VERSION 5.8 ;
BUSBITCHARS "[]" ;
DIVIDERCHAR "/" ;
UNITS
    DATABASE MICRONS 1000 ;
END UNITS

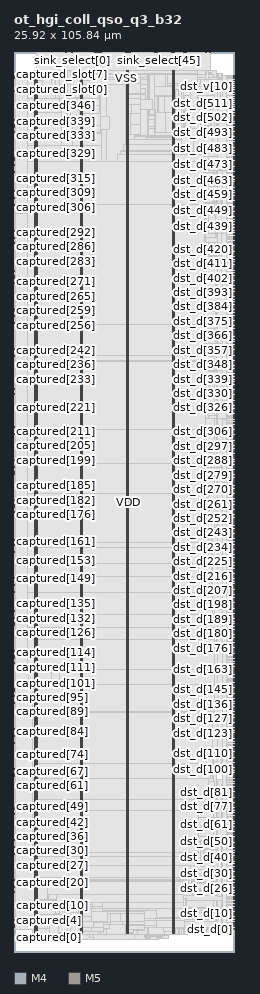
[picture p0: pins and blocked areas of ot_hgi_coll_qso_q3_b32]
MACRO ot_hgi_coll_qso_q3_b32
  FOREIGN ot_hgi_coll_qso_q3_b32 0 0 ;
  CLASS BLOCK ;
  SIZE 25.92 BY 105.84 ;
  PIN captured[0]
    DIRECTION INPUT ;
    USE SIGNAL ;
    PORT
      LAYER M4 ;
        RECT  0 2.64 0.084 2.664 ;
    END
  END captured[0]
  PIN captured[100]
    DIRECTION INPUT ;
    USE SIGNAL ;
    PORT
      LAYER M4 ;
        RECT  0 30.384 0.084 30.408 ;
    END
  END captured[100]
  PIN captured[101]
    DIRECTION INPUT ;
    USE SIGNAL ;
    PORT
      LAYER M4 ;
        RECT  0 30.672 0.084 30.696 ;
    END
  END captured[101]
  PIN captured[102]
    DIRECTION INPUT ;
    USE SIGNAL ;
    PORT
      LAYER M4 ;
        RECT  0 30.912 0.084 30.936 ;
    END
  END captured[102]
  PIN captured[103]
    DIRECTION INPUT ;
    USE SIGNAL ;
    PORT
      LAYER M4 ;
        RECT  0 31.2 0.084 31.224 ;
    END
  END captured[103]
  PIN captured[104]
    DIRECTION INPUT ;
    USE SIGNAL ;
    PORT
      LAYER M4 ;
        RECT  0 31.488 0.084 31.512 ;
    END
  END captured[104]
  PIN captured[105]
    DIRECTION INPUT ;
    USE SIGNAL ;
    PORT
      LAYER M4 ;
        RECT  0 31.776 0.084 31.8 ;
    END
  END captured[105]
  PIN captured[106]
    DIRECTION INPUT ;
    USE SIGNAL ;
    PORT
      LAYER M4 ;
        RECT  0 32.064 0.084 32.088 ;
    END
  END captured[106]
  PIN captured[107]
    DIRECTION INPUT ;
    USE SIGNAL ;
    PORT
      LAYER M4 ;
        RECT  0 32.304 0.084 32.328 ;
    END
  END captured[107]
  PIN captured[108]
    DIRECTION INPUT ;
    USE SIGNAL ;
    PORT
      LAYER M4 ;
        RECT  0 32.592 0.084 32.616 ;
    END
  END captured[108]
  PIN captured[109]
    DIRECTION INPUT ;
    USE SIGNAL ;
    PORT
      LAYER M4 ;
        RECT  0 32.88 0.084 32.904 ;
    END
  END captured[109]
  PIN captured[10]
    DIRECTION INPUT ;
    USE SIGNAL ;
    PORT
      LAYER M4 ;
        RECT  0 5.424 0.084 5.448 ;
    END
  END captured[10]
  PIN captured[110]
    DIRECTION INPUT ;
    USE SIGNAL ;
    PORT
      LAYER M4 ;
        RECT  0 33.168 0.084 33.192 ;
    END
  END captured[110]
  PIN captured[111]
    DIRECTION INPUT ;
    USE SIGNAL ;
    PORT
      LAYER M4 ;
        RECT  0 33.456 0.084 33.48 ;
    END
  END captured[111]
  PIN captured[112]
    DIRECTION INPUT ;
    USE SIGNAL ;
    PORT
      LAYER M4 ;
        RECT  0 33.696 0.084 33.72 ;
    END
  END captured[112]
  PIN captured[113]
    DIRECTION INPUT ;
    USE SIGNAL ;
    PORT
      LAYER M4 ;
        RECT  0 33.984 0.084 34.008 ;
    END
  END captured[113]
  PIN captured[114]
    DIRECTION INPUT ;
    USE SIGNAL ;
    PORT
      LAYER M4 ;
        RECT  0 34.272 0.084 34.296 ;
    END
  END captured[114]
  PIN captured[115]
    DIRECTION INPUT ;
    USE SIGNAL ;
    PORT
      LAYER M4 ;
        RECT  0 34.56 0.084 34.584 ;
    END
  END captured[115]
  PIN captured[116]
    DIRECTION INPUT ;
    USE SIGNAL ;
    PORT
      LAYER M4 ;
        RECT  0 34.8 0.084 34.824 ;
    END
  END captured[116]
  PIN captured[117]
    DIRECTION INPUT ;
    USE SIGNAL ;
    PORT
      LAYER M4 ;
        RECT  0 35.088 0.084 35.112 ;
    END
  END captured[117]
  PIN captured[118]
    DIRECTION INPUT ;
    USE SIGNAL ;
    PORT
      LAYER M4 ;
        RECT  0 35.376 0.084 35.4 ;
    END
  END captured[118]
  PIN captured[119]
    DIRECTION INPUT ;
    USE SIGNAL ;
    PORT
      LAYER M4 ;
        RECT  0 35.664 0.084 35.688 ;
    END
  END captured[119]
  PIN captured[11]
    DIRECTION INPUT ;
    USE SIGNAL ;
    PORT
      LAYER M4 ;
        RECT  0 5.664 0.084 5.688 ;
    END
  END captured[11]
  PIN captured[120]
    DIRECTION INPUT ;
    USE SIGNAL ;
    PORT
      LAYER M4 ;
        RECT  0 35.952 0.084 35.976 ;
    END
  END captured[120]
  PIN captured[121]
    DIRECTION INPUT ;
    USE SIGNAL ;
    PORT
      LAYER M4 ;
        RECT  0 36.192 0.084 36.216 ;
    END
  END captured[121]
  PIN captured[122]
    DIRECTION INPUT ;
    USE SIGNAL ;
    PORT
      LAYER M4 ;
        RECT  0 36.48 0.084 36.504 ;
    END
  END captured[122]
  PIN captured[123]
    DIRECTION INPUT ;
    USE SIGNAL ;
    PORT
      LAYER M4 ;
        RECT  0 36.768 0.084 36.792 ;
    END
  END captured[123]
  PIN captured[124]
    DIRECTION INPUT ;
    USE SIGNAL ;
    PORT
      LAYER M4 ;
        RECT  0 37.056 0.084 37.08 ;
    END
  END captured[124]
  PIN captured[125]
    DIRECTION INPUT ;
    USE SIGNAL ;
    PORT
      LAYER M4 ;
        RECT  0 37.296 0.084 37.32 ;
    END
  END captured[125]
  PIN captured[126]
    DIRECTION INPUT ;
    USE SIGNAL ;
    PORT
      LAYER M4 ;
        RECT  0 37.584 0.084 37.608 ;
    END
  END captured[126]
  PIN captured[127]
    DIRECTION INPUT ;
    USE SIGNAL ;
    PORT
      LAYER M4 ;
        RECT  0 37.872 0.084 37.896 ;
    END
  END captured[127]
  PIN captured[128]
    DIRECTION INPUT ;
    USE SIGNAL ;
    PORT
      LAYER M4 ;
        RECT  0 38.16 0.084 38.184 ;
    END
  END captured[128]
  PIN captured[129]
    DIRECTION INPUT ;
    USE SIGNAL ;
    PORT
      LAYER M4 ;
        RECT  0 38.448 0.084 38.472 ;
    END
  END captured[129]
  PIN captured[12]
    DIRECTION INPUT ;
    USE SIGNAL ;
    PORT
      LAYER M4 ;
        RECT  0 5.952 0.084 5.976 ;
    END
  END captured[12]
  PIN captured[130]
    DIRECTION INPUT ;
    USE SIGNAL ;
    PORT
      LAYER M4 ;
        RECT  0 38.688 0.084 38.712 ;
    END
  END captured[130]
  PIN captured[131]
    DIRECTION INPUT ;
    USE SIGNAL ;
    PORT
      LAYER M4 ;
        RECT  0 38.976 0.084 39 ;
    END
  END captured[131]
  PIN captured[132]
    DIRECTION INPUT ;
    USE SIGNAL ;
    PORT
      LAYER M4 ;
        RECT  0 39.264 0.084 39.288 ;
    END
  END captured[132]
  PIN captured[133]
    DIRECTION INPUT ;
    USE SIGNAL ;
    PORT
      LAYER M4 ;
        RECT  0 39.552 0.084 39.576 ;
    END
  END captured[133]
  PIN captured[134]
    DIRECTION INPUT ;
    USE SIGNAL ;
    PORT
      LAYER M4 ;
        RECT  0 39.84 0.084 39.864 ;
    END
  END captured[134]
  PIN captured[135]
    DIRECTION INPUT ;
    USE SIGNAL ;
    PORT
      LAYER M4 ;
        RECT  0 40.08 0.084 40.104 ;
    END
  END captured[135]
  PIN captured[136]
    DIRECTION INPUT ;
    USE SIGNAL ;
    PORT
      LAYER M4 ;
        RECT  0 40.368 0.084 40.392 ;
    END
  END captured[136]
  PIN captured[137]
    DIRECTION INPUT ;
    USE SIGNAL ;
    PORT
      LAYER M4 ;
        RECT  0 40.656 0.084 40.68 ;
    END
  END captured[137]
  PIN captured[138]
    DIRECTION INPUT ;
    USE SIGNAL ;
    PORT
      LAYER M4 ;
        RECT  0 40.944 0.084 40.968 ;
    END
  END captured[138]
  PIN captured[139]
    DIRECTION INPUT ;
    USE SIGNAL ;
    PORT
      LAYER M4 ;
        RECT  0 41.184 0.084 41.208 ;
    END
  END captured[139]
  PIN captured[13]
    DIRECTION INPUT ;
    USE SIGNAL ;
    PORT
      LAYER M4 ;
        RECT  0 6.24 0.084 6.264 ;
    END
  END captured[13]
  PIN captured[140]
    DIRECTION INPUT ;
    USE SIGNAL ;
    PORT
      LAYER M4 ;
        RECT  0 41.472 0.084 41.496 ;
    END
  END captured[140]
  PIN captured[141]
    DIRECTION INPUT ;
    USE SIGNAL ;
    PORT
      LAYER M4 ;
        RECT  0 41.76 0.084 41.784 ;
    END
  END captured[141]
  PIN captured[142]
    DIRECTION INPUT ;
    USE SIGNAL ;
    PORT
      LAYER M4 ;
        RECT  0 42.048 0.084 42.072 ;
    END
  END captured[142]
  PIN captured[143]
    DIRECTION INPUT ;
    USE SIGNAL ;
    PORT
      LAYER M4 ;
        RECT  0 42.336 0.084 42.36 ;
    END
  END captured[143]
  PIN captured[144]
    DIRECTION INPUT ;
    USE SIGNAL ;
    PORT
      LAYER M4 ;
        RECT  0 42.576 0.084 42.6 ;
    END
  END captured[144]
  PIN captured[145]
    DIRECTION INPUT ;
    USE SIGNAL ;
    PORT
      LAYER M4 ;
        RECT  0 42.864 0.084 42.888 ;
    END
  END captured[145]
  PIN captured[146]
    DIRECTION INPUT ;
    USE SIGNAL ;
    PORT
      LAYER M4 ;
        RECT  0 43.152 0.084 43.176 ;
    END
  END captured[146]
  PIN captured[147]
    DIRECTION INPUT ;
    USE SIGNAL ;
    PORT
      LAYER M4 ;
        RECT  0 43.44 0.084 43.464 ;
    END
  END captured[147]
  PIN captured[148]
    DIRECTION INPUT ;
    USE SIGNAL ;
    PORT
      LAYER M4 ;
        RECT  0 43.68 0.084 43.704 ;
    END
  END captured[148]
  PIN captured[149]
    DIRECTION INPUT ;
    USE SIGNAL ;
    PORT
      LAYER M4 ;
        RECT  0 43.968 0.084 43.992 ;
    END
  END captured[149]
  PIN captured[14]
    DIRECTION INPUT ;
    USE SIGNAL ;
    PORT
      LAYER M4 ;
        RECT  0 6.528 0.084 6.552 ;
    END
  END captured[14]
  PIN captured[150]
    DIRECTION INPUT ;
    USE SIGNAL ;
    PORT
      LAYER M4 ;
        RECT  0 44.256 0.084 44.28 ;
    END
  END captured[150]
  PIN captured[151]
    DIRECTION INPUT ;
    USE SIGNAL ;
    PORT
      LAYER M4 ;
        RECT  0 44.544 0.084 44.568 ;
    END
  END captured[151]
  PIN captured[152]
    DIRECTION INPUT ;
    USE SIGNAL ;
    PORT
      LAYER M4 ;
        RECT  0 44.832 0.084 44.856 ;
    END
  END captured[152]
  PIN captured[153]
    DIRECTION INPUT ;
    USE SIGNAL ;
    PORT
      LAYER M4 ;
        RECT  0 45.072 0.084 45.096 ;
    END
  END captured[153]
  PIN captured[154]
    DIRECTION INPUT ;
    USE SIGNAL ;
    PORT
      LAYER M4 ;
        RECT  0 45.36 0.084 45.384 ;
    END
  END captured[154]
  PIN captured[155]
    DIRECTION INPUT ;
    USE SIGNAL ;
    PORT
      LAYER M4 ;
        RECT  0 45.648 0.084 45.672 ;
    END
  END captured[155]
  PIN captured[156]
    DIRECTION INPUT ;
    USE SIGNAL ;
    PORT
      LAYER M4 ;
        RECT  0 45.936 0.084 45.96 ;
    END
  END captured[156]
  PIN captured[157]
    DIRECTION INPUT ;
    USE SIGNAL ;
    PORT
      LAYER M4 ;
        RECT  0 46.176 0.084 46.2 ;
    END
  END captured[157]
  PIN captured[158]
    DIRECTION INPUT ;
    USE SIGNAL ;
    PORT
      LAYER M4 ;
        RECT  0 46.464 0.084 46.488 ;
    END
  END captured[158]
  PIN captured[159]
    DIRECTION INPUT ;
    USE SIGNAL ;
    PORT
      LAYER M4 ;
        RECT  0 46.752 0.084 46.776 ;
    END
  END captured[159]
  PIN captured[15]
    DIRECTION INPUT ;
    USE SIGNAL ;
    PORT
      LAYER M4 ;
        RECT  0 6.768 0.084 6.792 ;
    END
  END captured[15]
  PIN captured[160]
    DIRECTION INPUT ;
    USE SIGNAL ;
    PORT
      LAYER M4 ;
        RECT  0 47.04 0.084 47.064 ;
    END
  END captured[160]
  PIN captured[161]
    DIRECTION INPUT ;
    USE SIGNAL ;
    PORT
      LAYER M4 ;
        RECT  0 47.328 0.084 47.352 ;
    END
  END captured[161]
  PIN captured[162]
    DIRECTION INPUT ;
    USE SIGNAL ;
    PORT
      LAYER M4 ;
        RECT  0 47.568 0.084 47.592 ;
    END
  END captured[162]
  PIN captured[163]
    DIRECTION INPUT ;
    USE SIGNAL ;
    PORT
      LAYER M4 ;
        RECT  0 47.856 0.084 47.88 ;
    END
  END captured[163]
  PIN captured[164]
    DIRECTION INPUT ;
    USE SIGNAL ;
    PORT
      LAYER M4 ;
        RECT  0 48.144 0.084 48.168 ;
    END
  END captured[164]
  PIN captured[165]
    DIRECTION INPUT ;
    USE SIGNAL ;
    PORT
      LAYER M4 ;
        RECT  0 48.432 0.084 48.456 ;
    END
  END captured[165]
  PIN captured[166]
    DIRECTION INPUT ;
    USE SIGNAL ;
    PORT
      LAYER M4 ;
        RECT  0 48.72 0.084 48.744 ;
    END
  END captured[166]
  PIN captured[167]
    DIRECTION INPUT ;
    USE SIGNAL ;
    PORT
      LAYER M4 ;
        RECT  0 48.96 0.084 48.984 ;
    END
  END captured[167]
  PIN captured[168]
    DIRECTION INPUT ;
    USE SIGNAL ;
    PORT
      LAYER M4 ;
        RECT  0 49.248 0.084 49.272 ;
    END
  END captured[168]
  PIN captured[169]
    DIRECTION INPUT ;
    USE SIGNAL ;
    PORT
      LAYER M4 ;
        RECT  0 49.536 0.084 49.56 ;
    END
  END captured[169]
  PIN captured[16]
    DIRECTION INPUT ;
    USE SIGNAL ;
    PORT
      LAYER M4 ;
        RECT  0 7.056 0.084 7.08 ;
    END
  END captured[16]
  PIN captured[170]
    DIRECTION INPUT ;
    USE SIGNAL ;
    PORT
      LAYER M4 ;
        RECT  0 49.824 0.084 49.848 ;
    END
  END captured[170]
  PIN captured[171]
    DIRECTION INPUT ;
    USE SIGNAL ;
    PORT
      LAYER M4 ;
        RECT  0 50.064 0.084 50.088 ;
    END
  END captured[171]
  PIN captured[172]
    DIRECTION INPUT ;
    USE SIGNAL ;
    PORT
      LAYER M4 ;
        RECT  0 50.352 0.084 50.376 ;
    END
  END captured[172]
  PIN captured[173]
    DIRECTION INPUT ;
    USE SIGNAL ;
    PORT
      LAYER M4 ;
        RECT  0 50.64 0.084 50.664 ;
    END
  END captured[173]
  PIN captured[174]
    DIRECTION INPUT ;
    USE SIGNAL ;
    PORT
      LAYER M4 ;
        RECT  0 50.928 0.084 50.952 ;
    END
  END captured[174]
  PIN captured[175]
    DIRECTION INPUT ;
    USE SIGNAL ;
    PORT
      LAYER M4 ;
        RECT  0 51.216 0.084 51.24 ;
    END
  END captured[175]
  PIN captured[176]
    DIRECTION INPUT ;
    USE SIGNAL ;
    PORT
      LAYER M4 ;
        RECT  0 51.456 0.084 51.48 ;
    END
  END captured[176]
  PIN captured[177]
    DIRECTION INPUT ;
    USE SIGNAL ;
    PORT
      LAYER M4 ;
        RECT  0 51.744 0.084 51.768 ;
    END
  END captured[177]
  PIN captured[178]
    DIRECTION INPUT ;
    USE SIGNAL ;
    PORT
      LAYER M4 ;
        RECT  0 52.032 0.084 52.056 ;
    END
  END captured[178]
  PIN captured[179]
    DIRECTION INPUT ;
    USE SIGNAL ;
    PORT
      LAYER M4 ;
        RECT  0 52.32 0.084 52.344 ;
    END
  END captured[179]
  PIN captured[17]
    DIRECTION INPUT ;
    USE SIGNAL ;
    PORT
      LAYER M4 ;
        RECT  0 7.344 0.084 7.368 ;
    END
  END captured[17]
  PIN captured[180]
    DIRECTION INPUT ;
    USE SIGNAL ;
    PORT
      LAYER M4 ;
        RECT  0 52.56 0.084 52.584 ;
    END
  END captured[180]
  PIN captured[181]
    DIRECTION INPUT ;
    USE SIGNAL ;
    PORT
      LAYER M4 ;
        RECT  0 52.848 0.084 52.872 ;
    END
  END captured[181]
  PIN captured[182]
    DIRECTION INPUT ;
    USE SIGNAL ;
    PORT
      LAYER M4 ;
        RECT  0 53.136 0.084 53.16 ;
    END
  END captured[182]
  PIN captured[183]
    DIRECTION INPUT ;
    USE SIGNAL ;
    PORT
      LAYER M4 ;
        RECT  0 53.424 0.084 53.448 ;
    END
  END captured[183]
  PIN captured[184]
    DIRECTION INPUT ;
    USE SIGNAL ;
    PORT
      LAYER M4 ;
        RECT  0 53.712 0.084 53.736 ;
    END
  END captured[184]
  PIN captured[185]
    DIRECTION INPUT ;
    USE SIGNAL ;
    PORT
      LAYER M4 ;
        RECT  0 53.952 0.084 53.976 ;
    END
  END captured[185]
  PIN captured[186]
    DIRECTION INPUT ;
    USE SIGNAL ;
    PORT
      LAYER M4 ;
        RECT  0 54.24 0.084 54.264 ;
    END
  END captured[186]
  PIN captured[187]
    DIRECTION INPUT ;
    USE SIGNAL ;
    PORT
      LAYER M4 ;
        RECT  0 54.528 0.084 54.552 ;
    END
  END captured[187]
  PIN captured[188]
    DIRECTION INPUT ;
    USE SIGNAL ;
    PORT
      LAYER M4 ;
        RECT  0 54.816 0.084 54.84 ;
    END
  END captured[188]
  PIN captured[189]
    DIRECTION INPUT ;
    USE SIGNAL ;
    PORT
      LAYER M4 ;
        RECT  0 55.104 0.084 55.128 ;
    END
  END captured[189]
  PIN captured[18]
    DIRECTION INPUT ;
    USE SIGNAL ;
    PORT
      LAYER M4 ;
        RECT  0 7.632 0.084 7.656 ;
    END
  END captured[18]
  PIN captured[190]
    DIRECTION INPUT ;
    USE SIGNAL ;
    PORT
      LAYER M4 ;
        RECT  0 55.344 0.084 55.368 ;
    END
  END captured[190]
  PIN captured[191]
    DIRECTION INPUT ;
    USE SIGNAL ;
    PORT
      LAYER M4 ;
        RECT  0 55.632 0.084 55.656 ;
    END
  END captured[191]
  PIN captured[192]
    DIRECTION INPUT ;
    USE SIGNAL ;
    PORT
      LAYER M4 ;
        RECT  0 55.92 0.084 55.944 ;
    END
  END captured[192]
  PIN captured[193]
    DIRECTION INPUT ;
    USE SIGNAL ;
    PORT
      LAYER M4 ;
        RECT  0 56.208 0.084 56.232 ;
    END
  END captured[193]
  PIN captured[194]
    DIRECTION INPUT ;
    USE SIGNAL ;
    PORT
      LAYER M4 ;
        RECT  0 56.448 0.084 56.472 ;
    END
  END captured[194]
  PIN captured[195]
    DIRECTION INPUT ;
    USE SIGNAL ;
    PORT
      LAYER M4 ;
        RECT  0 56.736 0.084 56.76 ;
    END
  END captured[195]
  PIN captured[196]
    DIRECTION INPUT ;
    USE SIGNAL ;
    PORT
      LAYER M4 ;
        RECT  0 57.024 0.084 57.048 ;
    END
  END captured[196]
  PIN captured[197]
    DIRECTION INPUT ;
    USE SIGNAL ;
    PORT
      LAYER M4 ;
        RECT  0 57.312 0.084 57.336 ;
    END
  END captured[197]
  PIN captured[198]
    DIRECTION INPUT ;
    USE SIGNAL ;
    PORT
      LAYER M4 ;
        RECT  0 57.6 0.084 57.624 ;
    END
  END captured[198]
  PIN captured[199]
    DIRECTION INPUT ;
    USE SIGNAL ;
    PORT
      LAYER M4 ;
        RECT  0 57.84 0.084 57.864 ;
    END
  END captured[199]
  PIN captured[19]
    DIRECTION INPUT ;
    USE SIGNAL ;
    PORT
      LAYER M4 ;
        RECT  0 7.92 0.084 7.944 ;
    END
  END captured[19]
  PIN captured[1]
    DIRECTION INPUT ;
    USE SIGNAL ;
    PORT
      LAYER M4 ;
        RECT  0 2.928 0.084 2.952 ;
    END
  END captured[1]
  PIN captured[200]
    DIRECTION INPUT ;
    USE SIGNAL ;
    PORT
      LAYER M4 ;
        RECT  0 58.128 0.084 58.152 ;
    END
  END captured[200]
  PIN captured[201]
    DIRECTION INPUT ;
    USE SIGNAL ;
    PORT
      LAYER M4 ;
        RECT  0 58.416 0.084 58.44 ;
    END
  END captured[201]
  PIN captured[202]
    DIRECTION INPUT ;
    USE SIGNAL ;
    PORT
      LAYER M4 ;
        RECT  0 58.704 0.084 58.728 ;
    END
  END captured[202]
  PIN captured[203]
    DIRECTION INPUT ;
    USE SIGNAL ;
    PORT
      LAYER M4 ;
        RECT  0 58.944 0.084 58.968 ;
    END
  END captured[203]
  PIN captured[204]
    DIRECTION INPUT ;
    USE SIGNAL ;
    PORT
      LAYER M4 ;
        RECT  0 59.232 0.084 59.256 ;
    END
  END captured[204]
  PIN captured[205]
    DIRECTION INPUT ;
    USE SIGNAL ;
    PORT
      LAYER M4 ;
        RECT  0 59.52 0.084 59.544 ;
    END
  END captured[205]
  PIN captured[206]
    DIRECTION INPUT ;
    USE SIGNAL ;
    PORT
      LAYER M4 ;
        RECT  0 59.808 0.084 59.832 ;
    END
  END captured[206]
  PIN captured[207]
    DIRECTION INPUT ;
    USE SIGNAL ;
    PORT
      LAYER M4 ;
        RECT  0 60.096 0.084 60.12 ;
    END
  END captured[207]
  PIN captured[208]
    DIRECTION INPUT ;
    USE SIGNAL ;
    PORT
      LAYER M4 ;
        RECT  0 60.336 0.084 60.36 ;
    END
  END captured[208]
  PIN captured[209]
    DIRECTION INPUT ;
    USE SIGNAL ;
    PORT
      LAYER M4 ;
        RECT  0 60.624 0.084 60.648 ;
    END
  END captured[209]
  PIN captured[20]
    DIRECTION INPUT ;
    USE SIGNAL ;
    PORT
      LAYER M4 ;
        RECT  0 8.16 0.084 8.184 ;
    END
  END captured[20]
  PIN captured[210]
    DIRECTION INPUT ;
    USE SIGNAL ;
    PORT
      LAYER M4 ;
        RECT  0 60.912 0.084 60.936 ;
    END
  END captured[210]
  PIN captured[211]
    DIRECTION INPUT ;
    USE SIGNAL ;
    PORT
      LAYER M4 ;
        RECT  0 61.2 0.084 61.224 ;
    END
  END captured[211]
  PIN captured[212]
    DIRECTION INPUT ;
    USE SIGNAL ;
    PORT
      LAYER M4 ;
        RECT  0 61.44 0.084 61.464 ;
    END
  END captured[212]
  PIN captured[213]
    DIRECTION INPUT ;
    USE SIGNAL ;
    PORT
      LAYER M4 ;
        RECT  0 61.728 0.084 61.752 ;
    END
  END captured[213]
  PIN captured[214]
    DIRECTION INPUT ;
    USE SIGNAL ;
    PORT
      LAYER M4 ;
        RECT  0 62.016 0.084 62.04 ;
    END
  END captured[214]
  PIN captured[215]
    DIRECTION INPUT ;
    USE SIGNAL ;
    PORT
      LAYER M4 ;
        RECT  0 62.304 0.084 62.328 ;
    END
  END captured[215]
  PIN captured[216]
    DIRECTION INPUT ;
    USE SIGNAL ;
    PORT
      LAYER M4 ;
        RECT  0 62.592 0.084 62.616 ;
    END
  END captured[216]
  PIN captured[217]
    DIRECTION INPUT ;
    USE SIGNAL ;
    PORT
      LAYER M4 ;
        RECT  0 62.832 0.084 62.856 ;
    END
  END captured[217]
  PIN captured[218]
    DIRECTION INPUT ;
    USE SIGNAL ;
    PORT
      LAYER M4 ;
        RECT  0 63.12 0.084 63.144 ;
    END
  END captured[218]
  PIN captured[219]
    DIRECTION INPUT ;
    USE SIGNAL ;
    PORT
      LAYER M4 ;
        RECT  0 63.408 0.084 63.432 ;
    END
  END captured[219]
  PIN captured[21]
    DIRECTION INPUT ;
    USE SIGNAL ;
    PORT
      LAYER M4 ;
        RECT  0 8.448 0.084 8.472 ;
    END
  END captured[21]
  PIN captured[220]
    DIRECTION INPUT ;
    USE SIGNAL ;
    PORT
      LAYER M4 ;
        RECT  0 63.696 0.084 63.72 ;
    END
  END captured[220]
  PIN captured[221]
    DIRECTION INPUT ;
    USE SIGNAL ;
    PORT
      LAYER M4 ;
        RECT  0 63.984 0.084 64.008 ;
    END
  END captured[221]
  PIN captured[222]
    DIRECTION INPUT ;
    USE SIGNAL ;
    PORT
      LAYER M4 ;
        RECT  0 64.224 0.084 64.248 ;
    END
  END captured[222]
  PIN captured[223]
    DIRECTION INPUT ;
    USE SIGNAL ;
    PORT
      LAYER M4 ;
        RECT  0 64.512 0.084 64.536 ;
    END
  END captured[223]
  PIN captured[224]
    DIRECTION INPUT ;
    USE SIGNAL ;
    PORT
      LAYER M4 ;
        RECT  0 64.8 0.084 64.824 ;
    END
  END captured[224]
  PIN captured[225]
    DIRECTION INPUT ;
    USE SIGNAL ;
    PORT
      LAYER M4 ;
        RECT  0 65.088 0.084 65.112 ;
    END
  END captured[225]
  PIN captured[226]
    DIRECTION INPUT ;
    USE SIGNAL ;
    PORT
      LAYER M4 ;
        RECT  0 65.328 0.084 65.352 ;
    END
  END captured[226]
  PIN captured[227]
    DIRECTION INPUT ;
    USE SIGNAL ;
    PORT
      LAYER M4 ;
        RECT  0 65.616 0.084 65.64 ;
    END
  END captured[227]
  PIN captured[228]
    DIRECTION INPUT ;
    USE SIGNAL ;
    PORT
      LAYER M4 ;
        RECT  0 65.904 0.084 65.928 ;
    END
  END captured[228]
  PIN captured[229]
    DIRECTION INPUT ;
    USE SIGNAL ;
    PORT
      LAYER M4 ;
        RECT  0 66.192 0.084 66.216 ;
    END
  END captured[229]
  PIN captured[22]
    DIRECTION INPUT ;
    USE SIGNAL ;
    PORT
      LAYER M4 ;
        RECT  0 8.736 0.084 8.76 ;
    END
  END captured[22]
  PIN captured[230]
    DIRECTION INPUT ;
    USE SIGNAL ;
    PORT
      LAYER M4 ;
        RECT  0 66.48 0.084 66.504 ;
    END
  END captured[230]
  PIN captured[231]
    DIRECTION INPUT ;
    USE SIGNAL ;
    PORT
      LAYER M4 ;
        RECT  0 66.72 0.084 66.744 ;
    END
  END captured[231]
  PIN captured[232]
    DIRECTION INPUT ;
    USE SIGNAL ;
    PORT
      LAYER M4 ;
        RECT  0 67.008 0.084 67.032 ;
    END
  END captured[232]
  PIN captured[233]
    DIRECTION INPUT ;
    USE SIGNAL ;
    PORT
      LAYER M4 ;
        RECT  0 67.296 0.084 67.32 ;
    END
  END captured[233]
  PIN captured[234]
    DIRECTION INPUT ;
    USE SIGNAL ;
    PORT
      LAYER M4 ;
        RECT  0 67.584 0.084 67.608 ;
    END
  END captured[234]
  PIN captured[235]
    DIRECTION INPUT ;
    USE SIGNAL ;
    PORT
      LAYER M4 ;
        RECT  0 67.824 0.084 67.848 ;
    END
  END captured[235]
  PIN captured[236]
    DIRECTION INPUT ;
    USE SIGNAL ;
    PORT
      LAYER M4 ;
        RECT  0 68.112 0.084 68.136 ;
    END
  END captured[236]
  PIN captured[237]
    DIRECTION INPUT ;
    USE SIGNAL ;
    PORT
      LAYER M4 ;
        RECT  0 68.4 0.084 68.424 ;
    END
  END captured[237]
  PIN captured[238]
    DIRECTION INPUT ;
    USE SIGNAL ;
    PORT
      LAYER M4 ;
        RECT  0 68.688 0.084 68.712 ;
    END
  END captured[238]
  PIN captured[239]
    DIRECTION INPUT ;
    USE SIGNAL ;
    PORT
      LAYER M4 ;
        RECT  0 68.976 0.084 69 ;
    END
  END captured[239]
  PIN captured[23]
    DIRECTION INPUT ;
    USE SIGNAL ;
    PORT
      LAYER M4 ;
        RECT  0 9.024 0.084 9.048 ;
    END
  END captured[23]
  PIN captured[240]
    DIRECTION INPUT ;
    USE SIGNAL ;
    PORT
      LAYER M4 ;
        RECT  0 69.216 0.084 69.24 ;
    END
  END captured[240]
  PIN captured[241]
    DIRECTION INPUT ;
    USE SIGNAL ;
    PORT
      LAYER M4 ;
        RECT  0 69.504 0.084 69.528 ;
    END
  END captured[241]
  PIN captured[242]
    DIRECTION INPUT ;
    USE SIGNAL ;
    PORT
      LAYER M4 ;
        RECT  0 69.792 0.084 69.816 ;
    END
  END captured[242]
  PIN captured[243]
    DIRECTION INPUT ;
    USE SIGNAL ;
    PORT
      LAYER M4 ;
        RECT  0 70.08 0.084 70.104 ;
    END
  END captured[243]
  PIN captured[244]
    DIRECTION INPUT ;
    USE SIGNAL ;
    PORT
      LAYER M4 ;
        RECT  0 70.368 0.084 70.392 ;
    END
  END captured[244]
  PIN captured[245]
    DIRECTION INPUT ;
    USE SIGNAL ;
    PORT
      LAYER M4 ;
        RECT  0 70.608 0.084 70.632 ;
    END
  END captured[245]
  PIN captured[246]
    DIRECTION INPUT ;
    USE SIGNAL ;
    PORT
      LAYER M4 ;
        RECT  0 70.896 0.084 70.92 ;
    END
  END captured[246]
  PIN captured[247]
    DIRECTION INPUT ;
    USE SIGNAL ;
    PORT
      LAYER M4 ;
        RECT  0 71.184 0.084 71.208 ;
    END
  END captured[247]
  PIN captured[248]
    DIRECTION INPUT ;
    USE SIGNAL ;
    PORT
      LAYER M4 ;
        RECT  0 71.472 0.084 71.496 ;
    END
  END captured[248]
  PIN captured[249]
    DIRECTION INPUT ;
    USE SIGNAL ;
    PORT
      LAYER M4 ;
        RECT  0 71.712 0.084 71.736 ;
    END
  END captured[249]
  PIN captured[24]
    DIRECTION INPUT ;
    USE SIGNAL ;
    PORT
      LAYER M4 ;
        RECT  0 9.264 0.084 9.288 ;
    END
  END captured[24]
  PIN captured[250]
    DIRECTION INPUT ;
    USE SIGNAL ;
    PORT
      LAYER M4 ;
        RECT  0 72 0.084 72.024 ;
    END
  END captured[250]
  PIN captured[251]
    DIRECTION INPUT ;
    USE SIGNAL ;
    PORT
      LAYER M4 ;
        RECT  0 72.288 0.084 72.312 ;
    END
  END captured[251]
  PIN captured[252]
    DIRECTION INPUT ;
    USE SIGNAL ;
    PORT
      LAYER M4 ;
        RECT  0 72.576 0.084 72.6 ;
    END
  END captured[252]
  PIN captured[253]
    DIRECTION INPUT ;
    USE SIGNAL ;
    PORT
      LAYER M4 ;
        RECT  0 72.864 0.084 72.888 ;
    END
  END captured[253]
  PIN captured[254]
    DIRECTION INPUT ;
    USE SIGNAL ;
    PORT
      LAYER M4 ;
        RECT  0 73.104 0.084 73.128 ;
    END
  END captured[254]
  PIN captured[255]
    DIRECTION INPUT ;
    USE SIGNAL ;
    PORT
      LAYER M4 ;
        RECT  0 73.392 0.084 73.416 ;
    END
  END captured[255]
  PIN captured[256]
    DIRECTION INPUT ;
    USE SIGNAL ;
    PORT
      LAYER M4 ;
        RECT  0 73.68 0.084 73.704 ;
    END
  END captured[256]
  PIN captured[257]
    DIRECTION INPUT ;
    USE SIGNAL ;
    PORT
      LAYER M4 ;
        RECT  0 73.968 0.084 73.992 ;
    END
  END captured[257]
  PIN captured[258]
    DIRECTION INPUT ;
    USE SIGNAL ;
    PORT
      LAYER M4 ;
        RECT  0 74.208 0.084 74.232 ;
    END
  END captured[258]
  PIN captured[259]
    DIRECTION INPUT ;
    USE SIGNAL ;
    PORT
      LAYER M4 ;
        RECT  0 74.496 0.084 74.52 ;
    END
  END captured[259]
  PIN captured[25]
    DIRECTION INPUT ;
    USE SIGNAL ;
    PORT
      LAYER M4 ;
        RECT  0 9.552 0.084 9.576 ;
    END
  END captured[25]
  PIN captured[260]
    DIRECTION INPUT ;
    USE SIGNAL ;
    PORT
      LAYER M4 ;
        RECT  0 74.784 0.084 74.808 ;
    END
  END captured[260]
  PIN captured[261]
    DIRECTION INPUT ;
    USE SIGNAL ;
    PORT
      LAYER M4 ;
        RECT  0 75.072 0.084 75.096 ;
    END
  END captured[261]
  PIN captured[262]
    DIRECTION INPUT ;
    USE SIGNAL ;
    PORT
      LAYER M4 ;
        RECT  0 75.36 0.084 75.384 ;
    END
  END captured[262]
  PIN captured[263]
    DIRECTION INPUT ;
    USE SIGNAL ;
    PORT
      LAYER M4 ;
        RECT  0 75.6 0.084 75.624 ;
    END
  END captured[263]
  PIN captured[264]
    DIRECTION INPUT ;
    USE SIGNAL ;
    PORT
      LAYER M4 ;
        RECT  0 75.888 0.084 75.912 ;
    END
  END captured[264]
  PIN captured[265]
    DIRECTION INPUT ;
    USE SIGNAL ;
    PORT
      LAYER M4 ;
        RECT  0 76.176 0.084 76.2 ;
    END
  END captured[265]
  PIN captured[266]
    DIRECTION INPUT ;
    USE SIGNAL ;
    PORT
      LAYER M4 ;
        RECT  0 76.464 0.084 76.488 ;
    END
  END captured[266]
  PIN captured[267]
    DIRECTION INPUT ;
    USE SIGNAL ;
    PORT
      LAYER M4 ;
        RECT  0 76.704 0.084 76.728 ;
    END
  END captured[267]
  PIN captured[268]
    DIRECTION INPUT ;
    USE SIGNAL ;
    PORT
      LAYER M4 ;
        RECT  0 76.992 0.084 77.016 ;
    END
  END captured[268]
  PIN captured[269]
    DIRECTION INPUT ;
    USE SIGNAL ;
    PORT
      LAYER M4 ;
        RECT  0 77.28 0.084 77.304 ;
    END
  END captured[269]
  PIN captured[26]
    DIRECTION INPUT ;
    USE SIGNAL ;
    PORT
      LAYER M4 ;
        RECT  0 9.84 0.084 9.864 ;
    END
  END captured[26]
  PIN captured[270]
    DIRECTION INPUT ;
    USE SIGNAL ;
    PORT
      LAYER M4 ;
        RECT  0 77.568 0.084 77.592 ;
    END
  END captured[270]
  PIN captured[271]
    DIRECTION INPUT ;
    USE SIGNAL ;
    PORT
      LAYER M4 ;
        RECT  0 77.856 0.084 77.88 ;
    END
  END captured[271]
  PIN captured[272]
    DIRECTION INPUT ;
    USE SIGNAL ;
    PORT
      LAYER M4 ;
        RECT  0 78.096 0.084 78.12 ;
    END
  END captured[272]
  PIN captured[273]
    DIRECTION INPUT ;
    USE SIGNAL ;
    PORT
      LAYER M4 ;
        RECT  0 78.384 0.084 78.408 ;
    END
  END captured[273]
  PIN captured[274]
    DIRECTION INPUT ;
    USE SIGNAL ;
    PORT
      LAYER M4 ;
        RECT  0 78.672 0.084 78.696 ;
    END
  END captured[274]
  PIN captured[275]
    DIRECTION INPUT ;
    USE SIGNAL ;
    PORT
      LAYER M4 ;
        RECT  0 78.96 0.084 78.984 ;
    END
  END captured[275]
  PIN captured[276]
    DIRECTION INPUT ;
    USE SIGNAL ;
    PORT
      LAYER M4 ;
        RECT  0 79.248 0.084 79.272 ;
    END
  END captured[276]
  PIN captured[277]
    DIRECTION INPUT ;
    USE SIGNAL ;
    PORT
      LAYER M4 ;
        RECT  0 79.488 0.084 79.512 ;
    END
  END captured[277]
  PIN captured[278]
    DIRECTION INPUT ;
    USE SIGNAL ;
    PORT
      LAYER M4 ;
        RECT  0 79.776 0.084 79.8 ;
    END
  END captured[278]
  PIN captured[279]
    DIRECTION INPUT ;
    USE SIGNAL ;
    PORT
      LAYER M4 ;
        RECT  0 80.064 0.084 80.088 ;
    END
  END captured[279]
  PIN captured[27]
    DIRECTION INPUT ;
    USE SIGNAL ;
    PORT
      LAYER M4 ;
        RECT  0 10.128 0.084 10.152 ;
    END
  END captured[27]
  PIN captured[280]
    DIRECTION INPUT ;
    USE SIGNAL ;
    PORT
      LAYER M4 ;
        RECT  0 80.352 0.084 80.376 ;
    END
  END captured[280]
  PIN captured[281]
    DIRECTION INPUT ;
    USE SIGNAL ;
    PORT
      LAYER M4 ;
        RECT  0 80.592 0.084 80.616 ;
    END
  END captured[281]
  PIN captured[282]
    DIRECTION INPUT ;
    USE SIGNAL ;
    PORT
      LAYER M4 ;
        RECT  0 80.88 0.084 80.904 ;
    END
  END captured[282]
  PIN captured[283]
    DIRECTION INPUT ;
    USE SIGNAL ;
    PORT
      LAYER M4 ;
        RECT  0 81.168 0.084 81.192 ;
    END
  END captured[283]
  PIN captured[284]
    DIRECTION INPUT ;
    USE SIGNAL ;
    PORT
      LAYER M4 ;
        RECT  0 81.456 0.084 81.48 ;
    END
  END captured[284]
  PIN captured[285]
    DIRECTION INPUT ;
    USE SIGNAL ;
    PORT
      LAYER M4 ;
        RECT  0 81.744 0.084 81.768 ;
    END
  END captured[285]
  PIN captured[286]
    DIRECTION INPUT ;
    USE SIGNAL ;
    PORT
      LAYER M4 ;
        RECT  0 81.984 0.084 82.008 ;
    END
  END captured[286]
  PIN captured[287]
    DIRECTION INPUT ;
    USE SIGNAL ;
    PORT
      LAYER M4 ;
        RECT  0 82.272 0.084 82.296 ;
    END
  END captured[287]
  PIN captured[288]
    DIRECTION INPUT ;
    USE SIGNAL ;
    PORT
      LAYER M4 ;
        RECT  0 82.56 0.084 82.584 ;
    END
  END captured[288]
  PIN captured[289]
    DIRECTION INPUT ;
    USE SIGNAL ;
    PORT
      LAYER M4 ;
        RECT  0 82.848 0.084 82.872 ;
    END
  END captured[289]
  PIN captured[28]
    DIRECTION INPUT ;
    USE SIGNAL ;
    PORT
      LAYER M4 ;
        RECT  0 10.416 0.084 10.44 ;
    END
  END captured[28]
  PIN captured[290]
    DIRECTION INPUT ;
    USE SIGNAL ;
    PORT
      LAYER M4 ;
        RECT  0 83.088 0.084 83.112 ;
    END
  END captured[290]
  PIN captured[291]
    DIRECTION INPUT ;
    USE SIGNAL ;
    PORT
      LAYER M4 ;
        RECT  0 83.376 0.084 83.4 ;
    END
  END captured[291]
  PIN captured[292]
    DIRECTION INPUT ;
    USE SIGNAL ;
    PORT
      LAYER M4 ;
        RECT  0 83.664 0.084 83.688 ;
    END
  END captured[292]
  PIN captured[293]
    DIRECTION INPUT ;
    USE SIGNAL ;
    PORT
      LAYER M4 ;
        RECT  0 83.952 0.084 83.976 ;
    END
  END captured[293]
  PIN captured[294]
    DIRECTION INPUT ;
    USE SIGNAL ;
    PORT
      LAYER M4 ;
        RECT  0 84.24 0.084 84.264 ;
    END
  END captured[294]
  PIN captured[295]
    DIRECTION INPUT ;
    USE SIGNAL ;
    PORT
      LAYER M4 ;
        RECT  0 84.48 0.084 84.504 ;
    END
  END captured[295]
  PIN captured[296]
    DIRECTION INPUT ;
    USE SIGNAL ;
    PORT
      LAYER M4 ;
        RECT  0 84.768 0.084 84.792 ;
    END
  END captured[296]
  PIN captured[297]
    DIRECTION INPUT ;
    USE SIGNAL ;
    PORT
      LAYER M4 ;
        RECT  0 85.056 0.084 85.08 ;
    END
  END captured[297]
  PIN captured[298]
    DIRECTION INPUT ;
    USE SIGNAL ;
    PORT
      LAYER M4 ;
        RECT  0 85.344 0.084 85.368 ;
    END
  END captured[298]
  PIN captured[299]
    DIRECTION INPUT ;
    USE SIGNAL ;
    PORT
      LAYER M4 ;
        RECT  0 85.632 0.084 85.656 ;
    END
  END captured[299]
  PIN captured[29]
    DIRECTION INPUT ;
    USE SIGNAL ;
    PORT
      LAYER M4 ;
        RECT  0 10.656 0.084 10.68 ;
    END
  END captured[29]
  PIN captured[2]
    DIRECTION INPUT ;
    USE SIGNAL ;
    PORT
      LAYER M4 ;
        RECT  0 3.168 0.084 3.192 ;
    END
  END captured[2]
  PIN captured[300]
    DIRECTION INPUT ;
    USE SIGNAL ;
    PORT
      LAYER M4 ;
        RECT  0 85.872 0.084 85.896 ;
    END
  END captured[300]
  PIN captured[301]
    DIRECTION INPUT ;
    USE SIGNAL ;
    PORT
      LAYER M4 ;
        RECT  0 86.16 0.084 86.184 ;
    END
  END captured[301]
  PIN captured[302]
    DIRECTION INPUT ;
    USE SIGNAL ;
    PORT
      LAYER M4 ;
        RECT  0 86.448 0.084 86.472 ;
    END
  END captured[302]
  PIN captured[303]
    DIRECTION INPUT ;
    USE SIGNAL ;
    PORT
      LAYER M4 ;
        RECT  0 86.736 0.084 86.76 ;
    END
  END captured[303]
  PIN captured[304]
    DIRECTION INPUT ;
    USE SIGNAL ;
    PORT
      LAYER M4 ;
        RECT  0 86.976 0.084 87 ;
    END
  END captured[304]
  PIN captured[305]
    DIRECTION INPUT ;
    USE SIGNAL ;
    PORT
      LAYER M4 ;
        RECT  0 87.264 0.084 87.288 ;
    END
  END captured[305]
  PIN captured[306]
    DIRECTION INPUT ;
    USE SIGNAL ;
    PORT
      LAYER M4 ;
        RECT  0 87.552 0.084 87.576 ;
    END
  END captured[306]
  PIN captured[307]
    DIRECTION INPUT ;
    USE SIGNAL ;
    PORT
      LAYER M4 ;
        RECT  0 87.84 0.084 87.864 ;
    END
  END captured[307]
  PIN captured[308]
    DIRECTION INPUT ;
    USE SIGNAL ;
    PORT
      LAYER M4 ;
        RECT  0 88.128 0.084 88.152 ;
    END
  END captured[308]
  PIN captured[309]
    DIRECTION INPUT ;
    USE SIGNAL ;
    PORT
      LAYER M4 ;
        RECT  0 88.368 0.084 88.392 ;
    END
  END captured[309]
  PIN captured[30]
    DIRECTION INPUT ;
    USE SIGNAL ;
    PORT
      LAYER M4 ;
        RECT  0 10.944 0.084 10.968 ;
    END
  END captured[30]
  PIN captured[310]
    DIRECTION INPUT ;
    USE SIGNAL ;
    PORT
      LAYER M4 ;
        RECT  0 88.656 0.084 88.68 ;
    END
  END captured[310]
  PIN captured[311]
    DIRECTION INPUT ;
    USE SIGNAL ;
    PORT
      LAYER M4 ;
        RECT  0 88.944 0.084 88.968 ;
    END
  END captured[311]
  PIN captured[312]
    DIRECTION INPUT ;
    USE SIGNAL ;
    PORT
      LAYER M4 ;
        RECT  0 89.232 0.084 89.256 ;
    END
  END captured[312]
  PIN captured[313]
    DIRECTION INPUT ;
    USE SIGNAL ;
    PORT
      LAYER M4 ;
        RECT  0 89.472 0.084 89.496 ;
    END
  END captured[313]
  PIN captured[314]
    DIRECTION INPUT ;
    USE SIGNAL ;
    PORT
      LAYER M4 ;
        RECT  0 89.76 0.084 89.784 ;
    END
  END captured[314]
  PIN captured[315]
    DIRECTION INPUT ;
    USE SIGNAL ;
    PORT
      LAYER M4 ;
        RECT  0 90.048 0.084 90.072 ;
    END
  END captured[315]
  PIN captured[316]
    DIRECTION INPUT ;
    USE SIGNAL ;
    PORT
      LAYER M4 ;
        RECT  0 90.336 0.084 90.36 ;
    END
  END captured[316]
  PIN captured[317]
    DIRECTION INPUT ;
    USE SIGNAL ;
    PORT
      LAYER M4 ;
        RECT  0 90.624 0.084 90.648 ;
    END
  END captured[317]
  PIN captured[318]
    DIRECTION INPUT ;
    USE SIGNAL ;
    PORT
      LAYER M4 ;
        RECT  0 90.864 0.084 90.888 ;
    END
  END captured[318]
  PIN captured[319]
    DIRECTION INPUT ;
    USE SIGNAL ;
    PORT
      LAYER M4 ;
        RECT  0 91.152 0.084 91.176 ;
    END
  END captured[319]
  PIN captured[31]
    DIRECTION INPUT ;
    USE SIGNAL ;
    PORT
      LAYER M4 ;
        RECT  0 11.232 0.084 11.256 ;
    END
  END captured[31]
  PIN captured[320]
    DIRECTION INPUT ;
    USE SIGNAL ;
    PORT
      LAYER M4 ;
        RECT  0 91.44 0.084 91.464 ;
    END
  END captured[320]
  PIN captured[321]
    DIRECTION INPUT ;
    USE SIGNAL ;
    PORT
      LAYER M4 ;
        RECT  0 91.728 0.084 91.752 ;
    END
  END captured[321]
  PIN captured[322]
    DIRECTION INPUT ;
    USE SIGNAL ;
    PORT
      LAYER M4 ;
        RECT  0 91.968 0.084 91.992 ;
    END
  END captured[322]
  PIN captured[323]
    DIRECTION INPUT ;
    USE SIGNAL ;
    PORT
      LAYER M4 ;
        RECT  0 92.256 0.084 92.28 ;
    END
  END captured[323]
  PIN captured[324]
    DIRECTION INPUT ;
    USE SIGNAL ;
    PORT
      LAYER M4 ;
        RECT  0 92.544 0.084 92.568 ;
    END
  END captured[324]
  PIN captured[325]
    DIRECTION INPUT ;
    USE SIGNAL ;
    PORT
      LAYER M4 ;
        RECT  0 92.832 0.084 92.856 ;
    END
  END captured[325]
  PIN captured[326]
    DIRECTION INPUT ;
    USE SIGNAL ;
    PORT
      LAYER M4 ;
        RECT  0 93.12 0.084 93.144 ;
    END
  END captured[326]
  PIN captured[327]
    DIRECTION INPUT ;
    USE SIGNAL ;
    PORT
      LAYER M4 ;
        RECT  0 93.36 0.084 93.384 ;
    END
  END captured[327]
  PIN captured[328]
    DIRECTION INPUT ;
    USE SIGNAL ;
    PORT
      LAYER M4 ;
        RECT  0 93.648 0.084 93.672 ;
    END
  END captured[328]
  PIN captured[329]
    DIRECTION INPUT ;
    USE SIGNAL ;
    PORT
      LAYER M4 ;
        RECT  0 93.936 0.084 93.96 ;
    END
  END captured[329]
  PIN captured[32]
    DIRECTION INPUT ;
    USE SIGNAL ;
    PORT
      LAYER M4 ;
        RECT  0 11.52 0.084 11.544 ;
    END
  END captured[32]
  PIN captured[330]
    DIRECTION INPUT ;
    USE SIGNAL ;
    PORT
      LAYER M4 ;
        RECT  0 94.224 0.084 94.248 ;
    END
  END captured[330]
  PIN captured[331]
    DIRECTION INPUT ;
    USE SIGNAL ;
    PORT
      LAYER M4 ;
        RECT  0 94.512 0.084 94.536 ;
    END
  END captured[331]
  PIN captured[332]
    DIRECTION INPUT ;
    USE SIGNAL ;
    PORT
      LAYER M4 ;
        RECT  0 94.752 0.084 94.776 ;
    END
  END captured[332]
  PIN captured[333]
    DIRECTION INPUT ;
    USE SIGNAL ;
    PORT
      LAYER M4 ;
        RECT  0 95.04 0.084 95.064 ;
    END
  END captured[333]
  PIN captured[334]
    DIRECTION INPUT ;
    USE SIGNAL ;
    PORT
      LAYER M4 ;
        RECT  0 95.328 0.084 95.352 ;
    END
  END captured[334]
  PIN captured[335]
    DIRECTION INPUT ;
    USE SIGNAL ;
    PORT
      LAYER M4 ;
        RECT  0 95.616 0.084 95.64 ;
    END
  END captured[335]
  PIN captured[336]
    DIRECTION INPUT ;
    USE SIGNAL ;
    PORT
      LAYER M4 ;
        RECT  0 95.856 0.084 95.88 ;
    END
  END captured[336]
  PIN captured[337]
    DIRECTION INPUT ;
    USE SIGNAL ;
    PORT
      LAYER M4 ;
        RECT  0 96.144 0.084 96.168 ;
    END
  END captured[337]
  PIN captured[338]
    DIRECTION INPUT ;
    USE SIGNAL ;
    PORT
      LAYER M4 ;
        RECT  0 96.432 0.084 96.456 ;
    END
  END captured[338]
  PIN captured[339]
    DIRECTION INPUT ;
    USE SIGNAL ;
    PORT
      LAYER M4 ;
        RECT  0 96.72 0.084 96.744 ;
    END
  END captured[339]
  PIN captured[33]
    DIRECTION INPUT ;
    USE SIGNAL ;
    PORT
      LAYER M4 ;
        RECT  0 11.808 0.084 11.832 ;
    END
  END captured[33]
  PIN captured[340]
    DIRECTION INPUT ;
    USE SIGNAL ;
    PORT
      LAYER M4 ;
        RECT  0 97.008 0.084 97.032 ;
    END
  END captured[340]
  PIN captured[341]
    DIRECTION INPUT ;
    USE SIGNAL ;
    PORT
      LAYER M4 ;
        RECT  0 97.248 0.084 97.272 ;
    END
  END captured[341]
  PIN captured[342]
    DIRECTION INPUT ;
    USE SIGNAL ;
    PORT
      LAYER M4 ;
        RECT  0 97.536 0.084 97.56 ;
    END
  END captured[342]
  PIN captured[343]
    DIRECTION INPUT ;
    USE SIGNAL ;
    PORT
      LAYER M4 ;
        RECT  0 97.824 0.084 97.848 ;
    END
  END captured[343]
  PIN captured[344]
    DIRECTION INPUT ;
    USE SIGNAL ;
    PORT
      LAYER M4 ;
        RECT  0 98.112 0.084 98.136 ;
    END
  END captured[344]
  PIN captured[345]
    DIRECTION INPUT ;
    USE SIGNAL ;
    PORT
      LAYER M4 ;
        RECT  0 98.352 0.084 98.376 ;
    END
  END captured[345]
  PIN captured[346]
    DIRECTION INPUT ;
    USE SIGNAL ;
    PORT
      LAYER M4 ;
        RECT  0 98.64 0.084 98.664 ;
    END
  END captured[346]
  PIN captured[347]
    DIRECTION INPUT ;
    USE SIGNAL ;
    PORT
      LAYER M4 ;
        RECT  0 98.928 0.084 98.952 ;
    END
  END captured[347]
  PIN captured[348]
    DIRECTION INPUT ;
    USE SIGNAL ;
    PORT
      LAYER M4 ;
        RECT  0 99.216 0.084 99.24 ;
    END
  END captured[348]
  PIN captured[349]
    DIRECTION INPUT ;
    USE SIGNAL ;
    PORT
      LAYER M4 ;
        RECT  0 99.504 0.084 99.528 ;
    END
  END captured[349]
  PIN captured[34]
    DIRECTION INPUT ;
    USE SIGNAL ;
    PORT
      LAYER M4 ;
        RECT  0 12.048 0.084 12.072 ;
    END
  END captured[34]
  PIN captured[350]
    DIRECTION INPUT ;
    USE SIGNAL ;
    PORT
      LAYER M4 ;
        RECT  0 99.744 0.084 99.768 ;
    END
  END captured[350]
  PIN captured[351]
    DIRECTION INPUT ;
    USE SIGNAL ;
    PORT
      LAYER M4 ;
        RECT  0 100.032 0.084 100.056 ;
    END
  END captured[351]
  PIN captured[35]
    DIRECTION INPUT ;
    USE SIGNAL ;
    PORT
      LAYER M4 ;
        RECT  0 12.336 0.084 12.36 ;
    END
  END captured[35]
  PIN captured[36]
    DIRECTION INPUT ;
    USE SIGNAL ;
    PORT
      LAYER M4 ;
        RECT  0 12.624 0.084 12.648 ;
    END
  END captured[36]
  PIN captured[37]
    DIRECTION INPUT ;
    USE SIGNAL ;
    PORT
      LAYER M4 ;
        RECT  0 12.912 0.084 12.936 ;
    END
  END captured[37]
  PIN captured[38]
    DIRECTION INPUT ;
    USE SIGNAL ;
    PORT
      LAYER M4 ;
        RECT  0 13.152 0.084 13.176 ;
    END
  END captured[38]
  PIN captured[39]
    DIRECTION INPUT ;
    USE SIGNAL ;
    PORT
      LAYER M4 ;
        RECT  0 13.44 0.084 13.464 ;
    END
  END captured[39]
  PIN captured[3]
    DIRECTION INPUT ;
    USE SIGNAL ;
    PORT
      LAYER M4 ;
        RECT  0 3.456 0.084 3.48 ;
    END
  END captured[3]
  PIN captured[40]
    DIRECTION INPUT ;
    USE SIGNAL ;
    PORT
      LAYER M4 ;
        RECT  0 13.728 0.084 13.752 ;
    END
  END captured[40]
  PIN captured[41]
    DIRECTION INPUT ;
    USE SIGNAL ;
    PORT
      LAYER M4 ;
        RECT  0 14.016 0.084 14.04 ;
    END
  END captured[41]
  PIN captured[42]
    DIRECTION INPUT ;
    USE SIGNAL ;
    PORT
      LAYER M4 ;
        RECT  0 14.304 0.084 14.328 ;
    END
  END captured[42]
  PIN captured[43]
    DIRECTION INPUT ;
    USE SIGNAL ;
    PORT
      LAYER M4 ;
        RECT  0 14.544 0.084 14.568 ;
    END
  END captured[43]
  PIN captured[44]
    DIRECTION INPUT ;
    USE SIGNAL ;
    PORT
      LAYER M4 ;
        RECT  0 14.832 0.084 14.856 ;
    END
  END captured[44]
  PIN captured[45]
    DIRECTION INPUT ;
    USE SIGNAL ;
    PORT
      LAYER M4 ;
        RECT  0 15.12 0.084 15.144 ;
    END
  END captured[45]
  PIN captured[46]
    DIRECTION INPUT ;
    USE SIGNAL ;
    PORT
      LAYER M4 ;
        RECT  0 15.408 0.084 15.432 ;
    END
  END captured[46]
  PIN captured[47]
    DIRECTION INPUT ;
    USE SIGNAL ;
    PORT
      LAYER M4 ;
        RECT  0 15.648 0.084 15.672 ;
    END
  END captured[47]
  PIN captured[48]
    DIRECTION INPUT ;
    USE SIGNAL ;
    PORT
      LAYER M4 ;
        RECT  0 15.936 0.084 15.96 ;
    END
  END captured[48]
  PIN captured[49]
    DIRECTION INPUT ;
    USE SIGNAL ;
    PORT
      LAYER M4 ;
        RECT  0 16.224 0.084 16.248 ;
    END
  END captured[49]
  PIN captured[4]
    DIRECTION INPUT ;
    USE SIGNAL ;
    PORT
      LAYER M4 ;
        RECT  0 3.744 0.084 3.768 ;
    END
  END captured[4]
  PIN captured[50]
    DIRECTION INPUT ;
    USE SIGNAL ;
    PORT
      LAYER M4 ;
        RECT  0 16.512 0.084 16.536 ;
    END
  END captured[50]
  PIN captured[51]
    DIRECTION INPUT ;
    USE SIGNAL ;
    PORT
      LAYER M4 ;
        RECT  0 16.8 0.084 16.824 ;
    END
  END captured[51]
  PIN captured[52]
    DIRECTION INPUT ;
    USE SIGNAL ;
    PORT
      LAYER M4 ;
        RECT  0 17.04 0.084 17.064 ;
    END
  END captured[52]
  PIN captured[53]
    DIRECTION INPUT ;
    USE SIGNAL ;
    PORT
      LAYER M4 ;
        RECT  0 17.328 0.084 17.352 ;
    END
  END captured[53]
  PIN captured[54]
    DIRECTION INPUT ;
    USE SIGNAL ;
    PORT
      LAYER M4 ;
        RECT  0 17.616 0.084 17.64 ;
    END
  END captured[54]
  PIN captured[55]
    DIRECTION INPUT ;
    USE SIGNAL ;
    PORT
      LAYER M4 ;
        RECT  0 17.904 0.084 17.928 ;
    END
  END captured[55]
  PIN captured[56]
    DIRECTION INPUT ;
    USE SIGNAL ;
    PORT
      LAYER M4 ;
        RECT  0 18.192 0.084 18.216 ;
    END
  END captured[56]
  PIN captured[57]
    DIRECTION INPUT ;
    USE SIGNAL ;
    PORT
      LAYER M4 ;
        RECT  0 18.432 0.084 18.456 ;
    END
  END captured[57]
  PIN captured[58]
    DIRECTION INPUT ;
    USE SIGNAL ;
    PORT
      LAYER M4 ;
        RECT  0 18.72 0.084 18.744 ;
    END
  END captured[58]
  PIN captured[59]
    DIRECTION INPUT ;
    USE SIGNAL ;
    PORT
      LAYER M4 ;
        RECT  0 19.008 0.084 19.032 ;
    END
  END captured[59]
  PIN captured[5]
    DIRECTION INPUT ;
    USE SIGNAL ;
    PORT
      LAYER M4 ;
        RECT  0 4.032 0.084 4.056 ;
    END
  END captured[5]
  PIN captured[60]
    DIRECTION INPUT ;
    USE SIGNAL ;
    PORT
      LAYER M4 ;
        RECT  0 19.296 0.084 19.32 ;
    END
  END captured[60]
  PIN captured[61]
    DIRECTION INPUT ;
    USE SIGNAL ;
    PORT
      LAYER M4 ;
        RECT  0 19.536 0.084 19.56 ;
    END
  END captured[61]
  PIN captured[62]
    DIRECTION INPUT ;
    USE SIGNAL ;
    PORT
      LAYER M4 ;
        RECT  0 19.824 0.084 19.848 ;
    END
  END captured[62]
  PIN captured[63]
    DIRECTION INPUT ;
    USE SIGNAL ;
    PORT
      LAYER M4 ;
        RECT  0 20.112 0.084 20.136 ;
    END
  END captured[63]
  PIN captured[64]
    DIRECTION INPUT ;
    USE SIGNAL ;
    PORT
      LAYER M4 ;
        RECT  0 20.4 0.084 20.424 ;
    END
  END captured[64]
  PIN captured[65]
    DIRECTION INPUT ;
    USE SIGNAL ;
    PORT
      LAYER M4 ;
        RECT  0 20.688 0.084 20.712 ;
    END
  END captured[65]
  PIN captured[66]
    DIRECTION INPUT ;
    USE SIGNAL ;
    PORT
      LAYER M4 ;
        RECT  0 20.928 0.084 20.952 ;
    END
  END captured[66]
  PIN captured[67]
    DIRECTION INPUT ;
    USE SIGNAL ;
    PORT
      LAYER M4 ;
        RECT  0 21.216 0.084 21.24 ;
    END
  END captured[67]
  PIN captured[68]
    DIRECTION INPUT ;
    USE SIGNAL ;
    PORT
      LAYER M4 ;
        RECT  0 21.504 0.084 21.528 ;
    END
  END captured[68]
  PIN captured[69]
    DIRECTION INPUT ;
    USE SIGNAL ;
    PORT
      LAYER M4 ;
        RECT  0 21.792 0.084 21.816 ;
    END
  END captured[69]
  PIN captured[6]
    DIRECTION INPUT ;
    USE SIGNAL ;
    PORT
      LAYER M4 ;
        RECT  0 4.272 0.084 4.296 ;
    END
  END captured[6]
  PIN captured[70]
    DIRECTION INPUT ;
    USE SIGNAL ;
    PORT
      LAYER M4 ;
        RECT  0 22.032 0.084 22.056 ;
    END
  END captured[70]
  PIN captured[71]
    DIRECTION INPUT ;
    USE SIGNAL ;
    PORT
      LAYER M4 ;
        RECT  0 22.32 0.084 22.344 ;
    END
  END captured[71]
  PIN captured[72]
    DIRECTION INPUT ;
    USE SIGNAL ;
    PORT
      LAYER M4 ;
        RECT  0 22.608 0.084 22.632 ;
    END
  END captured[72]
  PIN captured[73]
    DIRECTION INPUT ;
    USE SIGNAL ;
    PORT
      LAYER M4 ;
        RECT  0 22.896 0.084 22.92 ;
    END
  END captured[73]
  PIN captured[74]
    DIRECTION INPUT ;
    USE SIGNAL ;
    PORT
      LAYER M4 ;
        RECT  0 23.184 0.084 23.208 ;
    END
  END captured[74]
  PIN captured[75]
    DIRECTION INPUT ;
    USE SIGNAL ;
    PORT
      LAYER M4 ;
        RECT  0 23.424 0.084 23.448 ;
    END
  END captured[75]
  PIN captured[76]
    DIRECTION INPUT ;
    USE SIGNAL ;
    PORT
      LAYER M4 ;
        RECT  0 23.712 0.084 23.736 ;
    END
  END captured[76]
  PIN captured[77]
    DIRECTION INPUT ;
    USE SIGNAL ;
    PORT
      LAYER M4 ;
        RECT  0 24 0.084 24.024 ;
    END
  END captured[77]
  PIN captured[78]
    DIRECTION INPUT ;
    USE SIGNAL ;
    PORT
      LAYER M4 ;
        RECT  0 24.288 0.084 24.312 ;
    END
  END captured[78]
  PIN captured[79]
    DIRECTION INPUT ;
    USE SIGNAL ;
    PORT
      LAYER M4 ;
        RECT  0 24.576 0.084 24.6 ;
    END
  END captured[79]
  PIN captured[7]
    DIRECTION INPUT ;
    USE SIGNAL ;
    PORT
      LAYER M4 ;
        RECT  0 4.56 0.084 4.584 ;
    END
  END captured[7]
  PIN captured[80]
    DIRECTION INPUT ;
    USE SIGNAL ;
    PORT
      LAYER M4 ;
        RECT  0 24.816 0.084 24.84 ;
    END
  END captured[80]
  PIN captured[81]
    DIRECTION INPUT ;
    USE SIGNAL ;
    PORT
      LAYER M4 ;
        RECT  0 25.104 0.084 25.128 ;
    END
  END captured[81]
  PIN captured[82]
    DIRECTION INPUT ;
    USE SIGNAL ;
    PORT
      LAYER M4 ;
        RECT  0 25.392 0.084 25.416 ;
    END
  END captured[82]
  PIN captured[83]
    DIRECTION INPUT ;
    USE SIGNAL ;
    PORT
      LAYER M4 ;
        RECT  0 25.68 0.084 25.704 ;
    END
  END captured[83]
  PIN captured[84]
    DIRECTION INPUT ;
    USE SIGNAL ;
    PORT
      LAYER M4 ;
        RECT  0 25.92 0.084 25.944 ;
    END
  END captured[84]
  PIN captured[85]
    DIRECTION INPUT ;
    USE SIGNAL ;
    PORT
      LAYER M4 ;
        RECT  0 26.208 0.084 26.232 ;
    END
  END captured[85]
  PIN captured[86]
    DIRECTION INPUT ;
    USE SIGNAL ;
    PORT
      LAYER M4 ;
        RECT  0 26.496 0.084 26.52 ;
    END
  END captured[86]
  PIN captured[87]
    DIRECTION INPUT ;
    USE SIGNAL ;
    PORT
      LAYER M4 ;
        RECT  0 26.784 0.084 26.808 ;
    END
  END captured[87]
  PIN captured[88]
    DIRECTION INPUT ;
    USE SIGNAL ;
    PORT
      LAYER M4 ;
        RECT  0 27.072 0.084 27.096 ;
    END
  END captured[88]
  PIN captured[89]
    DIRECTION INPUT ;
    USE SIGNAL ;
    PORT
      LAYER M4 ;
        RECT  0 27.312 0.084 27.336 ;
    END
  END captured[89]
  PIN captured[8]
    DIRECTION INPUT ;
    USE SIGNAL ;
    PORT
      LAYER M4 ;
        RECT  0 4.848 0.084 4.872 ;
    END
  END captured[8]
  PIN captured[90]
    DIRECTION INPUT ;
    USE SIGNAL ;
    PORT
      LAYER M4 ;
        RECT  0 27.6 0.084 27.624 ;
    END
  END captured[90]
  PIN captured[91]
    DIRECTION INPUT ;
    USE SIGNAL ;
    PORT
      LAYER M4 ;
        RECT  0 27.888 0.084 27.912 ;
    END
  END captured[91]
  PIN captured[92]
    DIRECTION INPUT ;
    USE SIGNAL ;
    PORT
      LAYER M4 ;
        RECT  0 28.176 0.084 28.2 ;
    END
  END captured[92]
  PIN captured[93]
    DIRECTION INPUT ;
    USE SIGNAL ;
    PORT
      LAYER M4 ;
        RECT  0 28.416 0.084 28.44 ;
    END
  END captured[93]
  PIN captured[94]
    DIRECTION INPUT ;
    USE SIGNAL ;
    PORT
      LAYER M4 ;
        RECT  0 28.704 0.084 28.728 ;
    END
  END captured[94]
  PIN captured[95]
    DIRECTION INPUT ;
    USE SIGNAL ;
    PORT
      LAYER M4 ;
        RECT  0 28.992 0.084 29.016 ;
    END
  END captured[95]
  PIN captured[96]
    DIRECTION INPUT ;
    USE SIGNAL ;
    PORT
      LAYER M4 ;
        RECT  0 29.28 0.084 29.304 ;
    END
  END captured[96]
  PIN captured[97]
    DIRECTION INPUT ;
    USE SIGNAL ;
    PORT
      LAYER M4 ;
        RECT  0 29.568 0.084 29.592 ;
    END
  END captured[97]
  PIN captured[98]
    DIRECTION INPUT ;
    USE SIGNAL ;
    PORT
      LAYER M4 ;
        RECT  0 29.808 0.084 29.832 ;
    END
  END captured[98]
  PIN captured[99]
    DIRECTION INPUT ;
    USE SIGNAL ;
    PORT
      LAYER M4 ;
        RECT  0 30.096 0.084 30.12 ;
    END
  END captured[99]
  PIN captured[9]
    DIRECTION INPUT ;
    USE SIGNAL ;
    PORT
      LAYER M4 ;
        RECT  0 5.136 0.084 5.16 ;
    END
  END captured[9]
  PIN captured_slot[0]
    DIRECTION INPUT ;
    USE SIGNAL ;
    PORT
      LAYER M4 ;
        RECT  0 100.512 0.084 100.536 ;
    END
  END captured_slot[0]
  PIN captured_slot[10]
    DIRECTION INPUT ;
    USE SIGNAL ;
    PORT
      LAYER M4 ;
        RECT  0 103.008 0.084 103.032 ;
    END
  END captured_slot[10]
  PIN captured_slot[1]
    DIRECTION INPUT ;
    USE SIGNAL ;
    PORT
      LAYER M4 ;
        RECT  0 100.752 0.084 100.776 ;
    END
  END captured_slot[1]
  PIN captured_slot[2]
    DIRECTION INPUT ;
    USE SIGNAL ;
    PORT
      LAYER M4 ;
        RECT  0 100.992 0.084 101.016 ;
    END
  END captured_slot[2]
  PIN captured_slot[3]
    DIRECTION INPUT ;
    USE SIGNAL ;
    PORT
      LAYER M4 ;
        RECT  0 101.232 0.084 101.256 ;
    END
  END captured_slot[3]
  PIN captured_slot[4]
    DIRECTION INPUT ;
    USE SIGNAL ;
    PORT
      LAYER M4 ;
        RECT  0 101.52 0.084 101.544 ;
    END
  END captured_slot[4]
  PIN captured_slot[5]
    DIRECTION INPUT ;
    USE SIGNAL ;
    PORT
      LAYER M4 ;
        RECT  0 101.76 0.084 101.784 ;
    END
  END captured_slot[5]
  PIN captured_slot[6]
    DIRECTION INPUT ;
    USE SIGNAL ;
    PORT
      LAYER M4 ;
        RECT  0 102 0.084 102.024 ;
    END
  END captured_slot[6]
  PIN captured_slot[7]
    DIRECTION INPUT ;
    USE SIGNAL ;
    PORT
      LAYER M4 ;
        RECT  0 102.24 0.084 102.264 ;
    END
  END captured_slot[7]
  PIN captured_slot[8]
    DIRECTION INPUT ;
    USE SIGNAL ;
    PORT
      LAYER M4 ;
        RECT  0 102.48 0.084 102.504 ;
    END
  END captured_slot[8]
  PIN captured_slot[9]
    DIRECTION INPUT ;
    USE SIGNAL ;
    PORT
      LAYER M4 ;
        RECT  0 102.768 0.084 102.792 ;
    END
  END captured_slot[9]
  PIN clk
    DIRECTION INPUT ;
    USE SIGNAL ;
    PORT
      LAYER M5 ;
        RECT  21.552 105.756 21.576 105.84 ;
    END
  END clk
  PIN dst_d[0]
    DIRECTION OUTPUT ;
    USE SIGNAL ;
    PORT
      LAYER M4 ;
        RECT  25.836 2.592 25.92 2.616 ;
    END
  END dst_d[0]
  PIN dst_d[100]
    DIRECTION OUTPUT ;
    USE SIGNAL ;
    PORT
      LAYER M4 ;
        RECT  25.836 21.408 25.92 21.432 ;
    END
  END dst_d[100]
  PIN dst_d[101]
    DIRECTION OUTPUT ;
    USE SIGNAL ;
    PORT
      LAYER M4 ;
        RECT  25.836 21.6 25.92 21.624 ;
    END
  END dst_d[101]
  PIN dst_d[102]
    DIRECTION OUTPUT ;
    USE SIGNAL ;
    PORT
      LAYER M4 ;
        RECT  25.836 21.792 25.92 21.816 ;
    END
  END dst_d[102]
  PIN dst_d[103]
    DIRECTION OUTPUT ;
    USE SIGNAL ;
    PORT
      LAYER M4 ;
        RECT  25.836 21.984 25.92 22.008 ;
    END
  END dst_d[103]
  PIN dst_d[104]
    DIRECTION OUTPUT ;
    USE SIGNAL ;
    PORT
      LAYER M4 ;
        RECT  25.836 22.176 25.92 22.2 ;
    END
  END dst_d[104]
  PIN dst_d[105]
    DIRECTION OUTPUT ;
    USE SIGNAL ;
    PORT
      LAYER M4 ;
        RECT  25.836 22.368 25.92 22.392 ;
    END
  END dst_d[105]
  PIN dst_d[106]
    DIRECTION OUTPUT ;
    USE SIGNAL ;
    PORT
      LAYER M4 ;
        RECT  25.836 22.56 25.92 22.584 ;
    END
  END dst_d[106]
  PIN dst_d[107]
    DIRECTION OUTPUT ;
    USE SIGNAL ;
    PORT
      LAYER M4 ;
        RECT  25.836 22.752 25.92 22.776 ;
    END
  END dst_d[107]
  PIN dst_d[108]
    DIRECTION OUTPUT ;
    USE SIGNAL ;
    PORT
      LAYER M4 ;
        RECT  25.836 22.944 25.92 22.968 ;
    END
  END dst_d[108]
  PIN dst_d[109]
    DIRECTION OUTPUT ;
    USE SIGNAL ;
    PORT
      LAYER M4 ;
        RECT  25.836 23.136 25.92 23.16 ;
    END
  END dst_d[109]
  PIN dst_d[10]
    DIRECTION OUTPUT ;
    USE SIGNAL ;
    PORT
      LAYER M4 ;
        RECT  25.836 4.464 25.92 4.488 ;
    END
  END dst_d[10]
  PIN dst_d[110]
    DIRECTION OUTPUT ;
    USE SIGNAL ;
    PORT
      LAYER M4 ;
        RECT  25.836 23.28 25.92 23.304 ;
    END
  END dst_d[110]
  PIN dst_d[111]
    DIRECTION OUTPUT ;
    USE SIGNAL ;
    PORT
      LAYER M4 ;
        RECT  25.836 23.472 25.92 23.496 ;
    END
  END dst_d[111]
  PIN dst_d[112]
    DIRECTION OUTPUT ;
    USE SIGNAL ;
    PORT
      LAYER M4 ;
        RECT  25.836 23.664 25.92 23.688 ;
    END
  END dst_d[112]
  PIN dst_d[113]
    DIRECTION OUTPUT ;
    USE SIGNAL ;
    PORT
      LAYER M4 ;
        RECT  25.836 23.856 25.92 23.88 ;
    END
  END dst_d[113]
  PIN dst_d[114]
    DIRECTION OUTPUT ;
    USE SIGNAL ;
    PORT
      LAYER M4 ;
        RECT  25.836 24.048 25.92 24.072 ;
    END
  END dst_d[114]
  PIN dst_d[115]
    DIRECTION OUTPUT ;
    USE SIGNAL ;
    PORT
      LAYER M4 ;
        RECT  25.836 24.24 25.92 24.264 ;
    END
  END dst_d[115]
  PIN dst_d[116]
    DIRECTION OUTPUT ;
    USE SIGNAL ;
    PORT
      LAYER M4 ;
        RECT  25.836 24.432 25.92 24.456 ;
    END
  END dst_d[116]
  PIN dst_d[117]
    DIRECTION OUTPUT ;
    USE SIGNAL ;
    PORT
      LAYER M4 ;
        RECT  25.836 24.624 25.92 24.648 ;
    END
  END dst_d[117]
  PIN dst_d[118]
    DIRECTION OUTPUT ;
    USE SIGNAL ;
    PORT
      LAYER M4 ;
        RECT  25.836 24.816 25.92 24.84 ;
    END
  END dst_d[118]
  PIN dst_d[119]
    DIRECTION OUTPUT ;
    USE SIGNAL ;
    PORT
      LAYER M4 ;
        RECT  25.836 25.008 25.92 25.032 ;
    END
  END dst_d[119]
  PIN dst_d[11]
    DIRECTION OUTPUT ;
    USE SIGNAL ;
    PORT
      LAYER M4 ;
        RECT  25.836 4.656 25.92 4.68 ;
    END
  END dst_d[11]
  PIN dst_d[120]
    DIRECTION OUTPUT ;
    USE SIGNAL ;
    PORT
      LAYER M4 ;
        RECT  25.836 25.2 25.92 25.224 ;
    END
  END dst_d[120]
  PIN dst_d[121]
    DIRECTION OUTPUT ;
    USE SIGNAL ;
    PORT
      LAYER M4 ;
        RECT  25.836 25.392 25.92 25.416 ;
    END
  END dst_d[121]
  PIN dst_d[122]
    DIRECTION OUTPUT ;
    USE SIGNAL ;
    PORT
      LAYER M4 ;
        RECT  25.836 25.584 25.92 25.608 ;
    END
  END dst_d[122]
  PIN dst_d[123]
    DIRECTION OUTPUT ;
    USE SIGNAL ;
    PORT
      LAYER M4 ;
        RECT  25.836 25.728 25.92 25.752 ;
    END
  END dst_d[123]
  PIN dst_d[124]
    DIRECTION OUTPUT ;
    USE SIGNAL ;
    PORT
      LAYER M4 ;
        RECT  25.836 25.92 25.92 25.944 ;
    END
  END dst_d[124]
  PIN dst_d[125]
    DIRECTION OUTPUT ;
    USE SIGNAL ;
    PORT
      LAYER M4 ;
        RECT  25.836 26.112 25.92 26.136 ;
    END
  END dst_d[125]
  PIN dst_d[126]
    DIRECTION OUTPUT ;
    USE SIGNAL ;
    PORT
      LAYER M4 ;
        RECT  25.836 26.304 25.92 26.328 ;
    END
  END dst_d[126]
  PIN dst_d[127]
    DIRECTION OUTPUT ;
    USE SIGNAL ;
    PORT
      LAYER M4 ;
        RECT  25.836 26.496 25.92 26.52 ;
    END
  END dst_d[127]
  PIN dst_d[128]
    DIRECTION OUTPUT ;
    USE SIGNAL ;
    PORT
      LAYER M4 ;
        RECT  25.836 26.688 25.92 26.712 ;
    END
  END dst_d[128]
  PIN dst_d[129]
    DIRECTION OUTPUT ;
    USE SIGNAL ;
    PORT
      LAYER M4 ;
        RECT  25.836 26.88 25.92 26.904 ;
    END
  END dst_d[129]
  PIN dst_d[12]
    DIRECTION OUTPUT ;
    USE SIGNAL ;
    PORT
      LAYER M4 ;
        RECT  25.836 4.848 25.92 4.872 ;
    END
  END dst_d[12]
  PIN dst_d[130]
    DIRECTION OUTPUT ;
    USE SIGNAL ;
    PORT
      LAYER M4 ;
        RECT  25.836 27.072 25.92 27.096 ;
    END
  END dst_d[130]
  PIN dst_d[131]
    DIRECTION OUTPUT ;
    USE SIGNAL ;
    PORT
      LAYER M4 ;
        RECT  25.836 27.264 25.92 27.288 ;
    END
  END dst_d[131]
  PIN dst_d[132]
    DIRECTION OUTPUT ;
    USE SIGNAL ;
    PORT
      LAYER M4 ;
        RECT  25.836 27.456 25.92 27.48 ;
    END
  END dst_d[132]
  PIN dst_d[133]
    DIRECTION OUTPUT ;
    USE SIGNAL ;
    PORT
      LAYER M4 ;
        RECT  25.836 27.648 25.92 27.672 ;
    END
  END dst_d[133]
  PIN dst_d[134]
    DIRECTION OUTPUT ;
    USE SIGNAL ;
    PORT
      LAYER M4 ;
        RECT  25.836 27.84 25.92 27.864 ;
    END
  END dst_d[134]
  PIN dst_d[135]
    DIRECTION OUTPUT ;
    USE SIGNAL ;
    PORT
      LAYER M4 ;
        RECT  25.836 28.032 25.92 28.056 ;
    END
  END dst_d[135]
  PIN dst_d[136]
    DIRECTION OUTPUT ;
    USE SIGNAL ;
    PORT
      LAYER M4 ;
        RECT  25.836 28.176 25.92 28.2 ;
    END
  END dst_d[136]
  PIN dst_d[137]
    DIRECTION OUTPUT ;
    USE SIGNAL ;
    PORT
      LAYER M4 ;
        RECT  25.836 28.368 25.92 28.392 ;
    END
  END dst_d[137]
  PIN dst_d[138]
    DIRECTION OUTPUT ;
    USE SIGNAL ;
    PORT
      LAYER M4 ;
        RECT  25.836 28.56 25.92 28.584 ;
    END
  END dst_d[138]
  PIN dst_d[139]
    DIRECTION OUTPUT ;
    USE SIGNAL ;
    PORT
      LAYER M4 ;
        RECT  25.836 28.752 25.92 28.776 ;
    END
  END dst_d[139]
  PIN dst_d[13]
    DIRECTION OUTPUT ;
    USE SIGNAL ;
    PORT
      LAYER M4 ;
        RECT  25.836 5.04 25.92 5.064 ;
    END
  END dst_d[13]
  PIN dst_d[140]
    DIRECTION OUTPUT ;
    USE SIGNAL ;
    PORT
      LAYER M4 ;
        RECT  25.836 28.944 25.92 28.968 ;
    END
  END dst_d[140]
  PIN dst_d[141]
    DIRECTION OUTPUT ;
    USE SIGNAL ;
    PORT
      LAYER M4 ;
        RECT  25.836 29.136 25.92 29.16 ;
    END
  END dst_d[141]
  PIN dst_d[142]
    DIRECTION OUTPUT ;
    USE SIGNAL ;
    PORT
      LAYER M4 ;
        RECT  25.836 29.328 25.92 29.352 ;
    END
  END dst_d[142]
  PIN dst_d[143]
    DIRECTION OUTPUT ;
    USE SIGNAL ;
    PORT
      LAYER M4 ;
        RECT  25.836 29.52 25.92 29.544 ;
    END
  END dst_d[143]
  PIN dst_d[144]
    DIRECTION OUTPUT ;
    USE SIGNAL ;
    PORT
      LAYER M4 ;
        RECT  25.836 29.712 25.92 29.736 ;
    END
  END dst_d[144]
  PIN dst_d[145]
    DIRECTION OUTPUT ;
    USE SIGNAL ;
    PORT
      LAYER M4 ;
        RECT  25.836 29.904 25.92 29.928 ;
    END
  END dst_d[145]
  PIN dst_d[146]
    DIRECTION OUTPUT ;
    USE SIGNAL ;
    PORT
      LAYER M4 ;
        RECT  25.836 30.096 25.92 30.12 ;
    END
  END dst_d[146]
  PIN dst_d[147]
    DIRECTION OUTPUT ;
    USE SIGNAL ;
    PORT
      LAYER M4 ;
        RECT  25.836 30.288 25.92 30.312 ;
    END
  END dst_d[147]
  PIN dst_d[148]
    DIRECTION OUTPUT ;
    USE SIGNAL ;
    PORT
      LAYER M4 ;
        RECT  25.836 30.48 25.92 30.504 ;
    END
  END dst_d[148]
  PIN dst_d[149]
    DIRECTION OUTPUT ;
    USE SIGNAL ;
    PORT
      LAYER M4 ;
        RECT  25.836 30.672 25.92 30.696 ;
    END
  END dst_d[149]
  PIN dst_d[14]
    DIRECTION OUTPUT ;
    USE SIGNAL ;
    PORT
      LAYER M4 ;
        RECT  25.836 5.232 25.92 5.256 ;
    END
  END dst_d[14]
  PIN dst_d[150]
    DIRECTION OUTPUT ;
    USE SIGNAL ;
    PORT
      LAYER M4 ;
        RECT  25.836 30.816 25.92 30.84 ;
    END
  END dst_d[150]
  PIN dst_d[151]
    DIRECTION OUTPUT ;
    USE SIGNAL ;
    PORT
      LAYER M4 ;
        RECT  25.836 31.008 25.92 31.032 ;
    END
  END dst_d[151]
  PIN dst_d[152]
    DIRECTION OUTPUT ;
    USE SIGNAL ;
    PORT
      LAYER M4 ;
        RECT  25.836 31.2 25.92 31.224 ;
    END
  END dst_d[152]
  PIN dst_d[153]
    DIRECTION OUTPUT ;
    USE SIGNAL ;
    PORT
      LAYER M4 ;
        RECT  25.836 31.392 25.92 31.416 ;
    END
  END dst_d[153]
  PIN dst_d[154]
    DIRECTION OUTPUT ;
    USE SIGNAL ;
    PORT
      LAYER M4 ;
        RECT  25.836 31.584 25.92 31.608 ;
    END
  END dst_d[154]
  PIN dst_d[155]
    DIRECTION OUTPUT ;
    USE SIGNAL ;
    PORT
      LAYER M4 ;
        RECT  25.836 31.776 25.92 31.8 ;
    END
  END dst_d[155]
  PIN dst_d[156]
    DIRECTION OUTPUT ;
    USE SIGNAL ;
    PORT
      LAYER M4 ;
        RECT  25.836 31.968 25.92 31.992 ;
    END
  END dst_d[156]
  PIN dst_d[157]
    DIRECTION OUTPUT ;
    USE SIGNAL ;
    PORT
      LAYER M4 ;
        RECT  25.836 32.16 25.92 32.184 ;
    END
  END dst_d[157]
  PIN dst_d[158]
    DIRECTION OUTPUT ;
    USE SIGNAL ;
    PORT
      LAYER M4 ;
        RECT  25.836 32.352 25.92 32.376 ;
    END
  END dst_d[158]
  PIN dst_d[159]
    DIRECTION OUTPUT ;
    USE SIGNAL ;
    PORT
      LAYER M4 ;
        RECT  25.836 32.544 25.92 32.568 ;
    END
  END dst_d[159]
  PIN dst_d[15]
    DIRECTION OUTPUT ;
    USE SIGNAL ;
    PORT
      LAYER M4 ;
        RECT  25.836 5.424 25.92 5.448 ;
    END
  END dst_d[15]
  PIN dst_d[160]
    DIRECTION OUTPUT ;
    USE SIGNAL ;
    PORT
      LAYER M4 ;
        RECT  25.836 32.736 25.92 32.76 ;
    END
  END dst_d[160]
  PIN dst_d[161]
    DIRECTION OUTPUT ;
    USE SIGNAL ;
    PORT
      LAYER M4 ;
        RECT  25.836 32.928 25.92 32.952 ;
    END
  END dst_d[161]
  PIN dst_d[162]
    DIRECTION OUTPUT ;
    USE SIGNAL ;
    PORT
      LAYER M4 ;
        RECT  25.836 33.12 25.92 33.144 ;
    END
  END dst_d[162]
  PIN dst_d[163]
    DIRECTION OUTPUT ;
    USE SIGNAL ;
    PORT
      LAYER M4 ;
        RECT  25.836 33.264 25.92 33.288 ;
    END
  END dst_d[163]
  PIN dst_d[164]
    DIRECTION OUTPUT ;
    USE SIGNAL ;
    PORT
      LAYER M4 ;
        RECT  25.836 33.456 25.92 33.48 ;
    END
  END dst_d[164]
  PIN dst_d[165]
    DIRECTION OUTPUT ;
    USE SIGNAL ;
    PORT
      LAYER M4 ;
        RECT  25.836 33.648 25.92 33.672 ;
    END
  END dst_d[165]
  PIN dst_d[166]
    DIRECTION OUTPUT ;
    USE SIGNAL ;
    PORT
      LAYER M4 ;
        RECT  25.836 33.84 25.92 33.864 ;
    END
  END dst_d[166]
  PIN dst_d[167]
    DIRECTION OUTPUT ;
    USE SIGNAL ;
    PORT
      LAYER M4 ;
        RECT  25.836 34.032 25.92 34.056 ;
    END
  END dst_d[167]
  PIN dst_d[168]
    DIRECTION OUTPUT ;
    USE SIGNAL ;
    PORT
      LAYER M4 ;
        RECT  25.836 34.224 25.92 34.248 ;
    END
  END dst_d[168]
  PIN dst_d[169]
    DIRECTION OUTPUT ;
    USE SIGNAL ;
    PORT
      LAYER M4 ;
        RECT  25.836 34.416 25.92 34.44 ;
    END
  END dst_d[169]
  PIN dst_d[16]
    DIRECTION OUTPUT ;
    USE SIGNAL ;
    PORT
      LAYER M4 ;
        RECT  25.836 5.616 25.92 5.64 ;
    END
  END dst_d[16]
  PIN dst_d[170]
    DIRECTION OUTPUT ;
    USE SIGNAL ;
    PORT
      LAYER M4 ;
        RECT  25.836 34.608 25.92 34.632 ;
    END
  END dst_d[170]
  PIN dst_d[171]
    DIRECTION OUTPUT ;
    USE SIGNAL ;
    PORT
      LAYER M4 ;
        RECT  25.836 34.8 25.92 34.824 ;
    END
  END dst_d[171]
  PIN dst_d[172]
    DIRECTION OUTPUT ;
    USE SIGNAL ;
    PORT
      LAYER M4 ;
        RECT  25.836 34.992 25.92 35.016 ;
    END
  END dst_d[172]
  PIN dst_d[173]
    DIRECTION OUTPUT ;
    USE SIGNAL ;
    PORT
      LAYER M4 ;
        RECT  25.836 35.184 25.92 35.208 ;
    END
  END dst_d[173]
  PIN dst_d[174]
    DIRECTION OUTPUT ;
    USE SIGNAL ;
    PORT
      LAYER M4 ;
        RECT  25.836 35.376 25.92 35.4 ;
    END
  END dst_d[174]
  PIN dst_d[175]
    DIRECTION OUTPUT ;
    USE SIGNAL ;
    PORT
      LAYER M4 ;
        RECT  25.836 35.568 25.92 35.592 ;
    END
  END dst_d[175]
  PIN dst_d[176]
    DIRECTION OUTPUT ;
    USE SIGNAL ;
    PORT
      LAYER M4 ;
        RECT  25.836 35.712 25.92 35.736 ;
    END
  END dst_d[176]
  PIN dst_d[177]
    DIRECTION OUTPUT ;
    USE SIGNAL ;
    PORT
      LAYER M4 ;
        RECT  25.836 35.904 25.92 35.928 ;
    END
  END dst_d[177]
  PIN dst_d[178]
    DIRECTION OUTPUT ;
    USE SIGNAL ;
    PORT
      LAYER M4 ;
        RECT  25.836 36.096 25.92 36.12 ;
    END
  END dst_d[178]
  PIN dst_d[179]
    DIRECTION OUTPUT ;
    USE SIGNAL ;
    PORT
      LAYER M4 ;
        RECT  25.836 36.288 25.92 36.312 ;
    END
  END dst_d[179]
  PIN dst_d[17]
    DIRECTION OUTPUT ;
    USE SIGNAL ;
    PORT
      LAYER M4 ;
        RECT  25.836 5.808 25.92 5.832 ;
    END
  END dst_d[17]
  PIN dst_d[180]
    DIRECTION OUTPUT ;
    USE SIGNAL ;
    PORT
      LAYER M4 ;
        RECT  25.836 36.48 25.92 36.504 ;
    END
  END dst_d[180]
  PIN dst_d[181]
    DIRECTION OUTPUT ;
    USE SIGNAL ;
    PORT
      LAYER M4 ;
        RECT  25.836 36.672 25.92 36.696 ;
    END
  END dst_d[181]
  PIN dst_d[182]
    DIRECTION OUTPUT ;
    USE SIGNAL ;
    PORT
      LAYER M4 ;
        RECT  25.836 36.864 25.92 36.888 ;
    END
  END dst_d[182]
  PIN dst_d[183]
    DIRECTION OUTPUT ;
    USE SIGNAL ;
    PORT
      LAYER M4 ;
        RECT  25.836 37.056 25.92 37.08 ;
    END
  END dst_d[183]
  PIN dst_d[184]
    DIRECTION OUTPUT ;
    USE SIGNAL ;
    PORT
      LAYER M4 ;
        RECT  25.836 37.248 25.92 37.272 ;
    END
  END dst_d[184]
  PIN dst_d[185]
    DIRECTION OUTPUT ;
    USE SIGNAL ;
    PORT
      LAYER M4 ;
        RECT  25.836 37.44 25.92 37.464 ;
    END
  END dst_d[185]
  PIN dst_d[186]
    DIRECTION OUTPUT ;
    USE SIGNAL ;
    PORT
      LAYER M4 ;
        RECT  25.836 37.632 25.92 37.656 ;
    END
  END dst_d[186]
  PIN dst_d[187]
    DIRECTION OUTPUT ;
    USE SIGNAL ;
    PORT
      LAYER M4 ;
        RECT  25.836 37.824 25.92 37.848 ;
    END
  END dst_d[187]
  PIN dst_d[188]
    DIRECTION OUTPUT ;
    USE SIGNAL ;
    PORT
      LAYER M4 ;
        RECT  25.836 38.016 25.92 38.04 ;
    END
  END dst_d[188]
  PIN dst_d[189]
    DIRECTION OUTPUT ;
    USE SIGNAL ;
    PORT
      LAYER M4 ;
        RECT  25.836 38.16 25.92 38.184 ;
    END
  END dst_d[189]
  PIN dst_d[18]
    DIRECTION OUTPUT ;
    USE SIGNAL ;
    PORT
      LAYER M4 ;
        RECT  25.836 5.952 25.92 5.976 ;
    END
  END dst_d[18]
  PIN dst_d[190]
    DIRECTION OUTPUT ;
    USE SIGNAL ;
    PORT
      LAYER M4 ;
        RECT  25.836 38.352 25.92 38.376 ;
    END
  END dst_d[190]
  PIN dst_d[191]
    DIRECTION OUTPUT ;
    USE SIGNAL ;
    PORT
      LAYER M4 ;
        RECT  25.836 38.544 25.92 38.568 ;
    END
  END dst_d[191]
  PIN dst_d[192]
    DIRECTION OUTPUT ;
    USE SIGNAL ;
    PORT
      LAYER M4 ;
        RECT  25.836 38.736 25.92 38.76 ;
    END
  END dst_d[192]
  PIN dst_d[193]
    DIRECTION OUTPUT ;
    USE SIGNAL ;
    PORT
      LAYER M4 ;
        RECT  25.836 38.928 25.92 38.952 ;
    END
  END dst_d[193]
  PIN dst_d[194]
    DIRECTION OUTPUT ;
    USE SIGNAL ;
    PORT
      LAYER M4 ;
        RECT  25.836 39.12 25.92 39.144 ;
    END
  END dst_d[194]
  PIN dst_d[195]
    DIRECTION OUTPUT ;
    USE SIGNAL ;
    PORT
      LAYER M4 ;
        RECT  25.836 39.312 25.92 39.336 ;
    END
  END dst_d[195]
  PIN dst_d[196]
    DIRECTION OUTPUT ;
    USE SIGNAL ;
    PORT
      LAYER M4 ;
        RECT  25.836 39.504 25.92 39.528 ;
    END
  END dst_d[196]
  PIN dst_d[197]
    DIRECTION OUTPUT ;
    USE SIGNAL ;
    PORT
      LAYER M4 ;
        RECT  25.836 39.696 25.92 39.72 ;
    END
  END dst_d[197]
  PIN dst_d[198]
    DIRECTION OUTPUT ;
    USE SIGNAL ;
    PORT
      LAYER M4 ;
        RECT  25.836 39.888 25.92 39.912 ;
    END
  END dst_d[198]
  PIN dst_d[199]
    DIRECTION OUTPUT ;
    USE SIGNAL ;
    PORT
      LAYER M4 ;
        RECT  25.836 40.08 25.92 40.104 ;
    END
  END dst_d[199]
  PIN dst_d[19]
    DIRECTION OUTPUT ;
    USE SIGNAL ;
    PORT
      LAYER M4 ;
        RECT  25.836 6.144 25.92 6.168 ;
    END
  END dst_d[19]
  PIN dst_d[1]
    DIRECTION OUTPUT ;
    USE SIGNAL ;
    PORT
      LAYER M4 ;
        RECT  25.836 2.784 25.92 2.808 ;
    END
  END dst_d[1]
  PIN dst_d[200]
    DIRECTION OUTPUT ;
    USE SIGNAL ;
    PORT
      LAYER M4 ;
        RECT  25.836 40.272 25.92 40.296 ;
    END
  END dst_d[200]
  PIN dst_d[201]
    DIRECTION OUTPUT ;
    USE SIGNAL ;
    PORT
      LAYER M4 ;
        RECT  25.836 40.464 25.92 40.488 ;
    END
  END dst_d[201]
  PIN dst_d[202]
    DIRECTION OUTPUT ;
    USE SIGNAL ;
    PORT
      LAYER M4 ;
        RECT  25.836 40.608 25.92 40.632 ;
    END
  END dst_d[202]
  PIN dst_d[203]
    DIRECTION OUTPUT ;
    USE SIGNAL ;
    PORT
      LAYER M4 ;
        RECT  25.836 40.8 25.92 40.824 ;
    END
  END dst_d[203]
  PIN dst_d[204]
    DIRECTION OUTPUT ;
    USE SIGNAL ;
    PORT
      LAYER M4 ;
        RECT  25.836 40.992 25.92 41.016 ;
    END
  END dst_d[204]
  PIN dst_d[205]
    DIRECTION OUTPUT ;
    USE SIGNAL ;
    PORT
      LAYER M4 ;
        RECT  25.836 41.184 25.92 41.208 ;
    END
  END dst_d[205]
  PIN dst_d[206]
    DIRECTION OUTPUT ;
    USE SIGNAL ;
    PORT
      LAYER M4 ;
        RECT  25.836 41.376 25.92 41.4 ;
    END
  END dst_d[206]
  PIN dst_d[207]
    DIRECTION OUTPUT ;
    USE SIGNAL ;
    PORT
      LAYER M4 ;
        RECT  25.836 41.568 25.92 41.592 ;
    END
  END dst_d[207]
  PIN dst_d[208]
    DIRECTION OUTPUT ;
    USE SIGNAL ;
    PORT
      LAYER M4 ;
        RECT  25.836 41.76 25.92 41.784 ;
    END
  END dst_d[208]
  PIN dst_d[209]
    DIRECTION OUTPUT ;
    USE SIGNAL ;
    PORT
      LAYER M4 ;
        RECT  25.836 41.952 25.92 41.976 ;
    END
  END dst_d[209]
  PIN dst_d[20]
    DIRECTION OUTPUT ;
    USE SIGNAL ;
    PORT
      LAYER M4 ;
        RECT  25.836 6.336 25.92 6.36 ;
    END
  END dst_d[20]
  PIN dst_d[210]
    DIRECTION OUTPUT ;
    USE SIGNAL ;
    PORT
      LAYER M4 ;
        RECT  25.836 42.144 25.92 42.168 ;
    END
  END dst_d[210]
  PIN dst_d[211]
    DIRECTION OUTPUT ;
    USE SIGNAL ;
    PORT
      LAYER M4 ;
        RECT  25.836 42.336 25.92 42.36 ;
    END
  END dst_d[211]
  PIN dst_d[212]
    DIRECTION OUTPUT ;
    USE SIGNAL ;
    PORT
      LAYER M4 ;
        RECT  25.836 42.528 25.92 42.552 ;
    END
  END dst_d[212]
  PIN dst_d[213]
    DIRECTION OUTPUT ;
    USE SIGNAL ;
    PORT
      LAYER M4 ;
        RECT  25.836 42.72 25.92 42.744 ;
    END
  END dst_d[213]
  PIN dst_d[214]
    DIRECTION OUTPUT ;
    USE SIGNAL ;
    PORT
      LAYER M4 ;
        RECT  25.836 42.912 25.92 42.936 ;
    END
  END dst_d[214]
  PIN dst_d[215]
    DIRECTION OUTPUT ;
    USE SIGNAL ;
    PORT
      LAYER M4 ;
        RECT  25.836 43.056 25.92 43.08 ;
    END
  END dst_d[215]
  PIN dst_d[216]
    DIRECTION OUTPUT ;
    USE SIGNAL ;
    PORT
      LAYER M4 ;
        RECT  25.836 43.248 25.92 43.272 ;
    END
  END dst_d[216]
  PIN dst_d[217]
    DIRECTION OUTPUT ;
    USE SIGNAL ;
    PORT
      LAYER M4 ;
        RECT  25.836 43.44 25.92 43.464 ;
    END
  END dst_d[217]
  PIN dst_d[218]
    DIRECTION OUTPUT ;
    USE SIGNAL ;
    PORT
      LAYER M4 ;
        RECT  25.836 43.632 25.92 43.656 ;
    END
  END dst_d[218]
  PIN dst_d[219]
    DIRECTION OUTPUT ;
    USE SIGNAL ;
    PORT
      LAYER M4 ;
        RECT  25.836 43.824 25.92 43.848 ;
    END
  END dst_d[219]
  PIN dst_d[21]
    DIRECTION OUTPUT ;
    USE SIGNAL ;
    PORT
      LAYER M4 ;
        RECT  25.836 6.528 25.92 6.552 ;
    END
  END dst_d[21]
  PIN dst_d[220]
    DIRECTION OUTPUT ;
    USE SIGNAL ;
    PORT
      LAYER M4 ;
        RECT  25.836 44.016 25.92 44.04 ;
    END
  END dst_d[220]
  PIN dst_d[221]
    DIRECTION OUTPUT ;
    USE SIGNAL ;
    PORT
      LAYER M4 ;
        RECT  25.836 44.208 25.92 44.232 ;
    END
  END dst_d[221]
  PIN dst_d[222]
    DIRECTION OUTPUT ;
    USE SIGNAL ;
    PORT
      LAYER M4 ;
        RECT  25.836 44.4 25.92 44.424 ;
    END
  END dst_d[222]
  PIN dst_d[223]
    DIRECTION OUTPUT ;
    USE SIGNAL ;
    PORT
      LAYER M4 ;
        RECT  25.836 44.592 25.92 44.616 ;
    END
  END dst_d[223]
  PIN dst_d[224]
    DIRECTION OUTPUT ;
    USE SIGNAL ;
    PORT
      LAYER M4 ;
        RECT  25.836 44.784 25.92 44.808 ;
    END
  END dst_d[224]
  PIN dst_d[225]
    DIRECTION OUTPUT ;
    USE SIGNAL ;
    PORT
      LAYER M4 ;
        RECT  25.836 44.976 25.92 45 ;
    END
  END dst_d[225]
  PIN dst_d[226]
    DIRECTION OUTPUT ;
    USE SIGNAL ;
    PORT
      LAYER M4 ;
        RECT  25.836 45.168 25.92 45.192 ;
    END
  END dst_d[226]
  PIN dst_d[227]
    DIRECTION OUTPUT ;
    USE SIGNAL ;
    PORT
      LAYER M4 ;
        RECT  25.836 45.36 25.92 45.384 ;
    END
  END dst_d[227]
  PIN dst_d[228]
    DIRECTION OUTPUT ;
    USE SIGNAL ;
    PORT
      LAYER M4 ;
        RECT  25.836 45.552 25.92 45.576 ;
    END
  END dst_d[228]
  PIN dst_d[229]
    DIRECTION OUTPUT ;
    USE SIGNAL ;
    PORT
      LAYER M4 ;
        RECT  25.836 45.696 25.92 45.72 ;
    END
  END dst_d[229]
  PIN dst_d[22]
    DIRECTION OUTPUT ;
    USE SIGNAL ;
    PORT
      LAYER M4 ;
        RECT  25.836 6.72 25.92 6.744 ;
    END
  END dst_d[22]
  PIN dst_d[230]
    DIRECTION OUTPUT ;
    USE SIGNAL ;
    PORT
      LAYER M4 ;
        RECT  25.836 45.888 25.92 45.912 ;
    END
  END dst_d[230]
  PIN dst_d[231]
    DIRECTION OUTPUT ;
    USE SIGNAL ;
    PORT
      LAYER M4 ;
        RECT  25.836 46.08 25.92 46.104 ;
    END
  END dst_d[231]
  PIN dst_d[232]
    DIRECTION OUTPUT ;
    USE SIGNAL ;
    PORT
      LAYER M4 ;
        RECT  25.836 46.272 25.92 46.296 ;
    END
  END dst_d[232]
  PIN dst_d[233]
    DIRECTION OUTPUT ;
    USE SIGNAL ;
    PORT
      LAYER M4 ;
        RECT  25.836 46.464 25.92 46.488 ;
    END
  END dst_d[233]
  PIN dst_d[234]
    DIRECTION OUTPUT ;
    USE SIGNAL ;
    PORT
      LAYER M4 ;
        RECT  25.836 46.656 25.92 46.68 ;
    END
  END dst_d[234]
  PIN dst_d[235]
    DIRECTION OUTPUT ;
    USE SIGNAL ;
    PORT
      LAYER M4 ;
        RECT  25.836 46.848 25.92 46.872 ;
    END
  END dst_d[235]
  PIN dst_d[236]
    DIRECTION OUTPUT ;
    USE SIGNAL ;
    PORT
      LAYER M4 ;
        RECT  25.836 47.04 25.92 47.064 ;
    END
  END dst_d[236]
  PIN dst_d[237]
    DIRECTION OUTPUT ;
    USE SIGNAL ;
    PORT
      LAYER M4 ;
        RECT  25.836 47.232 25.92 47.256 ;
    END
  END dst_d[237]
  PIN dst_d[238]
    DIRECTION OUTPUT ;
    USE SIGNAL ;
    PORT
      LAYER M4 ;
        RECT  25.836 47.424 25.92 47.448 ;
    END
  END dst_d[238]
  PIN dst_d[239]
    DIRECTION OUTPUT ;
    USE SIGNAL ;
    PORT
      LAYER M4 ;
        RECT  25.836 47.616 25.92 47.64 ;
    END
  END dst_d[239]
  PIN dst_d[23]
    DIRECTION OUTPUT ;
    USE SIGNAL ;
    PORT
      LAYER M4 ;
        RECT  25.836 6.912 25.92 6.936 ;
    END
  END dst_d[23]
  PIN dst_d[240]
    DIRECTION OUTPUT ;
    USE SIGNAL ;
    PORT
      LAYER M4 ;
        RECT  25.836 47.808 25.92 47.832 ;
    END
  END dst_d[240]
  PIN dst_d[241]
    DIRECTION OUTPUT ;
    USE SIGNAL ;
    PORT
      LAYER M4 ;
        RECT  25.836 48 25.92 48.024 ;
    END
  END dst_d[241]
  PIN dst_d[242]
    DIRECTION OUTPUT ;
    USE SIGNAL ;
    PORT
      LAYER M4 ;
        RECT  25.836 48.144 25.92 48.168 ;
    END
  END dst_d[242]
  PIN dst_d[243]
    DIRECTION OUTPUT ;
    USE SIGNAL ;
    PORT
      LAYER M4 ;
        RECT  25.836 48.336 25.92 48.36 ;
    END
  END dst_d[243]
  PIN dst_d[244]
    DIRECTION OUTPUT ;
    USE SIGNAL ;
    PORT
      LAYER M4 ;
        RECT  25.836 48.528 25.92 48.552 ;
    END
  END dst_d[244]
  PIN dst_d[245]
    DIRECTION OUTPUT ;
    USE SIGNAL ;
    PORT
      LAYER M4 ;
        RECT  25.836 48.72 25.92 48.744 ;
    END
  END dst_d[245]
  PIN dst_d[246]
    DIRECTION OUTPUT ;
    USE SIGNAL ;
    PORT
      LAYER M4 ;
        RECT  25.836 48.912 25.92 48.936 ;
    END
  END dst_d[246]
  PIN dst_d[247]
    DIRECTION OUTPUT ;
    USE SIGNAL ;
    PORT
      LAYER M4 ;
        RECT  25.836 49.104 25.92 49.128 ;
    END
  END dst_d[247]
  PIN dst_d[248]
    DIRECTION OUTPUT ;
    USE SIGNAL ;
    PORT
      LAYER M4 ;
        RECT  25.836 49.296 25.92 49.32 ;
    END
  END dst_d[248]
  PIN dst_d[249]
    DIRECTION OUTPUT ;
    USE SIGNAL ;
    PORT
      LAYER M4 ;
        RECT  25.836 49.488 25.92 49.512 ;
    END
  END dst_d[249]
  PIN dst_d[24]
    DIRECTION OUTPUT ;
    USE SIGNAL ;
    PORT
      LAYER M4 ;
        RECT  25.836 7.104 25.92 7.128 ;
    END
  END dst_d[24]
  PIN dst_d[250]
    DIRECTION OUTPUT ;
    USE SIGNAL ;
    PORT
      LAYER M4 ;
        RECT  25.836 49.68 25.92 49.704 ;
    END
  END dst_d[250]
  PIN dst_d[251]
    DIRECTION OUTPUT ;
    USE SIGNAL ;
    PORT
      LAYER M4 ;
        RECT  25.836 49.872 25.92 49.896 ;
    END
  END dst_d[251]
  PIN dst_d[252]
    DIRECTION OUTPUT ;
    USE SIGNAL ;
    PORT
      LAYER M4 ;
        RECT  25.836 50.064 25.92 50.088 ;
    END
  END dst_d[252]
  PIN dst_d[253]
    DIRECTION OUTPUT ;
    USE SIGNAL ;
    PORT
      LAYER M4 ;
        RECT  25.836 50.256 25.92 50.28 ;
    END
  END dst_d[253]
  PIN dst_d[254]
    DIRECTION OUTPUT ;
    USE SIGNAL ;
    PORT
      LAYER M4 ;
        RECT  25.836 50.448 25.92 50.472 ;
    END
  END dst_d[254]
  PIN dst_d[255]
    DIRECTION OUTPUT ;
    USE SIGNAL ;
    PORT
      LAYER M4 ;
        RECT  25.836 50.592 25.92 50.616 ;
    END
  END dst_d[255]
  PIN dst_d[256]
    DIRECTION OUTPUT ;
    USE SIGNAL ;
    PORT
      LAYER M4 ;
        RECT  25.836 50.784 25.92 50.808 ;
    END
  END dst_d[256]
  PIN dst_d[257]
    DIRECTION OUTPUT ;
    USE SIGNAL ;
    PORT
      LAYER M4 ;
        RECT  25.836 50.976 25.92 51 ;
    END
  END dst_d[257]
  PIN dst_d[258]
    DIRECTION OUTPUT ;
    USE SIGNAL ;
    PORT
      LAYER M4 ;
        RECT  25.836 51.168 25.92 51.192 ;
    END
  END dst_d[258]
  PIN dst_d[259]
    DIRECTION OUTPUT ;
    USE SIGNAL ;
    PORT
      LAYER M4 ;
        RECT  25.836 51.36 25.92 51.384 ;
    END
  END dst_d[259]
  PIN dst_d[25]
    DIRECTION OUTPUT ;
    USE SIGNAL ;
    PORT
      LAYER M4 ;
        RECT  25.836 7.296 25.92 7.32 ;
    END
  END dst_d[25]
  PIN dst_d[260]
    DIRECTION OUTPUT ;
    USE SIGNAL ;
    PORT
      LAYER M4 ;
        RECT  25.836 51.552 25.92 51.576 ;
    END
  END dst_d[260]
  PIN dst_d[261]
    DIRECTION OUTPUT ;
    USE SIGNAL ;
    PORT
      LAYER M4 ;
        RECT  25.836 51.744 25.92 51.768 ;
    END
  END dst_d[261]
  PIN dst_d[262]
    DIRECTION OUTPUT ;
    USE SIGNAL ;
    PORT
      LAYER M4 ;
        RECT  25.836 51.936 25.92 51.96 ;
    END
  END dst_d[262]
  PIN dst_d[263]
    DIRECTION OUTPUT ;
    USE SIGNAL ;
    PORT
      LAYER M4 ;
        RECT  25.836 52.128 25.92 52.152 ;
    END
  END dst_d[263]
  PIN dst_d[264]
    DIRECTION OUTPUT ;
    USE SIGNAL ;
    PORT
      LAYER M4 ;
        RECT  25.836 52.32 25.92 52.344 ;
    END
  END dst_d[264]
  PIN dst_d[265]
    DIRECTION OUTPUT ;
    USE SIGNAL ;
    PORT
      LAYER M4 ;
        RECT  25.836 52.512 25.92 52.536 ;
    END
  END dst_d[265]
  PIN dst_d[266]
    DIRECTION OUTPUT ;
    USE SIGNAL ;
    PORT
      LAYER M4 ;
        RECT  25.836 52.704 25.92 52.728 ;
    END
  END dst_d[266]
  PIN dst_d[267]
    DIRECTION OUTPUT ;
    USE SIGNAL ;
    PORT
      LAYER M4 ;
        RECT  25.836 52.896 25.92 52.92 ;
    END
  END dst_d[267]
  PIN dst_d[268]
    DIRECTION OUTPUT ;
    USE SIGNAL ;
    PORT
      LAYER M4 ;
        RECT  25.836 53.04 25.92 53.064 ;
    END
  END dst_d[268]
  PIN dst_d[269]
    DIRECTION OUTPUT ;
    USE SIGNAL ;
    PORT
      LAYER M4 ;
        RECT  25.836 53.232 25.92 53.256 ;
    END
  END dst_d[269]
  PIN dst_d[26]
    DIRECTION OUTPUT ;
    USE SIGNAL ;
    PORT
      LAYER M4 ;
        RECT  25.836 7.488 25.92 7.512 ;
    END
  END dst_d[26]
  PIN dst_d[270]
    DIRECTION OUTPUT ;
    USE SIGNAL ;
    PORT
      LAYER M4 ;
        RECT  25.836 53.424 25.92 53.448 ;
    END
  END dst_d[270]
  PIN dst_d[271]
    DIRECTION OUTPUT ;
    USE SIGNAL ;
    PORT
      LAYER M4 ;
        RECT  25.836 53.616 25.92 53.64 ;
    END
  END dst_d[271]
  PIN dst_d[272]
    DIRECTION OUTPUT ;
    USE SIGNAL ;
    PORT
      LAYER M4 ;
        RECT  25.836 53.808 25.92 53.832 ;
    END
  END dst_d[272]
  PIN dst_d[273]
    DIRECTION OUTPUT ;
    USE SIGNAL ;
    PORT
      LAYER M4 ;
        RECT  25.836 54 25.92 54.024 ;
    END
  END dst_d[273]
  PIN dst_d[274]
    DIRECTION OUTPUT ;
    USE SIGNAL ;
    PORT
      LAYER M4 ;
        RECT  25.836 54.192 25.92 54.216 ;
    END
  END dst_d[274]
  PIN dst_d[275]
    DIRECTION OUTPUT ;
    USE SIGNAL ;
    PORT
      LAYER M4 ;
        RECT  25.836 54.384 25.92 54.408 ;
    END
  END dst_d[275]
  PIN dst_d[276]
    DIRECTION OUTPUT ;
    USE SIGNAL ;
    PORT
      LAYER M4 ;
        RECT  25.836 54.576 25.92 54.6 ;
    END
  END dst_d[276]
  PIN dst_d[277]
    DIRECTION OUTPUT ;
    USE SIGNAL ;
    PORT
      LAYER M4 ;
        RECT  25.836 54.768 25.92 54.792 ;
    END
  END dst_d[277]
  PIN dst_d[278]
    DIRECTION OUTPUT ;
    USE SIGNAL ;
    PORT
      LAYER M4 ;
        RECT  25.836 54.96 25.92 54.984 ;
    END
  END dst_d[278]
  PIN dst_d[279]
    DIRECTION OUTPUT ;
    USE SIGNAL ;
    PORT
      LAYER M4 ;
        RECT  25.836 55.152 25.92 55.176 ;
    END
  END dst_d[279]
  PIN dst_d[27]
    DIRECTION OUTPUT ;
    USE SIGNAL ;
    PORT
      LAYER M4 ;
        RECT  25.836 7.68 25.92 7.704 ;
    END
  END dst_d[27]
  PIN dst_d[280]
    DIRECTION OUTPUT ;
    USE SIGNAL ;
    PORT
      LAYER M4 ;
        RECT  25.836 55.344 25.92 55.368 ;
    END
  END dst_d[280]
  PIN dst_d[281]
    DIRECTION OUTPUT ;
    USE SIGNAL ;
    PORT
      LAYER M4 ;
        RECT  25.836 55.488 25.92 55.512 ;
    END
  END dst_d[281]
  PIN dst_d[282]
    DIRECTION OUTPUT ;
    USE SIGNAL ;
    PORT
      LAYER M4 ;
        RECT  25.836 55.68 25.92 55.704 ;
    END
  END dst_d[282]
  PIN dst_d[283]
    DIRECTION OUTPUT ;
    USE SIGNAL ;
    PORT
      LAYER M4 ;
        RECT  25.836 55.872 25.92 55.896 ;
    END
  END dst_d[283]
  PIN dst_d[284]
    DIRECTION OUTPUT ;
    USE SIGNAL ;
    PORT
      LAYER M4 ;
        RECT  25.836 56.064 25.92 56.088 ;
    END
  END dst_d[284]
  PIN dst_d[285]
    DIRECTION OUTPUT ;
    USE SIGNAL ;
    PORT
      LAYER M4 ;
        RECT  25.836 56.256 25.92 56.28 ;
    END
  END dst_d[285]
  PIN dst_d[286]
    DIRECTION OUTPUT ;
    USE SIGNAL ;
    PORT
      LAYER M4 ;
        RECT  25.836 56.448 25.92 56.472 ;
    END
  END dst_d[286]
  PIN dst_d[287]
    DIRECTION OUTPUT ;
    USE SIGNAL ;
    PORT
      LAYER M4 ;
        RECT  25.836 56.64 25.92 56.664 ;
    END
  END dst_d[287]
  PIN dst_d[288]
    DIRECTION OUTPUT ;
    USE SIGNAL ;
    PORT
      LAYER M4 ;
        RECT  25.836 56.832 25.92 56.856 ;
    END
  END dst_d[288]
  PIN dst_d[289]
    DIRECTION OUTPUT ;
    USE SIGNAL ;
    PORT
      LAYER M4 ;
        RECT  25.836 57.024 25.92 57.048 ;
    END
  END dst_d[289]
  PIN dst_d[28]
    DIRECTION OUTPUT ;
    USE SIGNAL ;
    PORT
      LAYER M4 ;
        RECT  25.836 7.872 25.92 7.896 ;
    END
  END dst_d[28]
  PIN dst_d[290]
    DIRECTION OUTPUT ;
    USE SIGNAL ;
    PORT
      LAYER M4 ;
        RECT  25.836 57.216 25.92 57.24 ;
    END
  END dst_d[290]
  PIN dst_d[291]
    DIRECTION OUTPUT ;
    USE SIGNAL ;
    PORT
      LAYER M4 ;
        RECT  25.836 57.408 25.92 57.432 ;
    END
  END dst_d[291]
  PIN dst_d[292]
    DIRECTION OUTPUT ;
    USE SIGNAL ;
    PORT
      LAYER M4 ;
        RECT  25.836 57.6 25.92 57.624 ;
    END
  END dst_d[292]
  PIN dst_d[293]
    DIRECTION OUTPUT ;
    USE SIGNAL ;
    PORT
      LAYER M4 ;
        RECT  25.836 57.792 25.92 57.816 ;
    END
  END dst_d[293]
  PIN dst_d[294]
    DIRECTION OUTPUT ;
    USE SIGNAL ;
    PORT
      LAYER M4 ;
        RECT  25.836 57.984 25.92 58.008 ;
    END
  END dst_d[294]
  PIN dst_d[295]
    DIRECTION OUTPUT ;
    USE SIGNAL ;
    PORT
      LAYER M4 ;
        RECT  25.836 58.128 25.92 58.152 ;
    END
  END dst_d[295]
  PIN dst_d[296]
    DIRECTION OUTPUT ;
    USE SIGNAL ;
    PORT
      LAYER M4 ;
        RECT  25.836 58.32 25.92 58.344 ;
    END
  END dst_d[296]
  PIN dst_d[297]
    DIRECTION OUTPUT ;
    USE SIGNAL ;
    PORT
      LAYER M4 ;
        RECT  25.836 58.512 25.92 58.536 ;
    END
  END dst_d[297]
  PIN dst_d[298]
    DIRECTION OUTPUT ;
    USE SIGNAL ;
    PORT
      LAYER M4 ;
        RECT  25.836 58.704 25.92 58.728 ;
    END
  END dst_d[298]
  PIN dst_d[299]
    DIRECTION OUTPUT ;
    USE SIGNAL ;
    PORT
      LAYER M4 ;
        RECT  25.836 58.896 25.92 58.92 ;
    END
  END dst_d[299]
  PIN dst_d[29]
    DIRECTION OUTPUT ;
    USE SIGNAL ;
    PORT
      LAYER M4 ;
        RECT  25.836 8.064 25.92 8.088 ;
    END
  END dst_d[29]
  PIN dst_d[2]
    DIRECTION OUTPUT ;
    USE SIGNAL ;
    PORT
      LAYER M4 ;
        RECT  25.836 2.976 25.92 3 ;
    END
  END dst_d[2]
  PIN dst_d[300]
    DIRECTION OUTPUT ;
    USE SIGNAL ;
    PORT
      LAYER M4 ;
        RECT  25.836 59.088 25.92 59.112 ;
    END
  END dst_d[300]
  PIN dst_d[301]
    DIRECTION OUTPUT ;
    USE SIGNAL ;
    PORT
      LAYER M4 ;
        RECT  25.836 59.28 25.92 59.304 ;
    END
  END dst_d[301]
  PIN dst_d[302]
    DIRECTION OUTPUT ;
    USE SIGNAL ;
    PORT
      LAYER M4 ;
        RECT  25.836 59.472 25.92 59.496 ;
    END
  END dst_d[302]
  PIN dst_d[303]
    DIRECTION OUTPUT ;
    USE SIGNAL ;
    PORT
      LAYER M4 ;
        RECT  25.836 59.664 25.92 59.688 ;
    END
  END dst_d[303]
  PIN dst_d[304]
    DIRECTION OUTPUT ;
    USE SIGNAL ;
    PORT
      LAYER M4 ;
        RECT  25.836 59.856 25.92 59.88 ;
    END
  END dst_d[304]
  PIN dst_d[305]
    DIRECTION OUTPUT ;
    USE SIGNAL ;
    PORT
      LAYER M4 ;
        RECT  25.836 60.048 25.92 60.072 ;
    END
  END dst_d[305]
  PIN dst_d[306]
    DIRECTION OUTPUT ;
    USE SIGNAL ;
    PORT
      LAYER M4 ;
        RECT  25.836 60.24 25.92 60.264 ;
    END
  END dst_d[306]
  PIN dst_d[307]
    DIRECTION OUTPUT ;
    USE SIGNAL ;
    PORT
      LAYER M4 ;
        RECT  25.836 60.432 25.92 60.456 ;
    END
  END dst_d[307]
  PIN dst_d[308]
    DIRECTION OUTPUT ;
    USE SIGNAL ;
    PORT
      LAYER M4 ;
        RECT  25.836 60.576 25.92 60.6 ;
    END
  END dst_d[308]
  PIN dst_d[309]
    DIRECTION OUTPUT ;
    USE SIGNAL ;
    PORT
      LAYER M4 ;
        RECT  25.836 60.768 25.92 60.792 ;
    END
  END dst_d[309]
  PIN dst_d[30]
    DIRECTION OUTPUT ;
    USE SIGNAL ;
    PORT
      LAYER M4 ;
        RECT  25.836 8.256 25.92 8.28 ;
    END
  END dst_d[30]
  PIN dst_d[310]
    DIRECTION OUTPUT ;
    USE SIGNAL ;
    PORT
      LAYER M4 ;
        RECT  25.836 60.96 25.92 60.984 ;
    END
  END dst_d[310]
  PIN dst_d[311]
    DIRECTION OUTPUT ;
    USE SIGNAL ;
    PORT
      LAYER M4 ;
        RECT  25.836 61.152 25.92 61.176 ;
    END
  END dst_d[311]
  PIN dst_d[312]
    DIRECTION OUTPUT ;
    USE SIGNAL ;
    PORT
      LAYER M4 ;
        RECT  25.836 61.344 25.92 61.368 ;
    END
  END dst_d[312]
  PIN dst_d[313]
    DIRECTION OUTPUT ;
    USE SIGNAL ;
    PORT
      LAYER M4 ;
        RECT  25.836 61.536 25.92 61.56 ;
    END
  END dst_d[313]
  PIN dst_d[314]
    DIRECTION OUTPUT ;
    USE SIGNAL ;
    PORT
      LAYER M4 ;
        RECT  25.836 61.728 25.92 61.752 ;
    END
  END dst_d[314]
  PIN dst_d[315]
    DIRECTION OUTPUT ;
    USE SIGNAL ;
    PORT
      LAYER M4 ;
        RECT  25.836 61.92 25.92 61.944 ;
    END
  END dst_d[315]
  PIN dst_d[316]
    DIRECTION OUTPUT ;
    USE SIGNAL ;
    PORT
      LAYER M4 ;
        RECT  25.836 62.112 25.92 62.136 ;
    END
  END dst_d[316]
  PIN dst_d[317]
    DIRECTION OUTPUT ;
    USE SIGNAL ;
    PORT
      LAYER M4 ;
        RECT  25.836 62.304 25.92 62.328 ;
    END
  END dst_d[317]
  PIN dst_d[318]
    DIRECTION OUTPUT ;
    USE SIGNAL ;
    PORT
      LAYER M4 ;
        RECT  25.836 62.496 25.92 62.52 ;
    END
  END dst_d[318]
  PIN dst_d[319]
    DIRECTION OUTPUT ;
    USE SIGNAL ;
    PORT
      LAYER M4 ;
        RECT  25.836 62.688 25.92 62.712 ;
    END
  END dst_d[319]
  PIN dst_d[31]
    DIRECTION OUTPUT ;
    USE SIGNAL ;
    PORT
      LAYER M4 ;
        RECT  25.836 8.4 25.92 8.424 ;
    END
  END dst_d[31]
  PIN dst_d[320]
    DIRECTION OUTPUT ;
    USE SIGNAL ;
    PORT
      LAYER M4 ;
        RECT  25.836 62.88 25.92 62.904 ;
    END
  END dst_d[320]
  PIN dst_d[321]
    DIRECTION OUTPUT ;
    USE SIGNAL ;
    PORT
      LAYER M4 ;
        RECT  25.836 63.024 25.92 63.048 ;
    END
  END dst_d[321]
  PIN dst_d[322]
    DIRECTION OUTPUT ;
    USE SIGNAL ;
    PORT
      LAYER M4 ;
        RECT  25.836 63.216 25.92 63.24 ;
    END
  END dst_d[322]
  PIN dst_d[323]
    DIRECTION OUTPUT ;
    USE SIGNAL ;
    PORT
      LAYER M4 ;
        RECT  25.836 63.408 25.92 63.432 ;
    END
  END dst_d[323]
  PIN dst_d[324]
    DIRECTION OUTPUT ;
    USE SIGNAL ;
    PORT
      LAYER M4 ;
        RECT  25.836 63.6 25.92 63.624 ;
    END
  END dst_d[324]
  PIN dst_d[325]
    DIRECTION OUTPUT ;
    USE SIGNAL ;
    PORT
      LAYER M4 ;
        RECT  25.836 63.792 25.92 63.816 ;
    END
  END dst_d[325]
  PIN dst_d[326]
    DIRECTION OUTPUT ;
    USE SIGNAL ;
    PORT
      LAYER M4 ;
        RECT  25.836 63.984 25.92 64.008 ;
    END
  END dst_d[326]
  PIN dst_d[327]
    DIRECTION OUTPUT ;
    USE SIGNAL ;
    PORT
      LAYER M4 ;
        RECT  25.836 64.176 25.92 64.2 ;
    END
  END dst_d[327]
  PIN dst_d[328]
    DIRECTION OUTPUT ;
    USE SIGNAL ;
    PORT
      LAYER M4 ;
        RECT  25.836 64.368 25.92 64.392 ;
    END
  END dst_d[328]
  PIN dst_d[329]
    DIRECTION OUTPUT ;
    USE SIGNAL ;
    PORT
      LAYER M4 ;
        RECT  25.836 64.56 25.92 64.584 ;
    END
  END dst_d[329]
  PIN dst_d[32]
    DIRECTION OUTPUT ;
    USE SIGNAL ;
    PORT
      LAYER M4 ;
        RECT  25.836 8.592 25.92 8.616 ;
    END
  END dst_d[32]
  PIN dst_d[330]
    DIRECTION OUTPUT ;
    USE SIGNAL ;
    PORT
      LAYER M4 ;
        RECT  25.836 64.752 25.92 64.776 ;
    END
  END dst_d[330]
  PIN dst_d[331]
    DIRECTION OUTPUT ;
    USE SIGNAL ;
    PORT
      LAYER M4 ;
        RECT  25.836 64.944 25.92 64.968 ;
    END
  END dst_d[331]
  PIN dst_d[332]
    DIRECTION OUTPUT ;
    USE SIGNAL ;
    PORT
      LAYER M4 ;
        RECT  25.836 65.136 25.92 65.16 ;
    END
  END dst_d[332]
  PIN dst_d[333]
    DIRECTION OUTPUT ;
    USE SIGNAL ;
    PORT
      LAYER M4 ;
        RECT  25.836 65.328 25.92 65.352 ;
    END
  END dst_d[333]
  PIN dst_d[334]
    DIRECTION OUTPUT ;
    USE SIGNAL ;
    PORT
      LAYER M4 ;
        RECT  25.836 65.472 25.92 65.496 ;
    END
  END dst_d[334]
  PIN dst_d[335]
    DIRECTION OUTPUT ;
    USE SIGNAL ;
    PORT
      LAYER M4 ;
        RECT  25.836 65.664 25.92 65.688 ;
    END
  END dst_d[335]
  PIN dst_d[336]
    DIRECTION OUTPUT ;
    USE SIGNAL ;
    PORT
      LAYER M4 ;
        RECT  25.836 65.856 25.92 65.88 ;
    END
  END dst_d[336]
  PIN dst_d[337]
    DIRECTION OUTPUT ;
    USE SIGNAL ;
    PORT
      LAYER M4 ;
        RECT  25.836 66.048 25.92 66.072 ;
    END
  END dst_d[337]
  PIN dst_d[338]
    DIRECTION OUTPUT ;
    USE SIGNAL ;
    PORT
      LAYER M4 ;
        RECT  25.836 66.24 25.92 66.264 ;
    END
  END dst_d[338]
  PIN dst_d[339]
    DIRECTION OUTPUT ;
    USE SIGNAL ;
    PORT
      LAYER M4 ;
        RECT  25.836 66.432 25.92 66.456 ;
    END
  END dst_d[339]
  PIN dst_d[33]
    DIRECTION OUTPUT ;
    USE SIGNAL ;
    PORT
      LAYER M4 ;
        RECT  25.836 8.784 25.92 8.808 ;
    END
  END dst_d[33]
  PIN dst_d[340]
    DIRECTION OUTPUT ;
    USE SIGNAL ;
    PORT
      LAYER M4 ;
        RECT  25.836 66.624 25.92 66.648 ;
    END
  END dst_d[340]
  PIN dst_d[341]
    DIRECTION OUTPUT ;
    USE SIGNAL ;
    PORT
      LAYER M4 ;
        RECT  25.836 66.816 25.92 66.84 ;
    END
  END dst_d[341]
  PIN dst_d[342]
    DIRECTION OUTPUT ;
    USE SIGNAL ;
    PORT
      LAYER M4 ;
        RECT  25.836 67.008 25.92 67.032 ;
    END
  END dst_d[342]
  PIN dst_d[343]
    DIRECTION OUTPUT ;
    USE SIGNAL ;
    PORT
      LAYER M4 ;
        RECT  25.836 67.2 25.92 67.224 ;
    END
  END dst_d[343]
  PIN dst_d[344]
    DIRECTION OUTPUT ;
    USE SIGNAL ;
    PORT
      LAYER M4 ;
        RECT  25.836 67.392 25.92 67.416 ;
    END
  END dst_d[344]
  PIN dst_d[345]
    DIRECTION OUTPUT ;
    USE SIGNAL ;
    PORT
      LAYER M4 ;
        RECT  25.836 67.584 25.92 67.608 ;
    END
  END dst_d[345]
  PIN dst_d[346]
    DIRECTION OUTPUT ;
    USE SIGNAL ;
    PORT
      LAYER M4 ;
        RECT  25.836 67.776 25.92 67.8 ;
    END
  END dst_d[346]
  PIN dst_d[347]
    DIRECTION OUTPUT ;
    USE SIGNAL ;
    PORT
      LAYER M4 ;
        RECT  25.836 67.92 25.92 67.944 ;
    END
  END dst_d[347]
  PIN dst_d[348]
    DIRECTION OUTPUT ;
    USE SIGNAL ;
    PORT
      LAYER M4 ;
        RECT  25.836 68.112 25.92 68.136 ;
    END
  END dst_d[348]
  PIN dst_d[349]
    DIRECTION OUTPUT ;
    USE SIGNAL ;
    PORT
      LAYER M4 ;
        RECT  25.836 68.304 25.92 68.328 ;
    END
  END dst_d[349]
  PIN dst_d[34]
    DIRECTION OUTPUT ;
    USE SIGNAL ;
    PORT
      LAYER M4 ;
        RECT  25.836 8.976 25.92 9 ;
    END
  END dst_d[34]
  PIN dst_d[350]
    DIRECTION OUTPUT ;
    USE SIGNAL ;
    PORT
      LAYER M4 ;
        RECT  25.836 68.496 25.92 68.52 ;
    END
  END dst_d[350]
  PIN dst_d[351]
    DIRECTION OUTPUT ;
    USE SIGNAL ;
    PORT
      LAYER M4 ;
        RECT  25.836 68.688 25.92 68.712 ;
    END
  END dst_d[351]
  PIN dst_d[352]
    DIRECTION OUTPUT ;
    USE SIGNAL ;
    PORT
      LAYER M4 ;
        RECT  25.836 68.88 25.92 68.904 ;
    END
  END dst_d[352]
  PIN dst_d[353]
    DIRECTION OUTPUT ;
    USE SIGNAL ;
    PORT
      LAYER M4 ;
        RECT  25.836 69.072 25.92 69.096 ;
    END
  END dst_d[353]
  PIN dst_d[354]
    DIRECTION OUTPUT ;
    USE SIGNAL ;
    PORT
      LAYER M4 ;
        RECT  25.836 69.264 25.92 69.288 ;
    END
  END dst_d[354]
  PIN dst_d[355]
    DIRECTION OUTPUT ;
    USE SIGNAL ;
    PORT
      LAYER M4 ;
        RECT  25.836 69.456 25.92 69.48 ;
    END
  END dst_d[355]
  PIN dst_d[356]
    DIRECTION OUTPUT ;
    USE SIGNAL ;
    PORT
      LAYER M4 ;
        RECT  25.836 69.648 25.92 69.672 ;
    END
  END dst_d[356]
  PIN dst_d[357]
    DIRECTION OUTPUT ;
    USE SIGNAL ;
    PORT
      LAYER M4 ;
        RECT  25.836 69.84 25.92 69.864 ;
    END
  END dst_d[357]
  PIN dst_d[358]
    DIRECTION OUTPUT ;
    USE SIGNAL ;
    PORT
      LAYER M4 ;
        RECT  25.836 70.032 25.92 70.056 ;
    END
  END dst_d[358]
  PIN dst_d[359]
    DIRECTION OUTPUT ;
    USE SIGNAL ;
    PORT
      LAYER M4 ;
        RECT  25.836 70.224 25.92 70.248 ;
    END
  END dst_d[359]
  PIN dst_d[35]
    DIRECTION OUTPUT ;
    USE SIGNAL ;
    PORT
      LAYER M4 ;
        RECT  25.836 9.168 25.92 9.192 ;
    END
  END dst_d[35]
  PIN dst_d[360]
    DIRECTION OUTPUT ;
    USE SIGNAL ;
    PORT
      LAYER M4 ;
        RECT  25.836 70.416 25.92 70.44 ;
    END
  END dst_d[360]
  PIN dst_d[361]
    DIRECTION OUTPUT ;
    USE SIGNAL ;
    PORT
      LAYER M4 ;
        RECT  25.836 70.56 25.92 70.584 ;
    END
  END dst_d[361]
  PIN dst_d[362]
    DIRECTION OUTPUT ;
    USE SIGNAL ;
    PORT
      LAYER M4 ;
        RECT  25.836 70.752 25.92 70.776 ;
    END
  END dst_d[362]
  PIN dst_d[363]
    DIRECTION OUTPUT ;
    USE SIGNAL ;
    PORT
      LAYER M4 ;
        RECT  25.836 70.944 25.92 70.968 ;
    END
  END dst_d[363]
  PIN dst_d[364]
    DIRECTION OUTPUT ;
    USE SIGNAL ;
    PORT
      LAYER M4 ;
        RECT  25.836 71.136 25.92 71.16 ;
    END
  END dst_d[364]
  PIN dst_d[365]
    DIRECTION OUTPUT ;
    USE SIGNAL ;
    PORT
      LAYER M4 ;
        RECT  25.836 71.328 25.92 71.352 ;
    END
  END dst_d[365]
  PIN dst_d[366]
    DIRECTION OUTPUT ;
    USE SIGNAL ;
    PORT
      LAYER M4 ;
        RECT  25.836 71.52 25.92 71.544 ;
    END
  END dst_d[366]
  PIN dst_d[367]
    DIRECTION OUTPUT ;
    USE SIGNAL ;
    PORT
      LAYER M4 ;
        RECT  25.836 71.712 25.92 71.736 ;
    END
  END dst_d[367]
  PIN dst_d[368]
    DIRECTION OUTPUT ;
    USE SIGNAL ;
    PORT
      LAYER M4 ;
        RECT  25.836 71.904 25.92 71.928 ;
    END
  END dst_d[368]
  PIN dst_d[369]
    DIRECTION OUTPUT ;
    USE SIGNAL ;
    PORT
      LAYER M4 ;
        RECT  25.836 72.096 25.92 72.12 ;
    END
  END dst_d[369]
  PIN dst_d[36]
    DIRECTION OUTPUT ;
    USE SIGNAL ;
    PORT
      LAYER M4 ;
        RECT  25.836 9.36 25.92 9.384 ;
    END
  END dst_d[36]
  PIN dst_d[370]
    DIRECTION OUTPUT ;
    USE SIGNAL ;
    PORT
      LAYER M4 ;
        RECT  25.836 72.288 25.92 72.312 ;
    END
  END dst_d[370]
  PIN dst_d[371]
    DIRECTION OUTPUT ;
    USE SIGNAL ;
    PORT
      LAYER M4 ;
        RECT  25.836 72.48 25.92 72.504 ;
    END
  END dst_d[371]
  PIN dst_d[372]
    DIRECTION OUTPUT ;
    USE SIGNAL ;
    PORT
      LAYER M4 ;
        RECT  25.836 72.672 25.92 72.696 ;
    END
  END dst_d[372]
  PIN dst_d[373]
    DIRECTION OUTPUT ;
    USE SIGNAL ;
    PORT
      LAYER M4 ;
        RECT  25.836 72.864 25.92 72.888 ;
    END
  END dst_d[373]
  PIN dst_d[374]
    DIRECTION OUTPUT ;
    USE SIGNAL ;
    PORT
      LAYER M4 ;
        RECT  25.836 73.008 25.92 73.032 ;
    END
  END dst_d[374]
  PIN dst_d[375]
    DIRECTION OUTPUT ;
    USE SIGNAL ;
    PORT
      LAYER M4 ;
        RECT  25.836 73.2 25.92 73.224 ;
    END
  END dst_d[375]
  PIN dst_d[376]
    DIRECTION OUTPUT ;
    USE SIGNAL ;
    PORT
      LAYER M4 ;
        RECT  25.836 73.392 25.92 73.416 ;
    END
  END dst_d[376]
  PIN dst_d[377]
    DIRECTION OUTPUT ;
    USE SIGNAL ;
    PORT
      LAYER M4 ;
        RECT  25.836 73.584 25.92 73.608 ;
    END
  END dst_d[377]
  PIN dst_d[378]
    DIRECTION OUTPUT ;
    USE SIGNAL ;
    PORT
      LAYER M4 ;
        RECT  25.836 73.776 25.92 73.8 ;
    END
  END dst_d[378]
  PIN dst_d[379]
    DIRECTION OUTPUT ;
    USE SIGNAL ;
    PORT
      LAYER M4 ;
        RECT  25.836 73.968 25.92 73.992 ;
    END
  END dst_d[379]
  PIN dst_d[37]
    DIRECTION OUTPUT ;
    USE SIGNAL ;
    PORT
      LAYER M4 ;
        RECT  25.836 9.552 25.92 9.576 ;
    END
  END dst_d[37]
  PIN dst_d[380]
    DIRECTION OUTPUT ;
    USE SIGNAL ;
    PORT
      LAYER M4 ;
        RECT  25.836 74.16 25.92 74.184 ;
    END
  END dst_d[380]
  PIN dst_d[381]
    DIRECTION OUTPUT ;
    USE SIGNAL ;
    PORT
      LAYER M4 ;
        RECT  25.836 74.352 25.92 74.376 ;
    END
  END dst_d[381]
  PIN dst_d[382]
    DIRECTION OUTPUT ;
    USE SIGNAL ;
    PORT
      LAYER M4 ;
        RECT  25.836 74.544 25.92 74.568 ;
    END
  END dst_d[382]
  PIN dst_d[383]
    DIRECTION OUTPUT ;
    USE SIGNAL ;
    PORT
      LAYER M4 ;
        RECT  25.836 74.736 25.92 74.76 ;
    END
  END dst_d[383]
  PIN dst_d[384]
    DIRECTION OUTPUT ;
    USE SIGNAL ;
    PORT
      LAYER M4 ;
        RECT  25.836 74.928 25.92 74.952 ;
    END
  END dst_d[384]
  PIN dst_d[385]
    DIRECTION OUTPUT ;
    USE SIGNAL ;
    PORT
      LAYER M4 ;
        RECT  25.836 75.12 25.92 75.144 ;
    END
  END dst_d[385]
  PIN dst_d[386]
    DIRECTION OUTPUT ;
    USE SIGNAL ;
    PORT
      LAYER M4 ;
        RECT  25.836 75.312 25.92 75.336 ;
    END
  END dst_d[386]
  PIN dst_d[387]
    DIRECTION OUTPUT ;
    USE SIGNAL ;
    PORT
      LAYER M4 ;
        RECT  25.836 75.456 25.92 75.48 ;
    END
  END dst_d[387]
  PIN dst_d[388]
    DIRECTION OUTPUT ;
    USE SIGNAL ;
    PORT
      LAYER M4 ;
        RECT  25.836 75.648 25.92 75.672 ;
    END
  END dst_d[388]
  PIN dst_d[389]
    DIRECTION OUTPUT ;
    USE SIGNAL ;
    PORT
      LAYER M4 ;
        RECT  25.836 75.84 25.92 75.864 ;
    END
  END dst_d[389]
  PIN dst_d[38]
    DIRECTION OUTPUT ;
    USE SIGNAL ;
    PORT
      LAYER M4 ;
        RECT  25.836 9.744 25.92 9.768 ;
    END
  END dst_d[38]
  PIN dst_d[390]
    DIRECTION OUTPUT ;
    USE SIGNAL ;
    PORT
      LAYER M4 ;
        RECT  25.836 76.032 25.92 76.056 ;
    END
  END dst_d[390]
  PIN dst_d[391]
    DIRECTION OUTPUT ;
    USE SIGNAL ;
    PORT
      LAYER M4 ;
        RECT  25.836 76.224 25.92 76.248 ;
    END
  END dst_d[391]
  PIN dst_d[392]
    DIRECTION OUTPUT ;
    USE SIGNAL ;
    PORT
      LAYER M4 ;
        RECT  25.836 76.416 25.92 76.44 ;
    END
  END dst_d[392]
  PIN dst_d[393]
    DIRECTION OUTPUT ;
    USE SIGNAL ;
    PORT
      LAYER M4 ;
        RECT  25.836 76.608 25.92 76.632 ;
    END
  END dst_d[393]
  PIN dst_d[394]
    DIRECTION OUTPUT ;
    USE SIGNAL ;
    PORT
      LAYER M4 ;
        RECT  25.836 76.8 25.92 76.824 ;
    END
  END dst_d[394]
  PIN dst_d[395]
    DIRECTION OUTPUT ;
    USE SIGNAL ;
    PORT
      LAYER M4 ;
        RECT  25.836 76.992 25.92 77.016 ;
    END
  END dst_d[395]
  PIN dst_d[396]
    DIRECTION OUTPUT ;
    USE SIGNAL ;
    PORT
      LAYER M4 ;
        RECT  25.836 77.184 25.92 77.208 ;
    END
  END dst_d[396]
  PIN dst_d[397]
    DIRECTION OUTPUT ;
    USE SIGNAL ;
    PORT
      LAYER M4 ;
        RECT  25.836 77.376 25.92 77.4 ;
    END
  END dst_d[397]
  PIN dst_d[398]
    DIRECTION OUTPUT ;
    USE SIGNAL ;
    PORT
      LAYER M4 ;
        RECT  25.836 77.568 25.92 77.592 ;
    END
  END dst_d[398]
  PIN dst_d[399]
    DIRECTION OUTPUT ;
    USE SIGNAL ;
    PORT
      LAYER M4 ;
        RECT  25.836 77.76 25.92 77.784 ;
    END
  END dst_d[399]
  PIN dst_d[39]
    DIRECTION OUTPUT ;
    USE SIGNAL ;
    PORT
      LAYER M4 ;
        RECT  25.836 9.936 25.92 9.96 ;
    END
  END dst_d[39]
  PIN dst_d[3]
    DIRECTION OUTPUT ;
    USE SIGNAL ;
    PORT
      LAYER M4 ;
        RECT  25.836 3.168 25.92 3.192 ;
    END
  END dst_d[3]
  PIN dst_d[400]
    DIRECTION OUTPUT ;
    USE SIGNAL ;
    PORT
      LAYER M4 ;
        RECT  25.836 77.904 25.92 77.928 ;
    END
  END dst_d[400]
  PIN dst_d[401]
    DIRECTION OUTPUT ;
    USE SIGNAL ;
    PORT
      LAYER M4 ;
        RECT  25.836 78.096 25.92 78.12 ;
    END
  END dst_d[401]
  PIN dst_d[402]
    DIRECTION OUTPUT ;
    USE SIGNAL ;
    PORT
      LAYER M4 ;
        RECT  25.836 78.288 25.92 78.312 ;
    END
  END dst_d[402]
  PIN dst_d[403]
    DIRECTION OUTPUT ;
    USE SIGNAL ;
    PORT
      LAYER M4 ;
        RECT  25.836 78.48 25.92 78.504 ;
    END
  END dst_d[403]
  PIN dst_d[404]
    DIRECTION OUTPUT ;
    USE SIGNAL ;
    PORT
      LAYER M4 ;
        RECT  25.836 78.672 25.92 78.696 ;
    END
  END dst_d[404]
  PIN dst_d[405]
    DIRECTION OUTPUT ;
    USE SIGNAL ;
    PORT
      LAYER M4 ;
        RECT  25.836 78.864 25.92 78.888 ;
    END
  END dst_d[405]
  PIN dst_d[406]
    DIRECTION OUTPUT ;
    USE SIGNAL ;
    PORT
      LAYER M4 ;
        RECT  25.836 79.056 25.92 79.08 ;
    END
  END dst_d[406]
  PIN dst_d[407]
    DIRECTION OUTPUT ;
    USE SIGNAL ;
    PORT
      LAYER M4 ;
        RECT  25.836 79.248 25.92 79.272 ;
    END
  END dst_d[407]
  PIN dst_d[408]
    DIRECTION OUTPUT ;
    USE SIGNAL ;
    PORT
      LAYER M4 ;
        RECT  25.836 79.44 25.92 79.464 ;
    END
  END dst_d[408]
  PIN dst_d[409]
    DIRECTION OUTPUT ;
    USE SIGNAL ;
    PORT
      LAYER M4 ;
        RECT  25.836 79.632 25.92 79.656 ;
    END
  END dst_d[409]
  PIN dst_d[40]
    DIRECTION OUTPUT ;
    USE SIGNAL ;
    PORT
      LAYER M4 ;
        RECT  25.836 10.128 25.92 10.152 ;
    END
  END dst_d[40]
  PIN dst_d[410]
    DIRECTION OUTPUT ;
    USE SIGNAL ;
    PORT
      LAYER M4 ;
        RECT  25.836 79.824 25.92 79.848 ;
    END
  END dst_d[410]
  PIN dst_d[411]
    DIRECTION OUTPUT ;
    USE SIGNAL ;
    PORT
      LAYER M4 ;
        RECT  25.836 80.016 25.92 80.04 ;
    END
  END dst_d[411]
  PIN dst_d[412]
    DIRECTION OUTPUT ;
    USE SIGNAL ;
    PORT
      LAYER M4 ;
        RECT  25.836 80.208 25.92 80.232 ;
    END
  END dst_d[412]
  PIN dst_d[413]
    DIRECTION OUTPUT ;
    USE SIGNAL ;
    PORT
      LAYER M4 ;
        RECT  25.836 80.352 25.92 80.376 ;
    END
  END dst_d[413]
  PIN dst_d[414]
    DIRECTION OUTPUT ;
    USE SIGNAL ;
    PORT
      LAYER M4 ;
        RECT  25.836 80.544 25.92 80.568 ;
    END
  END dst_d[414]
  PIN dst_d[415]
    DIRECTION OUTPUT ;
    USE SIGNAL ;
    PORT
      LAYER M4 ;
        RECT  25.836 80.736 25.92 80.76 ;
    END
  END dst_d[415]
  PIN dst_d[416]
    DIRECTION OUTPUT ;
    USE SIGNAL ;
    PORT
      LAYER M4 ;
        RECT  25.836 80.928 25.92 80.952 ;
    END
  END dst_d[416]
  PIN dst_d[417]
    DIRECTION OUTPUT ;
    USE SIGNAL ;
    PORT
      LAYER M4 ;
        RECT  25.836 81.12 25.92 81.144 ;
    END
  END dst_d[417]
  PIN dst_d[418]
    DIRECTION OUTPUT ;
    USE SIGNAL ;
    PORT
      LAYER M4 ;
        RECT  25.836 81.312 25.92 81.336 ;
    END
  END dst_d[418]
  PIN dst_d[419]
    DIRECTION OUTPUT ;
    USE SIGNAL ;
    PORT
      LAYER M4 ;
        RECT  25.836 81.504 25.92 81.528 ;
    END
  END dst_d[419]
  PIN dst_d[41]
    DIRECTION OUTPUT ;
    USE SIGNAL ;
    PORT
      LAYER M4 ;
        RECT  25.836 10.32 25.92 10.344 ;
    END
  END dst_d[41]
  PIN dst_d[420]
    DIRECTION OUTPUT ;
    USE SIGNAL ;
    PORT
      LAYER M4 ;
        RECT  25.836 81.696 25.92 81.72 ;
    END
  END dst_d[420]
  PIN dst_d[421]
    DIRECTION OUTPUT ;
    USE SIGNAL ;
    PORT
      LAYER M4 ;
        RECT  25.836 81.888 25.92 81.912 ;
    END
  END dst_d[421]
  PIN dst_d[422]
    DIRECTION OUTPUT ;
    USE SIGNAL ;
    PORT
      LAYER M4 ;
        RECT  25.836 82.08 25.92 82.104 ;
    END
  END dst_d[422]
  PIN dst_d[423]
    DIRECTION OUTPUT ;
    USE SIGNAL ;
    PORT
      LAYER M4 ;
        RECT  25.836 82.272 25.92 82.296 ;
    END
  END dst_d[423]
  PIN dst_d[424]
    DIRECTION OUTPUT ;
    USE SIGNAL ;
    PORT
      LAYER M4 ;
        RECT  25.836 82.464 25.92 82.488 ;
    END
  END dst_d[424]
  PIN dst_d[425]
    DIRECTION OUTPUT ;
    USE SIGNAL ;
    PORT
      LAYER M4 ;
        RECT  25.836 82.656 25.92 82.68 ;
    END
  END dst_d[425]
  PIN dst_d[426]
    DIRECTION OUTPUT ;
    USE SIGNAL ;
    PORT
      LAYER M4 ;
        RECT  25.836 82.8 25.92 82.824 ;
    END
  END dst_d[426]
  PIN dst_d[427]
    DIRECTION OUTPUT ;
    USE SIGNAL ;
    PORT
      LAYER M4 ;
        RECT  25.836 82.992 25.92 83.016 ;
    END
  END dst_d[427]
  PIN dst_d[428]
    DIRECTION OUTPUT ;
    USE SIGNAL ;
    PORT
      LAYER M4 ;
        RECT  25.836 83.184 25.92 83.208 ;
    END
  END dst_d[428]
  PIN dst_d[429]
    DIRECTION OUTPUT ;
    USE SIGNAL ;
    PORT
      LAYER M4 ;
        RECT  25.836 83.376 25.92 83.4 ;
    END
  END dst_d[429]
  PIN dst_d[42]
    DIRECTION OUTPUT ;
    USE SIGNAL ;
    PORT
      LAYER M4 ;
        RECT  25.836 10.512 25.92 10.536 ;
    END
  END dst_d[42]
  PIN dst_d[430]
    DIRECTION OUTPUT ;
    USE SIGNAL ;
    PORT
      LAYER M4 ;
        RECT  25.836 83.568 25.92 83.592 ;
    END
  END dst_d[430]
  PIN dst_d[431]
    DIRECTION OUTPUT ;
    USE SIGNAL ;
    PORT
      LAYER M4 ;
        RECT  25.836 83.76 25.92 83.784 ;
    END
  END dst_d[431]
  PIN dst_d[432]
    DIRECTION OUTPUT ;
    USE SIGNAL ;
    PORT
      LAYER M4 ;
        RECT  25.836 83.952 25.92 83.976 ;
    END
  END dst_d[432]
  PIN dst_d[433]
    DIRECTION OUTPUT ;
    USE SIGNAL ;
    PORT
      LAYER M4 ;
        RECT  25.836 84.144 25.92 84.168 ;
    END
  END dst_d[433]
  PIN dst_d[434]
    DIRECTION OUTPUT ;
    USE SIGNAL ;
    PORT
      LAYER M4 ;
        RECT  25.836 84.336 25.92 84.36 ;
    END
  END dst_d[434]
  PIN dst_d[435]
    DIRECTION OUTPUT ;
    USE SIGNAL ;
    PORT
      LAYER M4 ;
        RECT  25.836 84.528 25.92 84.552 ;
    END
  END dst_d[435]
  PIN dst_d[436]
    DIRECTION OUTPUT ;
    USE SIGNAL ;
    PORT
      LAYER M4 ;
        RECT  25.836 84.72 25.92 84.744 ;
    END
  END dst_d[436]
  PIN dst_d[437]
    DIRECTION OUTPUT ;
    USE SIGNAL ;
    PORT
      LAYER M4 ;
        RECT  25.836 84.912 25.92 84.936 ;
    END
  END dst_d[437]
  PIN dst_d[438]
    DIRECTION OUTPUT ;
    USE SIGNAL ;
    PORT
      LAYER M4 ;
        RECT  25.836 85.104 25.92 85.128 ;
    END
  END dst_d[438]
  PIN dst_d[439]
    DIRECTION OUTPUT ;
    USE SIGNAL ;
    PORT
      LAYER M4 ;
        RECT  25.836 85.296 25.92 85.32 ;
    END
  END dst_d[439]
  PIN dst_d[43]
    DIRECTION OUTPUT ;
    USE SIGNAL ;
    PORT
      LAYER M4 ;
        RECT  25.836 10.704 25.92 10.728 ;
    END
  END dst_d[43]
  PIN dst_d[440]
    DIRECTION OUTPUT ;
    USE SIGNAL ;
    PORT
      LAYER M4 ;
        RECT  25.836 85.44 25.92 85.464 ;
    END
  END dst_d[440]
  PIN dst_d[441]
    DIRECTION OUTPUT ;
    USE SIGNAL ;
    PORT
      LAYER M4 ;
        RECT  25.836 85.632 25.92 85.656 ;
    END
  END dst_d[441]
  PIN dst_d[442]
    DIRECTION OUTPUT ;
    USE SIGNAL ;
    PORT
      LAYER M4 ;
        RECT  25.836 85.824 25.92 85.848 ;
    END
  END dst_d[442]
  PIN dst_d[443]
    DIRECTION OUTPUT ;
    USE SIGNAL ;
    PORT
      LAYER M4 ;
        RECT  25.836 86.016 25.92 86.04 ;
    END
  END dst_d[443]
  PIN dst_d[444]
    DIRECTION OUTPUT ;
    USE SIGNAL ;
    PORT
      LAYER M4 ;
        RECT  25.836 86.208 25.92 86.232 ;
    END
  END dst_d[444]
  PIN dst_d[445]
    DIRECTION OUTPUT ;
    USE SIGNAL ;
    PORT
      LAYER M4 ;
        RECT  25.836 86.4 25.92 86.424 ;
    END
  END dst_d[445]
  PIN dst_d[446]
    DIRECTION OUTPUT ;
    USE SIGNAL ;
    PORT
      LAYER M4 ;
        RECT  25.836 86.592 25.92 86.616 ;
    END
  END dst_d[446]
  PIN dst_d[447]
    DIRECTION OUTPUT ;
    USE SIGNAL ;
    PORT
      LAYER M4 ;
        RECT  25.836 86.784 25.92 86.808 ;
    END
  END dst_d[447]
  PIN dst_d[448]
    DIRECTION OUTPUT ;
    USE SIGNAL ;
    PORT
      LAYER M4 ;
        RECT  25.836 86.976 25.92 87 ;
    END
  END dst_d[448]
  PIN dst_d[449]
    DIRECTION OUTPUT ;
    USE SIGNAL ;
    PORT
      LAYER M4 ;
        RECT  25.836 87.168 25.92 87.192 ;
    END
  END dst_d[449]
  PIN dst_d[44]
    DIRECTION OUTPUT ;
    USE SIGNAL ;
    PORT
      LAYER M4 ;
        RECT  25.836 10.848 25.92 10.872 ;
    END
  END dst_d[44]
  PIN dst_d[450]
    DIRECTION OUTPUT ;
    USE SIGNAL ;
    PORT
      LAYER M4 ;
        RECT  25.836 87.36 25.92 87.384 ;
    END
  END dst_d[450]
  PIN dst_d[451]
    DIRECTION OUTPUT ;
    USE SIGNAL ;
    PORT
      LAYER M4 ;
        RECT  25.836 87.552 25.92 87.576 ;
    END
  END dst_d[451]
  PIN dst_d[452]
    DIRECTION OUTPUT ;
    USE SIGNAL ;
    PORT
      LAYER M4 ;
        RECT  25.836 87.744 25.92 87.768 ;
    END
  END dst_d[452]
  PIN dst_d[453]
    DIRECTION OUTPUT ;
    USE SIGNAL ;
    PORT
      LAYER M4 ;
        RECT  25.836 87.888 25.92 87.912 ;
    END
  END dst_d[453]
  PIN dst_d[454]
    DIRECTION OUTPUT ;
    USE SIGNAL ;
    PORT
      LAYER M4 ;
        RECT  25.836 88.08 25.92 88.104 ;
    END
  END dst_d[454]
  PIN dst_d[455]
    DIRECTION OUTPUT ;
    USE SIGNAL ;
    PORT
      LAYER M4 ;
        RECT  25.836 88.272 25.92 88.296 ;
    END
  END dst_d[455]
  PIN dst_d[456]
    DIRECTION OUTPUT ;
    USE SIGNAL ;
    PORT
      LAYER M4 ;
        RECT  25.836 88.464 25.92 88.488 ;
    END
  END dst_d[456]
  PIN dst_d[457]
    DIRECTION OUTPUT ;
    USE SIGNAL ;
    PORT
      LAYER M4 ;
        RECT  25.836 88.656 25.92 88.68 ;
    END
  END dst_d[457]
  PIN dst_d[458]
    DIRECTION OUTPUT ;
    USE SIGNAL ;
    PORT
      LAYER M4 ;
        RECT  25.836 88.848 25.92 88.872 ;
    END
  END dst_d[458]
  PIN dst_d[459]
    DIRECTION OUTPUT ;
    USE SIGNAL ;
    PORT
      LAYER M4 ;
        RECT  25.836 89.04 25.92 89.064 ;
    END
  END dst_d[459]
  PIN dst_d[45]
    DIRECTION OUTPUT ;
    USE SIGNAL ;
    PORT
      LAYER M4 ;
        RECT  25.836 11.04 25.92 11.064 ;
    END
  END dst_d[45]
  PIN dst_d[460]
    DIRECTION OUTPUT ;
    USE SIGNAL ;
    PORT
      LAYER M4 ;
        RECT  25.836 89.232 25.92 89.256 ;
    END
  END dst_d[460]
  PIN dst_d[461]
    DIRECTION OUTPUT ;
    USE SIGNAL ;
    PORT
      LAYER M4 ;
        RECT  25.836 89.424 25.92 89.448 ;
    END
  END dst_d[461]
  PIN dst_d[462]
    DIRECTION OUTPUT ;
    USE SIGNAL ;
    PORT
      LAYER M4 ;
        RECT  25.836 89.616 25.92 89.64 ;
    END
  END dst_d[462]
  PIN dst_d[463]
    DIRECTION OUTPUT ;
    USE SIGNAL ;
    PORT
      LAYER M4 ;
        RECT  25.836 89.808 25.92 89.832 ;
    END
  END dst_d[463]
  PIN dst_d[464]
    DIRECTION OUTPUT ;
    USE SIGNAL ;
    PORT
      LAYER M4 ;
        RECT  25.836 90 25.92 90.024 ;
    END
  END dst_d[464]
  PIN dst_d[465]
    DIRECTION OUTPUT ;
    USE SIGNAL ;
    PORT
      LAYER M4 ;
        RECT  25.836 90.192 25.92 90.216 ;
    END
  END dst_d[465]
  PIN dst_d[466]
    DIRECTION OUTPUT ;
    USE SIGNAL ;
    PORT
      LAYER M4 ;
        RECT  25.836 90.336 25.92 90.36 ;
    END
  END dst_d[466]
  PIN dst_d[467]
    DIRECTION OUTPUT ;
    USE SIGNAL ;
    PORT
      LAYER M4 ;
        RECT  25.836 90.528 25.92 90.552 ;
    END
  END dst_d[467]
  PIN dst_d[468]
    DIRECTION OUTPUT ;
    USE SIGNAL ;
    PORT
      LAYER M4 ;
        RECT  25.836 90.72 25.92 90.744 ;
    END
  END dst_d[468]
  PIN dst_d[469]
    DIRECTION OUTPUT ;
    USE SIGNAL ;
    PORT
      LAYER M4 ;
        RECT  25.836 90.912 25.92 90.936 ;
    END
  END dst_d[469]
  PIN dst_d[46]
    DIRECTION OUTPUT ;
    USE SIGNAL ;
    PORT
      LAYER M4 ;
        RECT  25.836 11.232 25.92 11.256 ;
    END
  END dst_d[46]
  PIN dst_d[470]
    DIRECTION OUTPUT ;
    USE SIGNAL ;
    PORT
      LAYER M4 ;
        RECT  25.836 91.104 25.92 91.128 ;
    END
  END dst_d[470]
  PIN dst_d[471]
    DIRECTION OUTPUT ;
    USE SIGNAL ;
    PORT
      LAYER M4 ;
        RECT  25.836 91.296 25.92 91.32 ;
    END
  END dst_d[471]
  PIN dst_d[472]
    DIRECTION OUTPUT ;
    USE SIGNAL ;
    PORT
      LAYER M4 ;
        RECT  25.836 91.488 25.92 91.512 ;
    END
  END dst_d[472]
  PIN dst_d[473]
    DIRECTION OUTPUT ;
    USE SIGNAL ;
    PORT
      LAYER M4 ;
        RECT  25.836 91.68 25.92 91.704 ;
    END
  END dst_d[473]
  PIN dst_d[474]
    DIRECTION OUTPUT ;
    USE SIGNAL ;
    PORT
      LAYER M4 ;
        RECT  25.836 91.872 25.92 91.896 ;
    END
  END dst_d[474]
  PIN dst_d[475]
    DIRECTION OUTPUT ;
    USE SIGNAL ;
    PORT
      LAYER M4 ;
        RECT  25.836 92.064 25.92 92.088 ;
    END
  END dst_d[475]
  PIN dst_d[476]
    DIRECTION OUTPUT ;
    USE SIGNAL ;
    PORT
      LAYER M4 ;
        RECT  25.836 92.256 25.92 92.28 ;
    END
  END dst_d[476]
  PIN dst_d[477]
    DIRECTION OUTPUT ;
    USE SIGNAL ;
    PORT
      LAYER M4 ;
        RECT  25.836 92.448 25.92 92.472 ;
    END
  END dst_d[477]
  PIN dst_d[478]
    DIRECTION OUTPUT ;
    USE SIGNAL ;
    PORT
      LAYER M4 ;
        RECT  25.836 92.64 25.92 92.664 ;
    END
  END dst_d[478]
  PIN dst_d[479]
    DIRECTION OUTPUT ;
    USE SIGNAL ;
    PORT
      LAYER M4 ;
        RECT  25.836 92.784 25.92 92.808 ;
    END
  END dst_d[479]
  PIN dst_d[47]
    DIRECTION OUTPUT ;
    USE SIGNAL ;
    PORT
      LAYER M4 ;
        RECT  25.836 11.424 25.92 11.448 ;
    END
  END dst_d[47]
  PIN dst_d[480]
    DIRECTION OUTPUT ;
    USE SIGNAL ;
    PORT
      LAYER M4 ;
        RECT  25.836 92.976 25.92 93 ;
    END
  END dst_d[480]
  PIN dst_d[481]
    DIRECTION OUTPUT ;
    USE SIGNAL ;
    PORT
      LAYER M4 ;
        RECT  25.836 93.168 25.92 93.192 ;
    END
  END dst_d[481]
  PIN dst_d[482]
    DIRECTION OUTPUT ;
    USE SIGNAL ;
    PORT
      LAYER M4 ;
        RECT  25.836 93.36 25.92 93.384 ;
    END
  END dst_d[482]
  PIN dst_d[483]
    DIRECTION OUTPUT ;
    USE SIGNAL ;
    PORT
      LAYER M4 ;
        RECT  25.836 93.552 25.92 93.576 ;
    END
  END dst_d[483]
  PIN dst_d[484]
    DIRECTION OUTPUT ;
    USE SIGNAL ;
    PORT
      LAYER M4 ;
        RECT  25.836 93.744 25.92 93.768 ;
    END
  END dst_d[484]
  PIN dst_d[485]
    DIRECTION OUTPUT ;
    USE SIGNAL ;
    PORT
      LAYER M4 ;
        RECT  25.836 93.936 25.92 93.96 ;
    END
  END dst_d[485]
  PIN dst_d[486]
    DIRECTION OUTPUT ;
    USE SIGNAL ;
    PORT
      LAYER M4 ;
        RECT  25.836 94.128 25.92 94.152 ;
    END
  END dst_d[486]
  PIN dst_d[487]
    DIRECTION OUTPUT ;
    USE SIGNAL ;
    PORT
      LAYER M4 ;
        RECT  25.836 94.32 25.92 94.344 ;
    END
  END dst_d[487]
  PIN dst_d[488]
    DIRECTION OUTPUT ;
    USE SIGNAL ;
    PORT
      LAYER M4 ;
        RECT  25.836 94.512 25.92 94.536 ;
    END
  END dst_d[488]
  PIN dst_d[489]
    DIRECTION OUTPUT ;
    USE SIGNAL ;
    PORT
      LAYER M4 ;
        RECT  25.836 94.704 25.92 94.728 ;
    END
  END dst_d[489]
  PIN dst_d[48]
    DIRECTION OUTPUT ;
    USE SIGNAL ;
    PORT
      LAYER M4 ;
        RECT  25.836 11.616 25.92 11.64 ;
    END
  END dst_d[48]
  PIN dst_d[490]
    DIRECTION OUTPUT ;
    USE SIGNAL ;
    PORT
      LAYER M4 ;
        RECT  25.836 94.896 25.92 94.92 ;
    END
  END dst_d[490]
  PIN dst_d[491]
    DIRECTION OUTPUT ;
    USE SIGNAL ;
    PORT
      LAYER M4 ;
        RECT  25.836 95.088 25.92 95.112 ;
    END
  END dst_d[491]
  PIN dst_d[492]
    DIRECTION OUTPUT ;
    USE SIGNAL ;
    PORT
      LAYER M4 ;
        RECT  25.836 95.232 25.92 95.256 ;
    END
  END dst_d[492]
  PIN dst_d[493]
    DIRECTION OUTPUT ;
    USE SIGNAL ;
    PORT
      LAYER M4 ;
        RECT  25.836 95.424 25.92 95.448 ;
    END
  END dst_d[493]
  PIN dst_d[494]
    DIRECTION OUTPUT ;
    USE SIGNAL ;
    PORT
      LAYER M4 ;
        RECT  25.836 95.616 25.92 95.64 ;
    END
  END dst_d[494]
  PIN dst_d[495]
    DIRECTION OUTPUT ;
    USE SIGNAL ;
    PORT
      LAYER M4 ;
        RECT  25.836 95.808 25.92 95.832 ;
    END
  END dst_d[495]
  PIN dst_d[496]
    DIRECTION OUTPUT ;
    USE SIGNAL ;
    PORT
      LAYER M4 ;
        RECT  25.836 96 25.92 96.024 ;
    END
  END dst_d[496]
  PIN dst_d[497]
    DIRECTION OUTPUT ;
    USE SIGNAL ;
    PORT
      LAYER M4 ;
        RECT  25.836 96.192 25.92 96.216 ;
    END
  END dst_d[497]
  PIN dst_d[498]
    DIRECTION OUTPUT ;
    USE SIGNAL ;
    PORT
      LAYER M4 ;
        RECT  25.836 96.384 25.92 96.408 ;
    END
  END dst_d[498]
  PIN dst_d[499]
    DIRECTION OUTPUT ;
    USE SIGNAL ;
    PORT
      LAYER M4 ;
        RECT  25.836 96.576 25.92 96.6 ;
    END
  END dst_d[499]
  PIN dst_d[49]
    DIRECTION OUTPUT ;
    USE SIGNAL ;
    PORT
      LAYER M4 ;
        RECT  25.836 11.808 25.92 11.832 ;
    END
  END dst_d[49]
  PIN dst_d[4]
    DIRECTION OUTPUT ;
    USE SIGNAL ;
    PORT
      LAYER M4 ;
        RECT  25.836 3.36 25.92 3.384 ;
    END
  END dst_d[4]
  PIN dst_d[500]
    DIRECTION OUTPUT ;
    USE SIGNAL ;
    PORT
      LAYER M4 ;
        RECT  25.836 96.768 25.92 96.792 ;
    END
  END dst_d[500]
  PIN dst_d[501]
    DIRECTION OUTPUT ;
    USE SIGNAL ;
    PORT
      LAYER M4 ;
        RECT  25.836 96.96 25.92 96.984 ;
    END
  END dst_d[501]
  PIN dst_d[502]
    DIRECTION OUTPUT ;
    USE SIGNAL ;
    PORT
      LAYER M4 ;
        RECT  25.836 97.152 25.92 97.176 ;
    END
  END dst_d[502]
  PIN dst_d[503]
    DIRECTION OUTPUT ;
    USE SIGNAL ;
    PORT
      LAYER M4 ;
        RECT  25.836 97.344 25.92 97.368 ;
    END
  END dst_d[503]
  PIN dst_d[504]
    DIRECTION OUTPUT ;
    USE SIGNAL ;
    PORT
      LAYER M4 ;
        RECT  25.836 97.536 25.92 97.56 ;
    END
  END dst_d[504]
  PIN dst_d[505]
    DIRECTION OUTPUT ;
    USE SIGNAL ;
    PORT
      LAYER M4 ;
        RECT  25.836 97.728 25.92 97.752 ;
    END
  END dst_d[505]
  PIN dst_d[506]
    DIRECTION OUTPUT ;
    USE SIGNAL ;
    PORT
      LAYER M4 ;
        RECT  25.836 97.872 25.92 97.896 ;
    END
  END dst_d[506]
  PIN dst_d[507]
    DIRECTION OUTPUT ;
    USE SIGNAL ;
    PORT
      LAYER M4 ;
        RECT  25.836 98.064 25.92 98.088 ;
    END
  END dst_d[507]
  PIN dst_d[508]
    DIRECTION OUTPUT ;
    USE SIGNAL ;
    PORT
      LAYER M4 ;
        RECT  25.836 98.256 25.92 98.28 ;
    END
  END dst_d[508]
  PIN dst_d[509]
    DIRECTION OUTPUT ;
    USE SIGNAL ;
    PORT
      LAYER M4 ;
        RECT  25.836 98.448 25.92 98.472 ;
    END
  END dst_d[509]
  PIN dst_d[50]
    DIRECTION OUTPUT ;
    USE SIGNAL ;
    PORT
      LAYER M4 ;
        RECT  25.836 12 25.92 12.024 ;
    END
  END dst_d[50]
  PIN dst_d[510]
    DIRECTION OUTPUT ;
    USE SIGNAL ;
    PORT
      LAYER M4 ;
        RECT  25.836 98.64 25.92 98.664 ;
    END
  END dst_d[510]
  PIN dst_d[511]
    DIRECTION OUTPUT ;
    USE SIGNAL ;
    PORT
      LAYER M4 ;
        RECT  25.836 98.832 25.92 98.856 ;
    END
  END dst_d[511]
  PIN dst_d[51]
    DIRECTION OUTPUT ;
    USE SIGNAL ;
    PORT
      LAYER M4 ;
        RECT  25.836 12.192 25.92 12.216 ;
    END
  END dst_d[51]
  PIN dst_d[52]
    DIRECTION OUTPUT ;
    USE SIGNAL ;
    PORT
      LAYER M4 ;
        RECT  25.836 12.384 25.92 12.408 ;
    END
  END dst_d[52]
  PIN dst_d[53]
    DIRECTION OUTPUT ;
    USE SIGNAL ;
    PORT
      LAYER M4 ;
        RECT  25.836 12.576 25.92 12.6 ;
    END
  END dst_d[53]
  PIN dst_d[54]
    DIRECTION OUTPUT ;
    USE SIGNAL ;
    PORT
      LAYER M4 ;
        RECT  25.836 12.768 25.92 12.792 ;
    END
  END dst_d[54]
  PIN dst_d[55]
    DIRECTION OUTPUT ;
    USE SIGNAL ;
    PORT
      LAYER M4 ;
        RECT  25.836 12.96 25.92 12.984 ;
    END
  END dst_d[55]
  PIN dst_d[56]
    DIRECTION OUTPUT ;
    USE SIGNAL ;
    PORT
      LAYER M4 ;
        RECT  25.836 13.152 25.92 13.176 ;
    END
  END dst_d[56]
  PIN dst_d[57]
    DIRECTION OUTPUT ;
    USE SIGNAL ;
    PORT
      LAYER M4 ;
        RECT  25.836 13.296 25.92 13.32 ;
    END
  END dst_d[57]
  PIN dst_d[58]
    DIRECTION OUTPUT ;
    USE SIGNAL ;
    PORT
      LAYER M4 ;
        RECT  25.836 13.488 25.92 13.512 ;
    END
  END dst_d[58]
  PIN dst_d[59]
    DIRECTION OUTPUT ;
    USE SIGNAL ;
    PORT
      LAYER M4 ;
        RECT  25.836 13.68 25.92 13.704 ;
    END
  END dst_d[59]
  PIN dst_d[5]
    DIRECTION OUTPUT ;
    USE SIGNAL ;
    PORT
      LAYER M4 ;
        RECT  25.836 3.504 25.92 3.528 ;
    END
  END dst_d[5]
  PIN dst_d[60]
    DIRECTION OUTPUT ;
    USE SIGNAL ;
    PORT
      LAYER M4 ;
        RECT  25.836 13.872 25.92 13.896 ;
    END
  END dst_d[60]
  PIN dst_d[61]
    DIRECTION OUTPUT ;
    USE SIGNAL ;
    PORT
      LAYER M4 ;
        RECT  25.836 14.064 25.92 14.088 ;
    END
  END dst_d[61]
  PIN dst_d[62]
    DIRECTION OUTPUT ;
    USE SIGNAL ;
    PORT
      LAYER M4 ;
        RECT  25.836 14.256 25.92 14.28 ;
    END
  END dst_d[62]
  PIN dst_d[63]
    DIRECTION OUTPUT ;
    USE SIGNAL ;
    PORT
      LAYER M4 ;
        RECT  25.836 14.448 25.92 14.472 ;
    END
  END dst_d[63]
  PIN dst_d[64]
    DIRECTION OUTPUT ;
    USE SIGNAL ;
    PORT
      LAYER M4 ;
        RECT  25.836 14.64 25.92 14.664 ;
    END
  END dst_d[64]
  PIN dst_d[65]
    DIRECTION OUTPUT ;
    USE SIGNAL ;
    PORT
      LAYER M4 ;
        RECT  25.836 14.832 25.92 14.856 ;
    END
  END dst_d[65]
  PIN dst_d[66]
    DIRECTION OUTPUT ;
    USE SIGNAL ;
    PORT
      LAYER M4 ;
        RECT  25.836 15.024 25.92 15.048 ;
    END
  END dst_d[66]
  PIN dst_d[67]
    DIRECTION OUTPUT ;
    USE SIGNAL ;
    PORT
      LAYER M4 ;
        RECT  25.836 15.216 25.92 15.24 ;
    END
  END dst_d[67]
  PIN dst_d[68]
    DIRECTION OUTPUT ;
    USE SIGNAL ;
    PORT
      LAYER M4 ;
        RECT  25.836 15.408 25.92 15.432 ;
    END
  END dst_d[68]
  PIN dst_d[69]
    DIRECTION OUTPUT ;
    USE SIGNAL ;
    PORT
      LAYER M4 ;
        RECT  25.836 15.6 25.92 15.624 ;
    END
  END dst_d[69]
  PIN dst_d[6]
    DIRECTION OUTPUT ;
    USE SIGNAL ;
    PORT
      LAYER M4 ;
        RECT  25.836 3.696 25.92 3.72 ;
    END
  END dst_d[6]
  PIN dst_d[70]
    DIRECTION OUTPUT ;
    USE SIGNAL ;
    PORT
      LAYER M4 ;
        RECT  25.836 15.744 25.92 15.768 ;
    END
  END dst_d[70]
  PIN dst_d[71]
    DIRECTION OUTPUT ;
    USE SIGNAL ;
    PORT
      LAYER M4 ;
        RECT  25.836 15.936 25.92 15.96 ;
    END
  END dst_d[71]
  PIN dst_d[72]
    DIRECTION OUTPUT ;
    USE SIGNAL ;
    PORT
      LAYER M4 ;
        RECT  25.836 16.128 25.92 16.152 ;
    END
  END dst_d[72]
  PIN dst_d[73]
    DIRECTION OUTPUT ;
    USE SIGNAL ;
    PORT
      LAYER M4 ;
        RECT  25.836 16.32 25.92 16.344 ;
    END
  END dst_d[73]
  PIN dst_d[74]
    DIRECTION OUTPUT ;
    USE SIGNAL ;
    PORT
      LAYER M4 ;
        RECT  25.836 16.512 25.92 16.536 ;
    END
  END dst_d[74]
  PIN dst_d[75]
    DIRECTION OUTPUT ;
    USE SIGNAL ;
    PORT
      LAYER M4 ;
        RECT  25.836 16.704 25.92 16.728 ;
    END
  END dst_d[75]
  PIN dst_d[76]
    DIRECTION OUTPUT ;
    USE SIGNAL ;
    PORT
      LAYER M4 ;
        RECT  25.836 16.896 25.92 16.92 ;
    END
  END dst_d[76]
  PIN dst_d[77]
    DIRECTION OUTPUT ;
    USE SIGNAL ;
    PORT
      LAYER M4 ;
        RECT  25.836 17.088 25.92 17.112 ;
    END
  END dst_d[77]
  PIN dst_d[78]
    DIRECTION OUTPUT ;
    USE SIGNAL ;
    PORT
      LAYER M4 ;
        RECT  25.836 17.28 25.92 17.304 ;
    END
  END dst_d[78]
  PIN dst_d[79]
    DIRECTION OUTPUT ;
    USE SIGNAL ;
    PORT
      LAYER M4 ;
        RECT  25.836 17.472 25.92 17.496 ;
    END
  END dst_d[79]
  PIN dst_d[7]
    DIRECTION OUTPUT ;
    USE SIGNAL ;
    PORT
      LAYER M4 ;
        RECT  25.836 3.888 25.92 3.912 ;
    END
  END dst_d[7]
  PIN dst_d[80]
    DIRECTION OUTPUT ;
    USE SIGNAL ;
    PORT
      LAYER M4 ;
        RECT  25.836 17.664 25.92 17.688 ;
    END
  END dst_d[80]
  PIN dst_d[81]
    DIRECTION OUTPUT ;
    USE SIGNAL ;
    PORT
      LAYER M4 ;
        RECT  25.836 17.856 25.92 17.88 ;
    END
  END dst_d[81]
  PIN dst_d[82]
    DIRECTION OUTPUT ;
    USE SIGNAL ;
    PORT
      LAYER M4 ;
        RECT  25.836 18.048 25.92 18.072 ;
    END
  END dst_d[82]
  PIN dst_d[83]
    DIRECTION OUTPUT ;
    USE SIGNAL ;
    PORT
      LAYER M4 ;
        RECT  25.836 18.24 25.92 18.264 ;
    END
  END dst_d[83]
  PIN dst_d[84]
    DIRECTION OUTPUT ;
    USE SIGNAL ;
    PORT
      LAYER M4 ;
        RECT  25.836 18.384 25.92 18.408 ;
    END
  END dst_d[84]
  PIN dst_d[85]
    DIRECTION OUTPUT ;
    USE SIGNAL ;
    PORT
      LAYER M4 ;
        RECT  25.836 18.576 25.92 18.6 ;
    END
  END dst_d[85]
  PIN dst_d[86]
    DIRECTION OUTPUT ;
    USE SIGNAL ;
    PORT
      LAYER M4 ;
        RECT  25.836 18.768 25.92 18.792 ;
    END
  END dst_d[86]
  PIN dst_d[87]
    DIRECTION OUTPUT ;
    USE SIGNAL ;
    PORT
      LAYER M4 ;
        RECT  25.836 18.96 25.92 18.984 ;
    END
  END dst_d[87]
  PIN dst_d[88]
    DIRECTION OUTPUT ;
    USE SIGNAL ;
    PORT
      LAYER M4 ;
        RECT  25.836 19.152 25.92 19.176 ;
    END
  END dst_d[88]
  PIN dst_d[89]
    DIRECTION OUTPUT ;
    USE SIGNAL ;
    PORT
      LAYER M4 ;
        RECT  25.836 19.344 25.92 19.368 ;
    END
  END dst_d[89]
  PIN dst_d[8]
    DIRECTION OUTPUT ;
    USE SIGNAL ;
    PORT
      LAYER M4 ;
        RECT  25.836 4.08 25.92 4.104 ;
    END
  END dst_d[8]
  PIN dst_d[90]
    DIRECTION OUTPUT ;
    USE SIGNAL ;
    PORT
      LAYER M4 ;
        RECT  25.836 19.536 25.92 19.56 ;
    END
  END dst_d[90]
  PIN dst_d[91]
    DIRECTION OUTPUT ;
    USE SIGNAL ;
    PORT
      LAYER M4 ;
        RECT  25.836 19.728 25.92 19.752 ;
    END
  END dst_d[91]
  PIN dst_d[92]
    DIRECTION OUTPUT ;
    USE SIGNAL ;
    PORT
      LAYER M4 ;
        RECT  25.836 19.92 25.92 19.944 ;
    END
  END dst_d[92]
  PIN dst_d[93]
    DIRECTION OUTPUT ;
    USE SIGNAL ;
    PORT
      LAYER M4 ;
        RECT  25.836 20.112 25.92 20.136 ;
    END
  END dst_d[93]
  PIN dst_d[94]
    DIRECTION OUTPUT ;
    USE SIGNAL ;
    PORT
      LAYER M4 ;
        RECT  25.836 20.304 25.92 20.328 ;
    END
  END dst_d[94]
  PIN dst_d[95]
    DIRECTION OUTPUT ;
    USE SIGNAL ;
    PORT
      LAYER M4 ;
        RECT  25.836 20.496 25.92 20.52 ;
    END
  END dst_d[95]
  PIN dst_d[96]
    DIRECTION OUTPUT ;
    USE SIGNAL ;
    PORT
      LAYER M4 ;
        RECT  25.836 20.688 25.92 20.712 ;
    END
  END dst_d[96]
  PIN dst_d[97]
    DIRECTION OUTPUT ;
    USE SIGNAL ;
    PORT
      LAYER M4 ;
        RECT  25.836 20.832 25.92 20.856 ;
    END
  END dst_d[97]
  PIN dst_d[98]
    DIRECTION OUTPUT ;
    USE SIGNAL ;
    PORT
      LAYER M4 ;
        RECT  25.836 21.024 25.92 21.048 ;
    END
  END dst_d[98]
  PIN dst_d[99]
    DIRECTION OUTPUT ;
    USE SIGNAL ;
    PORT
      LAYER M4 ;
        RECT  25.836 21.216 25.92 21.24 ;
    END
  END dst_d[99]
  PIN dst_d[9]
    DIRECTION OUTPUT ;
    USE SIGNAL ;
    PORT
      LAYER M4 ;
        RECT  25.836 4.272 25.92 4.296 ;
    END
  END dst_d[9]
  PIN dst_v[0]
    DIRECTION OUTPUT ;
    USE SIGNAL ;
    PORT
      LAYER M4 ;
        RECT  25.836 99.264 25.92 99.288 ;
    END
  END dst_v[0]
  PIN dst_v[10]
    DIRECTION OUTPUT ;
    USE SIGNAL ;
    PORT
      LAYER M4 ;
        RECT  25.836 101.76 25.92 101.784 ;
    END
  END dst_v[10]
  PIN dst_v[11]
    DIRECTION OUTPUT ;
    USE SIGNAL ;
    PORT
      LAYER M4 ;
        RECT  25.836 102 25.92 102.024 ;
    END
  END dst_v[11]
  PIN dst_v[12]
    DIRECTION OUTPUT ;
    USE SIGNAL ;
    PORT
      LAYER M4 ;
        RECT  25.836 102.24 25.92 102.264 ;
    END
  END dst_v[12]
  PIN dst_v[13]
    DIRECTION OUTPUT ;
    USE SIGNAL ;
    PORT
      LAYER M4 ;
        RECT  25.836 102.48 25.92 102.504 ;
    END
  END dst_v[13]
  PIN dst_v[14]
    DIRECTION OUTPUT ;
    USE SIGNAL ;
    PORT
      LAYER M4 ;
        RECT  25.836 102.768 25.92 102.792 ;
    END
  END dst_v[14]
  PIN dst_v[15]
    DIRECTION OUTPUT ;
    USE SIGNAL ;
    PORT
      LAYER M4 ;
        RECT  25.836 103.008 25.92 103.032 ;
    END
  END dst_v[15]
  PIN dst_v[1]
    DIRECTION OUTPUT ;
    USE SIGNAL ;
    PORT
      LAYER M4 ;
        RECT  25.836 99.504 25.92 99.528 ;
    END
  END dst_v[1]
  PIN dst_v[2]
    DIRECTION OUTPUT ;
    USE SIGNAL ;
    PORT
      LAYER M4 ;
        RECT  25.836 99.744 25.92 99.768 ;
    END
  END dst_v[2]
  PIN dst_v[3]
    DIRECTION OUTPUT ;
    USE SIGNAL ;
    PORT
      LAYER M4 ;
        RECT  25.836 99.984 25.92 100.008 ;
    END
  END dst_v[3]
  PIN dst_v[4]
    DIRECTION OUTPUT ;
    USE SIGNAL ;
    PORT
      LAYER M4 ;
        RECT  25.836 100.272 25.92 100.296 ;
    END
  END dst_v[4]
  PIN dst_v[5]
    DIRECTION OUTPUT ;
    USE SIGNAL ;
    PORT
      LAYER M4 ;
        RECT  25.836 100.512 25.92 100.536 ;
    END
  END dst_v[5]
  PIN dst_v[6]
    DIRECTION OUTPUT ;
    USE SIGNAL ;
    PORT
      LAYER M4 ;
        RECT  25.836 100.752 25.92 100.776 ;
    END
  END dst_v[6]
  PIN dst_v[7]
    DIRECTION OUTPUT ;
    USE SIGNAL ;
    PORT
      LAYER M4 ;
        RECT  25.836 100.992 25.92 101.016 ;
    END
  END dst_v[7]
  PIN dst_v[8]
    DIRECTION OUTPUT ;
    USE SIGNAL ;
    PORT
      LAYER M4 ;
        RECT  25.836 101.232 25.92 101.256 ;
    END
  END dst_v[8]
  PIN dst_v[9]
    DIRECTION OUTPUT ;
    USE SIGNAL ;
    PORT
      LAYER M4 ;
        RECT  25.836 101.52 25.92 101.544 ;
    END
  END dst_v[9]
  PIN rst_n
    DIRECTION INPUT ;
    USE SIGNAL ;
    PORT
      LAYER M5 ;
        RECT  22.08 105.756 22.104 105.84 ;
    END
  END rst_n
  PIN select_fault
    DIRECTION OUTPUT ;
    USE SIGNAL ;
    PORT
      LAYER M5 ;
        RECT  22.56 105.756 22.584 105.84 ;
    END
  END select_fault
  PIN sink_select[0]
    DIRECTION INPUT ;
    USE SIGNAL ;
    PORT
      LAYER M5 ;
        RECT  6.816 105.756 6.84 105.84 ;
    END
  END sink_select[0]
  PIN sink_select[10]
    DIRECTION INPUT ;
    USE SIGNAL ;
    PORT
      LAYER M5 ;
        RECT  9.072 105.756 9.096 105.84 ;
    END
  END sink_select[10]
  PIN sink_select[11]
    DIRECTION INPUT ;
    USE SIGNAL ;
    PORT
      LAYER M5 ;
        RECT  9.312 105.756 9.336 105.84 ;
    END
  END sink_select[11]
  PIN sink_select[12]
    DIRECTION INPUT ;
    USE SIGNAL ;
    PORT
      LAYER M5 ;
        RECT  9.504 105.756 9.528 105.84 ;
    END
  END sink_select[12]
  PIN sink_select[13]
    DIRECTION INPUT ;
    USE SIGNAL ;
    PORT
      LAYER M5 ;
        RECT  9.744 105.756 9.768 105.84 ;
    END
  END sink_select[13]
  PIN sink_select[14]
    DIRECTION INPUT ;
    USE SIGNAL ;
    PORT
      LAYER M5 ;
        RECT  9.984 105.756 10.008 105.84 ;
    END
  END sink_select[14]
  PIN sink_select[15]
    DIRECTION INPUT ;
    USE SIGNAL ;
    PORT
      LAYER M5 ;
        RECT  10.224 105.756 10.248 105.84 ;
    END
  END sink_select[15]
  PIN sink_select[16]
    DIRECTION INPUT ;
    USE SIGNAL ;
    PORT
      LAYER M5 ;
        RECT  10.416 105.756 10.44 105.84 ;
    END
  END sink_select[16]
  PIN sink_select[17]
    DIRECTION INPUT ;
    USE SIGNAL ;
    PORT
      LAYER M5 ;
        RECT  10.656 105.756 10.68 105.84 ;
    END
  END sink_select[17]
  PIN sink_select[18]
    DIRECTION INPUT ;
    USE SIGNAL ;
    PORT
      LAYER M5 ;
        RECT  10.896 105.756 10.92 105.84 ;
    END
  END sink_select[18]
  PIN sink_select[19]
    DIRECTION INPUT ;
    USE SIGNAL ;
    PORT
      LAYER M5 ;
        RECT  11.136 105.756 11.16 105.84 ;
    END
  END sink_select[19]
  PIN sink_select[1]
    DIRECTION INPUT ;
    USE SIGNAL ;
    PORT
      LAYER M5 ;
        RECT  7.008 105.756 7.032 105.84 ;
    END
  END sink_select[1]
  PIN sink_select[20]
    DIRECTION INPUT ;
    USE SIGNAL ;
    PORT
      LAYER M5 ;
        RECT  11.328 105.756 11.352 105.84 ;
    END
  END sink_select[20]
  PIN sink_select[21]
    DIRECTION INPUT ;
    USE SIGNAL ;
    PORT
      LAYER M5 ;
        RECT  11.568 105.756 11.592 105.84 ;
    END
  END sink_select[21]
  PIN sink_select[22]
    DIRECTION INPUT ;
    USE SIGNAL ;
    PORT
      LAYER M5 ;
        RECT  11.808 105.756 11.832 105.84 ;
    END
  END sink_select[22]
  PIN sink_select[23]
    DIRECTION INPUT ;
    USE SIGNAL ;
    PORT
      LAYER M5 ;
        RECT  12 105.756 12.024 105.84 ;
    END
  END sink_select[23]
  PIN sink_select[24]
    DIRECTION INPUT ;
    USE SIGNAL ;
    PORT
      LAYER M5 ;
        RECT  12.24 105.756 12.264 105.84 ;
    END
  END sink_select[24]
  PIN sink_select[25]
    DIRECTION INPUT ;
    USE SIGNAL ;
    PORT
      LAYER M5 ;
        RECT  12.48 105.756 12.504 105.84 ;
    END
  END sink_select[25]
  PIN sink_select[26]
    DIRECTION INPUT ;
    USE SIGNAL ;
    PORT
      LAYER M5 ;
        RECT  12.72 105.756 12.744 105.84 ;
    END
  END sink_select[26]
  PIN sink_select[27]
    DIRECTION INPUT ;
    USE SIGNAL ;
    PORT
      LAYER M5 ;
        RECT  12.912 105.756 12.936 105.84 ;
    END
  END sink_select[27]
  PIN sink_select[28]
    DIRECTION INPUT ;
    USE SIGNAL ;
    PORT
      LAYER M5 ;
        RECT  13.152 105.756 13.176 105.84 ;
    END
  END sink_select[28]
  PIN sink_select[29]
    DIRECTION INPUT ;
    USE SIGNAL ;
    PORT
      LAYER M5 ;
        RECT  13.392 105.756 13.416 105.84 ;
    END
  END sink_select[29]
  PIN sink_select[2]
    DIRECTION INPUT ;
    USE SIGNAL ;
    PORT
      LAYER M5 ;
        RECT  7.248 105.756 7.272 105.84 ;
    END
  END sink_select[2]
  PIN sink_select[30]
    DIRECTION INPUT ;
    USE SIGNAL ;
    PORT
      LAYER M5 ;
        RECT  13.632 105.756 13.656 105.84 ;
    END
  END sink_select[30]
  PIN sink_select[31]
    DIRECTION INPUT ;
    USE SIGNAL ;
    PORT
      LAYER M5 ;
        RECT  13.824 105.756 13.848 105.84 ;
    END
  END sink_select[31]
  PIN sink_select[32]
    DIRECTION INPUT ;
    USE SIGNAL ;
    PORT
      LAYER M5 ;
        RECT  14.064 105.756 14.088 105.84 ;
    END
  END sink_select[32]
  PIN sink_select[33]
    DIRECTION INPUT ;
    USE SIGNAL ;
    PORT
      LAYER M5 ;
        RECT  14.304 105.756 14.328 105.84 ;
    END
  END sink_select[33]
  PIN sink_select[34]
    DIRECTION INPUT ;
    USE SIGNAL ;
    PORT
      LAYER M5 ;
        RECT  14.496 105.756 14.52 105.84 ;
    END
  END sink_select[34]
  PIN sink_select[35]
    DIRECTION INPUT ;
    USE SIGNAL ;
    PORT
      LAYER M5 ;
        RECT  14.736 105.756 14.76 105.84 ;
    END
  END sink_select[35]
  PIN sink_select[36]
    DIRECTION INPUT ;
    USE SIGNAL ;
    PORT
      LAYER M5 ;
        RECT  14.976 105.756 15 105.84 ;
    END
  END sink_select[36]
  PIN sink_select[37]
    DIRECTION INPUT ;
    USE SIGNAL ;
    PORT
      LAYER M5 ;
        RECT  15.216 105.756 15.24 105.84 ;
    END
  END sink_select[37]
  PIN sink_select[38]
    DIRECTION INPUT ;
    USE SIGNAL ;
    PORT
      LAYER M5 ;
        RECT  15.408 105.756 15.432 105.84 ;
    END
  END sink_select[38]
  PIN sink_select[39]
    DIRECTION INPUT ;
    USE SIGNAL ;
    PORT
      LAYER M5 ;
        RECT  15.648 105.756 15.672 105.84 ;
    END
  END sink_select[39]
  PIN sink_select[3]
    DIRECTION INPUT ;
    USE SIGNAL ;
    PORT
      LAYER M5 ;
        RECT  7.488 105.756 7.512 105.84 ;
    END
  END sink_select[3]
  PIN sink_select[40]
    DIRECTION INPUT ;
    USE SIGNAL ;
    PORT
      LAYER M5 ;
        RECT  15.888 105.756 15.912 105.84 ;
    END
  END sink_select[40]
  PIN sink_select[41]
    DIRECTION INPUT ;
    USE SIGNAL ;
    PORT
      LAYER M5 ;
        RECT  16.08 105.756 16.104 105.84 ;
    END
  END sink_select[41]
  PIN sink_select[42]
    DIRECTION INPUT ;
    USE SIGNAL ;
    PORT
      LAYER M5 ;
        RECT  16.32 105.756 16.344 105.84 ;
    END
  END sink_select[42]
  PIN sink_select[43]
    DIRECTION INPUT ;
    USE SIGNAL ;
    PORT
      LAYER M5 ;
        RECT  16.56 105.756 16.584 105.84 ;
    END
  END sink_select[43]
  PIN sink_select[44]
    DIRECTION INPUT ;
    USE SIGNAL ;
    PORT
      LAYER M5 ;
        RECT  16.8 105.756 16.824 105.84 ;
    END
  END sink_select[44]
  PIN sink_select[45]
    DIRECTION INPUT ;
    USE SIGNAL ;
    PORT
      LAYER M5 ;
        RECT  16.992 105.756 17.016 105.84 ;
    END
  END sink_select[45]
  PIN sink_select[46]
    DIRECTION INPUT ;
    USE SIGNAL ;
    PORT
      LAYER M5 ;
        RECT  17.232 105.756 17.256 105.84 ;
    END
  END sink_select[46]
  PIN sink_select[47]
    DIRECTION INPUT ;
    USE SIGNAL ;
    PORT
      LAYER M5 ;
        RECT  17.472 105.756 17.496 105.84 ;
    END
  END sink_select[47]
  PIN sink_select[48]
    DIRECTION INPUT ;
    USE SIGNAL ;
    PORT
      LAYER M5 ;
        RECT  17.712 105.756 17.736 105.84 ;
    END
  END sink_select[48]
  PIN sink_select[49]
    DIRECTION INPUT ;
    USE SIGNAL ;
    PORT
      LAYER M5 ;
        RECT  17.904 105.756 17.928 105.84 ;
    END
  END sink_select[49]
  PIN sink_select[4]
    DIRECTION INPUT ;
    USE SIGNAL ;
    PORT
      LAYER M5 ;
        RECT  7.728 105.756 7.752 105.84 ;
    END
  END sink_select[4]
  PIN sink_select[50]
    DIRECTION INPUT ;
    USE SIGNAL ;
    PORT
      LAYER M5 ;
        RECT  18.144 105.756 18.168 105.84 ;
    END
  END sink_select[50]
  PIN sink_select[51]
    DIRECTION INPUT ;
    USE SIGNAL ;
    PORT
      LAYER M5 ;
        RECT  18.384 105.756 18.408 105.84 ;
    END
  END sink_select[51]
  PIN sink_select[52]
    DIRECTION INPUT ;
    USE SIGNAL ;
    PORT
      LAYER M5 ;
        RECT  18.576 105.756 18.6 105.84 ;
    END
  END sink_select[52]
  PIN sink_select[53]
    DIRECTION INPUT ;
    USE SIGNAL ;
    PORT
      LAYER M5 ;
        RECT  18.816 105.756 18.84 105.84 ;
    END
  END sink_select[53]
  PIN sink_select[54]
    DIRECTION INPUT ;
    USE SIGNAL ;
    PORT
      LAYER M5 ;
        RECT  19.056 105.756 19.08 105.84 ;
    END
  END sink_select[54]
  PIN sink_select[55]
    DIRECTION INPUT ;
    USE SIGNAL ;
    PORT
      LAYER M5 ;
        RECT  19.296 105.756 19.32 105.84 ;
    END
  END sink_select[55]
  PIN sink_select[56]
    DIRECTION INPUT ;
    USE SIGNAL ;
    PORT
      LAYER M5 ;
        RECT  19.488 105.756 19.512 105.84 ;
    END
  END sink_select[56]
  PIN sink_select[57]
    DIRECTION INPUT ;
    USE SIGNAL ;
    PORT
      LAYER M5 ;
        RECT  19.728 105.756 19.752 105.84 ;
    END
  END sink_select[57]
  PIN sink_select[58]
    DIRECTION INPUT ;
    USE SIGNAL ;
    PORT
      LAYER M5 ;
        RECT  19.968 105.756 19.992 105.84 ;
    END
  END sink_select[58]
  PIN sink_select[59]
    DIRECTION INPUT ;
    USE SIGNAL ;
    PORT
      LAYER M5 ;
        RECT  20.208 105.756 20.232 105.84 ;
    END
  END sink_select[59]
  PIN sink_select[5]
    DIRECTION INPUT ;
    USE SIGNAL ;
    PORT
      LAYER M5 ;
        RECT  7.92 105.756 7.944 105.84 ;
    END
  END sink_select[5]
  PIN sink_select[60]
    DIRECTION INPUT ;
    USE SIGNAL ;
    PORT
      LAYER M5 ;
        RECT  20.4 105.756 20.424 105.84 ;
    END
  END sink_select[60]
  PIN sink_select[61]
    DIRECTION INPUT ;
    USE SIGNAL ;
    PORT
      LAYER M5 ;
        RECT  20.64 105.756 20.664 105.84 ;
    END
  END sink_select[61]
  PIN sink_select[62]
    DIRECTION INPUT ;
    USE SIGNAL ;
    PORT
      LAYER M5 ;
        RECT  20.88 105.756 20.904 105.84 ;
    END
  END sink_select[62]
  PIN sink_select[63]
    DIRECTION INPUT ;
    USE SIGNAL ;
    PORT
      LAYER M5 ;
        RECT  21.072 105.756 21.096 105.84 ;
    END
  END sink_select[63]
  PIN sink_select[6]
    DIRECTION INPUT ;
    USE SIGNAL ;
    PORT
      LAYER M5 ;
        RECT  8.16 105.756 8.184 105.84 ;
    END
  END sink_select[6]
  PIN sink_select[7]
    DIRECTION INPUT ;
    USE SIGNAL ;
    PORT
      LAYER M5 ;
        RECT  8.4 105.756 8.424 105.84 ;
    END
  END sink_select[7]
  PIN sink_select[8]
    DIRECTION INPUT ;
    USE SIGNAL ;
    PORT
      LAYER M5 ;
        RECT  8.64 105.756 8.664 105.84 ;
    END
  END sink_select[8]
  PIN sink_select[9]
    DIRECTION INPUT ;
    USE SIGNAL ;
    PORT
      LAYER M5 ;
        RECT  8.832 105.756 8.856 105.84 ;
    END
  END sink_select[9]
  PIN sink_slot[0]
    DIRECTION INPUT ;
    USE SIGNAL ;
    PORT
      LAYER M5 ;
        RECT  2.592 105.756 2.616 105.84 ;
    END
  END sink_slot[0]
  PIN sink_slot[10]
    DIRECTION INPUT ;
    USE SIGNAL ;
    PORT
      LAYER M5 ;
        RECT  5.136 105.756 5.16 105.84 ;
    END
  END sink_slot[10]
  PIN sink_slot[11]
    DIRECTION INPUT ;
    USE SIGNAL ;
    PORT
      LAYER M5 ;
        RECT  5.376 105.756 5.4 105.84 ;
    END
  END sink_slot[11]
  PIN sink_slot[12]
    DIRECTION INPUT ;
    USE SIGNAL ;
    PORT
      LAYER M5 ;
        RECT  5.616 105.756 5.64 105.84 ;
    END
  END sink_slot[12]
  PIN sink_slot[13]
    DIRECTION INPUT ;
    USE SIGNAL ;
    PORT
      LAYER M5 ;
        RECT  5.856 105.756 5.88 105.84 ;
    END
  END sink_slot[13]
  PIN sink_slot[14]
    DIRECTION INPUT ;
    USE SIGNAL ;
    PORT
      LAYER M5 ;
        RECT  6.096 105.756 6.12 105.84 ;
    END
  END sink_slot[14]
  PIN sink_slot[15]
    DIRECTION INPUT ;
    USE SIGNAL ;
    PORT
      LAYER M5 ;
        RECT  6.384 105.756 6.408 105.84 ;
    END
  END sink_slot[15]
  PIN sink_slot[1]
    DIRECTION INPUT ;
    USE SIGNAL ;
    PORT
      LAYER M5 ;
        RECT  2.88 105.756 2.904 105.84 ;
    END
  END sink_slot[1]
  PIN sink_slot[2]
    DIRECTION INPUT ;
    USE SIGNAL ;
    PORT
      LAYER M5 ;
        RECT  3.12 105.756 3.144 105.84 ;
    END
  END sink_slot[2]
  PIN sink_slot[3]
    DIRECTION INPUT ;
    USE SIGNAL ;
    PORT
      LAYER M5 ;
        RECT  3.36 105.756 3.384 105.84 ;
    END
  END sink_slot[3]
  PIN sink_slot[4]
    DIRECTION INPUT ;
    USE SIGNAL ;
    PORT
      LAYER M5 ;
        RECT  3.6 105.756 3.624 105.84 ;
    END
  END sink_slot[4]
  PIN sink_slot[5]
    DIRECTION INPUT ;
    USE SIGNAL ;
    PORT
      LAYER M5 ;
        RECT  3.84 105.756 3.864 105.84 ;
    END
  END sink_slot[5]
  PIN sink_slot[6]
    DIRECTION INPUT ;
    USE SIGNAL ;
    PORT
      LAYER M5 ;
        RECT  4.128 105.756 4.152 105.84 ;
    END
  END sink_slot[6]
  PIN sink_slot[7]
    DIRECTION INPUT ;
    USE SIGNAL ;
    PORT
      LAYER M5 ;
        RECT  4.368 105.756 4.392 105.84 ;
    END
  END sink_slot[7]
  PIN sink_slot[8]
    DIRECTION INPUT ;
    USE SIGNAL ;
    PORT
      LAYER M5 ;
        RECT  4.608 105.756 4.632 105.84 ;
    END
  END sink_slot[8]
  PIN sink_slot[9]
    DIRECTION INPUT ;
    USE SIGNAL ;
    PORT
      LAYER M5 ;
        RECT  4.848 105.756 4.872 105.84 ;
    END
  END sink_slot[9]
  PIN unavailable_fault
    DIRECTION OUTPUT ;
    USE SIGNAL ;
    PORT
      LAYER M5 ;
        RECT  23.04 105.756 23.064 105.84 ;
    END
  END unavailable_fault
  PIN VDD
    DIRECTION INOUT ;
    USE POWER ;
    PORT
      LAYER M5 ;
        RECT  18.792 2.151 18.912 103.689 ;
        RECT  13.392 2.151 13.512 103.689 ;
        RECT  7.992 2.151 8.112 103.689 ;
        RECT  2.592 2.151 2.712 103.689 ;
    END
  END VDD
  PIN VSS
    DIRECTION INOUT ;
    USE GROUND ;
    PORT
      LAYER M5 ;
        RECT  18.6 2.137 18.72 103.703 ;
        RECT  13.2 2.137 13.32 103.703 ;
        RECT  7.8 2.137 7.92 103.703 ;
        RECT  2.4 2.137 2.52 103.703 ;
    END
  END VSS
  # OT_OBS_CLOSED layer=M5 d_um=1.536 added=55
  OBS
    LAYER RVTN ;
     RECT  2.16 2.16 23.76 2.295 ;
     RECT  2.16 2.565 23.76 2.835 ;
     RECT  2.16 3.105 23.76 3.375 ;
     RECT  2.16 3.645 23.76 3.915 ;
     RECT  2.16 4.185 23.76 4.455 ;
     RECT  2.16 4.725 23.76 4.995 ;
     RECT  2.16 5.265 23.76 5.535 ;
     RECT  2.16 5.805 23.76 6.075 ;
     RECT  2.16 6.345 23.76 6.615 ;
     RECT  2.16 6.885 23.76 7.155 ;
     RECT  2.16 7.425 23.76 7.695 ;
     RECT  2.16 7.965 23.76 8.235 ;
     RECT  2.16 8.505 23.76 8.775 ;
     RECT  2.16 9.045 23.76 9.315 ;
     RECT  2.16 9.585 23.76 9.855 ;
     RECT  2.16 10.125 23.76 10.395 ;
     RECT  2.16 10.665 23.76 10.935 ;
     RECT  2.16 11.205 23.76 11.475 ;
     RECT  2.16 11.745 23.76 12.015 ;
     RECT  2.16 12.285 23.76 12.555 ;
     RECT  2.16 12.825 23.76 13.095 ;
     RECT  2.16 13.365 23.76 13.635 ;
     RECT  2.16 13.905 23.76 14.175 ;
     RECT  2.16 14.445 23.76 14.715 ;
     RECT  2.16 14.985 23.76 15.255 ;
     RECT  2.16 15.525 23.76 15.795 ;
     RECT  2.16 16.065 23.76 16.335 ;
     RECT  2.16 16.605 23.76 16.875 ;
     RECT  2.16 17.145 23.76 17.415 ;
     RECT  2.16 17.685 23.76 17.955 ;
     RECT  2.16 18.225 23.76 18.495 ;
     RECT  2.16 18.765 23.76 19.035 ;
     RECT  2.16 19.305 23.76 19.575 ;
     RECT  2.16 19.845 23.76 20.115 ;
     RECT  2.16 20.385 23.76 20.655 ;
     RECT  2.16 20.925 23.76 21.195 ;
     RECT  2.16 21.465 23.76 21.735 ;
     RECT  2.16 22.005 23.76 22.275 ;
     RECT  2.16 22.545 23.76 22.815 ;
     RECT  2.16 23.085 23.76 23.355 ;
     RECT  2.16 23.625 23.76 23.895 ;
     RECT  2.16 24.165 23.76 24.435 ;
     RECT  2.16 24.705 23.76 24.975 ;
     RECT  2.16 25.245 23.76 25.515 ;
     RECT  2.16 25.785 23.76 26.055 ;
     RECT  2.16 26.325 23.76 26.595 ;
     RECT  2.16 26.865 23.76 27.135 ;
     RECT  2.16 27.405 23.76 27.675 ;
     RECT  2.16 27.945 23.76 28.215 ;
     RECT  2.16 28.485 23.76 28.755 ;
     RECT  2.16 29.025 23.76 29.295 ;
     RECT  2.16 29.565 23.76 29.835 ;
     RECT  2.16 30.105 23.76 30.375 ;
     RECT  2.16 30.645 23.76 30.915 ;
     RECT  2.16 31.185 23.76 31.455 ;
     RECT  2.16 31.725 23.76 31.995 ;
     RECT  2.16 32.265 23.76 32.535 ;
     RECT  2.16 32.805 23.76 33.075 ;
     RECT  2.16 33.345 23.76 33.615 ;
     RECT  2.16 33.885 23.76 34.155 ;
     RECT  2.16 34.425 23.76 34.695 ;
     RECT  2.16 34.965 23.76 35.235 ;
     RECT  2.16 35.505 23.76 35.775 ;
     RECT  2.16 36.045 23.76 36.315 ;
     RECT  2.16 36.585 23.76 36.855 ;
     RECT  2.16 37.125 23.76 37.395 ;
     RECT  2.16 37.665 23.76 37.935 ;
     RECT  2.16 38.205 23.76 38.475 ;
     RECT  2.16 38.745 23.76 39.015 ;
     RECT  2.16 39.285 23.76 39.555 ;
     RECT  2.16 39.825 23.76 40.095 ;
     RECT  2.16 40.365 23.76 40.635 ;
     RECT  2.16 40.905 23.76 41.175 ;
     RECT  2.16 41.445 23.76 41.715 ;
     RECT  2.16 41.985 23.76 42.255 ;
     RECT  2.16 42.525 23.76 42.795 ;
     RECT  2.16 43.065 23.76 43.335 ;
     RECT  2.16 43.605 23.76 43.875 ;
     RECT  2.16 44.145 23.76 44.415 ;
     RECT  2.16 44.685 23.76 44.955 ;
     RECT  2.16 45.225 23.76 45.495 ;
     RECT  2.16 45.765 23.76 46.035 ;
     RECT  2.16 46.305 23.76 46.575 ;
     RECT  2.16 46.845 23.76 47.115 ;
     RECT  2.16 47.385 23.76 47.655 ;
     RECT  2.16 47.925 23.76 48.195 ;
     RECT  2.16 48.465 23.76 48.735 ;
     RECT  2.16 49.005 23.76 49.275 ;
     RECT  2.16 49.545 23.76 49.815 ;
     RECT  2.16 50.085 23.76 50.355 ;
     RECT  2.16 50.625 23.76 50.895 ;
     RECT  2.16 51.165 23.76 51.435 ;
     RECT  2.16 51.705 23.76 51.975 ;
     RECT  2.16 52.245 23.76 52.515 ;
     RECT  2.16 52.785 23.76 53.055 ;
     RECT  2.16 53.325 23.76 53.595 ;
     RECT  2.16 53.865 23.76 54.135 ;
     RECT  2.16 54.405 23.76 54.675 ;
     RECT  2.16 54.945 23.76 55.215 ;
     RECT  2.16 55.485 23.76 55.755 ;
     RECT  2.16 56.025 23.76 56.295 ;
     RECT  2.16 56.565 23.76 56.835 ;
     RECT  2.16 57.105 23.76 57.375 ;
     RECT  2.16 57.645 23.76 57.915 ;
     RECT  2.16 58.185 23.76 58.455 ;
     RECT  2.16 58.725 23.76 58.995 ;
     RECT  2.16 59.265 23.76 59.535 ;
     RECT  2.16 59.805 23.76 60.075 ;
     RECT  2.16 60.345 23.76 60.615 ;
     RECT  2.16 60.885 23.76 61.155 ;
     RECT  2.16 61.425 23.76 61.695 ;
     RECT  2.16 61.965 23.76 62.235 ;
     RECT  2.16 62.505 23.76 62.775 ;
     RECT  2.16 63.045 23.76 63.315 ;
     RECT  2.16 63.585 23.76 63.855 ;
     RECT  2.16 64.125 23.76 64.395 ;
     RECT  2.16 64.665 23.76 64.935 ;
     RECT  2.16 65.205 23.76 65.475 ;
     RECT  2.16 65.745 23.76 66.015 ;
     RECT  2.16 66.285 23.76 66.555 ;
     RECT  2.16 66.825 23.76 67.095 ;
     RECT  2.16 67.365 23.76 67.635 ;
     RECT  2.16 67.905 23.76 68.175 ;
     RECT  2.16 68.445 23.76 68.715 ;
     RECT  2.16 68.985 23.76 69.255 ;
     RECT  2.16 69.525 23.76 69.795 ;
     RECT  2.16 70.065 23.76 70.335 ;
     RECT  2.16 70.605 23.76 70.875 ;
     RECT  2.16 71.145 23.76 71.415 ;
     RECT  2.16 71.685 23.76 71.955 ;
     RECT  2.16 72.225 23.76 72.495 ;
     RECT  2.16 72.765 23.76 73.035 ;
     RECT  2.16 73.305 23.76 73.575 ;
     RECT  2.16 73.845 23.76 74.115 ;
     RECT  2.16 74.385 23.76 74.655 ;
     RECT  2.16 74.925 23.76 75.195 ;
     RECT  2.16 75.465 23.76 75.735 ;
     RECT  2.16 76.005 23.76 76.275 ;
     RECT  2.16 76.545 23.76 76.815 ;
     RECT  2.16 77.085 23.76 77.355 ;
     RECT  2.16 77.625 23.76 77.895 ;
     RECT  2.16 78.165 23.76 78.435 ;
     RECT  2.16 78.705 23.76 78.975 ;
     RECT  2.16 79.245 23.76 79.515 ;
     RECT  2.16 79.785 23.76 80.055 ;
     RECT  2.16 80.325 23.76 80.595 ;
     RECT  2.16 80.865 23.76 81.135 ;
     RECT  2.16 81.405 23.76 81.675 ;
     RECT  2.16 81.945 23.76 82.215 ;
     RECT  2.16 82.485 23.76 82.755 ;
     RECT  2.16 83.025 23.76 83.295 ;
     RECT  2.16 83.565 23.76 83.835 ;
     RECT  2.16 84.105 23.76 84.375 ;
     RECT  2.16 84.645 23.76 84.915 ;
     RECT  2.16 85.185 23.76 85.455 ;
     RECT  2.16 85.725 23.76 85.995 ;
     RECT  2.16 86.265 23.76 86.535 ;
     RECT  2.16 86.805 23.76 87.075 ;
     RECT  2.16 87.345 23.76 87.615 ;
     RECT  2.16 87.885 23.76 88.155 ;
     RECT  2.16 88.425 23.76 88.695 ;
     RECT  2.16 88.965 23.76 89.235 ;
     RECT  2.16 89.505 23.76 89.775 ;
     RECT  2.16 90.045 23.76 90.315 ;
     RECT  2.16 90.585 23.76 90.855 ;
     RECT  2.16 91.125 23.76 91.395 ;
     RECT  2.16 91.665 23.76 91.935 ;
     RECT  2.16 92.205 23.76 92.475 ;
     RECT  2.16 92.745 23.76 93.015 ;
     RECT  2.16 93.285 23.76 93.555 ;
     RECT  2.16 93.825 23.76 94.095 ;
     RECT  2.16 94.365 23.76 94.635 ;
     RECT  2.16 94.905 23.76 95.175 ;
     RECT  2.16 95.445 23.76 95.715 ;
     RECT  2.16 95.985 23.76 96.255 ;
     RECT  2.16 96.525 23.76 96.795 ;
     RECT  2.16 97.065 23.76 97.335 ;
     RECT  2.16 97.605 23.76 97.875 ;
     RECT  2.16 98.145 23.76 98.415 ;
     RECT  2.16 98.685 23.76 98.955 ;
     RECT  2.16 99.225 23.76 99.495 ;
     RECT  2.16 99.765 23.76 100.035 ;
     RECT  2.16 100.305 23.76 100.575 ;
     RECT  2.16 100.845 23.76 101.115 ;
     RECT  2.16 101.385 23.76 101.655 ;
     RECT  2.16 101.925 23.76 102.195 ;
     RECT  2.16 102.465 23.76 102.735 ;
     RECT  2.16 103.005 23.76 103.275 ;
     RECT  2.16 103.545 23.76 103.68 ;
    LAYER RVTP ;
     RECT  2.16 2.295 23.76 2.565 ;
     RECT  2.16 2.835 23.76 3.105 ;
     RECT  2.16 3.375 23.76 3.645 ;
     RECT  2.16 3.915 23.76 4.185 ;
     RECT  2.16 4.455 23.76 4.725 ;
     RECT  2.16 4.995 23.76 5.265 ;
     RECT  2.16 5.535 23.76 5.805 ;
     RECT  2.16 6.075 23.76 6.345 ;
     RECT  2.16 6.615 23.76 6.885 ;
     RECT  2.16 7.155 23.76 7.425 ;
     RECT  2.16 7.695 23.76 7.965 ;
     RECT  2.16 8.235 23.76 8.505 ;
     RECT  2.16 8.775 23.76 9.045 ;
     RECT  2.16 9.315 23.76 9.585 ;
     RECT  2.16 9.855 23.76 10.125 ;
     RECT  2.16 10.395 23.76 10.665 ;
     RECT  2.16 10.935 23.76 11.205 ;
     RECT  2.16 11.475 23.76 11.745 ;
     RECT  2.16 12.015 23.76 12.285 ;
     RECT  2.16 12.555 23.76 12.825 ;
     RECT  2.16 13.095 23.76 13.365 ;
     RECT  2.16 13.635 23.76 13.905 ;
     RECT  2.16 14.175 23.76 14.445 ;
     RECT  2.16 14.715 23.76 14.985 ;
     RECT  2.16 15.255 23.76 15.525 ;
     RECT  2.16 15.795 23.76 16.065 ;
     RECT  2.16 16.335 23.76 16.605 ;
     RECT  2.16 16.875 23.76 17.145 ;
     RECT  2.16 17.415 23.76 17.685 ;
     RECT  2.16 17.955 23.76 18.225 ;
     RECT  2.16 18.495 23.76 18.765 ;
     RECT  2.16 19.035 23.76 19.305 ;
     RECT  2.16 19.575 23.76 19.845 ;
     RECT  2.16 20.115 23.76 20.385 ;
     RECT  2.16 20.655 23.76 20.925 ;
     RECT  2.16 21.195 23.76 21.465 ;
     RECT  2.16 21.735 23.76 22.005 ;
     RECT  2.16 22.275 23.76 22.545 ;
     RECT  2.16 22.815 23.76 23.085 ;
     RECT  2.16 23.355 23.76 23.625 ;
     RECT  2.16 23.895 23.76 24.165 ;
     RECT  2.16 24.435 23.76 24.705 ;
     RECT  2.16 24.975 23.76 25.245 ;
     RECT  2.16 25.515 23.76 25.785 ;
     RECT  2.16 26.055 23.76 26.325 ;
     RECT  2.16 26.595 23.76 26.865 ;
     RECT  2.16 27.135 23.76 27.405 ;
     RECT  2.16 27.675 23.76 27.945 ;
     RECT  2.16 28.215 23.76 28.485 ;
     RECT  2.16 28.755 23.76 29.025 ;
     RECT  2.16 29.295 23.76 29.565 ;
     RECT  2.16 29.835 23.76 30.105 ;
     RECT  2.16 30.375 23.76 30.645 ;
     RECT  2.16 30.915 23.76 31.185 ;
     RECT  2.16 31.455 23.76 31.725 ;
     RECT  2.16 31.995 23.76 32.265 ;
     RECT  2.16 32.535 23.76 32.805 ;
     RECT  2.16 33.075 23.76 33.345 ;
     RECT  2.16 33.615 23.76 33.885 ;
     RECT  2.16 34.155 23.76 34.425 ;
     RECT  2.16 34.695 23.76 34.965 ;
     RECT  2.16 35.235 23.76 35.505 ;
     RECT  2.16 35.775 23.76 36.045 ;
     RECT  2.16 36.315 23.76 36.585 ;
     RECT  2.16 36.855 23.76 37.125 ;
     RECT  2.16 37.395 23.76 37.665 ;
     RECT  2.16 37.935 23.76 38.205 ;
     RECT  2.16 38.475 23.76 38.745 ;
     RECT  2.16 39.015 23.76 39.285 ;
     RECT  2.16 39.555 23.76 39.825 ;
     RECT  2.16 40.095 23.76 40.365 ;
     RECT  2.16 40.635 23.76 40.905 ;
     RECT  2.16 41.175 23.76 41.445 ;
     RECT  2.16 41.715 23.76 41.985 ;
     RECT  2.16 42.255 23.76 42.525 ;
     RECT  2.16 42.795 23.76 43.065 ;
     RECT  2.16 43.335 23.76 43.605 ;
     RECT  2.16 43.875 23.76 44.145 ;
     RECT  2.16 44.415 23.76 44.685 ;
     RECT  2.16 44.955 23.76 45.225 ;
     RECT  2.16 45.495 23.76 45.765 ;
     RECT  2.16 46.035 23.76 46.305 ;
     RECT  2.16 46.575 23.76 46.845 ;
     RECT  2.16 47.115 23.76 47.385 ;
     RECT  2.16 47.655 23.76 47.925 ;
     RECT  2.16 48.195 23.76 48.465 ;
     RECT  2.16 48.735 23.76 49.005 ;
     RECT  2.16 49.275 23.76 49.545 ;
     RECT  2.16 49.815 23.76 50.085 ;
     RECT  2.16 50.355 23.76 50.625 ;
     RECT  2.16 50.895 23.76 51.165 ;
     RECT  2.16 51.435 23.76 51.705 ;
     RECT  2.16 51.975 23.76 52.245 ;
     RECT  2.16 52.515 23.76 52.785 ;
     RECT  2.16 53.055 23.76 53.325 ;
     RECT  2.16 53.595 23.76 53.865 ;
     RECT  2.16 54.135 23.76 54.405 ;
     RECT  2.16 54.675 23.76 54.945 ;
     RECT  2.16 55.215 23.76 55.485 ;
     RECT  2.16 55.755 23.76 56.025 ;
     RECT  2.16 56.295 23.76 56.565 ;
     RECT  2.16 56.835 23.76 57.105 ;
     RECT  2.16 57.375 23.76 57.645 ;
     RECT  2.16 57.915 23.76 58.185 ;
     RECT  2.16 58.455 23.76 58.725 ;
     RECT  2.16 58.995 23.76 59.265 ;
     RECT  2.16 59.535 23.76 59.805 ;
     RECT  2.16 60.075 23.76 60.345 ;
     RECT  2.16 60.615 23.76 60.885 ;
     RECT  2.16 61.155 23.76 61.425 ;
     RECT  2.16 61.695 23.76 61.965 ;
     RECT  2.16 62.235 23.76 62.505 ;
     RECT  2.16 62.775 23.76 63.045 ;
     RECT  2.16 63.315 23.76 63.585 ;
     RECT  2.16 63.855 23.76 64.125 ;
     RECT  2.16 64.395 23.76 64.665 ;
     RECT  2.16 64.935 23.76 65.205 ;
     RECT  2.16 65.475 23.76 65.745 ;
     RECT  2.16 66.015 23.76 66.285 ;
     RECT  2.16 66.555 23.76 66.825 ;
     RECT  2.16 67.095 23.76 67.365 ;
     RECT  2.16 67.635 23.76 67.905 ;
     RECT  2.16 68.175 23.76 68.445 ;
     RECT  2.16 68.715 23.76 68.985 ;
     RECT  2.16 69.255 23.76 69.525 ;
     RECT  2.16 69.795 23.76 70.065 ;
     RECT  2.16 70.335 23.76 70.605 ;
     RECT  2.16 70.875 23.76 71.145 ;
     RECT  2.16 71.415 23.76 71.685 ;
     RECT  2.16 71.955 23.76 72.225 ;
     RECT  2.16 72.495 23.76 72.765 ;
     RECT  2.16 73.035 23.76 73.305 ;
     RECT  2.16 73.575 23.76 73.845 ;
     RECT  2.16 74.115 23.76 74.385 ;
     RECT  2.16 74.655 23.76 74.925 ;
     RECT  2.16 75.195 23.76 75.465 ;
     RECT  2.16 75.735 23.76 76.005 ;
     RECT  2.16 76.275 23.76 76.545 ;
     RECT  2.16 76.815 23.76 77.085 ;
     RECT  2.16 77.355 23.76 77.625 ;
     RECT  2.16 77.895 23.76 78.165 ;
     RECT  2.16 78.435 23.76 78.705 ;
     RECT  2.16 78.975 23.76 79.245 ;
     RECT  2.16 79.515 23.76 79.785 ;
     RECT  2.16 80.055 23.76 80.325 ;
     RECT  2.16 80.595 23.76 80.865 ;
     RECT  2.16 81.135 23.76 81.405 ;
     RECT  2.16 81.675 23.76 81.945 ;
     RECT  2.16 82.215 23.76 82.485 ;
     RECT  2.16 82.755 23.76 83.025 ;
     RECT  2.16 83.295 23.76 83.565 ;
     RECT  2.16 83.835 23.76 84.105 ;
     RECT  2.16 84.375 23.76 84.645 ;
     RECT  2.16 84.915 23.76 85.185 ;
     RECT  2.16 85.455 23.76 85.725 ;
     RECT  2.16 85.995 23.76 86.265 ;
     RECT  2.16 86.535 23.76 86.805 ;
     RECT  2.16 87.075 23.76 87.345 ;
     RECT  2.16 87.615 23.76 87.885 ;
     RECT  2.16 88.155 23.76 88.425 ;
     RECT  2.16 88.695 23.76 88.965 ;
     RECT  2.16 89.235 23.76 89.505 ;
     RECT  2.16 89.775 23.76 90.045 ;
     RECT  2.16 90.315 23.76 90.585 ;
     RECT  2.16 90.855 23.76 91.125 ;
     RECT  2.16 91.395 23.76 91.665 ;
     RECT  2.16 91.935 23.76 92.205 ;
     RECT  2.16 92.475 23.76 92.745 ;
     RECT  2.16 93.015 23.76 93.285 ;
     RECT  2.16 93.555 23.76 93.825 ;
     RECT  2.16 94.095 23.76 94.365 ;
     RECT  2.16 94.635 23.76 94.905 ;
     RECT  2.16 95.175 23.76 95.445 ;
     RECT  2.16 95.715 23.76 95.985 ;
     RECT  2.16 96.255 23.76 96.525 ;
     RECT  2.16 96.795 23.76 97.065 ;
     RECT  2.16 97.335 23.76 97.605 ;
     RECT  2.16 97.875 23.76 98.145 ;
     RECT  2.16 98.415 23.76 98.685 ;
     RECT  2.16 98.955 23.76 99.225 ;
     RECT  2.16 99.495 23.76 99.765 ;
     RECT  2.16 100.035 23.76 100.305 ;
     RECT  2.16 100.575 23.76 100.845 ;
     RECT  2.16 101.115 23.76 101.385 ;
     RECT  2.16 101.655 23.76 101.925 ;
     RECT  2.16 102.195 23.76 102.465 ;
     RECT  2.16 102.735 23.76 103.005 ;
     RECT  2.16 103.275 23.76 103.545 ;
    LAYER M1 ;
     RECT  2.16 2.151 23.76 103.689 ;
    LAYER M2 ;
     RECT  0.103 2.772 0.535 2.79 ;
     RECT  0.103 58.122 0.535 58.14 ;
     RECT  0.103 86.58 0.535 88.11 ;
     RECT  0.103 99.162 0.535 99.18 ;
     RECT  0.103 63.252 0.931 63.27 ;
     RECT  0.535 64.368 0.931 65.538 ;
     RECT  0.535 53.568 1.003 53.586 ;
     RECT  0.103 42.732 1.039 42.75 ;
     RECT  1.003 93.906 1.039 93.924 ;
     RECT  0.535 36.36 1.111 36.378 ;
     RECT  0.103 89.982 1.111 90 ;
     RECT  1.003 53.568 1.435 53.892 ;
     RECT  1.363 91.476 1.471 91.494 ;
     RECT  0.535 86.58 1.507 88.722 ;
     RECT  1.111 36.36 1.543 36.684 ;
     RECT  1.435 96.336 1.579 96.354 ;
     RECT  0.535 99.162 1.651 99.558 ;
     RECT  1.939 76.554 1.975 76.572 ;
     RECT  0.103 72.432 2.011 72.45 ;
     RECT  2.047 55.836 2.083 55.854 ;
     RECT  0.535 2.772 2.16 3.33 ;
     RECT  0.103 8.514 2.16 8.532 ;
     RECT  0.103 13.068 2.16 14.778 ;
     RECT  1.687 19.116 2.16 19.134 ;
     RECT  0.103 22.788 2.16 23.31 ;
     RECT  0.103 25.02 2.16 25.038 ;
     RECT  0.103 26.1 2.16 26.118 ;
     RECT  1.543 36.36 2.16 36.954 ;
     RECT  0.535 38.178 2.16 38.196 ;
     RECT  2.119 40.95 2.16 40.968 ;
     RECT  1.039 42.066 2.16 42.75 ;
     RECT  0.103 44.424 2.16 44.442 ;
     RECT  1.435 53.568 2.16 54.504 ;
     RECT  2.083 55.566 2.16 55.854 ;
     RECT  0.535 57.996 2.16 58.14 ;
     RECT  0.931 63.252 2.16 65.538 ;
     RECT  2.011 72.432 2.16 73.062 ;
     RECT  1.363 74.394 2.16 74.412 ;
     RECT  1.975 76.086 2.16 76.572 ;
     RECT  1.507 86.58 2.16 89.064 ;
     RECT  1.111 89.982 2.16 90.108 ;
     RECT  1.471 91.476 2.16 92.034 ;
     RECT  1.039 93.33 2.16 93.924 ;
     RECT  2.011 95.526 2.16 95.544 ;
     RECT  1.579 96.336 2.16 97.056 ;
     RECT  1.651 99.162 2.16 99.864 ;
     RECT  1.615 100.656 2.16 100.674 ;
     RECT  2.16 2.151 4.495 103.689 ;
     RECT  4.495 2.106 5.791 103.689 ;
     RECT  5.791 1.494 6.223 103.689 ;
     RECT  6.223 1.458 16.763 103.689 ;
     RECT  16.763 1.494 17.051 103.689 ;
     RECT  17.051 1.611 18.203 103.689 ;
     RECT  18.203 2.034 19.211 103.689 ;
     RECT  19.211 2.151 23.76 103.689 ;
     RECT  23.76 33.894 23.819 39.474 ;
     RECT  23.76 21.204 23.855 29.016 ;
     RECT  23.76 53.226 23.891 103.266 ;
     RECT  23.76 2.268 23.927 20.304 ;
     RECT  23.76 29.808 23.927 31.914 ;
     RECT  23.819 33.894 23.927 37.224 ;
     RECT  23.76 40.266 23.927 52.434 ;
     RECT  23.891 53.226 23.927 70.362 ;
     RECT  23.891 76.788 23.927 103.266 ;
     RECT  23.855 28.458 23.963 29.016 ;
     RECT  23.76 32.706 23.963 33.066 ;
     RECT  23.927 94.806 23.999 103.266 ;
     RECT  23.927 2.268 24.359 11.268 ;
     RECT  23.855 21.204 24.359 27.594 ;
     RECT  23.999 101.466 24.359 103.266 ;
     RECT  23.927 80.496 24.395 93.744 ;
     RECT  24.359 2.268 24.467 4.68 ;
     RECT  23.927 40.266 24.467 45.684 ;
     RECT  24.359 101.736 24.467 103.266 ;
     RECT  24.359 5.436 24.503 11.268 ;
     RECT  24.359 21.204 24.503 24.696 ;
     RECT  24.359 25.524 24.503 27.594 ;
     RECT  23.927 31.356 24.503 31.914 ;
     RECT  24.467 40.266 24.503 42.624 ;
     RECT  24.467 43.38 24.503 45.684 ;
     RECT  23.927 53.226 24.503 63.774 ;
     RECT  24.395 80.496 24.503 90.234 ;
     RECT  24.395 91.368 24.503 93.744 ;
     RECT  24.467 101.736 24.503 102.996 ;
     RECT  24.503 44.586 24.539 45.684 ;
     RECT  23.927 64.566 24.539 70.362 ;
     RECT  23.927 33.966 24.575 37.224 ;
     RECT  24.503 21.204 25.007 24.534 ;
     RECT  24.503 54.216 25.007 63.774 ;
     RECT  24.503 7.326 25.043 8.874 ;
     RECT  23.927 15.156 25.043 20.304 ;
     RECT  25.007 21.24 25.043 24.534 ;
     RECT  23.963 32.706 25.043 32.994 ;
     RECT  23.819 37.98 25.043 39.474 ;
     RECT  25.007 54.216 25.043 59.454 ;
     RECT  25.007 60.246 25.043 63.774 ;
     RECT  24.539 64.566 25.043 67.284 ;
     RECT  23.927 76.788 25.043 79.704 ;
     RECT  24.503 80.496 25.043 89.694 ;
     RECT  24.503 92.376 25.043 93.744 ;
     RECT  23.999 94.806 25.043 100.674 ;
     RECT  24.467 2.268 25.079 3.204 ;
     RECT  24.467 3.96 25.079 4.68 ;
     RECT  24.503 5.436 25.079 6.102 ;
     RECT  25.043 7.326 25.079 7.884 ;
     RECT  25.043 8.676 25.079 8.874 ;
     RECT  24.503 9.756 25.079 11.268 ;
     RECT  23.927 12.024 25.079 12.474 ;
     RECT  23.927 13.266 25.079 14.364 ;
     RECT  25.043 15.156 25.079 18.144 ;
     RECT  25.043 18.936 25.079 20.304 ;
     RECT  24.503 25.758 25.079 27.594 ;
     RECT  23.963 28.656 25.079 29.016 ;
     RECT  23.927 30.006 25.079 30.294 ;
     RECT  24.503 31.626 25.079 31.914 ;
     RECT  25.043 32.706 25.079 32.868 ;
     RECT  24.575 34.056 25.079 37.224 ;
     RECT  25.043 38.016 25.079 39.474 ;
     RECT  24.503 40.266 25.079 42.516 ;
     RECT  24.503 43.38 25.079 43.794 ;
     RECT  24.539 44.586 25.079 44.604 ;
     RECT  24.539 45.396 25.079 45.684 ;
     RECT  23.927 46.476 25.079 52.434 ;
     RECT  24.503 53.226 25.079 53.244 ;
     RECT  25.043 54.216 25.079 58.644 ;
     RECT  25.043 59.436 25.079 59.454 ;
     RECT  25.043 60.246 25.079 61.344 ;
     RECT  25.043 62.208 25.079 63.774 ;
     RECT  25.043 64.674 25.079 67.158 ;
     RECT  24.539 68.076 25.079 70.362 ;
     RECT  23.891 71.316 25.079 75.654 ;
     RECT  25.043 76.986 25.079 77.004 ;
     RECT  25.043 77.796 25.079 79.704 ;
     RECT  25.043 80.496 25.079 80.514 ;
     RECT  25.043 81.306 25.079 81.324 ;
     RECT  25.043 82.386 25.079 87.408 ;
     RECT  25.043 88.326 25.079 89.424 ;
     RECT  24.503 91.368 25.079 91.584 ;
     RECT  25.043 92.376 25.079 93.474 ;
     RECT  25.043 94.806 25.079 94.824 ;
     RECT  25.043 95.616 25.079 100.674 ;
     RECT  24.503 102.636 25.079 102.654 ;
     RECT  25.079 5.814 25.115 6.102 ;
     RECT  25.079 7.776 25.115 7.794 ;
     RECT  25.079 11.142 25.115 11.268 ;
     RECT  25.079 12.024 25.115 12.384 ;
     RECT  25.079 13.446 25.115 14.238 ;
     RECT  25.079 19.116 25.115 19.638 ;
     RECT  25.043 21.276 25.115 24.534 ;
     RECT  25.079 25.758 25.115 26.424 ;
     RECT  25.079 32.85 25.115 32.868 ;
     RECT  25.079 36.9 25.115 37.224 ;
     RECT  25.079 38.016 25.115 38.619 ;
     RECT  25.079 42.498 25.115 42.516 ;
     RECT  25.079 47.016 25.115 48.294 ;
     RECT  25.079 49.356 25.115 49.374 ;
     RECT  25.079 54.216 25.115 56.124 ;
     RECT  25.079 64.674 25.115 65.034 ;
     RECT  25.079 66.33 25.115 67.158 ;
     RECT  25.079 68.526 25.115 68.544 ;
     RECT  25.079 70.344 25.115 70.362 ;
     RECT  25.079 72.036 25.115 75.222 ;
     RECT  25.079 78.516 25.115 78.804 ;
     RECT  25.079 83.61 25.115 84.204 ;
     RECT  25.079 84.996 25.115 85.554 ;
     RECT  25.079 86.31 25.115 87.408 ;
     RECT  25.079 88.704 25.115 89.298 ;
     RECT  25.079 95.688 25.115 98.442 ;
     RECT  25.115 5.814 25.151 5.904 ;
     RECT  25.079 9.756 25.151 10.224 ;
     RECT  25.115 12.186 25.151 12.384 ;
     RECT  25.115 21.276 25.151 23.922 ;
     RECT  25.079 8.784 25.799 8.874 ;
     RECT  25.151 23.328 25.799 23.922 ;
     RECT  25.079 31.806 25.799 31.914 ;
     RECT  25.079 2.268 25.835 2.286 ;
     RECT  25.079 3.96 25.835 3.978 ;
     RECT  25.151 5.886 25.835 5.904 ;
     RECT  25.799 8.856 25.835 8.874 ;
     RECT  25.151 9.756 25.835 9.774 ;
     RECT  25.115 11.25 25.835 11.268 ;
     RECT  25.151 12.366 25.835 12.384 ;
     RECT  25.115 13.446 25.835 13.968 ;
     RECT  25.079 15.498 25.835 16.164 ;
     RECT  25.151 21.276 25.835 22.572 ;
     RECT  25.799 23.904 25.835 23.922 ;
     RECT  25.079 27.216 25.835 27.36 ;
     RECT  25.079 28.998 25.835 29.016 ;
     RECT  25.079 30.276 25.835 30.294 ;
     RECT  25.799 31.806 25.835 31.824 ;
     RECT  25.079 36.018 25.835 36.036 ;
     RECT  25.079 40.68 25.835 41.274 ;
     RECT  25.079 45.576 25.835 45.594 ;
     RECT  25.115 47.016 25.835 47.034 ;
     RECT  25.079 50.436 25.835 52.038 ;
     RECT  25.115 54.414 25.835 54.432 ;
     RECT  25.115 55.566 25.835 56.124 ;
     RECT  25.079 57.726 25.835 58.014 ;
     RECT  25.079 60.354 25.835 60.876 ;
     RECT  25.079 62.244 25.835 62.262 ;
     RECT  25.115 65.016 25.835 65.034 ;
     RECT  25.115 67.14 25.835 67.158 ;
     RECT  25.115 72.036 25.835 73.944 ;
     RECT  25.115 75.204 25.835 75.222 ;
     RECT  25.115 78.516 25.835 78.534 ;
     RECT  25.079 82.656 25.835 82.674 ;
     RECT  25.115 85.464 25.835 85.482 ;
     RECT  25.115 86.31 25.835 86.328 ;
     RECT  25.115 87.354 25.835 87.372 ;
     RECT  25.115 88.704 25.835 89.064 ;
     RECT  25.079 91.368 25.835 91.386 ;
     RECT  25.079 92.556 25.835 93.384 ;
     RECT  25.115 95.688 25.835 97.704 ;
     RECT  25.079 99.738 25.835 99.756 ;
     RECT  25.079 100.656 25.835 100.674 ;
     RECT  24.503 101.736 25.835 101.754 ;
    LAYER M3 ;
     RECT  6.228 1.453 6.246 1.489 ;
     RECT  16.74 1.453 16.758 1.489 ;
     RECT  5.796 1.489 6.246 1.561 ;
     RECT  15.444 1.525 15.462 1.561 ;
     RECT  9.36 1.525 9.378 1.651 ;
     RECT  15.444 1.561 16.002 1.651 ;
     RECT  16.74 1.489 17.046 1.651 ;
     RECT  5.796 1.561 6.39 1.687 ;
     RECT  15.372 1.651 16.002 1.876 ;
     RECT  16.74 1.651 17.406 1.876 ;
     RECT  15.372 1.876 17.406 1.921 ;
     RECT  18.18 1.606 18.198 1.921 ;
     RECT  5.796 1.687 6.606 1.957 ;
     RECT  5.796 1.957 7.002 1.993 ;
     RECT  7.776 1.606 7.794 1.993 ;
     RECT  10.8 1.921 10.818 2.011 ;
     RECT  8.82 1.651 9.378 2.065 ;
     RECT  10.224 2.011 10.818 2.065 ;
     RECT  5.796 1.993 7.794 2.101 ;
     RECT  13.104 1.876 13.122 2.101 ;
     RECT  5.328 2.101 7.794 2.143 ;
     RECT  13.104 2.101 13.194 2.143 ;
     RECT  15.372 1.921 18.198 2.143 ;
     RECT  19.188 2.029 19.206 2.143 ;
     RECT  4.5 2.101 4.518 2.191 ;
     RECT  8.82 2.065 10.818 2.191 ;
     RECT  14.112 1.687 14.13 2.191 ;
     RECT  4.5 2.191 4.554 2.203 ;
     RECT  5.328 2.143 7.905 2.203 ;
     RECT  8.82 2.191 11.502 2.203 ;
     RECT  14.112 2.191 14.31 2.227 ;
     RECT  15.372 2.143 19.206 2.227 ;
     RECT  3.672 2.227 3.69 2.263 ;
     RECT  4.5 2.203 11.502 2.263 ;
     RECT  21.924 2.191 21.942 2.263 ;
     RECT  13.104 2.143 13.305 2.299 ;
     RECT  14.112 2.227 19.206 2.299 ;
     RECT  20.34 2.059 20.358 2.299 ;
     RECT  20.052 2.299 20.358 2.335 ;
     RECT  21.528 2.263 21.942 2.335 ;
     RECT  3.672 2.263 11.502 2.371 ;
     RECT  12.996 2.299 19.206 2.371 ;
     RECT  20.052 2.335 20.574 2.371 ;
     RECT  23.436 2.263 23.454 2.371 ;
     RECT  2.415 2.143 2.505 2.413 ;
     RECT  2.415 2.413 2.697 2.488 ;
     RECT  21.528 2.335 22.662 2.497 ;
     RECT  23.4 2.371 23.454 2.497 ;
     RECT  19.98 2.371 20.574 2.533 ;
     RECT  24.624 2.461 24.642 2.569 ;
     RECT  3.672 2.371 19.206 2.587 ;
     RECT  19.944 2.533 20.574 2.587 ;
     RECT  24.588 2.569 24.642 2.587 ;
     RECT  2.415 2.488 2.754 2.605 ;
     RECT  3.672 2.587 20.574 2.605 ;
     RECT  2.304 2.605 2.754 2.641 ;
     RECT  3.672 2.605 20.682 2.641 ;
     RECT  21.528 2.497 23.454 2.641 ;
     RECT  2.304 2.641 23.454 2.803 ;
     RECT  24.588 2.587 25.074 2.803 ;
     RECT  25.812 2.263 25.83 2.813 ;
     RECT  2.304 2.803 23.742 2.939 ;
     RECT  0.108 2.767 0.126 2.957 ;
     RECT  0.54 3.307 0.558 3.485 ;
     RECT  24.516 2.803 25.074 3.533 ;
     RECT  2.304 2.939 23.67 3.569 ;
     RECT  24.516 3.533 24.786 3.691 ;
     RECT  5.58 3.569 23.67 3.839 ;
     RECT  5.688 3.839 23.67 3.883 ;
     RECT  24.444 3.691 24.786 3.883 ;
     RECT  25.812 3.883 25.83 3.983 ;
     RECT  2.304 3.569 4.77 4.459 ;
     RECT  5.688 3.883 24.786 4.648 ;
     RECT  5.688 4.648 25.074 4.685 ;
     RECT  5.688 4.685 24.786 4.829 ;
     RECT  5.688 4.829 23.634 4.877 ;
     RECT  2.304 4.459 4.842 5.071 ;
     RECT  5.688 4.877 23.454 5.071 ;
     RECT  2.304 5.071 23.454 5.189 ;
     RECT  24.768 4.829 24.786 5.419 ;
     RECT  24.768 5.419 25.074 5.611 ;
     RECT  24.516 5.611 25.074 5.809 ;
     RECT  25.812 5.611 25.83 5.809 ;
     RECT  24.516 5.809 25.83 5.909 ;
     RECT  2.304 5.189 23.418 6.043 ;
     RECT  2.304 6.043 23.526 6.115 ;
     RECT  24.516 5.909 25.146 6.115 ;
     RECT  2.304 6.115 25.146 6.611 ;
     RECT  25.056 6.611 25.146 6.749 ;
     RECT  2.304 6.611 23.958 7.133 ;
     RECT  2.304 7.133 23.454 7.223 ;
     RECT  25.056 6.749 25.074 7.675 ;
     RECT  25.02 7.675 25.074 7.771 ;
     RECT  2.34 7.223 23.454 8.059 ;
     RECT  2.34 8.059 23.922 8.155 ;
     RECT  2.304 8.155 23.922 8.267 ;
     RECT  2.304 8.267 23.526 8.303 ;
     RECT  25.02 7.771 25.11 8.395 ;
     RECT  25.02 8.395 25.83 8.699 ;
     RECT  0.108 8.509 0.126 8.765 ;
     RECT  25.776 8.699 25.83 8.807 ;
     RECT  2.34 8.303 23.526 9.013 ;
     RECT  24.372 8.779 24.498 9.013 ;
     RECT  2.34 9.013 24.498 9.197 ;
     RECT  2.34 9.197 23.454 9.259 ;
     RECT  24.48 9.197 24.498 9.389 ;
     RECT  2.304 9.259 23.454 9.661 ;
     RECT  25.812 8.807 25.83 9.739 ;
     RECT  25.092 9.739 25.83 9.779 ;
     RECT  25.092 9.779 25.146 10.123 ;
     RECT  25.056 10.123 25.146 10.843 ;
     RECT  2.268 9.661 23.454 11.011 ;
     RECT  25.056 10.843 25.83 11.273 ;
     RECT  2.268 11.011 23.958 11.645 ;
     RECT  2.268 11.645 23.454 12.091 ;
     RECT  25.056 11.273 25.11 12.181 ;
     RECT  25.056 12.181 25.146 12.187 ;
     RECT  25.056 12.187 25.83 12.389 ;
     RECT  25.056 12.389 25.146 12.605 ;
     RECT  2.196 12.091 23.454 12.793 ;
     RECT  2.196 12.793 23.49 12.955 ;
     RECT  2.196 12.955 23.922 13.091 ;
     RECT  2.196 13.091 23.49 13.559 ;
     RECT  25.812 13.291 25.83 13.973 ;
     RECT  25.056 12.605 25.074 13.981 ;
     RECT  25.056 13.981 25.11 14.285 ;
     RECT  2.196 13.559 23.418 14.635 ;
     RECT  0.108 13.063 0.126 14.861 ;
     RECT  25.056 14.285 25.074 15.019 ;
     RECT  2.196 14.635 23.922 15.791 ;
     RECT  2.196 15.791 23.418 15.835 ;
     RECT  25.02 15.019 25.074 16.105 ;
     RECT  25.812 15.403 25.83 16.169 ;
     RECT  24.444 16.105 25.074 16.439 ;
     RECT  24.48 16.439 25.074 16.529 ;
     RECT  24.516 16.529 25.074 16.541 ;
     RECT  2.16 15.835 23.418 16.879 ;
     RECT  24.984 16.541 25.074 17.117 ;
     RECT  2.16 16.879 23.454 17.275 ;
     RECT  2.16 17.275 23.922 17.447 ;
     RECT  2.16 17.447 23.382 18.265 ;
     RECT  2.16 18.265 23.454 18.841 ;
     RECT  2.16 18.841 23.958 18.989 ;
     RECT  2.16 18.989 23.634 19.111 ;
     RECT  25.02 17.117 25.074 19.111 ;
     RECT  25.02 19.111 25.11 19.339 ;
     RECT  24.444 19.339 25.11 19.679 ;
     RECT  24.48 19.679 25.11 19.757 ;
     RECT  1.692 19.111 23.634 20.039 ;
     RECT  24.48 19.757 25.074 20.147 ;
     RECT  24.516 20.147 25.074 20.333 ;
     RECT  24.984 20.333 25.074 21.227 ;
     RECT  25.02 21.227 25.074 21.263 ;
     RECT  25.056 21.263 25.074 21.629 ;
     RECT  25.812 20.491 25.83 21.631 ;
     RECT  25.092 21.631 25.83 22.013 ;
     RECT  1.692 20.039 23.49 22.351 ;
     RECT  25.128 22.013 25.83 22.577 ;
     RECT  25.128 22.577 25.182 22.589 ;
     RECT  1.692 22.351 23.958 22.747 ;
     RECT  25.128 22.589 25.146 22.747 ;
     RECT  1.692 22.747 25.146 23.009 ;
     RECT  1.692 23.009 23.958 23.165 ;
     RECT  25.056 23.009 25.146 23.323 ;
     RECT  0.108 22.783 0.126 23.453 ;
     RECT  25.056 23.323 25.794 23.851 ;
     RECT  25.056 23.851 25.83 23.927 ;
     RECT  1.692 23.165 23.562 24.241 ;
     RECT  25.056 23.927 25.794 24.427 ;
     RECT  1.692 24.241 23.634 24.737 ;
     RECT  24.48 24.427 25.794 25.037 ;
     RECT  0.108 25.015 0.126 25.133 ;
     RECT  24.48 25.037 25.146 25.195 ;
     RECT  24.336 25.195 25.146 25.349 ;
     RECT  24.48 25.349 25.146 25.547 ;
     RECT  0.108 26.095 0.126 26.237 ;
     RECT  25.056 25.547 25.146 26.299 ;
     RECT  1.692 24.737 23.562 26.329 ;
     RECT  25.056 26.299 25.83 26.491 ;
     RECT  1.692 26.329 23.598 26.635 ;
     RECT  25.02 26.491 25.83 26.699 ;
     RECT  25.056 26.699 25.83 26.909 ;
     RECT  1.692 26.635 23.634 26.941 ;
     RECT  1.692 26.941 23.814 27.067 ;
     RECT  1.692 27.067 23.922 27.203 ;
     RECT  25.812 26.909 25.83 27.677 ;
     RECT  1.692 27.203 23.814 27.949 ;
     RECT  1.692 27.949 23.85 28.363 ;
     RECT  1.692 28.363 23.922 28.453 ;
     RECT  1.692 28.453 23.958 28.589 ;
     RECT  25.056 26.909 25.074 28.949 ;
     RECT  25.812 28.939 25.83 29.021 ;
     RECT  1.692 28.589 23.922 29.323 ;
     RECT  1.692 29.323 24.498 29.899 ;
     RECT  1.692 29.899 25.074 30.029 ;
     RECT  25.812 30.091 25.83 30.299 ;
     RECT  1.692 30.029 24.498 31.195 ;
     RECT  1.692 31.195 25.074 31.379 ;
     RECT  25.056 31.379 25.074 31.771 ;
     RECT  25.812 31.579 25.83 31.771 ;
     RECT  25.056 31.771 25.83 31.829 ;
     RECT  25.056 31.829 25.794 31.919 ;
     RECT  25.056 31.919 25.074 32.539 ;
     RECT  25.02 32.539 25.074 32.845 ;
     RECT  25.02 32.845 25.11 32.957 ;
     RECT  1.692 31.379 23.85 33.043 ;
     RECT  1.692 33.043 23.958 33.115 ;
     RECT  25.02 32.957 25.074 33.115 ;
     RECT  1.692 33.115 25.074 33.989 ;
     RECT  1.692 33.989 23.958 34.987 ;
     RECT  25.056 33.989 25.074 34.987 ;
     RECT  1.692 34.987 25.074 35.429 ;
     RECT  25.812 35.899 25.83 36.041 ;
     RECT  1.692 35.429 23.922 36.149 ;
     RECT  1.692 36.149 23.85 36.391 ;
     RECT  25.056 35.429 25.074 36.475 ;
     RECT  0.54 36.355 0.558 36.509 ;
     RECT  1.656 36.391 23.85 36.619 ;
     RECT  25.02 36.475 25.074 36.895 ;
     RECT  25.02 36.895 25.11 36.959 ;
     RECT  25.056 36.959 25.11 37.819 ;
     RECT  1.08 36.619 23.85 38.173 ;
     RECT  0.54 38.173 23.85 38.281 ;
     RECT  25.02 37.819 25.11 38.281 ;
     RECT  0.54 38.281 25.11 38.477 ;
     RECT  1.08 38.477 25.11 38.573 ;
     RECT  25.02 38.573 25.11 38.669 ;
     RECT  0.108 38.587 0.126 38.717 ;
     RECT  1.08 38.573 23.85 38.957 ;
     RECT  25.056 38.669 25.11 38.957 ;
     RECT  1.08 38.957 23.742 39.353 ;
     RECT  1.08 39.353 23.454 40.559 ;
     RECT  25.056 38.957 25.074 41.179 ;
     RECT  25.812 40.459 25.83 41.279 ;
     RECT  1.08 40.559 23.418 41.521 ;
     RECT  24.48 41.179 25.074 41.563 ;
     RECT  1.08 41.521 23.454 42.025 ;
     RECT  1.08 42.025 23.526 42.061 ;
     RECT  1.044 42.061 23.526 42.331 ;
     RECT  24.444 41.563 25.074 42.331 ;
     RECT  1.044 42.331 25.074 42.493 ;
     RECT  1.044 42.493 25.11 42.557 ;
     RECT  1.044 42.557 23.526 42.719 ;
     RECT  24.444 42.557 25.11 42.749 ;
     RECT  0.108 42.727 0.126 42.893 ;
     RECT  24.444 42.749 25.074 43.061 ;
     RECT  1.044 42.719 23.346 43.771 ;
     RECT  25.056 43.061 25.074 43.819 ;
     RECT  1.044 43.771 23.562 44.185 ;
     RECT  0.108 44.419 0.126 44.573 ;
     RECT  24.48 43.819 25.074 44.789 ;
     RECT  24.516 44.789 25.074 44.813 ;
     RECT  25.812 45.355 25.83 45.599 ;
     RECT  1.044 44.185 23.598 45.691 ;
     RECT  1.044 45.691 23.922 46.067 ;
     RECT  25.056 44.813 25.074 46.267 ;
     RECT  24.48 46.267 25.074 46.607 ;
     RECT  25.812 46.843 25.83 47.039 ;
     RECT  25.056 46.607 25.074 47.611 ;
     RECT  25.02 47.611 25.074 47.687 ;
     RECT  25.056 47.687 25.074 47.731 ;
     RECT  25.056 47.731 25.11 48.365 ;
     RECT  25.056 48.365 25.074 48.523 ;
     RECT  25.02 48.523 25.074 48.907 ;
     RECT  24.984 48.907 25.074 49.109 ;
     RECT  25.056 49.109 25.074 49.351 ;
     RECT  25.056 49.351 25.11 49.517 ;
     RECT  1.044 46.067 23.598 49.675 ;
     RECT  1.044 49.675 23.922 49.919 ;
     RECT  25.056 49.517 25.074 50.161 ;
     RECT  24.516 50.161 25.074 50.477 ;
     RECT  25.02 50.477 25.074 50.621 ;
     RECT  25.056 50.621 25.074 50.965 ;
     RECT  25.812 50.251 25.83 50.965 ;
     RECT  25.056 50.965 25.83 51.005 ;
     RECT  25.056 51.005 25.074 51.511 ;
     RECT  1.044 49.919 23.598 51.547 ;
     RECT  25.812 51.005 25.83 52.043 ;
     RECT  1.044 51.547 23.922 52.051 ;
     RECT  25.02 51.511 25.074 52.051 ;
     RECT  1.044 52.051 25.074 52.733 ;
     RECT  1.044 52.733 23.598 53.563 ;
     RECT  0.54 53.563 23.598 53.741 ;
     RECT  24.48 52.733 25.074 54.211 ;
     RECT  25.812 53.227 25.83 54.211 ;
     RECT  24.48 54.211 25.83 54.437 ;
     RECT  24.48 54.437 25.11 55.181 ;
     RECT  24.48 55.181 25.074 55.481 ;
     RECT  25.812 55.339 25.83 56.129 ;
     RECT  24.516 55.481 25.074 56.443 ;
     RECT  24.48 56.443 25.074 56.635 ;
     RECT  1.008 53.741 23.598 57.019 ;
     RECT  24.444 56.635 25.074 57.019 ;
     RECT  1.008 57.019 25.074 57.029 ;
     RECT  1.008 57.029 23.922 57.355 ;
     RECT  0.972 57.355 23.922 57.479 ;
     RECT  25.056 57.029 25.074 57.919 ;
     RECT  25.812 57.595 25.83 57.919 ;
     RECT  0.972 57.479 23.598 57.991 ;
     RECT  25.056 57.919 25.83 58.019 ;
     RECT  0.54 57.991 23.598 58.117 ;
     RECT  0.108 58.117 23.598 58.157 ;
     RECT  25.056 58.019 25.11 58.157 ;
     RECT  25.056 58.157 25.074 58.315 ;
     RECT  0.54 58.157 23.598 58.733 ;
     RECT  25.02 58.315 25.074 59.275 ;
     RECT  0.972 58.733 23.598 59.467 ;
     RECT  24.984 59.275 25.074 59.729 ;
     RECT  0.972 59.467 23.922 59.837 ;
     RECT  25.812 60.235 25.83 60.881 ;
     RECT  25.02 59.729 25.074 61.147 ;
     RECT  24.984 61.147 25.074 61.339 ;
     RECT  24.372 61.339 25.074 61.457 ;
     RECT  24.48 61.457 25.074 62.609 ;
     RECT  0.972 59.837 23.598 62.779 ;
     RECT  25.812 62.107 25.83 62.813 ;
     RECT  0.972 62.779 23.922 63.041 ;
     RECT  0.972 63.041 23.886 63.149 ;
     RECT  0.108 63.247 0.126 63.437 ;
     RECT  25.02 62.609 25.074 63.617 ;
     RECT  0.972 63.149 23.598 63.661 ;
     RECT  0.936 63.661 23.598 63.979 ;
     RECT  0.936 63.979 23.922 64.157 ;
     RECT  0.936 64.157 23.598 64.363 ;
     RECT  25.056 63.617 25.074 64.363 ;
     RECT  25.02 64.363 25.074 64.669 ;
     RECT  25.812 64.555 25.83 64.669 ;
     RECT  25.02 64.669 25.83 64.781 ;
     RECT  25.02 64.781 25.074 64.903 ;
     RECT  25.812 64.781 25.83 65.039 ;
     RECT  0.54 64.363 23.598 65.209 ;
     RECT  24.516 64.903 25.074 65.209 ;
     RECT  0.54 65.209 25.074 65.357 ;
     RECT  0.54 65.357 23.958 65.693 ;
     RECT  0.54 65.693 23.922 65.933 ;
     RECT  0.936 65.933 23.922 66.119 ;
     RECT  25.056 65.357 25.074 66.235 ;
     RECT  25.056 66.235 25.11 66.551 ;
     RECT  25.056 66.551 25.074 66.811 ;
     RECT  25.812 67.003 25.83 67.163 ;
     RECT  25.02 66.811 25.074 67.195 ;
     RECT  24.48 67.195 25.074 67.613 ;
     RECT  0.936 66.119 23.598 67.639 ;
     RECT  0.936 67.639 23.958 68.279 ;
     RECT  25.02 67.613 25.074 68.521 ;
     RECT  25.02 68.521 25.11 68.791 ;
     RECT  24.516 68.791 25.11 68.909 ;
     RECT  25.056 68.909 25.11 69.101 ;
     RECT  0.936 68.279 23.598 69.331 ;
     RECT  0.936 69.331 23.67 69.643 ;
     RECT  25.056 69.101 25.074 69.643 ;
     RECT  0.936 69.643 25.074 70.253 ;
     RECT  25.056 70.253 25.074 70.339 ;
     RECT  25.056 70.339 25.11 70.445 ;
     RECT  0.936 70.253 23.922 70.795 ;
     RECT  25.056 70.445 25.074 71.131 ;
     RECT  0.9 70.795 23.922 71.515 ;
     RECT  25.02 71.131 25.074 71.515 ;
     RECT  0.9 71.515 25.074 71.519 ;
     RECT  0.9 71.519 23.67 72.139 ;
     RECT  24.48 71.519 25.074 72.667 ;
     RECT  25.812 71.899 25.83 72.667 ;
     RECT  24.48 72.667 25.83 72.797 ;
     RECT  0.864 72.139 23.67 72.931 ;
     RECT  0.864 72.931 23.706 73.031 ;
     RECT  25.056 72.797 25.83 73.229 ;
     RECT  0.108 72.283 0.126 73.277 ;
     RECT  25.092 73.229 25.83 73.421 ;
     RECT  25.812 73.421 25.83 73.949 ;
     RECT  0.864 73.031 23.67 73.963 ;
     RECT  0.864 73.963 23.922 74.155 ;
     RECT  0.864 74.155 24.498 74.347 ;
     RECT  0.864 74.347 25.074 74.489 ;
     RECT  0.108 74.203 0.126 74.525 ;
     RECT  24.48 74.489 25.074 74.539 ;
     RECT  24.48 74.539 25.11 74.579 ;
     RECT  24.516 74.579 25.11 74.651 ;
     RECT  25.812 75.115 25.83 75.227 ;
     RECT  0.864 74.489 23.67 75.307 ;
     RECT  24.516 74.651 25.074 75.307 ;
     RECT  0.864 75.307 25.074 75.659 ;
     RECT  0.864 75.659 24.534 75.677 ;
     RECT  25.056 76.603 25.074 76.783 ;
     RECT  0.864 75.677 23.922 77.387 ;
     RECT  25.02 76.783 25.074 77.563 ;
     RECT  25.812 78.283 25.83 78.539 ;
     RECT  24.48 77.563 25.074 78.781 ;
     RECT  24.48 78.781 25.11 78.893 ;
     RECT  0.864 77.387 23.67 79.435 ;
     RECT  24.48 78.893 25.074 79.435 ;
     RECT  0.864 79.435 25.074 79.661 ;
     RECT  0.864 79.661 23.922 81.307 ;
     RECT  25.02 79.661 25.074 81.307 ;
     RECT  0.864 81.307 25.074 81.779 ;
     RECT  0.864 81.779 23.922 81.977 ;
     RECT  25.02 81.779 25.074 82.651 ;
     RECT  25.812 82.267 25.83 82.679 ;
     RECT  24.48 82.651 25.074 82.786 ;
     RECT  24.444 82.786 25.074 82.859 ;
     RECT  0.864 81.977 23.67 83.065 ;
     RECT  25.02 82.859 25.074 83.605 ;
     RECT  0.864 83.065 23.958 83.981 ;
     RECT  25.02 83.605 25.11 84.139 ;
     RECT  24.48 84.139 25.11 84.749 ;
     RECT  0.108 84.763 0.126 84.893 ;
     RECT  25.056 84.749 25.11 85.291 ;
     RECT  25.056 85.291 25.83 86.011 ;
     RECT  24.48 86.011 25.83 86.333 ;
     RECT  0.864 83.981 23.67 86.669 ;
     RECT  24.48 86.333 25.11 86.801 ;
     RECT  25.056 86.801 25.11 87.163 ;
     RECT  25.056 87.163 25.83 87.377 ;
     RECT  25.056 87.377 25.11 87.547 ;
     RECT  25.02 87.547 25.11 87.773 ;
     RECT  25.02 87.773 25.074 87.883 ;
     RECT  24.408 87.883 25.074 87.989 ;
     RECT  0.864 86.669 23.598 88.075 ;
     RECT  0.864 88.075 23.922 88.151 ;
     RECT  0.108 86.575 0.126 88.157 ;
     RECT  0.864 88.151 23.598 88.699 ;
     RECT  0.54 88.699 23.598 88.973 ;
     RECT  25.056 87.989 25.074 89.035 ;
     RECT  25.812 88.651 25.83 89.069 ;
     RECT  0.864 88.973 23.598 89.239 ;
     RECT  24.48 89.035 25.074 89.239 ;
     RECT  0.864 89.239 25.074 89.275 ;
     RECT  0.864 89.275 25.11 89.453 ;
     RECT  0.864 89.453 25.038 89.699 ;
     RECT  0.864 89.699 24.534 90.029 ;
     RECT  0.108 89.977 0.126 90.077 ;
     RECT  0.864 90.029 24.498 90.221 ;
     RECT  0.864 90.221 23.598 90.845 ;
     RECT  24.336 90.221 24.498 91.099 ;
     RECT  0.9 90.845 23.598 91.661 ;
     RECT  1.008 91.661 23.598 91.867 ;
     RECT  24.336 91.099 25.074 91.867 ;
     RECT  1.008 91.867 25.074 92.039 ;
     RECT  1.008 92.039 23.922 92.309 ;
     RECT  25.02 92.039 25.074 92.779 ;
     RECT  25.812 91.291 25.83 92.779 ;
     RECT  25.02 92.779 25.83 93.011 ;
     RECT  1.008 92.309 23.598 93.163 ;
     RECT  1.008 93.163 23.922 93.325 ;
     RECT  25.812 93.011 25.83 93.389 ;
     RECT  1.008 93.325 23.994 93.547 ;
     RECT  25.02 93.011 25.074 93.547 ;
     RECT  1.008 93.547 25.074 93.929 ;
     RECT  1.44 93.929 25.074 94.361 ;
     RECT  24.444 94.361 25.074 95.227 ;
     RECT  24.372 95.227 25.074 95.477 ;
     RECT  1.44 94.361 23.598 96.359 ;
     RECT  1.584 96.359 23.598 96.379 ;
     RECT  1.584 96.379 23.922 96.629 ;
     RECT  25.02 95.477 25.074 96.763 ;
     RECT  25.812 95.611 25.83 96.763 ;
     RECT  1.584 96.629 23.598 97.061 ;
     RECT  25.02 96.763 25.83 97.439 ;
     RECT  25.812 97.439 25.83 97.709 ;
     RECT  25.02 97.439 25.074 97.757 ;
     RECT  1.62 97.061 23.598 97.879 ;
     RECT  1.62 97.879 23.958 98.411 ;
     RECT  25.056 97.757 25.074 98.419 ;
     RECT  1.62 98.411 23.418 98.609 ;
     RECT  25.056 98.419 25.11 98.635 ;
     RECT  24.372 98.635 25.11 98.861 ;
     RECT  24.372 98.861 25.074 98.987 ;
     RECT  24.516 98.987 25.074 99.149 ;
     RECT  0.108 99.157 0.126 99.245 ;
     RECT  24.516 99.149 24.534 99.293 ;
     RECT  1.62 98.609 23.382 99.733 ;
     RECT  0.54 99.535 0.558 99.773 ;
     RECT  25.056 99.979 25.074 100.229 ;
     RECT  1.62 99.733 23.454 100.273 ;
     RECT  1.62 100.273 23.958 100.507 ;
     RECT  1.62 100.507 24.462 100.679 ;
     RECT  25.812 99.733 25.83 100.679 ;
     RECT  2.232 100.679 24.462 101.755 ;
     RECT  2.232 101.755 25.074 102.029 ;
     RECT  25.812 101.731 25.83 102.269 ;
     RECT  2.268 102.029 25.074 102.659 ;
     RECT  2.268 102.659 24.498 102.797 ;
     RECT  24.444 102.797 24.498 103.001 ;
     RECT  2.268 102.797 23.454 103.199 ;
     RECT  24.444 103.001 24.462 103.271 ;
     RECT  2.268 103.199 23.238 103.343 ;
     RECT  2.415 103.343 23.238 103.379 ;
     RECT  2.415 103.379 21.114 103.469 ;
     RECT  21.96 103.379 23.238 103.469 ;
     RECT  10.44 103.469 13.662 103.541 ;
     RECT  22.104 103.469 22.878 103.541 ;
     RECT  19.944 103.469 21.114 103.577 ;
     RECT  10.728 103.541 13.662 103.649 ;
     RECT  15.3 103.469 16.002 103.649 ;
     RECT  17.46 103.469 18.99 103.649 ;
     RECT  20.664 103.577 21.114 103.649 ;
     RECT  2.415 103.469 4.914 103.697 ;
     RECT  2.592 103.697 4.914 103.757 ;
     RECT  5.652 103.469 9.342 103.757 ;
     RECT  11.808 103.649 13.662 103.757 ;
     RECT  15.804 103.649 15.822 103.757 ;
     RECT  17.856 103.649 18.99 103.757 ;
     RECT  22.104 103.541 22.842 103.757 ;
     RECT  2.592 103.757 2.754 103.805 ;
     RECT  7.704 103.757 8.334 103.805 ;
     RECT  12.528 103.757 13.194 103.805 ;
     RECT  18.108 103.757 18.99 103.805 ;
     RECT  7.956 103.805 7.974 103.853 ;
     RECT  18.108 103.805 18.558 103.853 ;
     RECT  4.5 103.757 4.914 104.333 ;
     RECT  12.528 103.805 13.122 104.861 ;
     RECT  2.736 103.805 2.754 104.909 ;
     RECT  18.108 103.853 18.126 104.909 ;
     RECT  4.896 104.333 4.914 105.725 ;
     RECT  13.104 104.861 13.122 105.725 ;
    LAYER M4 ;
     RECT  0.084 2.64 0.137 2.664 ;
     RECT  0.06 2.664 0.137 2.928 ;
     RECT  0.084 2.928 0.137 2.952 ;
     RECT  0.06 2.952 0.137 3.168 ;
     RECT  0.084 3.168 0.137 3.192 ;
     RECT  0.06 3.192 0.137 3.456 ;
     RECT  0.084 3.456 0.137 3.48 ;
     RECT  0.06 3.48 0.137 3.744 ;
     RECT  0.084 3.744 0.137 3.768 ;
     RECT  0.06 3.768 0.137 4.032 ;
     RECT  0.084 4.032 0.137 4.056 ;
     RECT  0.06 4.056 0.137 4.272 ;
     RECT  0.084 4.272 0.137 4.296 ;
     RECT  0.06 4.296 0.137 4.56 ;
     RECT  0.084 4.56 0.137 4.584 ;
     RECT  0.06 4.584 0.137 4.848 ;
     RECT  0.084 4.848 0.137 4.872 ;
     RECT  0.06 4.872 0.137 5.136 ;
     RECT  0.084 5.136 0.137 5.16 ;
     RECT  0.06 5.16 0.137 5.424 ;
     RECT  0.084 5.424 0.137 5.448 ;
     RECT  0.06 5.448 0.137 5.664 ;
     RECT  0.084 5.664 0.137 5.688 ;
     RECT  0.06 5.688 0.137 5.952 ;
     RECT  0.084 5.952 0.137 5.976 ;
     RECT  0.06 5.976 0.137 6.24 ;
     RECT  0.084 6.24 0.137 6.264 ;
     RECT  0.06 6.264 0.137 6.528 ;
     RECT  0.084 6.528 0.137 6.552 ;
     RECT  0.06 6.552 0.137 6.768 ;
     RECT  0.084 6.768 0.137 6.792 ;
     RECT  0.06 6.792 0.137 7.056 ;
     RECT  0.084 7.056 0.137 7.08 ;
     RECT  0.06 7.08 0.137 7.344 ;
     RECT  0.084 7.344 0.137 7.368 ;
     RECT  0.06 7.368 0.137 7.632 ;
     RECT  0.084 7.632 0.137 7.656 ;
     RECT  0.06 7.656 0.137 7.92 ;
     RECT  0.084 7.92 0.137 7.944 ;
     RECT  0.06 7.944 0.137 8.16 ;
     RECT  0.084 8.16 0.137 8.184 ;
     RECT  0.06 8.184 0.137 8.448 ;
     RECT  0.084 8.448 0.137 8.472 ;
     RECT  0.06 8.472 0.137 8.736 ;
     RECT  0.084 8.736 0.137 8.76 ;
     RECT  0.06 8.76 0.137 9.024 ;
     RECT  0.084 9.024 0.137 9.048 ;
     RECT  0.06 9.048 0.137 9.264 ;
     RECT  0.084 9.264 0.137 9.288 ;
     RECT  0.06 9.288 0.137 9.552 ;
     RECT  0.084 9.552 0.137 9.576 ;
     RECT  0.06 9.576 0.137 9.84 ;
     RECT  0.084 9.84 0.137 9.864 ;
     RECT  0.06 9.864 0.137 10.128 ;
     RECT  0.084 10.128 0.137 10.152 ;
     RECT  0.06 10.152 0.137 10.416 ;
     RECT  0.084 10.416 0.137 10.44 ;
     RECT  0.06 10.44 0.137 10.656 ;
     RECT  0.084 10.656 0.137 10.68 ;
     RECT  0.06 10.68 0.137 10.944 ;
     RECT  0.084 10.944 0.137 10.968 ;
     RECT  0.06 10.968 0.137 11.232 ;
     RECT  0.084 11.232 0.137 11.256 ;
     RECT  0.06 11.256 0.137 11.52 ;
     RECT  0.084 11.52 0.137 11.544 ;
     RECT  0.06 11.544 0.137 11.808 ;
     RECT  0.084 11.808 0.137 11.832 ;
     RECT  0.06 11.832 0.137 12.048 ;
     RECT  0.084 12.048 0.137 12.072 ;
     RECT  0.06 12.072 0.137 12.336 ;
     RECT  0.084 12.336 0.137 12.36 ;
     RECT  0.06 12.36 0.137 12.624 ;
     RECT  0.084 12.624 0.137 12.648 ;
     RECT  0.06 12.648 0.137 12.912 ;
     RECT  0.084 12.912 0.137 12.936 ;
     RECT  0.06 12.936 0.137 13.152 ;
     RECT  0.084 13.152 0.137 13.176 ;
     RECT  0.06 13.176 0.137 13.44 ;
     RECT  0.084 13.44 0.137 13.464 ;
     RECT  0.06 13.464 0.137 13.728 ;
     RECT  0.084 13.728 0.137 13.752 ;
     RECT  0.06 13.752 0.137 14.016 ;
     RECT  0.084 14.016 0.137 14.04 ;
     RECT  0.06 14.04 0.137 14.304 ;
     RECT  0.084 14.304 0.137 14.328 ;
     RECT  0.06 14.328 0.137 14.544 ;
     RECT  0.084 14.544 0.137 14.568 ;
     RECT  0.06 14.568 0.137 14.832 ;
     RECT  0.084 14.832 0.137 14.856 ;
     RECT  0.06 14.856 0.137 15.12 ;
     RECT  0.084 15.12 0.137 15.144 ;
     RECT  0.06 15.144 0.137 15.408 ;
     RECT  0.084 15.408 0.137 15.432 ;
     RECT  0.06 15.432 0.137 15.648 ;
     RECT  0.084 15.648 0.137 15.672 ;
     RECT  0.06 15.672 0.137 15.936 ;
     RECT  0.084 15.936 0.137 15.96 ;
     RECT  0.06 15.96 0.137 16.224 ;
     RECT  0.084 16.224 0.137 16.248 ;
     RECT  0.06 16.248 0.137 16.512 ;
     RECT  0.084 16.512 0.137 16.536 ;
     RECT  0.06 16.536 0.137 16.8 ;
     RECT  0.084 16.8 0.137 16.824 ;
     RECT  0.06 16.824 0.137 17.04 ;
     RECT  0.084 17.04 0.137 17.064 ;
     RECT  0.06 17.064 0.137 17.328 ;
     RECT  0.084 17.328 0.137 17.352 ;
     RECT  0.06 17.352 0.137 17.616 ;
     RECT  0.084 17.616 0.137 17.64 ;
     RECT  0.06 17.64 0.137 17.904 ;
     RECT  0.084 17.904 0.137 17.928 ;
     RECT  0.06 17.928 0.137 18.192 ;
     RECT  0.084 18.192 0.137 18.216 ;
     RECT  0.06 18.216 0.137 18.432 ;
     RECT  0.084 18.432 0.137 18.456 ;
     RECT  0.06 18.456 0.137 18.72 ;
     RECT  0.084 18.72 0.137 18.744 ;
     RECT  0.06 18.744 0.137 19.008 ;
     RECT  0.084 19.008 0.137 19.032 ;
     RECT  0.06 19.032 0.137 19.296 ;
     RECT  0.084 19.296 0.137 19.32 ;
     RECT  0.06 19.32 0.137 19.536 ;
     RECT  0.084 19.536 0.137 19.56 ;
     RECT  0.06 19.56 0.137 19.824 ;
     RECT  0.084 19.824 0.137 19.848 ;
     RECT  0.06 19.848 0.137 20.112 ;
     RECT  0.084 20.112 0.137 20.136 ;
     RECT  0.06 20.136 0.137 20.4 ;
     RECT  0.084 20.4 0.137 20.424 ;
     RECT  0.06 20.424 0.137 20.688 ;
     RECT  0.084 20.688 0.137 20.712 ;
     RECT  0.06 20.712 0.137 20.928 ;
     RECT  0.084 20.928 0.137 20.952 ;
     RECT  0.06 20.952 0.137 21.216 ;
     RECT  0.084 21.216 0.137 21.24 ;
     RECT  0.06 21.24 0.137 21.504 ;
     RECT  0.084 21.504 0.137 21.528 ;
     RECT  0.06 21.528 0.137 21.792 ;
     RECT  0.084 21.792 0.137 21.816 ;
     RECT  0.06 21.816 0.137 22.032 ;
     RECT  0.084 22.032 0.137 22.056 ;
     RECT  0.06 22.056 0.137 22.32 ;
     RECT  0.084 22.32 0.137 22.344 ;
     RECT  0.06 22.344 0.137 22.608 ;
     RECT  0.084 22.608 0.137 22.632 ;
     RECT  0.06 22.632 0.137 22.896 ;
     RECT  0.084 22.896 0.137 22.92 ;
     RECT  0.06 22.92 0.137 23.184 ;
     RECT  0.084 23.184 0.137 23.208 ;
     RECT  0.06 23.208 0.137 23.424 ;
     RECT  0.084 23.424 0.137 23.448 ;
     RECT  0.06 23.448 0.137 23.712 ;
     RECT  0.084 23.712 0.137 23.736 ;
     RECT  0.06 23.736 0.137 24 ;
     RECT  0.084 24 0.137 24.024 ;
     RECT  0.06 24.024 0.137 24.288 ;
     RECT  0.084 24.288 0.137 24.312 ;
     RECT  0.06 24.312 0.137 24.576 ;
     RECT  0.084 24.576 0.137 24.6 ;
     RECT  0.06 24.6 0.137 24.816 ;
     RECT  0.084 24.816 0.137 24.84 ;
     RECT  0.06 24.84 0.137 25.104 ;
     RECT  0.084 25.104 0.137 25.128 ;
     RECT  0.06 25.128 0.137 25.392 ;
     RECT  0.084 25.392 0.137 25.416 ;
     RECT  0.06 25.416 0.137 25.68 ;
     RECT  0.084 25.68 0.137 25.704 ;
     RECT  0.06 25.704 0.137 25.92 ;
     RECT  0.084 25.92 0.137 25.944 ;
     RECT  0.06 25.944 0.137 26.208 ;
     RECT  0.084 26.208 0.137 26.232 ;
     RECT  0.06 26.232 0.137 26.496 ;
     RECT  0.084 26.496 0.137 26.52 ;
     RECT  0.06 26.52 0.137 26.784 ;
     RECT  0.084 26.784 0.137 26.808 ;
     RECT  0.06 26.808 0.137 27.072 ;
     RECT  0.084 27.072 0.137 27.096 ;
     RECT  0.06 27.096 0.137 27.312 ;
     RECT  0.084 27.312 0.137 27.336 ;
     RECT  0.06 27.336 0.137 27.6 ;
     RECT  0.084 27.6 0.137 27.624 ;
     RECT  0.06 27.624 0.137 27.888 ;
     RECT  0.084 27.888 0.137 27.912 ;
     RECT  0.06 27.912 0.137 28.176 ;
     RECT  0.084 28.176 0.137 28.2 ;
     RECT  0.06 28.2 0.137 28.416 ;
     RECT  0.084 28.416 0.137 28.44 ;
     RECT  0.06 28.44 0.137 28.704 ;
     RECT  0.084 28.704 0.137 28.728 ;
     RECT  0.06 28.728 0.137 28.992 ;
     RECT  0.084 28.992 0.137 29.016 ;
     RECT  0.06 29.016 0.137 29.28 ;
     RECT  0.084 29.28 0.137 29.304 ;
     RECT  0.06 29.304 0.137 29.568 ;
     RECT  0.084 29.568 0.137 29.592 ;
     RECT  0.06 29.592 0.137 29.808 ;
     RECT  0.084 29.808 0.137 29.832 ;
     RECT  0.06 29.832 0.137 30.096 ;
     RECT  0.084 30.096 0.137 30.12 ;
     RECT  0.06 30.12 0.137 30.384 ;
     RECT  0.084 30.384 0.137 30.408 ;
     RECT  0.06 30.408 0.137 30.672 ;
     RECT  0.084 30.672 0.137 30.696 ;
     RECT  0.06 30.696 0.137 30.912 ;
     RECT  0.084 30.912 0.137 30.936 ;
     RECT  0.06 30.936 0.137 31.2 ;
     RECT  0.084 31.2 0.137 31.224 ;
     RECT  0.06 31.224 0.137 31.488 ;
     RECT  0.084 31.488 0.137 31.512 ;
     RECT  0.06 31.512 0.137 31.776 ;
     RECT  0.084 31.776 0.137 31.8 ;
     RECT  0.06 31.8 0.137 32.064 ;
     RECT  0.084 32.064 0.137 32.088 ;
     RECT  0.06 32.088 0.137 32.304 ;
     RECT  0.084 32.304 0.137 32.328 ;
     RECT  0.06 32.328 0.137 32.592 ;
     RECT  0.084 32.592 0.137 32.616 ;
     RECT  0.06 32.616 0.137 32.88 ;
     RECT  0.084 32.88 0.137 32.904 ;
     RECT  0.06 32.904 0.137 33.168 ;
     RECT  0.084 33.168 0.137 33.192 ;
     RECT  0.06 33.192 0.137 33.456 ;
     RECT  0.084 33.456 0.137 33.48 ;
     RECT  0.06 33.48 0.137 33.696 ;
     RECT  0.084 33.696 0.137 33.72 ;
     RECT  0.06 33.72 0.137 33.984 ;
     RECT  0.084 33.984 0.137 34.008 ;
     RECT  0.06 34.008 0.137 34.272 ;
     RECT  0.084 34.272 0.137 34.296 ;
     RECT  0.06 34.296 0.137 34.56 ;
     RECT  0.084 34.56 0.137 34.584 ;
     RECT  0.06 34.584 0.137 34.8 ;
     RECT  0.084 34.8 0.137 34.824 ;
     RECT  0.06 34.824 0.137 35.088 ;
     RECT  0.084 35.088 0.137 35.112 ;
     RECT  0.06 35.112 0.137 35.376 ;
     RECT  0.084 35.376 0.137 35.4 ;
     RECT  0.06 35.4 0.137 35.664 ;
     RECT  0.084 35.664 0.137 35.688 ;
     RECT  0.06 35.688 0.137 35.952 ;
     RECT  0.084 35.952 0.137 35.976 ;
     RECT  0.06 35.976 0.137 36.192 ;
     RECT  0.084 36.192 0.137 36.216 ;
     RECT  0.06 36.216 0.137 36.48 ;
     RECT  0.084 36.48 0.137 36.504 ;
     RECT  0.06 36.504 0.137 36.768 ;
     RECT  0.084 36.768 0.137 36.792 ;
     RECT  0.06 36.792 0.137 37.056 ;
     RECT  0.084 37.056 0.137 37.08 ;
     RECT  0.06 37.08 0.137 37.296 ;
     RECT  0.084 37.296 0.137 37.32 ;
     RECT  0.06 37.32 0.137 37.584 ;
     RECT  0.084 37.584 0.137 37.608 ;
     RECT  0.06 37.608 0.137 37.872 ;
     RECT  0.084 37.872 0.137 37.896 ;
     RECT  0.06 37.896 0.137 38.16 ;
     RECT  0.084 38.16 0.137 38.184 ;
     RECT  0.06 38.184 0.137 38.448 ;
     RECT  0.084 38.448 0.137 38.472 ;
     RECT  0.06 38.472 0.137 38.688 ;
     RECT  0.084 38.688 0.137 38.712 ;
     RECT  0.06 38.712 0.137 38.976 ;
     RECT  0.084 38.976 0.137 39 ;
     RECT  0.06 39 0.137 39.264 ;
     RECT  0.084 39.264 0.137 39.288 ;
     RECT  0.06 39.288 0.137 39.552 ;
     RECT  0.084 39.552 0.137 39.576 ;
     RECT  0.06 39.576 0.137 39.84 ;
     RECT  0.084 39.84 0.137 39.864 ;
     RECT  0.06 39.864 0.137 40.08 ;
     RECT  0.084 40.08 0.137 40.104 ;
     RECT  0.06 40.104 0.137 40.368 ;
     RECT  0.084 40.368 0.137 40.392 ;
     RECT  0.06 40.392 0.137 40.656 ;
     RECT  0.084 40.656 0.137 40.68 ;
     RECT  0.06 40.68 0.137 40.944 ;
     RECT  0.084 40.944 0.137 40.968 ;
     RECT  0.06 40.968 0.137 41.184 ;
     RECT  0.084 41.184 0.137 41.208 ;
     RECT  0.06 41.208 0.137 41.472 ;
     RECT  0.084 41.472 0.137 41.496 ;
     RECT  0.06 41.496 0.137 41.76 ;
     RECT  0.084 41.76 0.137 41.784 ;
     RECT  0.06 41.784 0.137 42.048 ;
     RECT  0.084 42.048 0.137 42.072 ;
     RECT  0.06 42.072 0.137 42.336 ;
     RECT  0.084 42.336 0.137 42.36 ;
     RECT  0.06 42.36 0.137 42.576 ;
     RECT  0.084 42.576 0.137 42.6 ;
     RECT  0.06 42.6 0.137 42.864 ;
     RECT  0.084 42.864 0.137 42.888 ;
     RECT  0.06 42.888 0.137 43.152 ;
     RECT  0.084 43.152 0.137 43.176 ;
     RECT  0.06 43.176 0.137 43.44 ;
     RECT  0.084 43.44 0.137 43.464 ;
     RECT  0.06 43.464 0.137 43.68 ;
     RECT  0.084 43.68 0.137 43.704 ;
     RECT  0.06 43.704 0.137 43.968 ;
     RECT  0.084 43.968 0.137 43.992 ;
     RECT  0.06 43.992 0.137 44.256 ;
     RECT  0.084 44.256 0.137 44.28 ;
     RECT  0.06 44.28 0.137 44.544 ;
     RECT  0.084 44.544 0.137 44.568 ;
     RECT  0.06 44.568 0.137 44.832 ;
     RECT  0.084 44.832 0.137 44.856 ;
     RECT  0.06 44.856 0.137 45.072 ;
     RECT  0.084 45.072 0.137 45.096 ;
     RECT  0.06 45.096 0.137 45.36 ;
     RECT  0.084 45.36 0.137 45.384 ;
     RECT  0.06 45.384 0.137 45.648 ;
     RECT  0.084 45.648 0.137 45.672 ;
     RECT  0.06 45.672 0.137 45.936 ;
     RECT  0.084 45.936 0.137 45.96 ;
     RECT  0.06 45.96 0.137 46.176 ;
     RECT  0.084 46.176 0.137 46.2 ;
     RECT  0.06 46.2 0.137 46.464 ;
     RECT  0.084 46.464 0.137 46.488 ;
     RECT  0.06 46.488 0.137 46.752 ;
     RECT  0.084 46.752 0.137 46.776 ;
     RECT  0.06 46.776 0.137 47.04 ;
     RECT  0.084 47.04 0.137 47.064 ;
     RECT  0.06 47.064 0.137 47.328 ;
     RECT  0.084 47.328 0.137 47.352 ;
     RECT  0.06 47.352 0.137 47.568 ;
     RECT  0.084 47.568 0.137 47.592 ;
     RECT  0.06 47.592 0.137 47.856 ;
     RECT  0.084 47.856 0.137 47.88 ;
     RECT  0.06 47.88 0.137 48.144 ;
     RECT  0.084 48.144 0.137 48.168 ;
     RECT  0.06 48.168 0.137 48.432 ;
     RECT  0.084 48.432 0.137 48.456 ;
     RECT  0.06 48.456 0.137 48.72 ;
     RECT  0.084 48.72 0.137 48.744 ;
     RECT  0.06 48.744 0.137 48.96 ;
     RECT  0.084 48.96 0.137 48.984 ;
     RECT  0.06 48.984 0.137 49.248 ;
     RECT  0.084 49.248 0.137 49.272 ;
     RECT  0.06 49.272 0.137 49.536 ;
     RECT  0.084 49.536 0.137 49.56 ;
     RECT  0.06 49.56 0.137 49.824 ;
     RECT  0.084 49.824 0.137 49.848 ;
     RECT  0.06 49.848 0.137 50.064 ;
     RECT  0.084 50.064 0.137 50.088 ;
     RECT  0.06 50.088 0.137 50.352 ;
     RECT  0.084 50.352 0.137 50.376 ;
     RECT  0.06 50.376 0.137 50.64 ;
     RECT  0.084 50.64 0.137 50.664 ;
     RECT  0.06 50.664 0.137 50.928 ;
     RECT  0.084 50.928 0.137 50.952 ;
     RECT  0.06 50.952 0.137 51.216 ;
     RECT  0.084 51.216 0.137 51.24 ;
     RECT  0.06 51.24 0.137 51.456 ;
     RECT  0.084 51.456 0.137 51.48 ;
     RECT  0.06 51.48 0.137 51.744 ;
     RECT  0.084 51.744 0.137 51.768 ;
     RECT  0.06 51.768 0.137 52.032 ;
     RECT  0.084 52.032 0.137 52.056 ;
     RECT  0.06 52.056 0.137 52.32 ;
     RECT  0.084 52.32 0.137 52.344 ;
     RECT  0.06 52.344 0.137 52.56 ;
     RECT  0.084 52.56 0.137 52.584 ;
     RECT  0.06 52.584 0.137 52.848 ;
     RECT  0.084 52.848 0.137 52.872 ;
     RECT  0.06 52.872 0.137 53.136 ;
     RECT  0.084 53.136 0.137 53.16 ;
     RECT  0.06 53.16 0.137 53.424 ;
     RECT  0.084 53.424 0.137 53.448 ;
     RECT  0.06 53.448 0.137 53.712 ;
     RECT  0.084 53.712 0.137 53.736 ;
     RECT  0.06 53.736 0.137 53.952 ;
     RECT  0.084 53.952 0.137 53.976 ;
     RECT  0.06 53.976 0.137 54.24 ;
     RECT  0.084 54.24 0.137 54.264 ;
     RECT  0.06 54.264 0.137 54.528 ;
     RECT  0.084 54.528 0.137 54.552 ;
     RECT  0.06 54.552 0.137 54.816 ;
     RECT  0.084 54.816 0.137 54.84 ;
     RECT  0.06 54.84 0.137 55.104 ;
     RECT  0.084 55.104 0.137 55.128 ;
     RECT  0.06 55.128 0.137 55.344 ;
     RECT  0.084 55.344 0.137 55.368 ;
     RECT  0.06 55.368 0.137 55.632 ;
     RECT  0.084 55.632 0.137 55.656 ;
     RECT  0.06 55.656 0.137 55.92 ;
     RECT  0.084 55.92 0.137 55.944 ;
     RECT  0.06 55.944 0.137 56.208 ;
     RECT  0.084 56.208 0.137 56.232 ;
     RECT  0.06 56.232 0.137 56.448 ;
     RECT  0.084 56.448 0.137 56.472 ;
     RECT  0.06 56.472 0.137 56.736 ;
     RECT  0.084 56.736 0.137 56.76 ;
     RECT  0.06 56.76 0.137 57.024 ;
     RECT  0.084 57.024 0.137 57.048 ;
     RECT  0.06 57.048 0.137 57.312 ;
     RECT  0.084 57.312 0.137 57.336 ;
     RECT  0.06 57.336 0.137 57.6 ;
     RECT  0.084 57.6 0.137 57.624 ;
     RECT  0.06 57.624 0.137 57.84 ;
     RECT  0.084 57.84 0.137 57.864 ;
     RECT  0.06 57.864 0.137 58.128 ;
     RECT  0.084 58.128 0.137 58.152 ;
     RECT  0.06 58.152 0.137 58.416 ;
     RECT  0.084 58.416 0.137 58.44 ;
     RECT  0.06 58.44 0.137 58.704 ;
     RECT  0.084 58.704 0.137 58.728 ;
     RECT  0.06 58.728 0.137 58.944 ;
     RECT  0.084 58.944 0.137 58.968 ;
     RECT  0.06 58.968 0.137 59.232 ;
     RECT  0.084 59.232 0.137 59.256 ;
     RECT  0.06 59.256 0.137 59.52 ;
     RECT  0.084 59.52 0.137 59.544 ;
     RECT  0.06 59.544 0.137 59.808 ;
     RECT  0.084 59.808 0.137 59.832 ;
     RECT  0.06 59.832 0.137 60.096 ;
     RECT  0.084 60.096 0.137 60.12 ;
     RECT  0.06 60.12 0.137 60.336 ;
     RECT  0.084 60.336 0.137 60.36 ;
     RECT  0.06 60.36 0.137 60.624 ;
     RECT  0.084 60.624 0.137 60.648 ;
     RECT  0.06 60.648 0.137 60.912 ;
     RECT  0.084 60.912 0.137 60.936 ;
     RECT  0.06 60.936 0.137 61.2 ;
     RECT  0.084 61.2 0.137 61.224 ;
     RECT  0.06 61.224 0.137 61.44 ;
     RECT  0.084 61.44 0.137 61.464 ;
     RECT  0.06 61.464 0.137 61.728 ;
     RECT  0.084 61.728 0.137 61.752 ;
     RECT  0.06 61.752 0.137 62.016 ;
     RECT  0.084 62.016 0.137 62.04 ;
     RECT  0.06 62.04 0.137 62.304 ;
     RECT  0.084 62.304 0.137 62.328 ;
     RECT  0.06 62.328 0.137 62.592 ;
     RECT  0.084 62.592 0.137 62.616 ;
     RECT  0.06 62.616 0.137 62.832 ;
     RECT  0.084 62.832 0.137 62.856 ;
     RECT  0.06 62.856 0.137 63.12 ;
     RECT  0.084 63.12 0.137 63.144 ;
     RECT  0.06 63.144 0.137 63.408 ;
     RECT  0.084 63.408 0.137 63.432 ;
     RECT  0.06 63.432 0.137 63.696 ;
     RECT  0.084 63.696 0.137 63.72 ;
     RECT  0.06 63.72 0.137 63.984 ;
     RECT  0.084 63.984 0.137 64.008 ;
     RECT  0.06 64.008 0.137 64.224 ;
     RECT  0.084 64.224 0.137 64.248 ;
     RECT  0.06 64.248 0.137 64.512 ;
     RECT  0.084 64.512 0.137 64.536 ;
     RECT  0.06 64.536 0.137 64.8 ;
     RECT  0.084 64.8 0.137 64.824 ;
     RECT  0.06 64.824 0.137 65.088 ;
     RECT  0.084 65.088 0.137 65.112 ;
     RECT  0.06 65.112 0.137 65.328 ;
     RECT  0.084 65.328 0.137 65.352 ;
     RECT  0.06 65.352 0.137 65.616 ;
     RECT  0.084 65.616 0.137 65.64 ;
     RECT  0.06 65.64 0.137 65.904 ;
     RECT  0.084 65.904 0.137 65.928 ;
     RECT  0.06 65.928 0.137 66.192 ;
     RECT  0.084 66.192 0.137 66.216 ;
     RECT  0.06 66.216 0.137 66.48 ;
     RECT  0.084 66.48 0.137 66.504 ;
     RECT  0.06 66.504 0.137 66.72 ;
     RECT  0.084 66.72 0.137 66.744 ;
     RECT  0.06 66.744 0.137 67.008 ;
     RECT  0.084 67.008 0.137 67.032 ;
     RECT  0.06 67.032 0.137 67.296 ;
     RECT  0.084 67.296 0.137 67.32 ;
     RECT  0.06 67.32 0.137 67.584 ;
     RECT  0.084 67.584 0.137 67.608 ;
     RECT  0.06 67.608 0.137 67.824 ;
     RECT  0.084 67.824 0.137 67.848 ;
     RECT  0.06 67.848 0.137 68.112 ;
     RECT  0.084 68.112 0.137 68.136 ;
     RECT  0.06 68.136 0.137 68.4 ;
     RECT  0.084 68.4 0.137 68.424 ;
     RECT  0.06 68.424 0.137 68.688 ;
     RECT  0.084 68.688 0.137 68.712 ;
     RECT  0.06 68.712 0.137 68.976 ;
     RECT  0.084 68.976 0.137 69 ;
     RECT  0.06 69 0.137 69.216 ;
     RECT  0.084 69.216 0.137 69.24 ;
     RECT  0.06 69.24 0.137 69.504 ;
     RECT  0.084 69.504 0.137 69.528 ;
     RECT  0.06 69.528 0.137 69.792 ;
     RECT  0.084 69.792 0.137 69.816 ;
     RECT  0.06 69.816 0.137 70.08 ;
     RECT  0.084 70.08 0.137 70.104 ;
     RECT  0.06 70.104 0.137 70.368 ;
     RECT  0.084 70.368 0.137 70.392 ;
     RECT  0.06 70.392 0.137 70.608 ;
     RECT  0.084 70.608 0.137 70.632 ;
     RECT  0.06 70.632 0.137 70.896 ;
     RECT  0.084 70.896 0.137 70.92 ;
     RECT  0.06 70.92 0.137 71.184 ;
     RECT  0.084 71.184 0.137 71.208 ;
     RECT  0.06 71.208 0.137 71.472 ;
     RECT  0.084 71.472 0.137 71.496 ;
     RECT  0.06 71.496 0.137 71.712 ;
     RECT  0.084 71.712 0.137 71.736 ;
     RECT  0.06 71.736 0.137 72 ;
     RECT  0.084 72 0.137 72.024 ;
     RECT  0.06 72.024 0.137 72.288 ;
     RECT  0.084 72.288 0.137 72.312 ;
     RECT  0.06 72.312 0.137 72.576 ;
     RECT  0.084 72.576 0.137 72.6 ;
     RECT  0.06 72.6 0.137 72.864 ;
     RECT  0.084 72.864 0.137 72.888 ;
     RECT  0.06 72.888 0.137 73.104 ;
     RECT  0.084 73.104 0.137 73.128 ;
     RECT  0.06 73.128 0.137 73.392 ;
     RECT  0.084 73.392 0.137 73.416 ;
     RECT  0.06 73.416 0.137 73.68 ;
     RECT  0.084 73.68 0.137 73.704 ;
     RECT  0.06 73.704 0.137 73.968 ;
     RECT  0.084 73.968 0.137 73.992 ;
     RECT  0.06 73.992 0.137 74.208 ;
     RECT  0.084 74.208 0.137 74.232 ;
     RECT  0.06 74.232 0.137 74.496 ;
     RECT  0.084 74.496 0.137 74.52 ;
     RECT  0.06 74.52 0.137 74.784 ;
     RECT  0.084 74.784 0.137 74.808 ;
     RECT  0.06 74.808 0.137 75.072 ;
     RECT  0.084 75.072 0.137 75.096 ;
     RECT  0.06 75.096 0.137 75.36 ;
     RECT  0.084 75.36 0.137 75.384 ;
     RECT  0.06 75.384 0.137 75.6 ;
     RECT  0.084 75.6 0.137 75.624 ;
     RECT  0.06 75.624 0.137 75.888 ;
     RECT  0.084 75.888 0.137 75.912 ;
     RECT  0.06 75.912 0.137 76.176 ;
     RECT  0.084 76.176 0.137 76.2 ;
     RECT  0.06 76.2 0.137 76.464 ;
     RECT  0.084 76.464 0.137 76.488 ;
     RECT  0.06 76.488 0.137 76.704 ;
     RECT  0.084 76.704 0.137 76.728 ;
     RECT  0.06 76.728 0.137 76.992 ;
     RECT  0.084 76.992 0.137 77.016 ;
     RECT  0.06 77.016 0.137 77.28 ;
     RECT  0.084 77.28 0.137 77.304 ;
     RECT  0.06 77.304 0.137 77.568 ;
     RECT  0.084 77.568 0.137 77.592 ;
     RECT  0.06 77.592 0.137 77.856 ;
     RECT  0.084 77.856 0.137 77.88 ;
     RECT  0.06 77.88 0.137 78.096 ;
     RECT  0.084 78.096 0.137 78.12 ;
     RECT  0.06 78.12 0.137 78.384 ;
     RECT  0.084 78.384 0.137 78.408 ;
     RECT  0.06 78.408 0.137 78.672 ;
     RECT  0.084 78.672 0.137 78.696 ;
     RECT  0.06 78.696 0.137 78.96 ;
     RECT  0.084 78.96 0.137 78.984 ;
     RECT  0.06 78.984 0.137 79.248 ;
     RECT  0.084 79.248 0.137 79.272 ;
     RECT  0.06 79.272 0.137 79.488 ;
     RECT  0.084 79.488 0.137 79.512 ;
     RECT  0.06 79.512 0.137 79.776 ;
     RECT  0.084 79.776 0.137 79.8 ;
     RECT  0.06 79.8 0.137 80.064 ;
     RECT  0.084 80.064 0.137 80.088 ;
     RECT  0.06 80.088 0.137 80.352 ;
     RECT  0.084 80.352 0.137 80.376 ;
     RECT  0.06 80.376 0.137 80.592 ;
     RECT  0.084 80.592 0.137 80.616 ;
     RECT  0.06 80.616 0.137 80.88 ;
     RECT  0.084 80.88 0.137 80.904 ;
     RECT  0.06 80.904 0.137 81.168 ;
     RECT  0.084 81.168 0.137 81.192 ;
     RECT  0.06 81.192 0.137 81.456 ;
     RECT  0.084 81.456 0.137 81.48 ;
     RECT  0.06 81.48 0.137 81.744 ;
     RECT  0.084 81.744 0.137 81.768 ;
     RECT  0.06 81.768 0.137 81.984 ;
     RECT  0.084 81.984 0.137 82.008 ;
     RECT  0.06 82.008 0.137 82.272 ;
     RECT  0.084 82.272 0.137 82.296 ;
     RECT  0.06 82.296 0.137 82.56 ;
     RECT  0.084 82.56 0.137 82.584 ;
     RECT  0.06 82.584 0.137 82.848 ;
     RECT  0.084 82.848 0.137 82.872 ;
     RECT  0.06 82.872 0.137 83.088 ;
     RECT  0.084 83.088 0.137 83.112 ;
     RECT  0.06 83.112 0.137 83.376 ;
     RECT  0.084 83.376 0.137 83.4 ;
     RECT  0.06 83.4 0.137 83.664 ;
     RECT  0.084 83.664 0.137 83.688 ;
     RECT  0.06 83.688 0.137 83.952 ;
     RECT  0.084 83.952 0.137 83.976 ;
     RECT  0.06 83.976 0.137 84.24 ;
     RECT  0.084 84.24 0.137 84.264 ;
     RECT  0.06 84.264 0.137 84.48 ;
     RECT  0.084 84.48 0.137 84.504 ;
     RECT  0.06 84.504 0.137 84.768 ;
     RECT  0.084 84.768 0.137 84.792 ;
     RECT  0.06 84.792 0.137 85.056 ;
     RECT  0.084 85.056 0.137 85.08 ;
     RECT  0.06 85.08 0.137 85.344 ;
     RECT  0.084 85.344 0.137 85.368 ;
     RECT  0.06 85.368 0.137 85.632 ;
     RECT  0.084 85.632 0.137 85.656 ;
     RECT  0.06 85.656 0.137 85.872 ;
     RECT  0.084 85.872 0.137 85.896 ;
     RECT  0.06 85.896 0.137 86.16 ;
     RECT  0.084 86.16 0.137 86.184 ;
     RECT  0.06 86.184 0.137 86.448 ;
     RECT  0.084 86.448 0.137 86.472 ;
     RECT  0.06 86.472 0.137 86.736 ;
     RECT  0.084 86.736 0.137 86.76 ;
     RECT  0.06 86.76 0.137 86.976 ;
     RECT  0.084 86.976 0.137 87 ;
     RECT  0.06 87 0.137 87.264 ;
     RECT  0.084 87.264 0.137 87.288 ;
     RECT  0.06 87.288 0.137 87.552 ;
     RECT  0.084 87.552 0.137 87.576 ;
     RECT  0.06 87.576 0.137 87.84 ;
     RECT  0.084 87.84 0.137 87.864 ;
     RECT  0.06 87.864 0.137 88.128 ;
     RECT  0.084 88.128 0.137 88.152 ;
     RECT  0.06 88.152 0.137 88.368 ;
     RECT  0.084 88.368 0.137 88.392 ;
     RECT  0.06 88.392 0.137 88.656 ;
     RECT  0.084 88.656 0.137 88.68 ;
     RECT  0.06 88.68 0.137 88.944 ;
     RECT  0.084 88.944 0.137 88.968 ;
     RECT  0.06 88.968 0.137 89.232 ;
     RECT  0.084 89.232 0.137 89.256 ;
     RECT  0.06 89.256 0.137 89.472 ;
     RECT  0.084 89.472 0.137 89.496 ;
     RECT  0.06 89.496 0.137 89.76 ;
     RECT  0.084 89.76 0.137 89.784 ;
     RECT  0.06 89.784 0.137 90.048 ;
     RECT  0.084 90.048 0.137 90.072 ;
     RECT  0.06 90.072 0.137 90.336 ;
     RECT  0.084 90.336 0.137 90.36 ;
     RECT  0.06 90.36 0.137 90.624 ;
     RECT  0.084 90.624 0.137 90.648 ;
     RECT  0.06 90.648 0.137 90.864 ;
     RECT  0.084 90.864 0.137 90.888 ;
     RECT  0.06 90.888 0.137 91.152 ;
     RECT  0.084 91.152 0.137 91.176 ;
     RECT  0.06 91.176 0.137 91.44 ;
     RECT  0.084 91.44 0.137 91.464 ;
     RECT  0.06 91.464 0.137 91.728 ;
     RECT  0.084 91.728 0.137 91.752 ;
     RECT  0.06 91.752 0.137 91.968 ;
     RECT  0.084 91.968 0.137 91.992 ;
     RECT  0.06 91.992 0.137 92.256 ;
     RECT  0.084 92.256 0.137 92.28 ;
     RECT  0.06 92.28 0.137 92.544 ;
     RECT  0.084 92.544 0.137 92.568 ;
     RECT  0.06 92.568 0.137 92.832 ;
     RECT  0.084 92.832 0.137 92.856 ;
     RECT  0.06 92.856 0.137 93.12 ;
     RECT  0.084 93.12 0.137 93.144 ;
     RECT  0.06 93.144 0.137 93.36 ;
     RECT  0.084 93.36 0.137 93.384 ;
     RECT  0.06 93.384 0.137 93.648 ;
     RECT  0.084 93.648 0.137 93.672 ;
     RECT  0.06 93.672 0.137 93.936 ;
     RECT  0.084 93.936 0.137 93.96 ;
     RECT  0.06 93.96 0.137 94.224 ;
     RECT  0.084 94.224 0.137 94.248 ;
     RECT  0.06 94.248 0.137 94.512 ;
     RECT  0.084 94.512 0.137 94.536 ;
     RECT  0.06 94.536 0.137 94.752 ;
     RECT  0.084 94.752 0.137 94.776 ;
     RECT  0.06 94.776 0.137 95.04 ;
     RECT  0.084 95.04 0.137 95.064 ;
     RECT  0.06 95.064 0.137 95.328 ;
     RECT  0.084 95.328 0.137 95.352 ;
     RECT  0.06 95.352 0.137 95.616 ;
     RECT  0.084 95.616 0.137 95.64 ;
     RECT  0.06 95.64 0.137 95.856 ;
     RECT  0.084 95.856 0.137 95.88 ;
     RECT  0.06 95.88 0.137 96.144 ;
     RECT  0.084 96.144 0.137 96.168 ;
     RECT  0.06 96.168 0.137 96.432 ;
     RECT  0.084 96.432 0.137 96.456 ;
     RECT  0.06 96.456 0.137 96.72 ;
     RECT  0.084 96.72 0.137 96.744 ;
     RECT  0.06 96.744 0.137 97.008 ;
     RECT  0.084 97.008 0.137 97.032 ;
     RECT  0.06 97.032 0.137 97.248 ;
     RECT  0.084 97.248 0.137 97.272 ;
     RECT  0.06 97.272 0.137 97.536 ;
     RECT  0.084 97.536 0.137 97.56 ;
     RECT  0.06 97.56 0.137 97.824 ;
     RECT  0.084 97.824 0.137 97.848 ;
     RECT  0.06 97.848 0.137 98.112 ;
     RECT  0.084 98.112 0.137 98.136 ;
     RECT  0.06 98.136 0.137 98.352 ;
     RECT  0.084 98.352 0.137 98.376 ;
     RECT  0.06 98.376 0.137 98.64 ;
     RECT  0.084 98.64 0.137 98.664 ;
     RECT  0.06 98.664 0.137 98.928 ;
     RECT  0.084 98.928 0.137 98.952 ;
     RECT  0.06 98.952 0.137 99.216 ;
     RECT  0.084 99.216 0.137 99.24 ;
     RECT  0.06 99.24 0.137 99.504 ;
     RECT  0.084 99.504 0.137 99.528 ;
     RECT  0.06 99.528 0.137 99.744 ;
     RECT  0.084 99.744 0.137 99.768 ;
     RECT  0.06 99.768 0.137 100.032 ;
     RECT  0.084 100.032 0.137 100.056 ;
     RECT  0.06 100.056 0.137 100.512 ;
     RECT  0.084 100.512 0.137 100.536 ;
     RECT  0.06 100.536 0.137 100.752 ;
     RECT  0.084 100.752 0.137 100.776 ;
     RECT  0.06 100.776 0.137 100.992 ;
     RECT  0.084 100.992 0.137 101.016 ;
     RECT  0.06 101.016 0.137 101.232 ;
     RECT  0.084 101.232 0.137 101.256 ;
     RECT  0.06 101.256 0.137 101.52 ;
     RECT  0.084 101.52 0.137 101.544 ;
     RECT  0.06 101.544 0.137 101.76 ;
     RECT  0.084 101.76 0.137 101.784 ;
     RECT  0.06 101.784 0.137 102 ;
     RECT  0.084 102 0.137 102.024 ;
     RECT  0.06 102.024 0.137 102.24 ;
     RECT  0.084 102.24 0.137 102.264 ;
     RECT  0.06 102.264 0.137 102.48 ;
     RECT  0.084 102.48 0.137 102.504 ;
     RECT  0.06 102.504 0.137 102.768 ;
     RECT  0.084 102.768 0.137 102.792 ;
     RECT  0.06 102.792 0.137 103.008 ;
     RECT  0.084 103.008 0.137 103.032 ;
     RECT  0.137 87.888 1.669 103.032 ;
     RECT  1.669 87.888 2.245 103.224 ;
     RECT  0.137 2.64 2.408 86.808 ;
     RECT  2.245 87.888 2.408 103.272 ;
     RECT  2.408 2.148 2.512 103.692 ;
     RECT  2.512 2.418 2.581 103.692 ;
     RECT  2.581 2.418 2.665 103.8 ;
     RECT  2.665 2.418 2.704 103.752 ;
     RECT  2.704 11.232 2.765 11.784 ;
     RECT  2.704 47.328 2.765 48.168 ;
     RECT  2.704 51.456 2.765 53.4 ;
     RECT  2.704 29.808 2.801 29.832 ;
     RECT  2.704 35.856 2.801 42.792 ;
     RECT  2.765 47.808 2.801 48.168 ;
     RECT  2.704 49.536 2.801 49.848 ;
     RECT  2.704 54.576 2.801 60.936 ;
     RECT  2.704 73.248 2.873 74.424 ;
     RECT  2.704 77.088 2.873 77.304 ;
     RECT  2.765 51.744 2.909 53.4 ;
     RECT  2.704 69.504 2.909 70.968 ;
     RECT  2.725 104.88 2.915 104.904 ;
     RECT  2.801 47.808 3.089 47.88 ;
     RECT  2.873 73.248 3.089 74.328 ;
     RECT  2.704 78.624 3.089 79.272 ;
     RECT  3.089 73.392 3.125 74.328 ;
     RECT  2.704 84.336 3.197 88.584 ;
     RECT  2.801 35.856 3.233 41.496 ;
     RECT  2.801 54.576 3.443 60.84 ;
     RECT  3.197 84.336 3.443 84.36 ;
     RECT  3.197 85.632 3.443 88.584 ;
     RECT  2.801 49.536 3.449 49.56 ;
     RECT  2.704 13.584 3.485 17.16 ;
     RECT  2.704 27.6 3.485 28.584 ;
     RECT  2.704 23.328 3.521 24.408 ;
     RECT  3.443 59.808 3.521 60.84 ;
     RECT  2.704 89.952 3.629 94.632 ;
     RECT  2.704 18.816 3.635 21.96 ;
     RECT  3.485 13.584 3.733 17.112 ;
     RECT  3.635 21.36 3.733 21.96 ;
     RECT  3.521 23.328 3.733 23.352 ;
     RECT  2.704 30.96 3.733 33.144 ;
     RECT  2.909 69.504 3.733 69.576 ;
     RECT  2.909 70.8 3.733 70.968 ;
     RECT  2.704 72.144 3.733 72.168 ;
     RECT  2.704 67.248 3.737 67.272 ;
     RECT  2.704 34.224 3.769 34.248 ;
     RECT  3.733 21.36 3.773 23.352 ;
     RECT  2.704 99.408 3.777 99.432 ;
     RECT  2.704 100.56 3.777 103.752 ;
     RECT  3.629 89.952 3.788 94.344 ;
     RECT  3.089 78.624 3.805 79.176 ;
     RECT  3.125 73.392 3.809 73.944 ;
     RECT  3.443 85.632 3.809 85.656 ;
     RECT  3.733 30.768 3.841 33.144 ;
     RECT  3.769 34.224 3.841 34.344 ;
     RECT  3.805 78.576 3.841 79.176 ;
     RECT  3.841 30.768 3.845 34.344 ;
     RECT  3.845 30.96 3.877 34.344 ;
     RECT  3.877 30.96 3.881 34.44 ;
     RECT  2.704 80.4 3.884 80.424 ;
     RECT  2.704 81.792 3.884 81.816 ;
     RECT  2.704 2.496 3.905 2.52 ;
     RECT  3.841 78.48 3.905 79.176 ;
     RECT  2.704 43.92 3.913 45.576 ;
     RECT  3.733 68.784 3.913 69.576 ;
     RECT  3.905 2.496 3.925 2.856 ;
     RECT  3.485 27.6 3.925 28.44 ;
     RECT  3.884 80.4 3.925 81.816 ;
     RECT  2.704 6.816 3.973 6.888 ;
     RECT  2.873 77.088 4.021 77.16 ;
     RECT  3.905 78.336 4.021 79.176 ;
     RECT  3.521 60.816 4.025 60.84 ;
     RECT  3.913 68.544 4.057 69.576 ;
     RECT  3.089 47.808 4.061 47.832 ;
     RECT  2.704 96.912 4.061 97.128 ;
     RECT  3.881 31.344 4.067 34.44 ;
     RECT  3.777 99.408 4.069 103.752 ;
     RECT  2.801 42.768 4.093 42.792 ;
     RECT  3.913 43.92 4.093 45.624 ;
     RECT  3.925 27.36 4.097 28.44 ;
     RECT  3.973 6.144 4.129 6.888 ;
     RECT  2.704 7.968 4.129 9.048 ;
     RECT  3.925 2.496 4.165 3.288 ;
     RECT  2.704 62.16 4.165 62.184 ;
     RECT  4.069 98.928 4.165 103.752 ;
     RECT  4.057 68.352 4.177 69.576 ;
     RECT  2.704 95.76 4.205 95.784 ;
     RECT  3.443 86.64 4.261 88.584 ;
     RECT  3.788 89.856 4.261 94.344 ;
     RECT  2.704 10.08 4.273 10.248 ;
     RECT  2.765 11.28 4.273 11.784 ;
     RECT  3.635 18.816 4.273 20.376 ;
     RECT  2.704 66.096 4.309 66.12 ;
     RECT  3.925 80.4 4.309 82.68 ;
     RECT  4.165 62.16 4.357 62.712 ;
     RECT  4.273 18.384 4.381 20.376 ;
     RECT  4.021 77.088 4.381 79.176 ;
     RECT  3.233 35.856 4.405 41.4 ;
     RECT  4.061 96.96 4.421 97.128 ;
     RECT  4.057 60.96 4.453 60.984 ;
     RECT  4.129 6.144 4.489 9.048 ;
     RECT  4.273 10.08 4.489 11.784 ;
     RECT  4.067 31.872 4.489 34.44 ;
     RECT  4.405 35.856 4.489 41.496 ;
     RECT  4.381 76.272 4.489 79.176 ;
     RECT  4.165 98.64 4.489 103.752 ;
     RECT  2.909 52.464 4.501 53.4 ;
     RECT  3.443 54.576 4.501 58.824 ;
     RECT  3.521 24.384 4.525 24.408 ;
     RECT  4.489 76.032 4.525 79.176 ;
     RECT  4.309 80.4 4.525 84.12 ;
     RECT  3.733 12.768 4.597 17.112 ;
     RECT  4.381 18.144 4.597 20.376 ;
     RECT  4.093 42.768 4.597 45.624 ;
     RECT  3.769 46.752 4.597 46.776 ;
     RECT  3.733 49.152 4.597 49.176 ;
     RECT  3.733 70.8 4.597 72.168 ;
     RECT  4.309 65.376 4.669 66.12 ;
     RECT  4.177 68.352 4.673 69.48 ;
     RECT  4.489 98.64 4.693 104.328 ;
     RECT  4.597 12.768 4.705 20.376 ;
     RECT  3.773 21.36 4.705 22.872 ;
     RECT  4.357 62.16 4.705 63.576 ;
     RECT  4.525 23.904 4.741 24.408 ;
     RECT  2.704 25.44 4.741 26.184 ;
     RECT  4.669 65.376 4.741 66.888 ;
     RECT  4.673 68.352 4.741 68.952 ;
     RECT  4.525 80.4 4.741 84.984 ;
     RECT  4.741 80.304 4.777 84.984 ;
     RECT  4.261 86.64 4.777 94.344 ;
     RECT  4.525 76.032 4.789 79.272 ;
     RECT  4.789 75.216 4.837 79.272 ;
     RECT  4.777 80.304 4.837 94.344 ;
     RECT  4.705 12.768 4.849 22.872 ;
     RECT  4.741 23.904 4.849 26.184 ;
     RECT  4.693 98.112 4.883 104.328 ;
     RECT  4.705 62.16 4.885 63.816 ;
     RECT  4.741 65.376 4.885 68.952 ;
     RECT  4.597 70.8 4.885 72.216 ;
     RECT  4.837 75.216 4.885 94.344 ;
     RECT  4.849 12.768 4.949 26.184 ;
     RECT  4.097 27.36 4.949 27.72 ;
     RECT  3.521 59.808 4.949 59.832 ;
     RECT  4.705 28.8 4.957 29.208 ;
     RECT  4.885 74.64 4.957 94.344 ;
     RECT  4.489 6.144 4.981 11.784 ;
     RECT  4.501 52.464 4.981 58.824 ;
     RECT  4.949 59.808 4.981 59.976 ;
     RECT  4.957 28.8 5.029 29.64 ;
     RECT  4.489 31.872 5.029 41.496 ;
     RECT  4.597 42.768 5.029 46.776 ;
     RECT  5.029 31.872 5.065 46.776 ;
     RECT  5.065 31.872 5.077 47.448 ;
     RECT  4.885 70.656 5.077 72.216 ;
     RECT  3.809 73.392 5.077 73.416 ;
     RECT  4.957 74.64 5.077 94.824 ;
     RECT  4.981 52.464 5.101 59.976 ;
     RECT  4.453 60.96 5.101 61.032 ;
     RECT  4.885 62.16 5.101 68.952 ;
     RECT  4.949 12.768 5.137 27.72 ;
     RECT  5.029 28.8 5.137 30.024 ;
     RECT  4.597 48.768 5.137 49.176 ;
     RECT  4.381 50.16 5.137 50.184 ;
     RECT  4.885 105.696 5.171 105.72 ;
     RECT  5.077 31.44 5.173 47.448 ;
     RECT  5.137 48.768 5.173 50.424 ;
     RECT  4.165 2.208 5.177 3.288 ;
     RECT  5.077 70.656 5.317 94.824 ;
     RECT  5.137 95.904 5.317 95.928 ;
     RECT  4.421 97.008 5.324 97.128 ;
     RECT  4.883 98.112 5.324 103.752 ;
     RECT  5.317 70.656 5.353 95.928 ;
     RECT  4.813 4.464 5.365 4.488 ;
     RECT  4.981 5.472 5.365 11.784 ;
     RECT  5.173 31.104 5.461 47.448 ;
     RECT  5.173 48.672 5.461 50.424 ;
     RECT  5.461 31.104 5.533 50.424 ;
     RECT  5.533 31.104 5.569 50.904 ;
     RECT  5.101 51.888 5.569 59.976 ;
     RECT  5.569 31.104 5.641 59.976 ;
     RECT  5.101 60.96 5.641 68.952 ;
     RECT  5.137 12.768 5.701 30.024 ;
     RECT  5.641 31.104 5.701 68.952 ;
     RECT  5.365 4.464 5.749 11.784 ;
     RECT  5.701 12.768 5.749 68.952 ;
     RECT  5.749 4.464 5.989 68.952 ;
     RECT  5.353 70.128 5.989 95.928 ;
     RECT  5.989 4.464 6.073 95.928 ;
     RECT  6.073 4.464 6.181 95.976 ;
     RECT  5.324 97.008 6.181 103.752 ;
     RECT  5.177 2.256 6.325 3.144 ;
     RECT  6.181 4.464 6.325 103.752 ;
     RECT  6.325 2.256 6.649 103.752 ;
     RECT  6.649 2.064 7.693 103.752 ;
     RECT  7.693 2.064 7.901 103.8 ;
     RECT  7.901 2.064 7.985 103.848 ;
     RECT  7.985 2.064 8.104 103.8 ;
     RECT  8.104 102.432 8.345 103.8 ;
     RECT  8.345 102.432 9.281 103.752 ;
     RECT  9.281 103.2 9.353 103.752 ;
     RECT  8.104 2.064 9.961 101.16 ;
     RECT  9.961 2.064 10.213 101.832 ;
     RECT  9.353 103.2 10.691 103.32 ;
     RECT  10.213 2.016 10.861 101.832 ;
     RECT  10.691 103.2 11.797 103.224 ;
     RECT  12.517 104.832 12.755 104.856 ;
     RECT  10.861 2.016 13.129 101.976 ;
     RECT  11.797 103.2 13.129 103.752 ;
     RECT  13.129 2.016 13.165 103.752 ;
     RECT  13.093 105.696 13.187 105.72 ;
     RECT  13.165 2.016 13.427 103.8 ;
     RECT  13.427 2.016 13.673 103.752 ;
     RECT  13.673 2.016 14.051 103.272 ;
     RECT  14.051 2.064 14.573 103.272 ;
     RECT  14.573 103.2 14.725 103.272 ;
     RECT  14.573 2.064 15.685 102.072 ;
     RECT  14.725 103.2 15.685 103.368 ;
     RECT  15.685 2.064 15.793 103.368 ;
     RECT  15.793 2.064 15.833 103.752 ;
     RECT  15.833 97.824 15.869 103.752 ;
     RECT  15.869 98.544 15.923 103.752 ;
     RECT  15.923 98.544 16.517 103.272 ;
     RECT  16.517 98.544 16.873 100.584 ;
     RECT  16.873 98.208 17.017 100.584 ;
     RECT  15.833 2.064 17.737 96.84 ;
     RECT  17.017 97.92 17.737 100.584 ;
     RECT  16.517 101.76 17.845 103.272 ;
     RECT  17.845 101.76 18.524 103.752 ;
     RECT  17.737 2.064 18.608 100.584 ;
     RECT  18.524 101.76 18.608 103.848 ;
     RECT  18.608 2.064 18.611 103.848 ;
     RECT  18.611 2.064 19.001 103.8 ;
     RECT  18.097 104.88 19.091 104.904 ;
     RECT  19.001 2.064 19.331 103.224 ;
     RECT  19.331 2.064 19.427 75.24 ;
     RECT  19.331 76.224 19.649 103.224 ;
     RECT  19.427 2.064 19.657 74.664 ;
     RECT  19.649 76.224 19.721 90.6 ;
     RECT  19.657 2.064 19.907 14.52 ;
     RECT  19.657 15.504 19.937 74.664 ;
     RECT  19.907 5.28 19.973 14.52 ;
     RECT  19.649 91.872 19.973 103.224 ;
     RECT  19.907 2.064 20.003 4.008 ;
     RECT  19.937 15.504 20.009 69.144 ;
     RECT  19.973 91.872 20.009 100.392 ;
     RECT  19.973 7.68 20.081 14.52 ;
     RECT  19.721 76.224 20.099 90.12 ;
     RECT  20.009 15.84 20.117 69.144 ;
     RECT  19.937 70.128 20.117 74.664 ;
     RECT  20.009 91.872 20.117 100.296 ;
     RECT  19.973 5.28 20.153 6.264 ;
     RECT  20.081 10.128 20.189 14.52 ;
     RECT  19.973 101.376 20.197 103.224 ;
     RECT  20.003 3.984 20.261 4.008 ;
     RECT  20.153 5.472 20.261 6.264 ;
     RECT  20.117 91.872 20.291 97.128 ;
     RECT  20.261 6.24 20.297 6.264 ;
     RECT  20.099 76.224 20.333 79.224 ;
     RECT  20.081 7.68 20.339 9.144 ;
     RECT  20.003 2.064 20.369 2.856 ;
     RECT  20.189 10.128 20.405 14.472 ;
     RECT  20.117 15.84 20.405 69 ;
     RECT  20.099 80.256 20.441 90.12 ;
     RECT  20.333 76.656 20.483 76.824 ;
     RECT  20.339 7.68 20.579 9.048 ;
     RECT  20.117 70.128 20.579 74.568 ;
     RECT  20.369 2.832 20.585 2.856 ;
     RECT  20.405 60.912 20.585 69 ;
     RECT  20.483 76.8 20.585 76.824 ;
     RECT  20.441 80.352 20.585 90.12 ;
     RECT  20.333 77.904 20.723 79.224 ;
     RECT  20.117 98.592 20.729 100.296 ;
     RECT  20.585 80.352 20.765 87.912 ;
     RECT  20.579 7.68 20.819 8.808 ;
     RECT  20.291 92.256 20.819 97.128 ;
     RECT  20.197 101.376 20.837 103.272 ;
     RECT  20.765 80.352 20.909 84.168 ;
     RECT  20.585 60.912 20.915 68.952 ;
     RECT  20.909 80.352 20.915 81.24 ;
     RECT  20.819 92.256 20.915 95.016 ;
     RECT  20.585 88.896 20.941 90.12 ;
     RECT  20.837 101.664 20.945 103.272 ;
     RECT  20.405 15.84 20.963 59.88 ;
     RECT  20.915 61.056 20.981 68.952 ;
     RECT  20.963 15.84 21.011 54.744 ;
     RECT  20.819 7.68 21.013 8.472 ;
     RECT  20.945 102.144 21.02 103.272 ;
     RECT  20.981 61.056 21.062 65.544 ;
     RECT  21.013 6.816 21.089 8.472 ;
     RECT  20.981 66.96 21.089 68.952 ;
     RECT  20.915 94.992 21.089 95.016 ;
     RECT  21.062 61.056 21.107 65.496 ;
     RECT  21.02 102.144 21.107 103.56 ;
     RECT  21.089 6.816 21.125 7.416 ;
     RECT  20.915 92.256 21.125 93.816 ;
     RECT  20.729 98.592 21.155 100.248 ;
     RECT  21.125 92.256 21.161 93.048 ;
     RECT  21.155 98.592 21.161 99.48 ;
     RECT  20.819 96.768 21.193 97.128 ;
     RECT  21.161 98.592 21.193 99.24 ;
     RECT  20.941 88.896 21.233 90.6 ;
     RECT  20.405 12.192 21.251 14.472 ;
     RECT  20.723 78 21.251 79.224 ;
     RECT  21.251 78.48 21.299 79.224 ;
     RECT  21.161 92.4 21.299 93.048 ;
     RECT  21.251 14.16 21.305 14.472 ;
     RECT  20.909 82.272 21.341 84.168 ;
     RECT  21.299 78.576 21.347 79.224 ;
     RECT  21.305 14.448 21.443 14.472 ;
     RECT  20.405 10.128 21.445 11.208 ;
     RECT  21.251 12.192 21.445 12.984 ;
     RECT  21.089 8.448 21.449 8.472 ;
     RECT  21.011 16.656 21.485 54.744 ;
     RECT  20.579 70.128 21.553 70.968 ;
     RECT  21.233 88.896 21.557 90.12 ;
     RECT  20.963 55.824 21.635 59.88 ;
     RECT  21.553 69.456 21.661 70.968 ;
     RECT  20.579 71.952 21.661 74.568 ;
     RECT  21.485 16.656 21.683 48.648 ;
     RECT  21.557 89.424 21.683 90.12 ;
     RECT  20.915 81.216 21.701 81.24 ;
     RECT  21.485 50.4 21.731 54.744 ;
     RECT  21.683 23.808 21.737 48.648 ;
     RECT  21.635 56.688 21.737 59.88 ;
     RECT  21.107 61.488 21.737 65.496 ;
     RECT  21.737 29.184 21.773 48.648 ;
     RECT  21.737 23.808 21.809 28.2 ;
     RECT  21.553 75.744 21.841 75.768 ;
     RECT  21.731 50.4 21.881 52.008 ;
     RECT  21.089 66.96 21.881 68.424 ;
     RECT  21.347 78.576 21.881 78.648 ;
     RECT  21.107 102.144 21.881 102.648 ;
     RECT  21.445 10.128 21.949 12.984 ;
     RECT  21.881 78.576 21.953 78.6 ;
     RECT  21.125 7.392 21.989 7.416 ;
     RECT  21.661 69.456 21.989 74.568 ;
     RECT  21.773 30.816 22.025 48.504 ;
     RECT  21.737 56.976 22.061 59.88 ;
     RECT  22.061 58.608 22.097 59.88 ;
     RECT  21.737 61.488 22.133 65.448 ;
     RECT  21.841 75.744 22.133 75.96 ;
     RECT  21.341 82.56 22.165 84.168 ;
     RECT  20.765 85.488 22.165 87.912 ;
     RECT  21.985 14.832 22.169 14.856 ;
     RECT  22.133 61.488 22.169 63.24 ;
     RECT  22.025 30.816 22.205 46.2 ;
     RECT  22.133 75.84 22.205 75.96 ;
     RECT  22.165 82.56 22.211 87.912 ;
     RECT  21.949 10.032 22.241 12.984 ;
     RECT  21.193 96.768 22.259 99.24 ;
     RECT  21.773 29.184 22.277 29.784 ;
     RECT  21.683 16.656 22.307 22.728 ;
     RECT  22.133 64.368 22.307 65.448 ;
     RECT  22.211 82.56 22.309 86.664 ;
     RECT  22.307 16.944 22.313 22.728 ;
     RECT  22.205 30.816 22.349 46.152 ;
     RECT  21.989 71.328 22.349 74.568 ;
     RECT  21.881 67.632 22.355 68.424 ;
     RECT  22.241 10.032 22.385 12.504 ;
     RECT  22.313 17.904 22.385 22.728 ;
     RECT  22.061 56.976 22.403 57.432 ;
     RECT  22.211 87.888 22.403 87.912 ;
     RECT  22.385 19.92 22.421 22.728 ;
     RECT  21.881 50.688 22.421 52.008 ;
     RECT  22.307 64.368 22.421 65.4 ;
     RECT  22.349 72.528 22.451 74.568 ;
     RECT  22.097 58.752 22.489 59.88 ;
     RECT  21.683 89.424 22.493 89.448 ;
     RECT  22.129 93.84 22.493 93.864 ;
     RECT  22.169 61.488 22.499 61.56 ;
     RECT  21.989 69.456 22.499 70.152 ;
     RECT  22.385 10.944 22.529 10.968 ;
     RECT  22.309 81.888 22.529 86.664 ;
     RECT  21.881 102.624 22.549 102.648 ;
     RECT  22.049 103.728 22.549 103.752 ;
     RECT  21.731 53.04 22.601 54.744 ;
     RECT  22.451 72.528 22.601 73.368 ;
     RECT  22.403 56.976 22.637 57 ;
     RECT  22.421 64.368 22.637 65.112 ;
     RECT  22.355 68.304 22.637 68.424 ;
     RECT  21.809 23.808 22.643 23.832 ;
     RECT  22.421 20.4 22.669 22.728 ;
     RECT  22.489 58.752 22.673 59.976 ;
     RECT  22.529 81.888 22.673 83.4 ;
     RECT  21.809 24.816 22.813 28.2 ;
     RECT  22.277 29.184 22.813 29.544 ;
     RECT  22.601 53.04 22.813 54.6 ;
     RECT  22.169 62.736 22.817 63.24 ;
     RECT  21.299 92.4 22.817 92.424 ;
     RECT  22.549 102.624 22.817 103.752 ;
     RECT  22.385 17.904 22.835 18.6 ;
     RECT  22.421 50.688 22.853 51.912 ;
     RECT  22.813 52.896 22.853 54.6 ;
     RECT  22.673 83.232 22.853 83.4 ;
     RECT  22.529 84.528 22.853 86.664 ;
     RECT  22.817 102.624 22.853 102.648 ;
     RECT  22.673 58.8 22.889 59.976 ;
     RECT  22.853 85.536 22.889 86.664 ;
     RECT  22.813 6.864 22.925 6.888 ;
     RECT  22.813 14.688 22.925 14.712 ;
     RECT  22.849 66.528 22.961 66.648 ;
     RECT  22.853 51.888 22.997 51.912 ;
     RECT  22.637 64.368 23.069 64.392 ;
     RECT  22.817 103.728 23.075 103.752 ;
     RECT  22.961 66.528 23.105 66.552 ;
     RECT  22.259 97.152 23.171 99.24 ;
     RECT  22.349 30.816 23.173 45.624 ;
     RECT  22.025 47.232 23.281 48.504 ;
     RECT  23.173 30.72 23.285 45.624 ;
     RECT  22.853 50.688 23.285 50.712 ;
     RECT  22.889 59.952 23.285 59.976 ;
     RECT  22.813 24.816 23.317 29.544 ;
     RECT  23.285 30.72 23.317 35.736 ;
     RECT  23.285 36.768 23.317 45.624 ;
     RECT  23.281 46.608 23.317 48.504 ;
     RECT  22.385 12.192 23.353 12.504 ;
     RECT  22.669 20.4 23.353 22.776 ;
     RECT  23.317 24.816 23.353 35.736 ;
     RECT  23.317 36.768 23.353 48.504 ;
     RECT  23.353 20.4 23.357 22.968 ;
     RECT  23.353 36.768 23.357 49.128 ;
     RECT  22.889 58.8 23.357 58.92 ;
     RECT  23.353 95.808 23.389 95.832 ;
     RECT  23.357 21.216 23.411 22.968 ;
     RECT  23.317 9.936 23.425 9.96 ;
     RECT  23.353 12.192 23.425 13.512 ;
     RECT  22.637 68.304 23.465 68.376 ;
     RECT  22.601 72.672 23.501 73.368 ;
     RECT  23.501 73.344 23.537 73.368 ;
     RECT  23.357 36.768 23.555 40.296 ;
     RECT  23.555 36.768 23.603 36.792 ;
     RECT  23.101 5.232 23.605 5.256 ;
     RECT  23.353 100.752 23.605 101.256 ;
     RECT  23.605 4.848 23.641 5.256 ;
     RECT  22.889 85.824 23.681 86.664 ;
     RECT  23.281 63.408 23.857 64.008 ;
     RECT  22.499 69.456 23.857 70.056 ;
     RECT  22.349 71.328 23.857 71.352 ;
     RECT  22.205 75.84 23.857 75.864 ;
     RECT  23.353 7.296 23.893 7.32 ;
     RECT  23.425 9.936 23.893 10.728 ;
     RECT  23.425 12 23.893 13.512 ;
     RECT  22.835 18.048 23.893 18.6 ;
     RECT  23.357 41.376 23.893 49.128 ;
     RECT  23.357 58.896 23.893 58.92 ;
     RECT  23.857 62.88 23.893 64.008 ;
     RECT  23.465 68.304 23.893 68.328 ;
     RECT  22.813 74.736 23.893 74.76 ;
     RECT  23.857 75.84 23.893 76.44 ;
     RECT  22.741 78.096 23.893 78.12 ;
     RECT  22.673 81.888 23.893 81.912 ;
     RECT  23.353 88.272 23.893 88.296 ;
     RECT  23.353 90.528 23.893 91.512 ;
     RECT  23.353 93.936 23.893 93.96 ;
     RECT  23.389 95.088 23.893 95.832 ;
     RECT  23.171 97.872 23.893 99.24 ;
     RECT  23.605 100.32 23.893 101.256 ;
     RECT  23.641 4.464 23.929 5.256 ;
     RECT  23.893 7.296 23.929 8.088 ;
     RECT  23.893 9.936 23.929 13.512 ;
     RECT  23.893 17.28 23.929 18.6 ;
     RECT  23.411 22.944 23.929 22.968 ;
     RECT  23.353 24.048 23.929 35.736 ;
     RECT  22.853 52.896 23.929 54.024 ;
     RECT  23.893 65.856 23.929 65.88 ;
     RECT  22.853 83.376 23.929 83.4 ;
     RECT  22.853 84.528 23.929 84.552 ;
     RECT  23.893 90.528 23.929 91.896 ;
     RECT  23.893 97.872 23.939 101.256 ;
     RECT  23.939 100.512 24.325 101.256 ;
     RECT  23.929 6.528 24.361 8.088 ;
     RECT  23.929 9.168 24.361 13.512 ;
     RECT  22.499 61.536 24.361 61.56 ;
     RECT  23.893 88.08 24.397 88.296 ;
     RECT  23.929 4.08 24.433 5.256 ;
     RECT  23.893 14.64 24.433 15.768 ;
     RECT  23.929 17.28 24.433 18.984 ;
     RECT  23.893 57.024 24.433 57.24 ;
     RECT  23.893 79.44 24.433 81.912 ;
     RECT  23.929 83.184 24.433 84.552 ;
     RECT  23.929 102.768 24.433 102.792 ;
     RECT  24.361 6.528 24.469 13.512 ;
     RECT  24.433 14.64 24.469 19.368 ;
     RECT  23.411 21.216 24.469 21.816 ;
     RECT  23.929 22.944 24.469 35.736 ;
     RECT  23.555 38.016 24.469 40.296 ;
     RECT  23.893 41.376 24.469 49.704 ;
     RECT  23.893 51.552 24.469 51.576 ;
     RECT  23.929 52.704 24.469 54.024 ;
     RECT  24.433 56.64 24.469 57.24 ;
     RECT  24.361 61.344 24.469 61.56 ;
     RECT  23.893 67.776 24.469 68.328 ;
     RECT  23.857 69.456 24.469 71.352 ;
     RECT  24.397 87.888 24.469 88.296 ;
     RECT  23.929 89.616 24.469 91.896 ;
     RECT  24.325 100.512 24.469 101.544 ;
     RECT  24.433 102.768 24.469 103.032 ;
     RECT  24.433 3.696 24.505 5.256 ;
     RECT  24.469 6.336 24.505 13.512 ;
     RECT  24.469 14.64 24.505 20.136 ;
     RECT  24.469 21.216 24.505 35.736 ;
     RECT  24.469 38.016 24.505 49.704 ;
     RECT  24.469 56.448 24.505 57.24 ;
     RECT  23.929 65.664 24.505 65.88 ;
     RECT  24.469 67.2 24.505 68.328 ;
     RECT  24.469 69.456 24.505 72.504 ;
     RECT  24.505 3.168 24.577 13.512 ;
     RECT  24.469 61.344 24.973 61.752 ;
     RECT  24.505 14.64 25.009 35.736 ;
     RECT  24.505 38.016 25.009 50.472 ;
     RECT  24.469 51.552 25.009 54.984 ;
     RECT  23.893 58.896 25.009 59.688 ;
     RECT  24.973 61.152 25.009 61.752 ;
     RECT  23.893 62.784 25.009 64.008 ;
     RECT  24.505 65.136 25.009 65.88 ;
     RECT  24.505 67.2 25.009 72.504 ;
     RECT  23.893 73.968 25.009 78.12 ;
     RECT  24.433 79.44 25.009 84.552 ;
     RECT  23.681 85.824 25.009 86.616 ;
     RECT  24.469 87.888 25.009 91.896 ;
     RECT  23.893 93.168 25.009 96.408 ;
     RECT  23.939 97.872 25.009 99.528 ;
     RECT  24.577 2.976 25.045 13.512 ;
     RECT  25.009 14.64 25.045 36.504 ;
     RECT  25.009 37.824 25.045 54.984 ;
     RECT  24.505 56.256 25.045 57.24 ;
     RECT  25.009 58.32 25.045 61.752 ;
     RECT  25.009 62.784 25.045 72.504 ;
     RECT  25.009 73.968 25.045 84.552 ;
     RECT  25.009 85.824 25.045 96.408 ;
     RECT  25.009 97.728 25.045 99.528 ;
     RECT  24.469 100.512 25.045 103.032 ;
     RECT  25.045 2.592 25.836 2.616 ;
     RECT  25.045 2.616 25.884 2.784 ;
     RECT  25.045 2.784 25.836 2.808 ;
     RECT  25.045 2.808 25.884 2.976 ;
     RECT  25.045 2.976 25.836 3 ;
     RECT  25.045 3 25.884 3.168 ;
     RECT  25.045 3.168 25.836 3.192 ;
     RECT  25.045 3.192 25.884 3.36 ;
     RECT  25.045 3.36 25.836 3.384 ;
     RECT  25.045 3.384 25.884 3.504 ;
     RECT  25.045 3.504 25.836 3.528 ;
     RECT  25.045 3.528 25.884 3.696 ;
     RECT  25.045 3.696 25.836 3.72 ;
     RECT  25.045 3.72 25.884 3.888 ;
     RECT  25.045 3.888 25.836 3.912 ;
     RECT  25.045 3.912 25.884 4.08 ;
     RECT  25.045 4.08 25.836 4.104 ;
     RECT  25.045 4.104 25.884 4.272 ;
     RECT  25.045 4.272 25.836 4.296 ;
     RECT  25.045 4.296 25.884 4.464 ;
     RECT  25.045 4.464 25.836 4.488 ;
     RECT  25.045 4.488 25.884 4.656 ;
     RECT  25.045 4.656 25.836 4.68 ;
     RECT  25.045 4.68 25.884 4.848 ;
     RECT  25.045 4.848 25.836 4.872 ;
     RECT  25.045 4.872 25.884 5.04 ;
     RECT  25.045 5.04 25.836 5.064 ;
     RECT  25.045 5.064 25.884 5.232 ;
     RECT  25.045 5.232 25.836 5.256 ;
     RECT  25.045 5.256 25.884 5.424 ;
     RECT  25.045 5.424 25.836 5.448 ;
     RECT  25.045 5.448 25.884 5.616 ;
     RECT  25.045 5.616 25.836 5.64 ;
     RECT  25.045 5.64 25.884 5.808 ;
     RECT  25.045 5.808 25.836 5.832 ;
     RECT  25.045 5.832 25.884 5.952 ;
     RECT  25.045 5.952 25.836 5.976 ;
     RECT  25.045 5.976 25.884 6.144 ;
     RECT  25.045 6.144 25.836 6.168 ;
     RECT  25.045 6.168 25.884 6.336 ;
     RECT  25.045 6.336 25.836 6.36 ;
     RECT  25.045 6.36 25.884 6.528 ;
     RECT  25.045 6.528 25.836 6.552 ;
     RECT  25.045 6.552 25.884 6.72 ;
     RECT  25.045 6.72 25.836 6.744 ;
     RECT  25.045 6.744 25.884 6.912 ;
     RECT  25.045 6.912 25.836 6.936 ;
     RECT  25.045 6.936 25.884 7.104 ;
     RECT  25.045 7.104 25.836 7.128 ;
     RECT  25.045 7.128 25.884 7.296 ;
     RECT  25.045 7.296 25.836 7.32 ;
     RECT  25.045 7.32 25.884 7.488 ;
     RECT  25.045 7.488 25.836 7.512 ;
     RECT  25.045 7.512 25.884 7.68 ;
     RECT  25.045 7.68 25.836 7.704 ;
     RECT  25.045 7.704 25.884 7.872 ;
     RECT  25.045 7.872 25.836 7.896 ;
     RECT  25.045 7.896 25.884 8.064 ;
     RECT  25.045 8.064 25.836 8.088 ;
     RECT  25.045 8.088 25.884 8.256 ;
     RECT  25.045 8.256 25.836 8.28 ;
     RECT  25.045 8.28 25.884 8.4 ;
     RECT  25.045 8.4 25.836 8.424 ;
     RECT  25.045 8.424 25.884 8.592 ;
     RECT  25.045 8.592 25.836 8.616 ;
     RECT  25.045 8.616 25.884 8.784 ;
     RECT  25.045 8.784 25.836 8.808 ;
     RECT  25.045 8.808 25.884 8.976 ;
     RECT  25.045 8.976 25.836 9 ;
     RECT  25.045 9 25.884 9.168 ;
     RECT  25.045 9.168 25.836 9.192 ;
     RECT  25.045 9.192 25.884 9.36 ;
     RECT  25.045 9.36 25.836 9.384 ;
     RECT  25.045 9.384 25.884 9.552 ;
     RECT  25.045 9.552 25.836 9.576 ;
     RECT  25.045 9.576 25.884 9.744 ;
     RECT  25.045 9.744 25.836 9.768 ;
     RECT  25.045 9.768 25.884 9.936 ;
     RECT  25.045 9.936 25.836 9.96 ;
     RECT  25.045 9.96 25.884 10.128 ;
     RECT  25.045 10.128 25.836 10.152 ;
     RECT  25.045 10.152 25.884 10.32 ;
     RECT  25.045 10.32 25.836 10.344 ;
     RECT  25.045 10.344 25.884 10.512 ;
     RECT  25.045 10.512 25.836 10.536 ;
     RECT  25.045 10.536 25.884 10.704 ;
     RECT  25.045 10.704 25.836 10.728 ;
     RECT  25.045 10.728 25.884 10.848 ;
     RECT  25.045 10.848 25.836 10.872 ;
     RECT  25.045 10.872 25.884 11.04 ;
     RECT  25.045 11.04 25.836 11.064 ;
     RECT  25.045 11.064 25.884 11.232 ;
     RECT  25.045 11.232 25.836 11.256 ;
     RECT  25.045 11.256 25.884 11.424 ;
     RECT  25.045 11.424 25.836 11.448 ;
     RECT  25.045 11.448 25.884 11.616 ;
     RECT  25.045 11.616 25.836 11.64 ;
     RECT  25.045 11.64 25.884 11.808 ;
     RECT  25.045 11.808 25.836 11.832 ;
     RECT  25.045 11.832 25.884 12 ;
     RECT  25.045 12 25.836 12.024 ;
     RECT  25.045 12.024 25.884 12.192 ;
     RECT  25.045 12.192 25.836 12.216 ;
     RECT  25.045 12.216 25.884 12.384 ;
     RECT  25.045 12.384 25.836 12.408 ;
     RECT  25.045 12.408 25.884 12.576 ;
     RECT  25.045 12.576 25.836 12.6 ;
     RECT  25.045 12.6 25.884 12.768 ;
     RECT  25.045 12.768 25.836 12.792 ;
     RECT  25.045 12.792 25.884 12.96 ;
     RECT  25.045 12.96 25.836 12.984 ;
     RECT  25.045 12.984 25.884 13.152 ;
     RECT  25.045 13.152 25.836 13.176 ;
     RECT  25.045 13.176 25.884 13.296 ;
     RECT  25.045 13.296 25.836 13.32 ;
     RECT  25.045 13.32 25.884 13.488 ;
     RECT  25.045 13.488 25.836 13.512 ;
     RECT  25.045 13.512 25.884 13.68 ;
     RECT  25.045 13.68 25.836 13.704 ;
     RECT  25.045 13.704 25.884 13.872 ;
     RECT  25.045 13.872 25.836 13.896 ;
     RECT  25.045 13.896 25.884 14.064 ;
     RECT  25.045 14.064 25.836 14.088 ;
     RECT  25.045 14.088 25.884 14.256 ;
     RECT  25.045 14.256 25.836 14.28 ;
     RECT  25.045 14.28 25.884 14.448 ;
     RECT  25.045 14.448 25.836 14.472 ;
     RECT  25.045 14.472 25.884 14.64 ;
     RECT  25.045 14.64 25.836 14.664 ;
     RECT  25.045 14.664 25.884 14.832 ;
     RECT  25.045 14.832 25.836 14.856 ;
     RECT  25.045 14.856 25.884 15.024 ;
     RECT  25.045 15.024 25.836 15.048 ;
     RECT  25.045 15.048 25.884 15.216 ;
     RECT  25.045 15.216 25.836 15.24 ;
     RECT  25.045 15.24 25.884 15.408 ;
     RECT  25.045 15.408 25.836 15.432 ;
     RECT  25.045 15.432 25.884 15.6 ;
     RECT  25.045 15.6 25.836 15.624 ;
     RECT  25.045 15.624 25.884 15.744 ;
     RECT  25.045 15.744 25.836 15.768 ;
     RECT  25.045 15.768 25.884 15.936 ;
     RECT  25.045 15.936 25.836 15.96 ;
     RECT  25.045 15.96 25.884 16.128 ;
     RECT  25.045 16.128 25.836 16.152 ;
     RECT  25.045 16.152 25.884 16.32 ;
     RECT  25.045 16.32 25.836 16.344 ;
     RECT  25.045 16.344 25.884 16.512 ;
     RECT  25.045 16.512 25.836 16.536 ;
     RECT  25.045 16.536 25.884 16.704 ;
     RECT  25.045 16.704 25.836 16.728 ;
     RECT  25.045 16.728 25.884 16.896 ;
     RECT  25.045 16.896 25.836 16.92 ;
     RECT  25.045 16.92 25.884 17.088 ;
     RECT  25.045 17.088 25.836 17.112 ;
     RECT  25.045 17.112 25.884 17.28 ;
     RECT  25.045 17.28 25.836 17.304 ;
     RECT  25.045 17.304 25.884 17.472 ;
     RECT  25.045 17.472 25.836 17.496 ;
     RECT  25.045 17.496 25.884 17.664 ;
     RECT  25.045 17.664 25.836 17.688 ;
     RECT  25.045 17.688 25.884 17.856 ;
     RECT  25.045 17.856 25.836 17.88 ;
     RECT  25.045 17.88 25.884 18.048 ;
     RECT  25.045 18.048 25.836 18.072 ;
     RECT  25.045 18.072 25.884 18.24 ;
     RECT  25.045 18.24 25.836 18.264 ;
     RECT  25.045 18.264 25.884 18.384 ;
     RECT  25.045 18.384 25.836 18.408 ;
     RECT  25.045 18.408 25.884 18.576 ;
     RECT  25.045 18.576 25.836 18.6 ;
     RECT  25.045 18.6 25.884 18.768 ;
     RECT  25.045 18.768 25.836 18.792 ;
     RECT  25.045 18.792 25.884 18.96 ;
     RECT  25.045 18.96 25.836 18.984 ;
     RECT  25.045 18.984 25.884 19.152 ;
     RECT  25.045 19.152 25.836 19.176 ;
     RECT  25.045 19.176 25.884 19.344 ;
     RECT  25.045 19.344 25.836 19.368 ;
     RECT  25.045 19.368 25.884 19.536 ;
     RECT  25.045 19.536 25.836 19.56 ;
     RECT  25.045 19.56 25.884 19.728 ;
     RECT  25.045 19.728 25.836 19.752 ;
     RECT  25.045 19.752 25.884 19.92 ;
     RECT  25.045 19.92 25.836 19.944 ;
     RECT  25.045 19.944 25.884 20.112 ;
     RECT  25.045 20.112 25.836 20.136 ;
     RECT  25.045 20.136 25.884 20.304 ;
     RECT  25.045 20.304 25.836 20.328 ;
     RECT  25.045 20.328 25.884 20.496 ;
     RECT  25.045 20.496 25.836 20.52 ;
     RECT  25.045 20.52 25.884 20.688 ;
     RECT  25.045 20.688 25.836 20.712 ;
     RECT  25.045 20.712 25.884 20.832 ;
     RECT  25.045 20.832 25.836 20.856 ;
     RECT  25.045 20.856 25.884 21.024 ;
     RECT  25.045 21.024 25.836 21.048 ;
     RECT  25.045 21.048 25.884 21.216 ;
     RECT  25.045 21.216 25.836 21.24 ;
     RECT  25.045 21.24 25.884 21.408 ;
     RECT  25.045 21.408 25.836 21.432 ;
     RECT  25.045 21.432 25.884 21.6 ;
     RECT  25.045 21.6 25.836 21.624 ;
     RECT  25.045 21.624 25.884 21.792 ;
     RECT  25.045 21.792 25.836 21.816 ;
     RECT  25.045 21.816 25.884 21.984 ;
     RECT  25.045 21.984 25.836 22.008 ;
     RECT  25.045 22.008 25.884 22.176 ;
     RECT  25.045 22.176 25.836 22.2 ;
     RECT  25.045 22.2 25.884 22.368 ;
     RECT  25.045 22.368 25.836 22.392 ;
     RECT  25.045 22.392 25.884 22.56 ;
     RECT  25.045 22.56 25.836 22.584 ;
     RECT  25.045 22.584 25.884 22.752 ;
     RECT  25.045 22.752 25.836 22.776 ;
     RECT  25.045 22.776 25.884 22.944 ;
     RECT  25.045 22.944 25.836 22.968 ;
     RECT  25.045 22.968 25.884 23.136 ;
     RECT  25.045 23.136 25.836 23.16 ;
     RECT  25.045 23.16 25.884 23.28 ;
     RECT  25.045 23.28 25.836 23.304 ;
     RECT  25.045 23.304 25.884 23.472 ;
     RECT  25.045 23.472 25.836 23.496 ;
     RECT  25.045 23.496 25.884 23.664 ;
     RECT  25.045 23.664 25.836 23.688 ;
     RECT  25.045 23.688 25.884 23.856 ;
     RECT  25.045 23.856 25.836 23.88 ;
     RECT  25.045 23.88 25.884 24.048 ;
     RECT  25.045 24.048 25.836 24.072 ;
     RECT  25.045 24.072 25.884 24.24 ;
     RECT  25.045 24.24 25.836 24.264 ;
     RECT  25.045 24.264 25.884 24.432 ;
     RECT  25.045 24.432 25.836 24.456 ;
     RECT  25.045 24.456 25.884 24.624 ;
     RECT  25.045 24.624 25.836 24.648 ;
     RECT  25.045 24.648 25.884 24.816 ;
     RECT  25.045 24.816 25.836 24.84 ;
     RECT  25.045 24.84 25.884 25.008 ;
     RECT  25.045 25.008 25.836 25.032 ;
     RECT  25.045 25.032 25.884 25.2 ;
     RECT  25.045 25.2 25.836 25.224 ;
     RECT  25.045 25.224 25.884 25.392 ;
     RECT  25.045 25.392 25.836 25.416 ;
     RECT  25.045 25.416 25.884 25.584 ;
     RECT  25.045 25.584 25.836 25.608 ;
     RECT  25.045 25.608 25.884 25.728 ;
     RECT  25.045 25.728 25.836 25.752 ;
     RECT  25.045 25.752 25.884 25.92 ;
     RECT  25.045 25.92 25.836 25.944 ;
     RECT  25.045 25.944 25.884 26.112 ;
     RECT  25.045 26.112 25.836 26.136 ;
     RECT  25.045 26.136 25.884 26.304 ;
     RECT  25.045 26.304 25.836 26.328 ;
     RECT  25.045 26.328 25.884 26.496 ;
     RECT  25.045 26.496 25.836 26.52 ;
     RECT  25.045 26.52 25.884 26.688 ;
     RECT  25.045 26.688 25.836 26.712 ;
     RECT  25.045 26.712 25.884 26.88 ;
     RECT  25.045 26.88 25.836 26.904 ;
     RECT  25.045 26.904 25.884 27.072 ;
     RECT  25.045 27.072 25.836 27.096 ;
     RECT  25.045 27.096 25.884 27.264 ;
     RECT  25.045 27.264 25.836 27.288 ;
     RECT  25.045 27.288 25.884 27.456 ;
     RECT  25.045 27.456 25.836 27.48 ;
     RECT  25.045 27.48 25.884 27.648 ;
     RECT  25.045 27.648 25.836 27.672 ;
     RECT  25.045 27.672 25.884 27.84 ;
     RECT  25.045 27.84 25.836 27.864 ;
     RECT  25.045 27.864 25.884 28.032 ;
     RECT  25.045 28.032 25.836 28.056 ;
     RECT  25.045 28.056 25.884 28.176 ;
     RECT  25.045 28.176 25.836 28.2 ;
     RECT  25.045 28.2 25.884 28.368 ;
     RECT  25.045 28.368 25.836 28.392 ;
     RECT  25.045 28.392 25.884 28.56 ;
     RECT  25.045 28.56 25.836 28.584 ;
     RECT  25.045 28.584 25.884 28.752 ;
     RECT  25.045 28.752 25.836 28.776 ;
     RECT  25.045 28.776 25.884 28.944 ;
     RECT  25.045 28.944 25.836 28.968 ;
     RECT  25.045 28.968 25.884 29.136 ;
     RECT  25.045 29.136 25.836 29.16 ;
     RECT  25.045 29.16 25.884 29.328 ;
     RECT  25.045 29.328 25.836 29.352 ;
     RECT  25.045 29.352 25.884 29.52 ;
     RECT  25.045 29.52 25.836 29.544 ;
     RECT  25.045 29.544 25.884 29.712 ;
     RECT  25.045 29.712 25.836 29.736 ;
     RECT  25.045 29.736 25.884 29.904 ;
     RECT  25.045 29.904 25.836 29.928 ;
     RECT  25.045 29.928 25.884 30.096 ;
     RECT  25.045 30.096 25.836 30.12 ;
     RECT  25.045 30.12 25.884 30.288 ;
     RECT  25.045 30.288 25.836 30.312 ;
     RECT  25.045 30.312 25.884 30.48 ;
     RECT  25.045 30.48 25.836 30.504 ;
     RECT  25.045 30.504 25.884 30.672 ;
     RECT  25.045 30.672 25.836 30.696 ;
     RECT  25.045 30.696 25.884 30.816 ;
     RECT  25.045 30.816 25.836 30.84 ;
     RECT  25.045 30.84 25.884 31.008 ;
     RECT  25.045 31.008 25.836 31.032 ;
     RECT  25.045 31.032 25.884 31.2 ;
     RECT  25.045 31.2 25.836 31.224 ;
     RECT  25.045 31.224 25.884 31.392 ;
     RECT  25.045 31.392 25.836 31.416 ;
     RECT  25.045 31.416 25.884 31.584 ;
     RECT  25.045 31.584 25.836 31.608 ;
     RECT  25.045 31.608 25.884 31.776 ;
     RECT  25.045 31.776 25.836 31.8 ;
     RECT  25.045 31.8 25.884 31.968 ;
     RECT  25.045 31.968 25.836 31.992 ;
     RECT  25.045 31.992 25.884 32.16 ;
     RECT  25.045 32.16 25.836 32.184 ;
     RECT  25.045 32.184 25.884 32.352 ;
     RECT  25.045 32.352 25.836 32.376 ;
     RECT  25.045 32.376 25.884 32.544 ;
     RECT  25.045 32.544 25.836 32.568 ;
     RECT  25.045 32.568 25.884 32.736 ;
     RECT  25.045 32.736 25.836 32.76 ;
     RECT  25.045 32.76 25.884 32.928 ;
     RECT  25.045 32.928 25.836 32.952 ;
     RECT  25.045 32.952 25.884 33.12 ;
     RECT  25.045 33.12 25.836 33.144 ;
     RECT  25.045 33.144 25.884 33.264 ;
     RECT  25.045 33.264 25.836 33.288 ;
     RECT  25.045 33.288 25.884 33.456 ;
     RECT  25.045 33.456 25.836 33.48 ;
     RECT  25.045 33.48 25.884 33.648 ;
     RECT  25.045 33.648 25.836 33.672 ;
     RECT  25.045 33.672 25.884 33.84 ;
     RECT  25.045 33.84 25.836 33.864 ;
     RECT  25.045 33.864 25.884 34.032 ;
     RECT  25.045 34.032 25.836 34.056 ;
     RECT  25.045 34.056 25.884 34.224 ;
     RECT  25.045 34.224 25.836 34.248 ;
     RECT  25.045 34.248 25.884 34.416 ;
     RECT  25.045 34.416 25.836 34.44 ;
     RECT  25.045 34.44 25.884 34.608 ;
     RECT  25.045 34.608 25.836 34.632 ;
     RECT  25.045 34.632 25.884 34.8 ;
     RECT  25.045 34.8 25.836 34.824 ;
     RECT  25.045 34.824 25.884 34.992 ;
     RECT  25.045 34.992 25.836 35.016 ;
     RECT  25.045 35.016 25.884 35.184 ;
     RECT  25.045 35.184 25.836 35.208 ;
     RECT  25.045 35.208 25.884 35.376 ;
     RECT  25.045 35.376 25.836 35.4 ;
     RECT  25.045 35.4 25.884 35.568 ;
     RECT  25.045 35.568 25.836 35.592 ;
     RECT  25.045 35.592 25.884 35.712 ;
     RECT  25.045 35.712 25.836 35.736 ;
     RECT  25.045 35.736 25.884 35.904 ;
     RECT  25.045 35.904 25.836 35.928 ;
     RECT  25.045 35.928 25.884 36.096 ;
     RECT  25.045 36.096 25.836 36.12 ;
     RECT  25.045 36.12 25.884 36.288 ;
     RECT  25.045 36.288 25.836 36.312 ;
     RECT  25.045 36.312 25.884 36.48 ;
     RECT  25.045 36.48 25.836 36.504 ;
     RECT  25.045 36.504 25.884 36.672 ;
     RECT  25.045 36.672 25.836 36.696 ;
     RECT  25.045 36.696 25.884 36.864 ;
     RECT  25.045 36.864 25.836 36.888 ;
     RECT  25.045 36.888 25.884 37.056 ;
     RECT  25.045 37.056 25.836 37.08 ;
     RECT  25.045 37.08 25.884 37.248 ;
     RECT  25.045 37.248 25.836 37.272 ;
     RECT  25.045 37.272 25.884 37.44 ;
     RECT  25.045 37.44 25.836 37.464 ;
     RECT  25.045 37.464 25.884 37.632 ;
     RECT  25.045 37.632 25.836 37.656 ;
     RECT  25.045 37.656 25.884 37.824 ;
     RECT  25.045 37.824 25.836 37.848 ;
     RECT  25.045 37.848 25.884 38.016 ;
     RECT  25.045 38.016 25.836 38.04 ;
     RECT  25.045 38.04 25.884 38.16 ;
     RECT  25.045 38.16 25.836 38.184 ;
     RECT  25.045 38.184 25.884 38.352 ;
     RECT  25.045 38.352 25.836 38.376 ;
     RECT  25.045 38.376 25.884 38.544 ;
     RECT  25.045 38.544 25.836 38.568 ;
     RECT  25.045 38.568 25.884 38.736 ;
     RECT  25.045 38.736 25.836 38.76 ;
     RECT  25.045 38.76 25.884 38.928 ;
     RECT  25.045 38.928 25.836 38.952 ;
     RECT  25.045 38.952 25.884 39.12 ;
     RECT  25.045 39.12 25.836 39.144 ;
     RECT  25.045 39.144 25.884 39.312 ;
     RECT  25.045 39.312 25.836 39.336 ;
     RECT  25.045 39.336 25.884 39.504 ;
     RECT  25.045 39.504 25.836 39.528 ;
     RECT  25.045 39.528 25.884 39.696 ;
     RECT  25.045 39.696 25.836 39.72 ;
     RECT  25.045 39.72 25.884 39.888 ;
     RECT  25.045 39.888 25.836 39.912 ;
     RECT  25.045 39.912 25.884 40.08 ;
     RECT  25.045 40.08 25.836 40.104 ;
     RECT  25.045 40.104 25.884 40.272 ;
     RECT  25.045 40.272 25.836 40.296 ;
     RECT  25.045 40.296 25.884 40.464 ;
     RECT  25.045 40.464 25.836 40.488 ;
     RECT  25.045 40.488 25.884 40.608 ;
     RECT  25.045 40.608 25.836 40.632 ;
     RECT  25.045 40.632 25.884 40.8 ;
     RECT  25.045 40.8 25.836 40.824 ;
     RECT  25.045 40.824 25.884 40.992 ;
     RECT  25.045 40.992 25.836 41.016 ;
     RECT  25.045 41.016 25.884 41.184 ;
     RECT  25.045 41.184 25.836 41.208 ;
     RECT  25.045 41.208 25.884 41.376 ;
     RECT  25.045 41.376 25.836 41.4 ;
     RECT  25.045 41.4 25.884 41.568 ;
     RECT  25.045 41.568 25.836 41.592 ;
     RECT  25.045 41.592 25.884 41.76 ;
     RECT  25.045 41.76 25.836 41.784 ;
     RECT  25.045 41.784 25.884 41.952 ;
     RECT  25.045 41.952 25.836 41.976 ;
     RECT  25.045 41.976 25.884 42.144 ;
     RECT  25.045 42.144 25.836 42.168 ;
     RECT  25.045 42.168 25.884 42.336 ;
     RECT  25.045 42.336 25.836 42.36 ;
     RECT  25.045 42.36 25.884 42.528 ;
     RECT  25.045 42.528 25.836 42.552 ;
     RECT  25.045 42.552 25.884 42.72 ;
     RECT  25.045 42.72 25.836 42.744 ;
     RECT  25.045 42.744 25.884 42.912 ;
     RECT  25.045 42.912 25.836 42.936 ;
     RECT  25.045 42.936 25.884 43.056 ;
     RECT  25.045 43.056 25.836 43.08 ;
     RECT  25.045 43.08 25.884 43.248 ;
     RECT  25.045 43.248 25.836 43.272 ;
     RECT  25.045 43.272 25.884 43.44 ;
     RECT  25.045 43.44 25.836 43.464 ;
     RECT  25.045 43.464 25.884 43.632 ;
     RECT  25.045 43.632 25.836 43.656 ;
     RECT  25.045 43.656 25.884 43.824 ;
     RECT  25.045 43.824 25.836 43.848 ;
     RECT  25.045 43.848 25.884 44.016 ;
     RECT  25.045 44.016 25.836 44.04 ;
     RECT  25.045 44.04 25.884 44.208 ;
     RECT  25.045 44.208 25.836 44.232 ;
     RECT  25.045 44.232 25.884 44.4 ;
     RECT  25.045 44.4 25.836 44.424 ;
     RECT  25.045 44.424 25.884 44.592 ;
     RECT  25.045 44.592 25.836 44.616 ;
     RECT  25.045 44.616 25.884 44.784 ;
     RECT  25.045 44.784 25.836 44.808 ;
     RECT  25.045 44.808 25.884 44.976 ;
     RECT  25.045 44.976 25.836 45 ;
     RECT  25.045 45 25.884 45.168 ;
     RECT  25.045 45.168 25.836 45.192 ;
     RECT  25.045 45.192 25.884 45.36 ;
     RECT  25.045 45.36 25.836 45.384 ;
     RECT  25.045 45.384 25.884 45.552 ;
     RECT  25.045 45.552 25.836 45.576 ;
     RECT  25.045 45.576 25.884 45.696 ;
     RECT  25.045 45.696 25.836 45.72 ;
     RECT  25.045 45.72 25.884 45.888 ;
     RECT  25.045 45.888 25.836 45.912 ;
     RECT  25.045 45.912 25.884 46.08 ;
     RECT  25.045 46.08 25.836 46.104 ;
     RECT  25.045 46.104 25.884 46.272 ;
     RECT  25.045 46.272 25.836 46.296 ;
     RECT  25.045 46.296 25.884 46.464 ;
     RECT  25.045 46.464 25.836 46.488 ;
     RECT  25.045 46.488 25.884 46.656 ;
     RECT  25.045 46.656 25.836 46.68 ;
     RECT  25.045 46.68 25.884 46.848 ;
     RECT  25.045 46.848 25.836 46.872 ;
     RECT  25.045 46.872 25.884 47.04 ;
     RECT  25.045 47.04 25.836 47.064 ;
     RECT  25.045 47.064 25.884 47.232 ;
     RECT  25.045 47.232 25.836 47.256 ;
     RECT  25.045 47.256 25.884 47.424 ;
     RECT  25.045 47.424 25.836 47.448 ;
     RECT  25.045 47.448 25.884 47.616 ;
     RECT  25.045 47.616 25.836 47.64 ;
     RECT  25.045 47.64 25.884 47.808 ;
     RECT  25.045 47.808 25.836 47.832 ;
     RECT  25.045 47.832 25.884 48 ;
     RECT  25.045 48 25.836 48.024 ;
     RECT  25.045 48.024 25.884 48.144 ;
     RECT  25.045 48.144 25.836 48.168 ;
     RECT  25.045 48.168 25.884 48.336 ;
     RECT  25.045 48.336 25.836 48.36 ;
     RECT  25.045 48.36 25.884 48.528 ;
     RECT  25.045 48.528 25.836 48.552 ;
     RECT  25.045 48.552 25.884 48.72 ;
     RECT  25.045 48.72 25.836 48.744 ;
     RECT  25.045 48.744 25.884 48.912 ;
     RECT  25.045 48.912 25.836 48.936 ;
     RECT  25.045 48.936 25.884 49.104 ;
     RECT  25.045 49.104 25.836 49.128 ;
     RECT  25.045 49.128 25.884 49.296 ;
     RECT  25.045 49.296 25.836 49.32 ;
     RECT  25.045 49.32 25.884 49.488 ;
     RECT  25.045 49.488 25.836 49.512 ;
     RECT  25.045 49.512 25.884 49.68 ;
     RECT  25.045 49.68 25.836 49.704 ;
     RECT  25.045 49.704 25.884 49.872 ;
     RECT  25.045 49.872 25.836 49.896 ;
     RECT  25.045 49.896 25.884 50.064 ;
     RECT  25.045 50.064 25.836 50.088 ;
     RECT  25.045 50.088 25.884 50.256 ;
     RECT  25.045 50.256 25.836 50.28 ;
     RECT  25.045 50.28 25.884 50.448 ;
     RECT  25.045 50.448 25.836 50.472 ;
     RECT  25.045 50.472 25.884 50.592 ;
     RECT  25.045 50.592 25.836 50.616 ;
     RECT  25.045 50.616 25.884 50.784 ;
     RECT  25.045 50.784 25.836 50.808 ;
     RECT  25.045 50.808 25.884 50.976 ;
     RECT  25.045 50.976 25.836 51 ;
     RECT  25.045 51 25.884 51.168 ;
     RECT  25.045 51.168 25.836 51.192 ;
     RECT  25.045 51.192 25.884 51.36 ;
     RECT  25.045 51.36 25.836 51.384 ;
     RECT  25.045 51.384 25.884 51.552 ;
     RECT  25.045 51.552 25.836 51.576 ;
     RECT  25.045 51.576 25.884 51.744 ;
     RECT  25.045 51.744 25.836 51.768 ;
     RECT  25.045 51.768 25.884 51.936 ;
     RECT  25.045 51.936 25.836 51.96 ;
     RECT  25.045 51.96 25.884 52.128 ;
     RECT  25.045 52.128 25.836 52.152 ;
     RECT  25.045 52.152 25.884 52.32 ;
     RECT  25.045 52.32 25.836 52.344 ;
     RECT  25.045 52.344 25.884 52.512 ;
     RECT  25.045 52.512 25.836 52.536 ;
     RECT  25.045 52.536 25.884 52.704 ;
     RECT  25.045 52.704 25.836 52.728 ;
     RECT  25.045 52.728 25.884 52.896 ;
     RECT  25.045 52.896 25.836 52.92 ;
     RECT  25.045 52.92 25.884 53.04 ;
     RECT  25.045 53.04 25.836 53.064 ;
     RECT  25.045 53.064 25.884 53.232 ;
     RECT  25.045 53.232 25.836 53.256 ;
     RECT  25.045 53.256 25.884 53.424 ;
     RECT  25.045 53.424 25.836 53.448 ;
     RECT  25.045 53.448 25.884 53.616 ;
     RECT  25.045 53.616 25.836 53.64 ;
     RECT  25.045 53.64 25.884 53.808 ;
     RECT  25.045 53.808 25.836 53.832 ;
     RECT  25.045 53.832 25.884 54 ;
     RECT  25.045 54 25.836 54.024 ;
     RECT  25.045 54.024 25.884 54.192 ;
     RECT  25.045 54.192 25.836 54.216 ;
     RECT  25.045 54.216 25.884 54.384 ;
     RECT  25.045 54.384 25.836 54.408 ;
     RECT  25.045 54.408 25.884 54.576 ;
     RECT  25.045 54.576 25.836 54.6 ;
     RECT  25.045 54.6 25.884 54.768 ;
     RECT  25.045 54.768 25.836 54.792 ;
     RECT  25.045 54.792 25.884 54.96 ;
     RECT  25.045 54.96 25.836 54.984 ;
     RECT  25.045 54.984 25.884 55.152 ;
     RECT  25.045 55.152 25.836 55.176 ;
     RECT  25.045 55.176 25.884 55.344 ;
     RECT  25.045 55.344 25.836 55.368 ;
     RECT  25.045 55.368 25.884 55.488 ;
     RECT  25.045 55.488 25.836 55.512 ;
     RECT  25.045 55.512 25.884 55.68 ;
     RECT  25.045 55.68 25.836 55.704 ;
     RECT  25.045 55.704 25.884 55.872 ;
     RECT  25.045 55.872 25.836 55.896 ;
     RECT  25.045 55.896 25.884 56.064 ;
     RECT  25.045 56.064 25.836 56.088 ;
     RECT  25.045 56.088 25.884 56.256 ;
     RECT  25.045 56.256 25.836 56.28 ;
     RECT  25.045 56.28 25.884 56.448 ;
     RECT  25.045 56.448 25.836 56.472 ;
     RECT  25.045 56.472 25.884 56.64 ;
     RECT  25.045 56.64 25.836 56.664 ;
     RECT  25.045 56.664 25.884 56.832 ;
     RECT  25.045 56.832 25.836 56.856 ;
     RECT  25.045 56.856 25.884 57.024 ;
     RECT  25.045 57.024 25.836 57.048 ;
     RECT  25.045 57.048 25.884 57.216 ;
     RECT  25.045 57.216 25.836 57.24 ;
     RECT  25.045 57.24 25.884 57.408 ;
     RECT  25.045 57.408 25.836 57.432 ;
     RECT  25.045 57.432 25.884 57.6 ;
     RECT  25.045 57.6 25.836 57.624 ;
     RECT  25.045 57.624 25.884 57.792 ;
     RECT  25.045 57.792 25.836 57.816 ;
     RECT  25.045 57.816 25.884 57.984 ;
     RECT  25.045 57.984 25.836 58.008 ;
     RECT  25.045 58.008 25.884 58.128 ;
     RECT  25.045 58.128 25.836 58.152 ;
     RECT  25.045 58.152 25.884 58.32 ;
     RECT  25.045 58.32 25.836 58.344 ;
     RECT  25.045 58.344 25.884 58.512 ;
     RECT  25.045 58.512 25.836 58.536 ;
     RECT  25.045 58.536 25.884 58.704 ;
     RECT  25.045 58.704 25.836 58.728 ;
     RECT  25.045 58.728 25.884 58.896 ;
     RECT  25.045 58.896 25.836 58.92 ;
     RECT  25.045 58.92 25.884 59.088 ;
     RECT  25.045 59.088 25.836 59.112 ;
     RECT  25.045 59.112 25.884 59.28 ;
     RECT  25.045 59.28 25.836 59.304 ;
     RECT  25.045 59.304 25.884 59.472 ;
     RECT  25.045 59.472 25.836 59.496 ;
     RECT  25.045 59.496 25.884 59.664 ;
     RECT  25.045 59.664 25.836 59.688 ;
     RECT  25.045 59.688 25.884 59.856 ;
     RECT  25.045 59.856 25.836 59.88 ;
     RECT  25.045 59.88 25.884 60.048 ;
     RECT  25.045 60.048 25.836 60.072 ;
     RECT  25.045 60.072 25.884 60.24 ;
     RECT  25.045 60.24 25.836 60.264 ;
     RECT  25.045 60.264 25.884 60.432 ;
     RECT  25.045 60.432 25.836 60.456 ;
     RECT  25.045 60.456 25.884 60.576 ;
     RECT  25.045 60.576 25.836 60.6 ;
     RECT  25.045 60.6 25.884 60.768 ;
     RECT  25.045 60.768 25.836 60.792 ;
     RECT  25.045 60.792 25.884 60.96 ;
     RECT  25.045 60.96 25.836 60.984 ;
     RECT  25.045 60.984 25.884 61.152 ;
     RECT  25.045 61.152 25.836 61.176 ;
     RECT  25.045 61.176 25.884 61.344 ;
     RECT  25.045 61.344 25.836 61.368 ;
     RECT  25.045 61.368 25.884 61.536 ;
     RECT  25.045 61.536 25.836 61.56 ;
     RECT  25.045 61.56 25.884 61.728 ;
     RECT  25.045 61.728 25.836 61.752 ;
     RECT  25.045 61.752 25.884 61.92 ;
     RECT  25.045 61.92 25.836 61.944 ;
     RECT  25.045 61.944 25.884 62.112 ;
     RECT  25.045 62.112 25.836 62.136 ;
     RECT  25.045 62.136 25.884 62.304 ;
     RECT  25.045 62.304 25.836 62.328 ;
     RECT  25.045 62.328 25.884 62.496 ;
     RECT  25.045 62.496 25.836 62.52 ;
     RECT  25.045 62.52 25.884 62.688 ;
     RECT  25.045 62.688 25.836 62.712 ;
     RECT  25.045 62.712 25.884 62.88 ;
     RECT  25.045 62.88 25.836 62.904 ;
     RECT  25.045 62.904 25.884 63.024 ;
     RECT  25.045 63.024 25.836 63.048 ;
     RECT  25.045 63.048 25.884 63.216 ;
     RECT  25.045 63.216 25.836 63.24 ;
     RECT  25.045 63.24 25.884 63.408 ;
     RECT  25.045 63.408 25.836 63.432 ;
     RECT  25.045 63.432 25.884 63.6 ;
     RECT  25.045 63.6 25.836 63.624 ;
     RECT  25.045 63.624 25.884 63.792 ;
     RECT  25.045 63.792 25.836 63.816 ;
     RECT  25.045 63.816 25.884 63.984 ;
     RECT  25.045 63.984 25.836 64.008 ;
     RECT  25.045 64.008 25.884 64.176 ;
     RECT  25.045 64.176 25.836 64.2 ;
     RECT  25.045 64.2 25.884 64.368 ;
     RECT  25.045 64.368 25.836 64.392 ;
     RECT  25.045 64.392 25.884 64.56 ;
     RECT  25.045 64.56 25.836 64.584 ;
     RECT  25.045 64.584 25.884 64.752 ;
     RECT  25.045 64.752 25.836 64.776 ;
     RECT  25.045 64.776 25.884 64.944 ;
     RECT  25.045 64.944 25.836 64.968 ;
     RECT  25.045 64.968 25.884 65.136 ;
     RECT  25.045 65.136 25.836 65.16 ;
     RECT  25.045 65.16 25.884 65.328 ;
     RECT  25.045 65.328 25.836 65.352 ;
     RECT  25.045 65.352 25.884 65.472 ;
     RECT  25.045 65.472 25.836 65.496 ;
     RECT  25.045 65.496 25.884 65.664 ;
     RECT  25.045 65.664 25.836 65.688 ;
     RECT  25.045 65.688 25.884 65.856 ;
     RECT  25.045 65.856 25.836 65.88 ;
     RECT  25.045 65.88 25.884 66.048 ;
     RECT  25.045 66.048 25.836 66.072 ;
     RECT  25.045 66.072 25.884 66.24 ;
     RECT  25.045 66.24 25.836 66.264 ;
     RECT  25.045 66.264 25.884 66.432 ;
     RECT  25.045 66.432 25.836 66.456 ;
     RECT  25.045 66.456 25.884 66.624 ;
     RECT  25.045 66.624 25.836 66.648 ;
     RECT  25.045 66.648 25.884 66.816 ;
     RECT  25.045 66.816 25.836 66.84 ;
     RECT  25.045 66.84 25.884 67.008 ;
     RECT  25.045 67.008 25.836 67.032 ;
     RECT  25.045 67.032 25.884 67.2 ;
     RECT  25.045 67.2 25.836 67.224 ;
     RECT  25.045 67.224 25.884 67.392 ;
     RECT  25.045 67.392 25.836 67.416 ;
     RECT  25.045 67.416 25.884 67.584 ;
     RECT  25.045 67.584 25.836 67.608 ;
     RECT  25.045 67.608 25.884 67.776 ;
     RECT  25.045 67.776 25.836 67.8 ;
     RECT  25.045 67.8 25.884 67.92 ;
     RECT  25.045 67.92 25.836 67.944 ;
     RECT  25.045 67.944 25.884 68.112 ;
     RECT  25.045 68.112 25.836 68.136 ;
     RECT  25.045 68.136 25.884 68.304 ;
     RECT  25.045 68.304 25.836 68.328 ;
     RECT  25.045 68.328 25.884 68.496 ;
     RECT  25.045 68.496 25.836 68.52 ;
     RECT  25.045 68.52 25.884 68.688 ;
     RECT  25.045 68.688 25.836 68.712 ;
     RECT  25.045 68.712 25.884 68.88 ;
     RECT  25.045 68.88 25.836 68.904 ;
     RECT  25.045 68.904 25.884 69.072 ;
     RECT  25.045 69.072 25.836 69.096 ;
     RECT  25.045 69.096 25.884 69.264 ;
     RECT  25.045 69.264 25.836 69.288 ;
     RECT  25.045 69.288 25.884 69.456 ;
     RECT  25.045 69.456 25.836 69.48 ;
     RECT  25.045 69.48 25.884 69.648 ;
     RECT  25.045 69.648 25.836 69.672 ;
     RECT  25.045 69.672 25.884 69.84 ;
     RECT  25.045 69.84 25.836 69.864 ;
     RECT  25.045 69.864 25.884 70.032 ;
     RECT  25.045 70.032 25.836 70.056 ;
     RECT  25.045 70.056 25.884 70.224 ;
     RECT  25.045 70.224 25.836 70.248 ;
     RECT  25.045 70.248 25.884 70.416 ;
     RECT  25.045 70.416 25.836 70.44 ;
     RECT  25.045 70.44 25.884 70.56 ;
     RECT  25.045 70.56 25.836 70.584 ;
     RECT  25.045 70.584 25.884 70.752 ;
     RECT  25.045 70.752 25.836 70.776 ;
     RECT  25.045 70.776 25.884 70.944 ;
     RECT  25.045 70.944 25.836 70.968 ;
     RECT  25.045 70.968 25.884 71.136 ;
     RECT  25.045 71.136 25.836 71.16 ;
     RECT  25.045 71.16 25.884 71.328 ;
     RECT  25.045 71.328 25.836 71.352 ;
     RECT  25.045 71.352 25.884 71.52 ;
     RECT  25.045 71.52 25.836 71.544 ;
     RECT  25.045 71.544 25.884 71.712 ;
     RECT  25.045 71.712 25.836 71.736 ;
     RECT  25.045 71.736 25.884 71.904 ;
     RECT  25.045 71.904 25.836 71.928 ;
     RECT  25.045 71.928 25.884 72.096 ;
     RECT  25.045 72.096 25.836 72.12 ;
     RECT  25.045 72.12 25.884 72.288 ;
     RECT  25.045 72.288 25.836 72.312 ;
     RECT  25.045 72.312 25.884 72.48 ;
     RECT  25.045 72.48 25.836 72.504 ;
     RECT  25.045 72.504 25.884 72.672 ;
     RECT  25.045 72.672 25.836 72.696 ;
     RECT  25.045 72.696 25.884 72.864 ;
     RECT  25.045 72.864 25.836 72.888 ;
     RECT  25.045 72.888 25.884 73.008 ;
     RECT  25.045 73.008 25.836 73.032 ;
     RECT  25.045 73.032 25.884 73.2 ;
     RECT  25.045 73.2 25.836 73.224 ;
     RECT  25.045 73.224 25.884 73.392 ;
     RECT  25.045 73.392 25.836 73.416 ;
     RECT  25.045 73.416 25.884 73.584 ;
     RECT  25.045 73.584 25.836 73.608 ;
     RECT  25.045 73.608 25.884 73.776 ;
     RECT  25.045 73.776 25.836 73.8 ;
     RECT  25.045 73.8 25.884 73.968 ;
     RECT  25.045 73.968 25.836 73.992 ;
     RECT  25.045 73.992 25.884 74.16 ;
     RECT  25.045 74.16 25.836 74.184 ;
     RECT  25.045 74.184 25.884 74.352 ;
     RECT  25.045 74.352 25.836 74.376 ;
     RECT  25.045 74.376 25.884 74.544 ;
     RECT  25.045 74.544 25.836 74.568 ;
     RECT  25.045 74.568 25.884 74.736 ;
     RECT  25.045 74.736 25.836 74.76 ;
     RECT  25.045 74.76 25.884 74.928 ;
     RECT  25.045 74.928 25.836 74.952 ;
     RECT  25.045 74.952 25.884 75.12 ;
     RECT  25.045 75.12 25.836 75.144 ;
     RECT  25.045 75.144 25.884 75.312 ;
     RECT  25.045 75.312 25.836 75.336 ;
     RECT  25.045 75.336 25.884 75.456 ;
     RECT  25.045 75.456 25.836 75.48 ;
     RECT  25.045 75.48 25.884 75.648 ;
     RECT  25.045 75.648 25.836 75.672 ;
     RECT  25.045 75.672 25.884 75.84 ;
     RECT  25.045 75.84 25.836 75.864 ;
     RECT  25.045 75.864 25.884 76.032 ;
     RECT  25.045 76.032 25.836 76.056 ;
     RECT  25.045 76.056 25.884 76.224 ;
     RECT  25.045 76.224 25.836 76.248 ;
     RECT  25.045 76.248 25.884 76.416 ;
     RECT  25.045 76.416 25.836 76.44 ;
     RECT  25.045 76.44 25.884 76.608 ;
     RECT  25.045 76.608 25.836 76.632 ;
     RECT  25.045 76.632 25.884 76.8 ;
     RECT  25.045 76.8 25.836 76.824 ;
     RECT  25.045 76.824 25.884 76.992 ;
     RECT  25.045 76.992 25.836 77.016 ;
     RECT  25.045 77.016 25.884 77.184 ;
     RECT  25.045 77.184 25.836 77.208 ;
     RECT  25.045 77.208 25.884 77.376 ;
     RECT  25.045 77.376 25.836 77.4 ;
     RECT  25.045 77.4 25.884 77.568 ;
     RECT  25.045 77.568 25.836 77.592 ;
     RECT  25.045 77.592 25.884 77.76 ;
     RECT  25.045 77.76 25.836 77.784 ;
     RECT  25.045 77.784 25.884 77.904 ;
     RECT  25.045 77.904 25.836 77.928 ;
     RECT  25.045 77.928 25.884 78.096 ;
     RECT  25.045 78.096 25.836 78.12 ;
     RECT  25.045 78.12 25.884 78.288 ;
     RECT  25.045 78.288 25.836 78.312 ;
     RECT  25.045 78.312 25.884 78.48 ;
     RECT  25.045 78.48 25.836 78.504 ;
     RECT  25.045 78.504 25.884 78.672 ;
     RECT  25.045 78.672 25.836 78.696 ;
     RECT  25.045 78.696 25.884 78.864 ;
     RECT  25.045 78.864 25.836 78.888 ;
     RECT  25.045 78.888 25.884 79.056 ;
     RECT  25.045 79.056 25.836 79.08 ;
     RECT  25.045 79.08 25.884 79.248 ;
     RECT  25.045 79.248 25.836 79.272 ;
     RECT  25.045 79.272 25.884 79.44 ;
     RECT  25.045 79.44 25.836 79.464 ;
     RECT  25.045 79.464 25.884 79.632 ;
     RECT  25.045 79.632 25.836 79.656 ;
     RECT  25.045 79.656 25.884 79.824 ;
     RECT  25.045 79.824 25.836 79.848 ;
     RECT  25.045 79.848 25.884 80.016 ;
     RECT  25.045 80.016 25.836 80.04 ;
     RECT  25.045 80.04 25.884 80.208 ;
     RECT  25.045 80.208 25.836 80.232 ;
     RECT  25.045 80.232 25.884 80.352 ;
     RECT  25.045 80.352 25.836 80.376 ;
     RECT  25.045 80.376 25.884 80.544 ;
     RECT  25.045 80.544 25.836 80.568 ;
     RECT  25.045 80.568 25.884 80.736 ;
     RECT  25.045 80.736 25.836 80.76 ;
     RECT  25.045 80.76 25.884 80.928 ;
     RECT  25.045 80.928 25.836 80.952 ;
     RECT  25.045 80.952 25.884 81.12 ;
     RECT  25.045 81.12 25.836 81.144 ;
     RECT  25.045 81.144 25.884 81.312 ;
     RECT  25.045 81.312 25.836 81.336 ;
     RECT  25.045 81.336 25.884 81.504 ;
     RECT  25.045 81.504 25.836 81.528 ;
     RECT  25.045 81.528 25.884 81.696 ;
     RECT  25.045 81.696 25.836 81.72 ;
     RECT  25.045 81.72 25.884 81.888 ;
     RECT  25.045 81.888 25.836 81.912 ;
     RECT  25.045 81.912 25.884 82.08 ;
     RECT  25.045 82.08 25.836 82.104 ;
     RECT  25.045 82.104 25.884 82.272 ;
     RECT  25.045 82.272 25.836 82.296 ;
     RECT  25.045 82.296 25.884 82.464 ;
     RECT  25.045 82.464 25.836 82.488 ;
     RECT  25.045 82.488 25.884 82.656 ;
     RECT  25.045 82.656 25.836 82.68 ;
     RECT  25.045 82.68 25.884 82.8 ;
     RECT  25.045 82.8 25.836 82.824 ;
     RECT  25.045 82.824 25.884 82.992 ;
     RECT  25.045 82.992 25.836 83.016 ;
     RECT  25.045 83.016 25.884 83.184 ;
     RECT  25.045 83.184 25.836 83.208 ;
     RECT  25.045 83.208 25.884 83.376 ;
     RECT  25.045 83.376 25.836 83.4 ;
     RECT  25.045 83.4 25.884 83.568 ;
     RECT  25.045 83.568 25.836 83.592 ;
     RECT  25.045 83.592 25.884 83.76 ;
     RECT  25.045 83.76 25.836 83.784 ;
     RECT  25.045 83.784 25.884 83.952 ;
     RECT  25.045 83.952 25.836 83.976 ;
     RECT  25.045 83.976 25.884 84.144 ;
     RECT  25.045 84.144 25.836 84.168 ;
     RECT  25.045 84.168 25.884 84.336 ;
     RECT  25.045 84.336 25.836 84.36 ;
     RECT  25.045 84.36 25.884 84.528 ;
     RECT  25.045 84.528 25.836 84.552 ;
     RECT  25.045 84.552 25.884 84.72 ;
     RECT  25.045 84.72 25.836 84.744 ;
     RECT  25.045 84.744 25.884 84.912 ;
     RECT  25.045 84.912 25.836 84.936 ;
     RECT  25.045 84.936 25.884 85.104 ;
     RECT  25.045 85.104 25.836 85.128 ;
     RECT  25.045 85.128 25.884 85.296 ;
     RECT  25.045 85.296 25.836 85.32 ;
     RECT  25.045 85.32 25.884 85.44 ;
     RECT  25.045 85.44 25.836 85.464 ;
     RECT  25.045 85.464 25.884 85.632 ;
     RECT  25.045 85.632 25.836 85.656 ;
     RECT  25.045 85.656 25.884 85.824 ;
     RECT  25.045 85.824 25.836 85.848 ;
     RECT  25.045 85.848 25.884 86.016 ;
     RECT  25.045 86.016 25.836 86.04 ;
     RECT  25.045 86.04 25.884 86.208 ;
     RECT  25.045 86.208 25.836 86.232 ;
     RECT  25.045 86.232 25.884 86.4 ;
     RECT  25.045 86.4 25.836 86.424 ;
     RECT  25.045 86.424 25.884 86.592 ;
     RECT  25.045 86.592 25.836 86.616 ;
     RECT  25.045 86.616 25.884 86.784 ;
     RECT  25.045 86.784 25.836 86.808 ;
     RECT  25.045 86.808 25.884 86.976 ;
     RECT  25.045 86.976 25.836 87 ;
     RECT  25.045 87 25.884 87.168 ;
     RECT  25.045 87.168 25.836 87.192 ;
     RECT  25.045 87.192 25.884 87.36 ;
     RECT  25.045 87.36 25.836 87.384 ;
     RECT  25.045 87.384 25.884 87.552 ;
     RECT  25.045 87.552 25.836 87.576 ;
     RECT  25.045 87.576 25.884 87.744 ;
     RECT  25.045 87.744 25.836 87.768 ;
     RECT  25.045 87.768 25.884 87.888 ;
     RECT  25.045 87.888 25.836 87.912 ;
     RECT  25.045 87.912 25.884 88.08 ;
     RECT  25.045 88.08 25.836 88.104 ;
     RECT  25.045 88.104 25.884 88.272 ;
     RECT  25.045 88.272 25.836 88.296 ;
     RECT  25.045 88.296 25.884 88.464 ;
     RECT  25.045 88.464 25.836 88.488 ;
     RECT  25.045 88.488 25.884 88.656 ;
     RECT  25.045 88.656 25.836 88.68 ;
     RECT  25.045 88.68 25.884 88.848 ;
     RECT  25.045 88.848 25.836 88.872 ;
     RECT  25.045 88.872 25.884 89.04 ;
     RECT  25.045 89.04 25.836 89.064 ;
     RECT  25.045 89.064 25.884 89.232 ;
     RECT  25.045 89.232 25.836 89.256 ;
     RECT  25.045 89.256 25.884 89.424 ;
     RECT  25.045 89.424 25.836 89.448 ;
     RECT  25.045 89.448 25.884 89.616 ;
     RECT  25.045 89.616 25.836 89.64 ;
     RECT  25.045 89.64 25.884 89.808 ;
     RECT  25.045 89.808 25.836 89.832 ;
     RECT  25.045 89.832 25.884 90 ;
     RECT  25.045 90 25.836 90.024 ;
     RECT  25.045 90.024 25.884 90.192 ;
     RECT  25.045 90.192 25.836 90.216 ;
     RECT  25.045 90.216 25.884 90.336 ;
     RECT  25.045 90.336 25.836 90.36 ;
     RECT  25.045 90.36 25.884 90.528 ;
     RECT  25.045 90.528 25.836 90.552 ;
     RECT  25.045 90.552 25.884 90.72 ;
     RECT  25.045 90.72 25.836 90.744 ;
     RECT  25.045 90.744 25.884 90.912 ;
     RECT  25.045 90.912 25.836 90.936 ;
     RECT  25.045 90.936 25.884 91.104 ;
     RECT  25.045 91.104 25.836 91.128 ;
     RECT  25.045 91.128 25.884 91.296 ;
     RECT  25.045 91.296 25.836 91.32 ;
     RECT  25.045 91.32 25.884 91.488 ;
     RECT  25.045 91.488 25.836 91.512 ;
     RECT  25.045 91.512 25.884 91.68 ;
     RECT  25.045 91.68 25.836 91.704 ;
     RECT  25.045 91.704 25.884 91.872 ;
     RECT  25.045 91.872 25.836 91.896 ;
     RECT  25.045 91.896 25.884 92.064 ;
     RECT  25.045 92.064 25.836 92.088 ;
     RECT  25.045 92.088 25.884 92.256 ;
     RECT  25.045 92.256 25.836 92.28 ;
     RECT  25.045 92.28 25.884 92.448 ;
     RECT  25.045 92.448 25.836 92.472 ;
     RECT  25.045 92.472 25.884 92.64 ;
     RECT  25.045 92.64 25.836 92.664 ;
     RECT  25.045 92.664 25.884 92.784 ;
     RECT  25.045 92.784 25.836 92.808 ;
     RECT  25.045 92.808 25.884 92.976 ;
     RECT  25.045 92.976 25.836 93 ;
     RECT  25.045 93 25.884 93.168 ;
     RECT  25.045 93.168 25.836 93.192 ;
     RECT  25.045 93.192 25.884 93.36 ;
     RECT  25.045 93.36 25.836 93.384 ;
     RECT  25.045 93.384 25.884 93.552 ;
     RECT  25.045 93.552 25.836 93.576 ;
     RECT  25.045 93.576 25.884 93.744 ;
     RECT  25.045 93.744 25.836 93.768 ;
     RECT  25.045 93.768 25.884 93.936 ;
     RECT  25.045 93.936 25.836 93.96 ;
     RECT  25.045 93.96 25.884 94.128 ;
     RECT  25.045 94.128 25.836 94.152 ;
     RECT  25.045 94.152 25.884 94.32 ;
     RECT  25.045 94.32 25.836 94.344 ;
     RECT  25.045 94.344 25.884 94.512 ;
     RECT  25.045 94.512 25.836 94.536 ;
     RECT  25.045 94.536 25.884 94.704 ;
     RECT  25.045 94.704 25.836 94.728 ;
     RECT  25.045 94.728 25.884 94.896 ;
     RECT  25.045 94.896 25.836 94.92 ;
     RECT  25.045 94.92 25.884 95.088 ;
     RECT  25.045 95.088 25.836 95.112 ;
     RECT  25.045 95.112 25.884 95.232 ;
     RECT  25.045 95.232 25.836 95.256 ;
     RECT  25.045 95.256 25.884 95.424 ;
     RECT  25.045 95.424 25.836 95.448 ;
     RECT  25.045 95.448 25.884 95.616 ;
     RECT  25.045 95.616 25.836 95.64 ;
     RECT  25.045 95.64 25.884 95.808 ;
     RECT  25.045 95.808 25.836 95.832 ;
     RECT  25.045 95.832 25.884 96 ;
     RECT  25.045 96 25.836 96.024 ;
     RECT  25.045 96.024 25.884 96.192 ;
     RECT  25.045 96.192 25.836 96.216 ;
     RECT  25.045 96.216 25.884 96.384 ;
     RECT  25.045 96.384 25.836 96.408 ;
     RECT  25.045 96.408 25.884 96.576 ;
     RECT  25.045 96.576 25.836 96.6 ;
     RECT  25.045 96.6 25.884 96.768 ;
     RECT  25.045 96.768 25.836 96.792 ;
     RECT  25.045 96.792 25.884 96.96 ;
     RECT  25.045 96.96 25.836 96.984 ;
     RECT  25.045 96.984 25.884 97.152 ;
     RECT  25.045 97.152 25.836 97.176 ;
     RECT  25.045 97.176 25.884 97.344 ;
     RECT  25.045 97.344 25.836 97.368 ;
     RECT  25.045 97.368 25.884 97.536 ;
     RECT  25.045 97.536 25.836 97.56 ;
     RECT  25.045 97.56 25.884 97.728 ;
     RECT  25.045 97.728 25.836 97.752 ;
     RECT  25.045 97.752 25.884 97.872 ;
     RECT  25.045 97.872 25.836 97.896 ;
     RECT  25.045 97.896 25.884 98.064 ;
     RECT  25.045 98.064 25.836 98.088 ;
     RECT  25.045 98.088 25.884 98.256 ;
     RECT  25.045 98.256 25.836 98.28 ;
     RECT  25.045 98.28 25.884 98.448 ;
     RECT  25.045 98.448 25.836 98.472 ;
     RECT  25.045 98.472 25.884 98.64 ;
     RECT  25.045 98.64 25.836 98.664 ;
     RECT  25.045 98.664 25.884 98.832 ;
     RECT  25.045 98.832 25.836 98.856 ;
     RECT  25.045 98.856 25.884 99.264 ;
     RECT  25.045 99.264 25.836 99.288 ;
     RECT  25.045 99.288 25.884 99.504 ;
     RECT  25.045 99.504 25.836 99.528 ;
     RECT  25.045 99.528 25.884 99.744 ;
     RECT  25.045 99.744 25.836 99.768 ;
     RECT  25.045 99.768 25.884 99.984 ;
     RECT  25.045 99.984 25.836 100.008 ;
     RECT  25.045 100.008 25.884 100.272 ;
     RECT  25.045 100.272 25.836 100.296 ;
     RECT  25.045 100.296 25.884 100.512 ;
     RECT  25.045 100.512 25.836 100.536 ;
     RECT  25.045 100.536 25.884 100.752 ;
     RECT  25.045 100.752 25.836 100.776 ;
     RECT  25.045 100.776 25.884 100.992 ;
     RECT  25.045 100.992 25.836 101.016 ;
     RECT  25.045 101.016 25.884 101.232 ;
     RECT  25.045 101.232 25.836 101.256 ;
     RECT  25.045 101.256 25.884 101.52 ;
     RECT  25.045 101.52 25.836 101.544 ;
     RECT  25.045 101.544 25.884 101.76 ;
     RECT  25.045 101.76 25.836 101.784 ;
     RECT  25.045 101.784 25.884 102 ;
     RECT  25.045 102 25.836 102.024 ;
     RECT  25.045 102.024 25.884 102.24 ;
     RECT  25.045 102.24 25.836 102.264 ;
     RECT  25.045 102.264 25.884 102.48 ;
     RECT  25.045 102.48 25.836 102.504 ;
     RECT  25.045 102.504 25.884 102.768 ;
     RECT  25.045 102.768 25.836 102.792 ;
     RECT  25.045 102.792 25.884 103.008 ;
     RECT  25.045 103.008 25.836 103.032 ;
    LAYER M5 ;
     RECT  14.016 2.005 14.04 2.137 ;
     RECT  2.4 2.137 2.52 2.151 ;
     RECT  7.8 2.137 7.92 2.151 ;
     RECT  18.6 2.137 18.72 2.151 ;
     RECT  7.8 2.151 8.112 2.245 ;
     RECT  13.2 2.137 14.04 2.245 ;
     RECT  7.68 2.245 8.112 2.389 ;
     RECT  18.6 2.151 18.912 2.437 ;
     RECT  15.216 2.533 15.24 2.581 ;
     RECT  13.2 2.245 14.088 2.629 ;
     RECT  15.216 2.581 15.384 2.629 ;
     RECT  10.56 2.245 10.584 2.677 ;
     RECT  10.56 2.677 10.68 2.725 ;
     RECT  4.176 2.197 4.2 2.821 ;
     RECT  17.616 2.437 18.912 2.869 ;
     RECT  19.968 2.821 19.992 2.869 ;
     RECT  7.68 2.389 9.096 2.917 ;
     RECT  17.616 2.869 19.992 2.917 ;
     RECT  13.2 2.629 15.384 3.107 ;
     RECT  3.936 2.821 4.2 3.155 ;
     RECT  13.2 3.107 15.336 3.157 ;
     RECT  10.56 2.725 11.208 3.205 ;
     RECT  13.008 3.157 15.336 3.253 ;
     RECT  3.936 3.155 3.96 3.299 ;
     RECT  10.56 3.205 11.4 3.443 ;
     RECT  7.68 2.917 9.384 3.539 ;
     RECT  12.816 3.253 15.336 3.541 ;
     RECT  16.752 2.917 19.992 3.685 ;
     RECT  16.656 3.685 19.992 3.923 ;
     RECT  16.752 3.923 19.992 4.019 ;
     RECT  7.68 3.539 9.144 4.213 ;
     RECT  11.04 3.443 11.4 4.501 ;
     RECT  12.48 3.541 15.336 4.501 ;
     RECT  11.04 4.501 15.336 4.789 ;
     RECT  10.416 4.789 15.336 4.885 ;
     RECT  6.192 4.597 6.216 4.933 ;
     RECT  7.536 4.213 9.144 5.077 ;
     RECT  10.416 4.885 15.672 5.077 ;
     RECT  16.752 4.019 19.896 5.077 ;
     RECT  7.536 5.077 9.192 5.317 ;
     RECT  5.376 4.933 6.216 5.461 ;
     RECT  4.992 5.461 6.216 5.557 ;
     RECT  7.536 5.317 9.288 5.557 ;
     RECT  4.992 5.557 9.288 5.845 ;
     RECT  10.416 5.077 19.896 5.845 ;
     RECT  3.984 6.133 4.008 6.805 ;
     RECT  4.992 5.845 19.896 6.805 ;
     RECT  2.4 2.151 2.712 8.341 ;
     RECT  3.984 6.805 19.896 8.341 ;
     RECT  2.4 8.341 19.896 8.437 ;
     RECT  2.4 8.437 19.992 8.533 ;
     RECT  2.4 8.533 20.232 8.773 ;
     RECT  2.4 8.773 20.808 10.117 ;
     RECT  2.4 10.117 21.672 11.173 ;
     RECT  2.256 11.173 21.672 11.749 ;
     RECT  2.208 11.749 21.672 16.645 ;
     RECT  2.208 16.645 22.296 17.893 ;
     RECT  2.208 17.893 22.824 20.437 ;
     RECT  2.208 20.437 23.064 22.165 ;
     RECT  2.208 22.165 23.4 28.165 ;
     RECT  2.208 28.165 23.448 28.261 ;
     RECT  2.208 28.261 23.544 31.475 ;
     RECT  2.208 31.475 4.392 31.957 ;
     RECT  1.68 31.957 4.392 32.821 ;
     RECT  1.632 32.821 4.392 33.253 ;
     RECT  5.376 31.475 23.544 33.253 ;
     RECT  1.632 33.253 23.544 36.757 ;
     RECT  1.632 36.757 23.592 38.149 ;
     RECT  1.632 38.149 23.928 39.731 ;
     RECT  1.632 39.731 23.352 42.227 ;
     RECT  1.632 42.227 22.968 44.101 ;
     RECT  1.632 44.101 23.256 45.635 ;
     RECT  1.632 45.635 22.824 47.603 ;
     RECT  1.632 47.603 22.68 48.179 ;
     RECT  1.632 48.179 22.296 53.893 ;
     RECT  1.632 53.893 22.344 57.397 ;
     RECT  1.632 57.397 22.392 61.477 ;
     RECT  1.632 61.477 22.488 69.445 ;
     RECT  1.632 69.445 22.824 69.587 ;
     RECT  1.632 69.587 22.488 70.163 ;
     RECT  1.632 70.163 22.44 73.811 ;
     RECT  1.632 73.811 22.392 87.923 ;
     RECT  1.632 87.923 22.248 92.915 ;
     RECT  1.632 92.915 10.536 93.011 ;
     RECT  12.192 92.915 22.248 93.779 ;
     RECT  12.528 93.779 22.248 94.115 ;
     RECT  20.88 94.115 22.248 94.163 ;
     RECT  12.528 94.115 19.656 94.211 ;
     RECT  1.632 93.011 10.344 94.883 ;
     RECT  12.912 94.211 19.656 94.979 ;
     RECT  13.104 94.979 19.656 95.603 ;
     RECT  15.6 95.603 19.656 95.795 ;
     RECT  15.6 95.795 18.912 95.891 ;
     RECT  21.12 94.163 22.248 95.941 ;
     RECT  15.648 95.891 18.912 96.035 ;
     RECT  13.104 95.603 14.136 96.131 ;
     RECT  13.2 96.131 14.136 96.179 ;
     RECT  6.912 94.883 10.344 96.229 ;
     RECT  6.864 96.229 10.344 96.371 ;
     RECT  16.56 96.035 18.912 96.419 ;
     RECT  20.784 95.941 22.248 96.803 ;
     RECT  6.864 96.371 10.152 97.139 ;
     RECT  6.912 97.139 10.152 97.235 ;
     RECT  23.136 97.141 23.16 97.861 ;
     RECT  20.784 96.803 21.912 98.099 ;
     RECT  11.232 96.757 11.256 98.291 ;
     RECT  13.2 96.179 13.704 98.581 ;
     RECT  7.68 97.235 10.152 98.627 ;
     RECT  1.632 94.883 5.544 98.675 ;
     RECT  17.76 96.419 18.912 98.675 ;
     RECT  16.56 96.419 16.584 99.061 ;
     RECT  16.32 99.061 16.584 99.107 ;
     RECT  23.136 97.861 23.352 99.203 ;
     RECT  20.784 98.099 21.768 99.251 ;
     RECT  6.528 99.109 6.552 99.589 ;
     RECT  7.68 98.627 10.104 99.589 ;
     RECT  13.2 98.581 13.8 99.685 ;
     RECT  14.832 97.333 14.856 99.685 ;
     RECT  16.32 99.107 16.344 100.211 ;
     RECT  1.632 98.675 5.304 100.355 ;
     RECT  6.528 99.589 10.104 100.355 ;
     RECT  23.904 99.493 23.928 100.355 ;
     RECT  13.2 99.685 14.856 100.357 ;
     RECT  7.8 100.355 10.104 100.403 ;
     RECT  6.528 100.355 6.552 100.547 ;
     RECT  10.08 100.403 10.104 100.883 ;
     RECT  13.104 100.357 14.856 100.885 ;
     RECT  13.104 100.885 15.48 100.931 ;
     RECT  1.632 100.355 4.872 101.171 ;
     RECT  18.6 98.675 18.912 101.413 ;
     RECT  14.832 100.931 15.48 101.555 ;
     RECT  20.784 99.251 21.576 101.891 ;
     RECT  18.6 101.413 19.608 101.941 ;
     RECT  14.832 101.555 14.856 102.083 ;
     RECT  18 101.941 19.608 102.083 ;
     RECT  1.632 101.171 3.336 102.467 ;
     RECT  4.416 101.171 4.872 102.659 ;
     RECT  13.104 100.931 13.512 103.189 ;
     RECT  18 102.083 18.912 103.189 ;
     RECT  21.552 101.891 21.576 103.189 ;
     RECT  1.68 102.467 3.336 103.235 ;
     RECT  7.8 100.403 8.112 103.237 ;
     RECT  10.224 103.189 21.576 103.237 ;
     RECT  2.256 103.235 3.336 103.283 ;
     RECT  2.4 103.283 3.336 103.285 ;
     RECT  4.848 102.659 4.872 103.285 ;
     RECT  7.8 103.237 21.576 103.333 ;
     RECT  2.4 103.285 3.624 103.703 ;
     RECT  2.592 103.703 3.624 103.717 ;
     RECT  4.848 103.285 5.4 103.717 ;
     RECT  7.488 103.333 21.576 103.717 ;
     RECT  22.56 103.237 22.584 103.717 ;
     RECT  2.592 103.717 23.064 105.756 ;
     RECT  2.616 105.756 2.88 105.808 ;
     RECT  2.904 105.756 3.12 105.808 ;
     RECT  3.144 105.756 3.36 105.808 ;
     RECT  3.384 105.756 3.6 105.808 ;
     RECT  3.624 105.756 3.84 105.808 ;
     RECT  3.864 105.756 4.128 105.808 ;
     RECT  4.152 105.756 4.368 105.808 ;
     RECT  4.392 105.756 4.608 105.808 ;
     RECT  4.632 105.756 4.848 105.808 ;
     RECT  4.872 105.756 5.136 105.808 ;
     RECT  5.16 105.756 5.376 105.808 ;
     RECT  5.4 105.756 5.616 105.808 ;
     RECT  5.64 105.756 5.856 105.808 ;
     RECT  5.88 105.756 6.096 105.808 ;
     RECT  6.12 105.756 6.384 105.808 ;
     RECT  6.408 105.756 6.816 105.808 ;
     RECT  6.84 105.756 7.008 105.808 ;
     RECT  7.032 105.756 7.248 105.808 ;
     RECT  7.272 105.756 7.488 105.808 ;
     RECT  7.512 105.756 7.728 105.808 ;
     RECT  7.752 105.756 7.92 105.808 ;
     RECT  7.944 105.756 8.16 105.808 ;
     RECT  8.184 105.756 8.4 105.808 ;
     RECT  8.424 105.756 8.64 105.808 ;
     RECT  8.664 105.756 8.832 105.808 ;
     RECT  8.856 105.756 9.072 105.808 ;
     RECT  9.096 105.756 9.312 105.808 ;
     RECT  9.336 105.756 9.504 105.808 ;
     RECT  9.528 105.756 9.744 105.808 ;
     RECT  9.768 105.756 9.984 105.808 ;
     RECT  10.008 105.756 10.224 105.808 ;
     RECT  10.248 105.756 10.416 105.808 ;
     RECT  10.44 105.756 10.656 105.808 ;
     RECT  10.68 105.756 10.896 105.808 ;
     RECT  10.92 105.756 11.136 105.808 ;
     RECT  11.16 105.756 11.328 105.808 ;
     RECT  11.352 105.756 11.568 105.808 ;
     RECT  11.592 105.756 11.808 105.808 ;
     RECT  11.832 105.756 12 105.808 ;
     RECT  12.024 105.756 12.24 105.808 ;
     RECT  12.264 105.756 12.48 105.808 ;
     RECT  12.504 105.756 12.72 105.808 ;
     RECT  12.744 105.756 12.912 105.808 ;
     RECT  12.936 105.756 13.152 105.808 ;
     RECT  13.176 105.756 13.392 105.808 ;
     RECT  13.416 105.756 13.632 105.808 ;
     RECT  13.656 105.756 13.824 105.808 ;
     RECT  13.848 105.756 14.064 105.808 ;
     RECT  14.088 105.756 14.304 105.808 ;
     RECT  14.328 105.756 14.496 105.808 ;
     RECT  14.52 105.756 14.736 105.808 ;
     RECT  14.76 105.756 14.976 105.808 ;
     RECT  15 105.756 15.216 105.808 ;
     RECT  15.24 105.756 15.408 105.808 ;
     RECT  15.432 105.756 15.648 105.808 ;
     RECT  15.672 105.756 15.888 105.808 ;
     RECT  15.912 105.756 16.08 105.808 ;
     RECT  16.104 105.756 16.32 105.808 ;
     RECT  16.344 105.756 16.56 105.808 ;
     RECT  16.584 105.756 16.8 105.808 ;
     RECT  16.824 105.756 16.992 105.808 ;
     RECT  17.016 105.756 17.232 105.808 ;
     RECT  17.256 105.756 17.472 105.808 ;
     RECT  17.496 105.756 17.712 105.808 ;
     RECT  17.736 105.756 17.904 105.808 ;
     RECT  17.928 105.756 18.144 105.808 ;
     RECT  18.168 105.756 18.384 105.808 ;
     RECT  18.408 105.756 18.576 105.808 ;
     RECT  18.6 105.756 18.816 105.808 ;
     RECT  18.84 105.756 19.056 105.808 ;
     RECT  19.08 105.756 19.296 105.808 ;
     RECT  19.32 105.756 19.488 105.808 ;
     RECT  19.512 105.756 19.728 105.808 ;
     RECT  19.752 105.756 19.968 105.808 ;
     RECT  19.992 105.756 20.208 105.808 ;
     RECT  20.232 105.756 20.4 105.808 ;
     RECT  20.424 105.756 20.64 105.808 ;
     RECT  20.664 105.756 20.88 105.808 ;
     RECT  20.904 105.756 21.072 105.808 ;
     RECT  21.096 105.756 21.552 105.808 ;
     RECT  21.576 105.756 22.08 105.808 ;
     RECT  22.104 105.756 22.56 105.808 ;
     RECT  22.584 105.756 23.04 105.808 ;
     RECT  2.712 2.197 4.176 2.821 ;
     RECT  9.096 2.389 10.56 2.917 ;
     RECT  14.088 2.533 15.216 2.629 ;
     RECT  2.712 2.821 3.936 3.299 ;
     RECT  18.912 2.821 19.968 2.869 ;
     RECT  9.384 2.917 10.56 3.443 ;
     RECT  15.384 2.917 16.752 3.107 ;
     RECT  15.336 3.107 16.752 3.685 ;
     RECT  11.4 3.253 12.816 3.541 ;
     RECT  9.384 3.443 11.04 3.539 ;
     RECT  9.144 3.539 11.04 4.789 ;
     RECT  11.4 3.541 12.48 4.501 ;
     RECT  15.336 3.685 16.656 3.923 ;
     RECT  15.336 3.923 16.752 4.885 ;
     RECT  6.216 4.597 7.536 5.557 ;
     RECT  9.144 4.789 10.416 5.077 ;
     RECT  15.672 4.885 16.752 5.077 ;
     RECT  9.192 5.077 10.416 5.317 ;
     RECT  9.288 5.317 10.416 5.845 ;
     RECT  2.712 6.133 3.984 8.341 ;
     RECT  4.008 6.133 4.992 6.805 ;
     RECT  4.392 31.475 5.376 33.253 ;
     RECT  19.656 94.115 20.88 94.163 ;
     RECT  19.656 94.163 21.12 95.795 ;
     RECT  5.544 94.883 6.912 96.229 ;
     RECT  14.136 95.603 15.6 95.891 ;
     RECT  20.784 95.795 21.12 95.941 ;
     RECT  14.136 95.891 15.648 96.035 ;
     RECT  14.136 96.035 14.856 96.179 ;
     RECT  13.704 96.179 14.856 97.333 ;
     RECT  5.544 96.229 6.864 97.139 ;
     RECT  10.152 96.371 10.344 96.757 ;
     RECT  16.584 96.419 17.76 98.675 ;
     RECT  10.152 96.757 11.232 98.291 ;
     RECT  21.912 96.803 22.248 97.141 ;
     RECT  5.544 97.139 6.912 97.235 ;
     RECT  21.912 97.141 23.136 98.099 ;
     RECT  13.704 97.333 14.832 98.581 ;
     RECT  21.768 98.099 23.136 99.203 ;
     RECT  13.8 98.581 14.832 99.685 ;
     RECT  5.304 98.675 5.544 99.109 ;
     RECT  14.856 99.061 16.32 100.211 ;
     RECT  5.304 99.109 6.528 100.355 ;
     RECT  6.552 99.109 7.68 99.589 ;
     RECT  14.856 100.211 15.48 100.885 ;
     RECT  6.552 100.355 7.8 100.547 ;
     RECT  13.512 100.931 14.832 102.083 ;
     RECT  3.336 101.171 4.416 102.659 ;
     RECT  19.608 101.413 20.784 101.891 ;
     RECT  19.608 101.891 21.552 102.083 ;
     RECT  13.512 102.083 14.856 103.189 ;
     RECT  18.912 102.083 21.552 103.189 ;
     RECT  3.336 102.659 4.848 103.285 ;
     RECT  21.576 103.237 22.56 103.717 ;
     RECT  3.624 103.285 4.848 103.717 ;
  END
END ot_hgi_coll_qso_q3_b32
END LIBRARY
